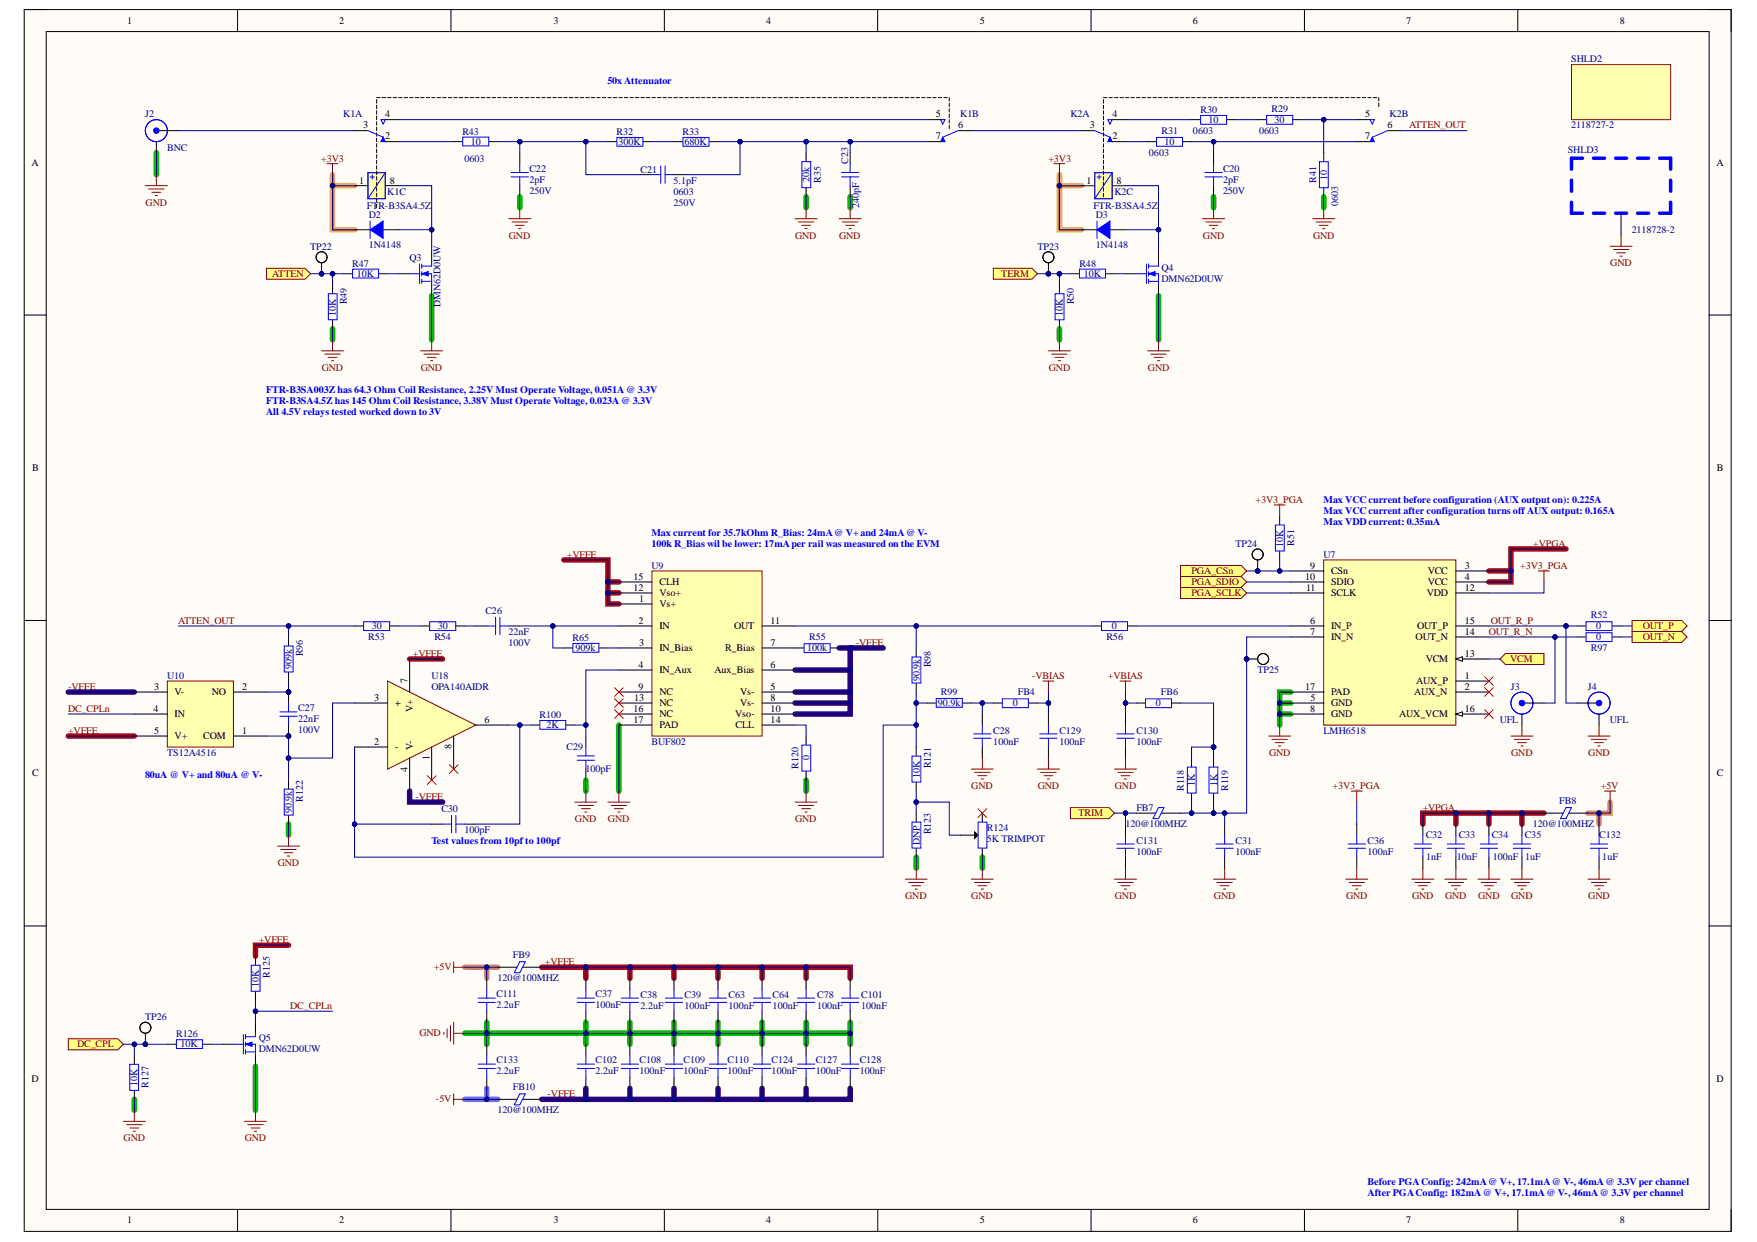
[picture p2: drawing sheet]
<svg xmlns="http://www.w3.org/2000/svg" width="297mm" height="210mm" viewBox="0 0 297 210" stroke-linecap="round" stroke-linejoin="round" font-family="sans-serif">
<defs><g id="words">
<g font-size="1.7">
<text x="21.5" y="4">1</text>
<text x="57.4" y="4">2</text>
<text x="93.6" y="4">3</text>
<text x="129.5" y="4">4</text>
<text x="165.6" y="4">5</text>
<text x="201.7" y="4">6</text>
<text x="237.7" y="4">7</text>
<text x="273.8" y="4">8</text>
<text x="61.4" y="21.7">3</text>
<text x="65.1" y="23.6">2</text>
<text x="65.1" y="19.9">4</text>
<text x="158.2" y="19.9">5</text>
<text x="158.2" y="23.6">7</text>
<text x="162" y="21.7">6</text>
<text x="184.3" y="21.7">3</text>
<text x="188.1" y="23.6">2</text>
<text x="188.1" y="19.9">4</text>
<text x="230.8" y="19.9">5</text>
<text x="230.8" y="23.6">7</text>
<text x="234.6" y="21.7">6</text>
<text x="5.3" y="28">A</text>
<text x="290.2" y="28">A</text>
<text x="60.7" y="31">1</text>
<text x="65.9" y="31">8</text>
<text x="183.7" y="31">1</text>
<text x="188.7" y="31">8</text>
<text x="5.4" y="79.6">B</text>
<text x="290.3" y="79.6">B</text>
<text x="107.1" y="99.8">12</text>
<text x="107.1" y="98">15</text>
<text x="108" y="101.7">1</text>
<text x="111.5" y="100.8">Vso+</text>
<text x="111.5" y="98.9">CLH</text>
<text x="220.6" y="98">10</text>
<text x="220.8" y="99.8">11</text>
<text x="221.5" y="96.1">9</text>
<text x="225" y="97">CSn</text>
<text x="225" y="98.9">SDIO</text>
<text x="225" y="100.8">SCLK</text>
<text x="241.2" y="100.8">VDD</text>
<text x="241.4" y="97">VCC</text>
<text x="241.4" y="98.9">VCC</text>
<text x="247.6" y="99.8">12</text>
<text x="247.6" y="96.1">3</text>
<text x="247.6" y="98">4</text>
<text x="107.9" y="105.4">2</text>
<text x="111.5" y="102.6">Vs+</text>
<text x="111.5" y="106.3">IN</text>
<text x="124.1" y="106.3">OUT</text>
<text x="130.3" y="105.4">11</text>
<text x="221.5" y="105.4">6</text>
<text x="221.5" y="107.3">7</text>
<text x="225" y="106.3">IN_P</text>
<text x="239.6" y="106.3">OUT_P</text>
<text x="247.6" y="107.3">14</text>
<text x="247.6" y="105.4">15</text>
<text x="107.9" y="112.8">4</text>
<text x="108" y="109.1">3</text>
<text x="111.5" y="110.1">IN_Bias</text>
<text x="111.5" y="113.8">IN_Aux</text>
<text x="120.8" y="113.8">Aux_Bias</text>
<text x="122.6" y="110.1">R_Bias</text>
<text x="130.3" y="112.8">6</text>
<text x="130.3" y="109.1">7</text>
<text x="225" y="108.2">IN_N</text>
<text x="239.3" y="108.2">OUT_N</text>
<text x="241" y="111.9">VCM</text>
<text x="247.6" y="111">13</text>
<text x="26.1" y="116.6">3</text>
<text x="29.5" y="117.5">V-</text>
<text x="35.8" y="117.5">NO</text>
<text x="40.9" y="116.6">2</text>
<text x="63.3" y="118.4">3</text>
<text x="66.8" y="119.4">+</text>
<text x="68.9" y="115.5" transform="rotate(-90 68.9 115.5)">7</text>
<text x="107.2" y="118.4">13</text>
<text x="107.9" y="116.6">9</text>
<text x="111.5" y="117.5">NC</text>
<text x="111.5" y="119.4">NC</text>
<text x="125.1" y="117.5">Vs-</text>
<text x="125.1" y="119.4">Vs-</text>
<text x="130.3" y="116.6">5</text>
<text x="130.3" y="118.4">8</text>
<text x="220.6" y="116.6">17</text>
<text x="221.6" y="118.4">5</text>
<text x="225" y="119.4">GND</text>
<text x="225" y="117.5">PAD</text>
<text x="239.1" y="117.5">AUX_N</text>
<text x="239.4" y="115.6">AUX_P</text>
<text x="247.6" y="114.7">1</text>
<text x="247.6" y="116.6">2</text>
<text x="26" y="120.3">4</text>
<text x="26.1" y="124">5</text>
<text x="29.5" y="124.9">V+</text>
<text x="29.5" y="121.2">IN</text>
<text x="34.3" y="124.9">COM</text>
<text x="40.9" y="124">1</text>
<text x="63.3" y="125.9">2</text>
<text x="69.8" y="120.4" transform="rotate(-90 69.8 120.4)">V+</text>
<text x="81.9" y="122.1">6</text>
<text x="107.1" y="120.3">16</text>
<text x="107.1" y="122.1">17</text>
<text x="111.5" y="121.2">NC</text>
<text x="111.5" y="123.1">PAD</text>
<text x="124.3" y="121.2">Vso-</text>
<text x="124.4" y="123.1">CLL</text>
<text x="130.3" y="120.3">10</text>
<text x="130.3" y="122.1">14</text>
<text x="221.5" y="120.3">8</text>
<text x="225" y="121.2">GND</text>
<text x="236.5" y="121.2">AUX_VCM</text>
<text x="247.6" y="120.3">16</text>
<text x="5.4" y="131.2">C</text>
<text x="66.8" y="126.8">-</text>
<text x="68.9" y="130.4" transform="rotate(-90 68.9 130.4)">4</text>
<text x="69.8" y="126.8" transform="rotate(-90 69.8 126.8)">V-</text>
<text x="72.6" y="128.4" transform="rotate(-90 72.6 128.4)">1</text>
<text x="76.3" y="126.6" transform="rotate(-90 76.3 126.6)">8</text>
<text x="290.3" y="131.2">C</text>
<text x="5.3" y="182.8">D</text>
<text x="290.2" y="182.8">D</text>
<text x="21.5" y="206.8">1</text>
<text x="57.4" y="206.8">2</text>
<text x="93.6" y="206.8">3</text>
<text x="129.5" y="206.8">4</text>
<text x="165.6" y="206.8">5</text>
<text x="201.7" y="206.8">6</text>
<text x="237.7" y="206.8">7</text>
<text x="273.8" y="206.8">8</text>
</g>
<g font-size="1.7" fill="#000080">
<text x="265.6" y="10.6">SHLD2</text>
<text x="24.5" y="19.9">J2</text>
<text x="58" y="19.9">K1A</text>
<text x="78.2" y="22.8">R43</text>
<text x="104.2" y="22.8">R32</text>
<text x="115.4" y="22.8">R33</text>
<text x="162.3" y="19.9">K1B</text>
<text x="181" y="19.9">K2A</text>
<text x="196.4" y="22.6">R31</text>
<text x="201.7" y="22.6">0603</text>
<text x="203" y="19.1">R30</text>
<text x="204.3" y="20.8">10</text>
<text x="212.9" y="22.6">0603</text>
<text x="215" y="18.9">R29</text>
<text x="215.5" y="20.8">30</text>
<text x="234.9" y="19.9">K2B</text>
<text x="265.6" y="21.7">2118727-2</text>
<text x="28.3" y="25.4">BNC</text>
<text x="78.5" y="27.3">0603</text>
<text x="79.6" y="24.5">10</text>
<text x="89.5" y="29">C22</text>
<text x="104.6" y="24.5">300K</text>
<text x="108.3" y="29.2">C21</text>
<text x="115.7" y="24.5">680K</text>
<text x="143.4" y="27.6" transform="rotate(-90 143.4 27.6)">C23</text>
<text x="194.2" y="26.4">0603</text>
<text x="196.9" y="24.5">10</text>
<text x="206.8" y="29">C20</text>
<text x="265.1" y="25.8">SHLD3</text>
<text x="62" y="35.2">FTR-B3SA4.5Z</text>
<text x="65.5" y="32.9">K1C</text>
<text x="89.5" y="32.7">250V</text>
<text x="89.5" y="30.8">2pF</text>
<text x="113.9" y="32.9">0603</text>
<text x="113.9" y="34.7">250V</text>
<text x="113.9" y="31">5.1pF</text>
<text x="136.9" y="30.8" transform="rotate(-90 136.9 30.8)">20k</text>
<text x="138.7" y="30.8" transform="rotate(-90 138.7 30.8)">R35</text>
<text x="145.3" y="35.1" transform="rotate(-90 145.3 35.1)">240pF</text>
<text x="184.9" y="35.2">FTR-B3SA4.5Z</text>
<text x="188.4" y="32.9">K2C</text>
<text x="206.8" y="32.7">250V</text>
<text x="206.8" y="30.8">2pF</text>
<text x="222.5" y="30.8" transform="rotate(-90 222.5 30.8)">R41</text>
<text x="224.4" y="30.3" transform="rotate(-90 224.4 30.3)">10</text>
<text x="226.2" y="34.8" transform="rotate(-90 226.2 34.8)">0603</text>
<text x="62.3" y="36.8">D2</text>
<text x="62.3" y="41.9">1N4148</text>
<text x="185.3" y="36.8">D3</text>
<text x="185.3" y="41.9">1N4148</text>
<text x="275.9" y="39.4">2118728-2</text>
<text x="52.5" y="42.2">TP22</text>
<text x="59.6" y="45.1">R47</text>
<text x="60.3" y="46.8">10K</text>
<text x="69.2" y="44">Q3</text>
<text x="175.4" y="42.2">TP23</text>
<text x="182.5" y="45.1">R48</text>
<text x="183.2" y="46.8">10K</text>
<text x="196.4" y="45.7">Q4</text>
<text x="196.4" y="47.6">DMN62D0UW</text>
<text x="56.8" y="53.3" transform="rotate(-90 56.8 53.3)">10K</text>
<text x="58.6" y="51.4" transform="rotate(-90 58.6 51.4)">R49</text>
<text x="74.4" y="51.8" transform="rotate(-90 74.4 51.8)">DMN62D0UW</text>
<text x="179.7" y="53.3" transform="rotate(-90 179.7 53.3)">10K</text>
<text x="181.6" y="51.4" transform="rotate(-90 181.6 51.4)">R50</text>
<text x="208.9" y="92.4">TP24</text>
<text x="216.9" y="92.4" transform="rotate(-90 216.9 92.4)">10K</text>
<text x="218.8" y="92.2" transform="rotate(-90 218.8 92.2)">R51</text>
<text x="223.8" y="94.2">U7</text>
<text x="110.1" y="96.1">U9</text>
<text x="62.9" y="106.3">30</text>
<text x="74" y="106.3">30</text>
<text x="82.1" y="103.7">C26</text>
<text x="86" y="107.3">22nF</text>
<text x="188" y="106.3">0</text>
<text x="268.9" y="104.5">R52</text>
<text x="269.9" y="106.3">0</text>
<text x="49.3" y="113.1" transform="rotate(-90 49.3 113.1)">909k</text>
<text x="51.2" y="110.9" transform="rotate(-90 51.2 110.9)">R96</text>
<text x="62.3" y="108.2">R53</text>
<text x="73.4" y="108.2">R54</text>
<text x="86" y="109.1">100V</text>
<text x="96.8" y="108.4">R65</text>
<text x="97.3" y="110.1">909k</text>
<text x="136.5" y="110.1">100k</text>
<text x="136.8" y="108.2">R55</text>
<text x="157.4" y="112.8" transform="rotate(-90 157.4 112.8)">R98</text>
<text x="187" y="108.2">R56</text>
<text x="212.6" y="113.8">TP25</text>
<text x="268.9" y="110.1">R97</text>
<text x="269.9" y="108.2">0</text>
<text x="28.3" y="114.7">U10</text>
<text x="72.9" y="114.7">U18</text>
<text x="72.9" y="116.6">OPA140AIDR</text>
<text x="155.5" y="115.1" transform="rotate(-90 155.5 115.1)">90.9k</text>
<text x="158.5" y="119.4">90.9k</text>
<text x="159" y="117.5">R99</text>
<text x="171.2" y="119.4">0</text>
<text x="172.1" y="117.5">FB4</text>
<text x="195.4" y="119.4">0</text>
<text x="196.3" y="117.5">FB6</text>
<text x="255.4" y="116.6">J3</text>
<text x="268.4" y="116.6">J4</text>
<text x="50.4" y="123.8">100V</text>
<text x="50.4" y="120.1">C27</text>
<text x="50.4" y="122">22nF</text>
<text x="91.2" y="121.4">R100</text>
<text x="92.4" y="123.1">2K</text>
<text x="110.1" y="125.9">BUF802</text>
<text x="167.9" y="124">C28</text>
<text x="167.9" y="125.9">100nF</text>
<text x="179.1" y="124">C129</text>
<text x="179.1" y="125.9">100nF</text>
<text x="192.1" y="124">C130</text>
<text x="192.1" y="125.9">100nF</text>
<text x="223.8" y="124">LMH6518</text>
<text x="253.5" y="122.1">UFL</text>
<text x="272.2" y="122.1">UFL</text>
<text x="28.3" y="127.7">TS12A4516</text>
<text x="95.8" y="126.8">C29</text>
<text x="99" y="130.5">100pF</text>
<text x="135" y="129.9" transform="rotate(-90 135 129.9)">R120</text>
<text x="136.9" y="128.5" transform="rotate(-90 136.9 128.5)">0</text>
<text x="155.5" y="131.4" transform="rotate(-90 155.5 131.4)">10K</text>
<text x="157.4" y="129.8" transform="rotate(-90 157.4 129.8)">R121</text>
<text x="49.3" y="137.4" transform="rotate(-90 49.3 137.4)">90.9k</text>
<text x="51.2" y="135.5" transform="rotate(-90 51.2 135.5)">R122</text>
<text x="74.6" y="137.3">C30</text>
<text x="192.1" y="137">FB7</text>
<text x="200.2" y="133.6" transform="rotate(-90 200.2 133.6)">R118</text>
<text x="202" y="132.9" transform="rotate(-90 202 132.9)">1K</text>
<text x="205.7" y="132.9" transform="rotate(-90 205.7 132.9)">1K</text>
<text x="207.6" y="133.6" transform="rotate(-90 207.6 133.6)">R119</text>
<text x="263.6" y="135.9">FB8</text>
<text x="78.5" y="140.7">100pF</text>
<text x="155.5" y="142.8" transform="rotate(-90 155.5 142.8)">DNP</text>
<text x="157.4" y="141" transform="rotate(-90 157.4 141)">R123</text>
<text x="166.8" y="140.4">R124</text>
<text x="166.8" y="142.3">5K TRIMPOT</text>
<text x="190.3" y="139.8">120@100MHZ</text>
<text x="192.1" y="142.6">C131</text>
<text x="208.9" y="142.6">C31</text>
<text x="231.2" y="142.6">C36</text>
<text x="241" y="141.7">C32</text>
<text x="246.6" y="141.7">C33</text>
<text x="252.2" y="141.7">C34</text>
<text x="257.8" y="141.7">C35</text>
<text x="259.1" y="139.8">120@100MHZ</text>
<text x="270.4" y="141.7">C132</text>
<text x="192.1" y="144.5">100nF</text>
<text x="208.9" y="144.5">100nF</text>
<text x="231.2" y="144.5">100nF</text>
<text x="241.1" y="145.4">1nF</text>
<text x="246.3" y="145.4">10nF</text>
<text x="252.4" y="145.4">100nF 1uF</text>
<text x="270.9" y="145.4">1uF</text>
<text x="86.7" y="162">FB9</text>
<text x="43.7" y="166.8" transform="rotate(-90 43.7 166.8)">10K</text>
<text x="45.6" y="165.3" transform="rotate(-90 45.6 165.3)">R125</text>
<text x="84.1" y="165.8">120@100MHZ</text>
<text x="24.5" y="172.4">TP26</text>
<text x="83.9" y="168.5">C111</text>
<text x="83.9" y="170.3">2.2uF</text>
<text x="100.7" y="168.5">C37</text>
<text x="100.7" y="170.3">100nF</text>
<text x="108.3" y="168.6">C38</text>
<text x="108.3" y="170.5">2.2uF</text>
<text x="115.7" y="168.6">C39</text>
<text x="115.7" y="170.5">100nF</text>
<text x="123.2" y="168.6">C63</text>
<text x="123.2" y="170.5">100nF</text>
<text x="130.6" y="168.6">C64</text>
<text x="130.6" y="170.5">100nF</text>
<text x="138.2" y="168.6">C78</text>
<text x="138.2" y="170.5">100nF</text>
<text x="145.6" y="168.6">C101</text>
<text x="145.6" y="170.5">100nF</text>
<text x="29.8" y="175.3">R126</text>
<text x="30.5" y="177">10K</text>
<text x="43.7" y="175.9">Q5</text>
<text x="43.7" y="177.8">DMN62D0UW</text>
<text x="83.9" y="179.6">C133</text>
<text x="100.7" y="179.6">C102</text>
<text x="108.1" y="179.6">C108</text>
<text x="115.6" y="179.6">C109</text>
<text x="123" y="179.6">C110</text>
<text x="130.5" y="179.6">C124</text>
<text x="137.9" y="179.6">C127</text>
<text x="145.3" y="179.6">C128</text>
<text x="23.3" y="183.5" transform="rotate(-90 23.3 183.5)">10K</text>
<text x="25.1" y="183.8" transform="rotate(-90 25.1 183.8)">R127</text>
<text x="83.9" y="181.5">2.2uF</text>
<text x="86.7" y="184.3">FB10</text>
<text x="100.7" y="181.5">2.2uF</text>
<text x="108.1" y="181.5">100nF</text>
<text x="115.6" y="181.5">100nF</text>
<text x="123" y="181.5">100nF</text>
<text x="130.5" y="181.5">100nF</text>
<text x="137.9" y="181.5">100nF</text>
<text x="145.3" y="181.5">100nF</text>
<text x="84.1" y="188.2">120@100MHZ</text>
</g>
<g font-size="1.7" fill="#00f">
<text x="102.7" y="14.3">50x Attenuator</text>
<text x="45" y="66.3">FTR-B3SA003Z has 64.3 Ohm Coil Resistance, 2.25V Must Operate Voltage, 0.051A @ 3.3V</text>
<text x="45" y="68.2">FTR-B3SA4.5Z has 145 Ohm Coil Resistance, 3.38V Must Operate Voltage, 0.023A @ 3.3V</text>
<text x="45" y="70.1">All 4.5V relays tested worked down to 3V</text>
<text x="223.8" y="84.9">Max VCC current before configuration (AUX output on): 0.225A</text>
<text x="223.8" y="86.8">Max VCC current after configuration turns offAUX output: 0.165A</text>
<text x="223.8" y="88.7">Max VDD current: 0.35mA</text>
<text x="110.1" y="90.5">Max current for 35.7kOhm R_Bias: 24mA@ V+ and 24mA@ V-</text>
<text x="110.1" y="92.4">100k R_Bias wil be lower: 17mAper rail was measured on the EVM</text>
<text x="24.5" y="131.4">80uA @ V+ and 80uA @ V-</text>
<text x="72.9" y="142.6">Test values from 10pfto 100pf</text>
<text x="231.2" y="200.2">Before PGAConfig: 242mA@ V+, 17.1mA@ V-, 46mA@ 3.3V per channel</text>
<text x="231.2" y="202.1">After PGAConfig: 182mA@ V+, 17.1mA@ V-, 46mA@ 3.3V per channel</text>
</g>
<g font-size="1.7" fill="#800000">
<text x="238.2" y="21.7">ATTEN_OUT</text>
<text x="54.3" y="27.3">+3V3</text>
<text x="177.2" y="27.3">+3V3</text>
<text x="24.6" y="34.7">GND</text>
<text x="86" y="40.3">GND</text>
<text x="134.4" y="40.3">GND</text>
<text x="141.9" y="40.3">GND</text>
<text x="203.4" y="40.3">GND</text>
<text x="222" y="40.3">GND</text>
<text x="46" y="46.8">ATTEN</text>
<text x="169.3" y="46.8">TERM</text>
<text x="272.2" y="45">GND</text>
<text x="54.4" y="62.6">GND</text>
<text x="71.1" y="62.6">GND</text>
<text x="177.3" y="62.6">GND</text>
<text x="194.1" y="62.6">GND</text>
<text x="212.3" y="84.9">+3V3_PGA</text>
<text x="95.9" y="94.2">+VFFE</text>
<text x="259.2" y="92.4">+VPGA</text>
<text x="201.4" y="97">PGA_CSn</text>
<text x="201.4" y="100.8">PGA_SCLK</text>
<text x="201.4" y="98.9">PGA_SDIO</text>
<text x="257" y="96.1">+3V3_PGA</text>
<text x="30.1" y="105.4">ATTEN_OUT</text>
<text x="251.7" y="107.3">OUT_R_N</text>
<text x="252" y="105.4">OUT_R_P</text>
<text x="277.7" y="106.3">OUT_P</text>
<text x="69.8" y="111">+VFFE</text>
<text x="144.7" y="109.1">-VFFE</text>
<text x="255.3" y="111.9">VCM</text>
<text x="277.7" y="108.2">OUT_N</text>
<text x="11.5" y="116.6">-VFFE</text>
<text x="174.4" y="114.7">-VBIAS</text>
<text x="187.3" y="114.7">+VBIAS</text>
<text x="11.5" y="120.3">DC_CPLn</text>
<text x="11.5" y="124">+VFFE</text>
<text x="214.5" y="127.7">GND</text>
<text x="255.5" y="127.7">GND</text>
<text x="268.5" y="127.7">GND</text>
<text x="70.2" y="135.2">-VFFE</text>
<text x="164.2" y="133.3">GND</text>
<text x="175.5" y="133.3">GND</text>
<text x="182.3" y="137.9">TRIM</text>
<text x="188.5" y="133.3">GND</text>
<text x="225.3" y="133.3">+3V3_PGA</text>
<text x="240.5" y="137">+VPGA</text>
<text x="270.6" y="133.3">+5V</text>
<text x="97.2" y="138.9">GND</text>
<text x="102.8" y="138.9">GND</text>
<text x="134.4" y="138.9">GND</text>
<text x="47" y="146.3">GND</text>
<text x="153" y="151.9">GND</text>
<text x="164.2" y="151.9">GND</text>
<text x="188.5" y="151.9">GND</text>
<text x="205.2" y="151.9">GND</text>
<text x="227.6" y="151.9">GND</text>
<text x="238.7" y="151.9">GND</text>
<text x="244.3" y="151.9">GND</text>
<text x="249.9" y="151.9">GND</text>
<text x="255.5" y="151.9">GND</text>
<text x="268.5" y="151.9">GND</text>
<text x="43.7" y="159.3">+VFFE</text>
<text x="73.3" y="164">+5V</text>
<text x="92.1" y="163.1">+VFFE</text>
<text x="49.1" y="170.5">DC_CPLn</text>
<text x="13" y="177">DC_CPL</text>
<text x="70.9" y="175.1">GND</text>
<text x="92.6" y="185.4">-VFFE</text>
<text x="73.7" y="186.3">-5V</text>
<text x="20.9" y="192.8">GND</text>
<text x="41.4" y="192.8">GND</text>
</g>
</g></defs>
<path d="M4.1 1.6h288.6v206.5h-288.6z" fill-rule="evenodd" fill="#fffcf8"/>
<path d="M4.1 1.6h288.6v206.5h-288.6z" fill="none" stroke="#000" stroke-width=".17"/>
<path d="M7.8 5.3h281.2v199.1h-281.2z" fill-rule="evenodd" fill="#fffcf8"/>
<g fill="none" stroke="#000" stroke-width=".17">
<path d="M4.1 1.6h3.7M7.8 5.3h281.2v199.1h-281.2zM40.2 1.6v3.7M76.2 1.6v3.7M112.3 1.6v3.7M148.4 1.6v3.7M184.5 1.6v3.7M220.5 1.6v3.7M256.6 1.6v3.7M289 1.6h3.7v3.7M274.1 36v3.8M4.1 53.2h3.7"/>
<path d="M289 53.2h3.7M4.1 104.9h3.7M289 104.9h3.7M4.1 156.5h3.7M289 156.5h3.7M40.2 204.4v3.7M76.2 204.4v3.7M112.3 204.4v3.7M148.4 204.4v3.7M184.5 204.4v3.7M220.5 204.4v3.7M256.6 204.4v3.7"/>
<path d="M292.7 204.4v3.7"/>
</g>
<g fill="none" stroke="#00be00" stroke-width=".93">
<path d="M26.4 25.8v3.7M87.9 33.2v1.9M136.3 33.2v1.9M143.7 33.2v1.9M205.2 33.2v1.9M223.8 33.2v1.9M56.2 55.6v1.8M73 50v7.4M179.1 55.6v1.8M195.9 50v7.4M216.3 118.8h1.9M218.2 117h-1.9v3.7h1.9"/>
<path d="M48.8 139.3v1.8M99 131.8v1.9M104.6 122.5v11.2M136.3 131.8v1.9M216.3 120.7v1.8M154.9 144.9v1.8M166.1 144.9v1.8M82.3 172.8v3.7M99 172.8v3.7M106.5 172.8v3.7M113.9 172.8v3.7M121.4 172.8v3.7"/>
<path d="M128.8 172.8v3.7M136.3 172.8v3.7M143.7 172.8v1.8h-65.1M143.7 174.6v1.9M22.7 185.8v1.9M43.2 180.2v7.5"/>
</g>
<g fill="none" stroke="#a50021" stroke-width=".93">
<path d="M95.3 94.6h7.5v7.5h1.8M102.8 98.4h1.8M251.7 96.5h3.7M264.7 92.8h-9.3v5.6h-3.7M69.3 111.4h5.5M102.8 100.2h1.8M11.5 124.4h11.2M246.1 137.4h-5.6v1.9M251.7 137.4h-5.6v1.9M257.3 137.4v1.9M261 137.4h-9.3v1.9M48.8 159.7h-5.6v1.9"/>
<path d="M91.6 163.5h7.4M99 163.5h7.5v1.8M99 163.5v1.8M106.5 163.5h29.8v1.8M113.9 163.5v1.8M121.4 163.5v1.8M128.8 163.5v1.8M136.3 163.5h7.4v1.8"/>
</g>
<path d="M56.2 31.4v7.4h3.7M56.2 29.5v1.9h3.7M179.1 31.4v7.4h3.7M179.1 29.5v1.9h3.7" fill="none" stroke="#f90" stroke-width=".93"/>
<g fill="none" stroke="#30007b" stroke-width=".93">
<path d="M11.5 117h11.2M134.4 113.2h9.3v3.8h-9.3M134.4 118.8h9.3v1.9h-9.3M141.9 109.5h1.8v3.7M143.7 117v1.8M143.7 109.5h5.6M69.3 133.7v1.9h5.5M91.6 185.8h7.4M99 183.9v1.9M106.5 183.9v1.9M113.9 183.9v1.9M121.4 183.9v1.9"/>
<path d="M128.8 183.9v1.9M136.3 183.9v1.9h-37.3M143.7 183.9v1.9h-7.4"/>
</g>
<path d="M270.3 137.4v1.9M272.2 135.6v1.8h-3.7M78.6 163.5h5.6M82.3 163.5v1.8" fill="none" stroke="#ff6e6e" stroke-width=".93"/>
<path d="M78.6 185.8h5.6M82.3 183.9v1.9" fill="none" stroke="#6e6eff" stroke-width=".93"/>
<path d="M265.7 30.5v1.8M265.7 34.2v1.8h1.8M267.5 26.7h-1.8v1.9M269.4 36h1.9M269.4 26.7h1.9M273.1 36h1.9M273.1 26.7h1.9M276.9 36h1.8M276.9 26.7h1.8M280.6 26.7h1.8v1.9M282.4 34.2v1.8h-1.8M282.4 30.5v1.8" fill="none" stroke="#00f" stroke-width=".59"/>
<path d="M274.1 39.8v1.8M272.2 41.6h3.7M272.7 42.2h2.7M273.3 42.7h1.5M273.9 43.3h.3" fill="none" stroke="#800000" stroke-width=".17"/>
<path d="M265.7 10.9h16.7v9.3h-16.7z" fill-rule="evenodd" fill="#ffffb0"/>
<path d="M265.7 10.9h16.7v9.3h-16.7zM24.6 31.4h3.7M25.1 31.9h2.6M25.7 32.5h1.5M26.2 33.1h.4M26.4 29.5v1.9" fill="none" stroke="#800000" stroke-width=".17"/>
<circle cx="26.4" cy="22.1" r="1.86" fill="none" stroke="#00f" stroke-width=".17"/>
<path d="M26.4 22.1h3.8M26.4 23.9v1.9" fill="none" stroke="#000" stroke-width=".17"/>
<circle cx="26.4" cy="22.1" r=".47" fill="#00f"/>
<g fill="none" stroke="#00f" stroke-width=".17">
<path d="M186.2 105.1h4.4v1.5h-4.4z"/>
<circle cx="26.4" cy="22.1" r=".47"/>
</g>
<path d="M184.7 105.8h1.5M190.7 105.8h1.4" fill="none" stroke="#000" stroke-width=".17"/>
<path d="M223.8 94.6h22.3v27.9h-22.3z" fill-rule="evenodd" fill="#ffffb0"/>
<path d="M223.8 94.6h22.3v27.9h-22.3z" fill="none" stroke="#800000" stroke-width=".17"/>
<path d="M218.2 96.5h5.6M218.2 98.4h5.6M218.2 100.2h5.6M246.1 100.2h5.6M246.1 111.4h5.6" fill="none" stroke="#000" stroke-width=".17"/>
<path d="M246.1 111.4l1.1-.4v.8z" fill="#f8fcff"/>
<path d="M246.1 111.4l1.1-.4v.8zM246.1 107.7h5.6M246.1 105.8h5.6M246.1 115.1h5.6M246.1 117h5.6M246.1 120.7h5.6" fill="none" stroke="#000" stroke-width=".17"/>
<path d="M246.1 120.7l1.1-.4v.8z" fill="#f8fcff"/>
<path d="M246.1 96.5h5.6M246.1 98.4h5.6M218.2 118.8h5.6M218.2 117h5.6M218.2 105.8h5.6M218.2 107.7h5.6M218.2 120.7h5.6M246.1 120.7l1.1-.4v.8z" fill="none" stroke="#000" stroke-width=".17"/>
<path d="M199.6 95.6h10.2l1 .9-1 .9h-10.2z" fill-rule="evenodd" fill="#ffff80"/>
<path d="M199.6 95.6h10.2l1 .9-1 .9h-10.2z" fill="none" stroke="#800000" stroke-width=".17"/>
<path d="M216.3 87.2v1.5M216.3 93.2v1.4" fill="none" stroke="#000" stroke-width=".17"/>
<path d="M215.6 88.7h1.5v4.4h-1.5z" fill="none" stroke="#00f" stroke-width=".17"/>
<path d="M199.6 99.3h10.2l1 .9-1 .9h-10.2z" fill-rule="evenodd" fill="#ffff80"/>
<path d="M199.6 99.3h10.2l1 .9-1 .9h-10.2z" fill="none" stroke="#800000" stroke-width=".17"/>
<path d="M199.6 97.4h10.2l1 1-1 .9h-10.2z" fill-rule="evenodd" fill="#ffff80"/>
<path d="M199.6 97.4h10.2l1 1-1 .9h-10.2zM214.5 124.4h3.7M215 125h2.6M215.6 125.5h1.5M216.2 126.1h.3M216.3 122.5v1.9" fill="none" stroke="#800000" stroke-width=".17"/>
<path d="M253.6 111.4l.9-1h6.5v1.9h-6.5z" fill-rule="evenodd" fill="#ffff80"/>
<path d="M253.6 111.4l.9-1h6.5v1.9h-6.5z" fill="none" stroke="#800000" stroke-width=".17"/>
<path d="M251 114.4l1.5 1.4M251 116.2l1.5 1.5M251 119.9l1.5 1.5M252.5 114.4l-1.5 1.4M252.5 116.2l-1.5 1.5M252.5 119.9l-1.5 1.5" fill="none" stroke="#f00" stroke-width=".17"/>
<path d="M275.9 104.9h8.4l.9 .9-.9 .9h-8.4z" fill-rule="evenodd" fill="#ffff80"/>
<path d="M275.9 104.9h8.4l.9 .9-.9 .9h-8.4z" fill="none" stroke="#800000" stroke-width=".17"/>
<path d="M275.9 106.7h8.4l.9 1-.9 .9h-8.4z" fill-rule="evenodd" fill="#ffff80"/>
<path d="M275.9 106.7h8.4l.9 1-.9 .9h-8.4z" fill="none" stroke="#800000" stroke-width=".17"/>
<path d="M257.3 118.8h3.7M266.6 105.8h1.5M266.6 107.7h1.5M272.6 105.8h1.5M272.6 107.7h1.5M257.3 120.7v1.8" fill="none" stroke="#000" stroke-width=".17"/>
<g fill="none" stroke="#00f" stroke-width=".17">
<path d="M268.1 105.1h4.4v1.5h-4.4zM268.1 106.9h4.4v1.5h-4.4z"/>
<circle cx="257.3" cy="118.8" r="1.86"/>
</g>
<circle cx="257.3" cy="118.8" r=".46" fill="#00f"/>
<g fill="none" stroke="#00f" stroke-width=".17">
<circle cx="257.3" cy="118.8" r=".46"/>
<circle cx="270.3" cy="118.8" r="1.86"/>
</g>
<path d="M255.4 124.4h3.8M256 125h2.6M256.6 125.5h1.5M257.1 126.1h.4M257.3 122.5v1.9" fill="none" stroke="#800000" stroke-width=".17"/>
<path d="M266.6 118.8h3.7M270.3 120.7v1.8" fill="none" stroke="#000" stroke-width=".17"/>
<circle cx="270.3" cy="118.8" r=".47" fill="#00f"/>
<circle cx="270.3" cy="118.8" r=".47" fill="none" stroke="#00f" stroke-width=".17"/>
<path d="M268.5 124.4h3.7M269 125h2.6M269.6 125.5h1.5M270.1 126.1h.4M270.3 122.5v1.9" fill="none" stroke="#800000" stroke-width=".17"/>
<circle cx="212.6" cy="96.5" r=".37" fill="#000080"/>
<circle cx="212.6" cy="96.5" r=".37" fill="none" stroke="#000080" stroke-width=".17"/>
<path d="M212.6 94.6v1.9" fill="none" stroke="#000" stroke-width=".17"/>
<circle cx="212.6" cy="96.5" r=".37" fill="#000080"/>
<circle cx="212.6" cy="96.5" r=".37" fill="none" stroke="#000080" stroke-width=".17"/>
<g fill="none" stroke="#000" stroke-width=".17">
<path d="M201.4 128.1v1.5M201.4 134.1v1.5M205.2 128.1v1.5M205.2 134.1v1.5M229.4 139.3v1.8M240.5 139.3v1.8M246.1 139.3v1.8M251.7 139.3v1.8M257.3 139.3v1.8M229.4 144.9v1.8M240.5 144.9v1.8M246.1 144.9v1.8"/>
<path d="M251.7 144.9v1.8M257.3 144.9v1.8"/>
<circle cx="212.6" cy="93.7" r=".93"/>
</g>
<g fill="none" stroke="#00f" stroke-width=".17">
<path d="M200.7 129.6h1.5v4.4h-1.5zM204.4 129.6h1.5v4.4h-1.5zM227.9 143.4h2.9M227.9 142.6h2.9M229.4 141.1v1.5M229.4 143.4v1.5M239.1 143.4h2.9M239.1 142.6h2.9M240.5 141.1v1.5M240.5 143.4v1.5M244.7 143.4h2.9M244.7 142.6h2.9"/>
<path d="M246.1 141.1v1.5M246.1 143.4v1.5M250.2 143.4h3M250.2 142.6h3M251.7 141.1v1.5M251.7 143.4v1.5M255.8 143.4h3M255.8 142.6h3M257.3 141.1v1.5M257.3 143.4v1.5"/>
</g>
<g fill="none" stroke="#800000" stroke-width=".17">
<path d="M271.3 133.7h1.8M272.2 133.7v1.9M227.5 148.6h3.7M228.1 149.1h2.6M228.6 149.7h1.5M229.2 150.3h.4M229.4 146.7v1.9M238.7 148.6h3.7M239.2 149.1h2.6M239.8 149.7h1.5M240.4 150.3h.3M240.5 146.7v1.9"/>
<path d="M244.3 148.6h3.7M244.8 149.1h2.6M245.4 149.7h1.5M245.9 150.3h.4M246.1 146.7v1.9M249.9 148.6h3.7M250.4 149.1h2.6M251 149.7h1.5M251.5 150.3h.4M251.7 146.7v1.9M255.4 148.6h3.8M256 149.1h2.6"/>
<path d="M256.6 149.7h1.5M257.1 150.3h.4M257.3 146.7v1.9"/>
</g>
<path d="M181 136.5h6.5l.9 .9-.9 .9h-6.5z" fill-rule="evenodd" fill="#ffff80"/>
<path d="M181 136.5h6.5l.9 .9-.9 .9h-6.5z" fill="none" stroke="#800000" stroke-width=".17"/>
<circle cx="210.8" cy="111.4" r=".38" fill="#000080"/>
<circle cx="210.8" cy="111.4" r=".38" fill="none" stroke="#000080" stroke-width=".17"/>
<path d="M210.8 111.4h1.8" fill="none" stroke="#000" stroke-width=".17"/>
<circle cx="210.8" cy="111.4" r=".38" fill="#000080"/>
<circle cx="210.8" cy="111.4" r=".38" fill="none" stroke="#000080" stroke-width=".17"/>
<g fill="none" stroke="#000" stroke-width=".17">
<path d="M207 139.3v1.8M207 144.9v1.8"/>
<circle cx="213.5" cy="111.4" r=".93"/>
<circle cx="213.6" cy="111.4" r=".93"/>
</g>
<path d="M205.6 142.6h2.9M205.6 143.4h2.9M207 141.1v1.5M207 143.4v1.5" fill="none" stroke="#00f" stroke-width=".17"/>
<path d="M215.4 85.3h1.9M216.3 85.3v1.9M260.1 96.5h1.9M261 96.5v1.9M228.4 133.7h1.9M229.4 133.7v1.9M205.2 148.6h3.7M205.7 149.1h2.6M206.3 149.7h1.5M206.8 150.3h.4M207 146.7v1.9" fill="none" stroke="#800000" stroke-width=".17"/>
<path d="M62.2 29.2h2.9v4.4h-2.9z" fill-rule="evenodd" fill="#ffffb0"/>
<path d="M55.3 27.7h1.9M56.2 27.7v1.8M62.2 29.2h2.9v4.4h-2.9z" fill="none" stroke="#800000" stroke-width=".17"/>
<path d="M62.6 29.9h.7M62.9 29.6v.7M65.1 29.2l-2.9 4.4M65.1 29.2h-2.9v4.4M65.1 29.2v4.4h-2.9" fill="none" stroke="#00f" stroke-width=".17"/>
<path d="M59.9 31.4h2.2M59.9 38.8h2.8M64.6 38.8h2.8M65.2 31.4h2.2" fill="none" stroke="#000" stroke-width=".17"/>
<path d="M62.6 38.8l2.2-1.4v2.9z" fill="#00f"/>
<path d="M62.6 38.8l2.2-1.4v2.9zM62.6 37.4v2.9M69.3 46.3h1.6M70.9 44.6v3.3M71.3 45h1.7M71.3 46.3h1.7v1.8M71.3 47.5h1.7M71.3 44.6v.7M71.3 45.9v.7M71.3 47.2v.7" fill="none" stroke="#00f" stroke-width=".17"/>
<path d="M67.4 46.3h1.9M73 42.5v1.9M73 48.1v1.9" fill="none" stroke="#000" stroke-width=".17"/>
<path d="M71.3 46.3l1.1-.4v.7z" fill="#00f"/>
<path d="M55.5 49.6h1.5v4.4h-1.5zM71.3 46.3l1.1-.4v.7zM73 44.4v.6" fill="none" stroke="#00f" stroke-width=".17"/>
<path d="M54.4 59.3h3.7M54.9 59.8h2.6M56.2 57.4v1.9M71.1 59.3h3.7M71.7 59.8h2.6M73 57.4v1.9M55.5 60.4h1.5M56 61h.4M72.2 60.4h1.5M72.8 61h.4" fill="none" stroke="#800000" stroke-width=".17"/>
<path d="M56.2 48.1v1.5M56.2 54.1v1.5" fill="none" stroke="#000" stroke-width=".17"/>
<path d="M45 45.3h6.6l.9 1-.9 .9h-6.6z" fill-rule="evenodd" fill="#ffff80"/>
<path d="M134.4 37h3.7M135 37.5h2.6M135.5 38.1h1.5M136.1 38.6h.4M136.3 35.1v1.9M141.9 37h3.7M142.4 37.5h2.6M143 38.1h1.5M143.5 38.6h.4M143.7 35.1v1.9M45 45.3h6.6l.9 1-.9 .9h-6.6z" fill="none" stroke="#800000" stroke-width=".17"/>
<g fill="none" stroke="#000" stroke-width=".17">
<path d="M63.7 16.8v.6M63.7 17.8v.6M63.7 18.7v.6M63.7 19.6v.6M63.7 16.5h.6M64.6 16.5h.6M65.5 16.5h.6M66.5 16.5h.5M67.4 16.5h.6M68.3 16.5h.6M69.3 16.5h.5M70.2 16.5h.6"/>
<path d="M71.1 16.5h.6M72 16.5h.6M73 16.5h.6M73.9 16.5h.6M74.8 16.5h.6M75.8 16.5h.6M76.7 16.5h.6M77.6 16.5h.6M78.6 16.5h.5M79.5 16.5h.6M80.4 16.5h.6M81.4 16.5h.5"/>
<path d="M82.3 16.5h.6M83.2 16.5h.6M84.2 16.5h.5M85.1 16.5h.6M86 16.5h.6M86.9 16.5h.6M87.9 16.5h.6M88.8 16.5h.6M89.7 16.5h.6M90.7 16.5h.5M91.6 16.5h.6M92.5 16.5h.6"/>
<path d="M93.5 16.5h.5M94.4 16.5h.6M95.3 16.5h.6M96.3 16.5h.5M97.2 16.5h.6M98.1 16.5h.6M99 16.5h.6M100 16.5h.6M100.9 16.5h.6M101.8 16.5h.6M102.8 16.5h.5M103.7 16.5h.6"/>
<path d="M104.6 16.5h.6M105.6 16.5h.5M106.5 16.5h.6M107.4 16.5h.6M108.4 16.5h.5M109.3 16.5h.6M110.2 16.5h.6M111.1 16.5h.6M112.1 16.5h.6M113 16.5h.6M113.9 16.5h.6M114.9 16.5h.6"/>
<path d="M115.8 16.5h.6M116.7 16.5h.6M117.7 16.5h.5M118.6 16.5h.6M119.5 16.5h.6M120.5 16.5h.5M121.4 16.5h.6M122.3 16.5h.6M123.2 16.5h.6M124.2 16.5h.6M125.1 16.5h.6M126 16.5h.6"/>
<path d="M127 16.5h.6M127.9 16.5h.6M128.8 16.5h.6M129.8 16.5h.5M130.7 16.5h.6M131.6 16.5h.6M132.6 16.5h.5M133.5 16.5h.6M134.4 16.5h.6M135.3 16.5h.6M136.3 16.5h.6M137.2 16.5h.6"/>
<path d="M138.1 16.5h.6M139.1 16.5h.6M140 16.5h.6M140.9 16.5h.6M141.9 16.5h.5M142.8 16.5h.6M143.7 16.5h.6M144.7 16.5h.5M145.6 16.5h.6M146.5 16.5h.6M147.5 16.5h.5M148.4 16.5h.6"/>
<path d="M149.3 16.5h.6M150.2 16.5h.6M151.2 16.5h.6M152.1 16.5h.6M153 16.5h.6M154 16.5h.5M154.9 16.5h.6M155.8 16.5h.6M156.8 16.5h.5M157.7 16.5h.6M158.6 16.5h.6M159.6 16.5h.5"/>
<path d="M160.5 16.5v.6M160.5 17.4v.6M160.5 18.4v.5M160.5 19.3v.6M59.9 22.1h2.2M63.7 20.6v.6M63.7 21.5v.6M63.7 22.4v.6M63.7 23.4v.5M63.7 24.3v.6M63.7 25.2v.6M63.7 26.1v.6"/>
<path d="M63.7 27.1v.6M63.7 28v.6M63.7 28.9v.6M63.7 29.9v.5M63.7 30.8v.6M63.7 31.7v.6M63.7 32.7v.5M63.7 33.6v.6M63.7 34.5v.6M102.8 23.9h1.4M108.4 29.5h1.8M108.7 23.9h1.5"/>
<path d="M113.9 23.9h1.5M113.9 29.5h1.9M119.9 23.9h1.5M136.3 25.8v1.5M136.3 31.8v1.4M143.7 25.8v1.9M143.7 31.4v1.8M160.5 20.2v.6M160.5 21.2v.5"/>
</g>
<path d="M62.2 22.1l2.6 1.1M104.3 23.2h4.4v1.5h-4.4zM110.2 29.5h1.5M111.7 28.1v2.9M112.4 29.5h1.5M112.4 28.1v2.9M115.5 23.2h4.4v1.5h-4.4zM135.6 27.3h1.5v4.4h-1.5zM142.3 29.9h2.9M142.3 29.2h2.9M143.7 27.7v1.5M143.7 29.9v1.5" fill="none" stroke="#00f" stroke-width=".17"/>
<path d="M64.8 23.2l.3 .7h-.7z" fill="#00f"/>
<path d="M64.4 20.2h.7l-.3 .8zM64.8 23.2l.3 .7h-.7zM159 20.2h.8l-.4 .8zM162 22.1l-2.6 1.1" fill="none" stroke="#00f" stroke-width=".17"/>
<path d="M65.2 23.9h2.2M65.2 20.2h2.2M162 22.1h2.2" fill="none" stroke="#000" stroke-width=".17"/>
<path d="M159.4 23.2l.4 .7h-.8z" fill="#00f"/>
<path d="M159.4 23.2l.4 .7h-.8zM59.6 45.5h4.4v1.5h-4.4z" fill="none" stroke="#00f" stroke-width=".17"/>
<path d="M156.8 20.2h2.2M156.8 23.9h2.2M58.1 46.3h1.5M64.1 46.3h1.4" fill="none" stroke="#000" stroke-width=".17"/>
<circle cx="54.4" cy="46.3" r=".37" fill="#000080"/>
<circle cx="54.4" cy="46.3" r=".37" fill="none" stroke="#000080" stroke-width=".17"/>
<path d="M54.4 44.4v1.9" fill="none" stroke="#000" stroke-width=".17"/>
<circle cx="54.4" cy="46.3" r=".37" fill="#000080"/>
<circle cx="54.4" cy="46.3" r=".37" fill="none" stroke="#000080" stroke-width=".17"/>
<circle cx="54.4" cy="43.5" r=".93" fill="none" stroke="#000" stroke-width=".17"/>
<path d="M167.9 45.3h6.6l.9 1-.9 .9h-6.6z" fill-rule="evenodd" fill="#ffff80"/>
<path d="M203.3 37h3.7M203.9 37.5h2.6M204.4 38.1h1.5M205 38.6h.4M205.2 35.1v1.9M167.9 45.3h6.6l.9 1-.9 .9h-6.6z" fill="none" stroke="#800000" stroke-width=".17"/>
<path d="M205.2 25.8v1.9M205.2 31.4v1.8" fill="none" stroke="#000" stroke-width=".17"/>
<path d="M203.7 29.2h2.9M203.7 29.9h2.9M205.2 27.7v1.5M205.2 29.9v1.5" fill="none" stroke="#00f" stroke-width=".17"/>
<path d="M185.1 29.2h2.9v4.4h-2.9z" fill-rule="evenodd" fill="#ffffb0"/>
<path d="M178.2 27.7h1.8M179.1 27.7v1.8M185.1 29.2h2.9v4.4h-2.9z" fill="none" stroke="#800000" stroke-width=".17"/>
<path d="M185.5 29.9h.7M185.8 29.6v.7M188 29.2l-2.9 4.4M188 29.2h-2.9v4.4M188 29.2v4.4h-2.9" fill="none" stroke="#00f" stroke-width=".17"/>
<path d="M182.8 31.4h2.2M182.8 38.8h2.8M187.5 38.8h2.8M188.1 31.4h2.2" fill="none" stroke="#000" stroke-width=".17"/>
<path d="M185.5 38.8l2.2-1.4v2.9z" fill="#00f"/>
<path d="M185.5 38.8l2.2-1.4v2.9zM185.5 37.4v2.9M192.1 46.3h1.7M193.8 44.6v3.3M194.2 45h1.7M194.2 46.3h1.7v1.8M194.2 47.6h1.7M194.2 44.6v.8M194.2 45.9v.7M194.2 47.2v.7" fill="none" stroke="#00f" stroke-width=".17"/>
<path d="M190.3 46.3h1.8M195.9 42.5v1.9M195.9 48.1v1.9" fill="none" stroke="#000" stroke-width=".17"/>
<path d="M194.2 46.3l1.1-.4v.7z" fill="#00f"/>
<path d="M185.1 22.1l2.6 1.1M178.4 49.7h1.5v4.3h-1.5zM194.2 46.3l1.1-.4v.7zM195.9 44.4v.6" fill="none" stroke="#00f" stroke-width=".17"/>
<path d="M177.2 59.3h3.8M177.8 59.9h2.6M179.1 57.4v1.9M194 59.3h3.7M194.6 59.9h2.6M195.9 57.4v1.9M178.4 60.4h1.4M178.9 61h.4M195.1 60.4h1.5M195.7 61h.3" fill="none" stroke="#800000" stroke-width=".17"/>
<g fill="none" stroke="#000" stroke-width=".17">
<path d="M186.6 16.8v.6M186.6 17.8v.6M186.6 18.7v.6M186.6 19.6v.6M186.6 16.5h.5M187.5 16.5h.6M188.4 16.5h.6M189.3 16.5h.6M190.3 16.5h.6M191.2 16.5h.6M192.1 16.5h.6M193.1 16.5h.5"/>
<path d="M194 16.5h.6M194.9 16.5h.6M195.9 16.5h.5M196.8 16.5h.6M197.7 16.5h.6M198.7 16.5h.5M199.6 16.5h.6M200.5 16.5h.6M201.4 16.5h.6M202.4 16.5h.6M203.3 16.5h.6M204.2 16.5h.6"/>
<path d="M205.2 16.5h.5M206.1 16.5h.6M207 16.5h.6M208 16.5h.5M208.9 16.5h.6M209.8 16.5h.6M210.8 16.5h.5M211.7 16.5h.6M212.6 16.5h.6M213.6 16.5h.5M214.5 16.5h.6M215.4 16.5h.6"/>
<path d="M216.3 16.5h.6M217.3 16.5h.6M218.2 16.5h.6M219.1 16.5h.6M220.1 16.5h.5M221 16.5h.6M221.9 16.5h.6M222.9 16.5h.5M223.8 16.5h.6M224.7 16.5h.6M225.6 16.5h.6M226.6 16.5h.6"/>
<path d="M227.5 16.5h.6M228.4 16.5h.6M229.4 16.5h.6M230.3 16.5h.6M231.2 16.5h.6M232.2 16.5h.5M233.1 16.5v.6M233.1 17.4v.6M182.8 22.1h2.2M186.6 20.6v.6M186.6 21.5v.6M186.6 22.4v.6"/>
<path d="M186.6 23.4v.5M186.6 24.3v.6M186.6 25.2v.6M186.6 26.2v.5M186.6 27.1v.6M186.6 28v.6M186.6 28.9v.6M186.6 29.9v.6M186.6 30.8v.6M186.6 31.7v.6M186.6 32.7v.5M179.1 48.1v1.5"/>
<path d="M179.1 54.1v1.5"/>
</g>
<path d="M187.7 23.2l.3 .7h-.7z" fill="#00f"/>
<path d="M187.3 20.2h.7l-.3 .8zM187.7 23.2l.3 .7h-.7zM231.6 20.2h.8l-.4 .8zM234.6 22.1l-2.6 1.1" fill="none" stroke="#00f" stroke-width=".17"/>
<path d="M188.1 23.9h2.2M188.1 20.2h2.2M234.6 22.1h2.2" fill="none" stroke="#000" stroke-width=".17"/>
<path d="M232 23.2l.4 .7h-.8z" fill="#00f"/>
<path d="M232 23.2l.4 .7h-.8zM182.5 45.5h4.4v1.5h-4.4z" fill="none" stroke="#00f" stroke-width=".17"/>
<path d="M229.4 20.2h2.2M229.4 23.9h2.2M181 46.3h1.4M186.9 46.3h1.5" fill="none" stroke="#000" stroke-width=".17"/>
<circle cx="177.2" cy="46.3" r=".38" fill="#000080"/>
<circle cx="177.2" cy="46.3" r=".38" fill="none" stroke="#000080" stroke-width=".17"/>
<path d="M177.2 44.4v1.9" fill="none" stroke="#000" stroke-width=".17"/>
<circle cx="177.2" cy="46.3" r=".38" fill="#000080"/>
<circle cx="177.2" cy="46.3" r=".38" fill="none" stroke="#000080" stroke-width=".17"/>
<g fill="none" stroke="#000" stroke-width=".17">
<path d="M76.7 23.9h1.5M82.7 23.9h1.5M87.9 25.8v1.9M87.9 31.4v1.8M194 23.9h1.5M200 23.9h1.4M201.4 20.2h1.5M207.4 20.2h1.5M212.6 20.2h1.5M218.6 20.2h1.5M223.8 25.8v1.5M223.8 31.8v1.4"/>
<circle cx="177.2" cy="43.5" r=".93"/>
</g>
<path d="M203 19.5h4.4v1.5h-4.4zM214.1 19.5h4.4v1.5h-4.4zM78.2 23.2h4.4v1.5h-4.4zM86.4 29.9h2.9M86.4 29.2h2.9M87.9 27.7v1.5M87.9 29.9v1.5M195.5 23.2h4.4v1.5h-4.4zM223.1 27.3h1.5v4.4h-1.5z" fill="none" stroke="#00f" stroke-width=".17"/>
<g fill="none" stroke="#800000" stroke-width=".17">
<path d="M86 37h3.7M86.6 37.5h2.6M87.1 38.1h1.5M87.7 38.6h.4M87.9 35.1v1.9M221.9 37h3.7M222.5 37.5h2.6M223 38.1h1.5M223.6 38.6h.4M223.8 35.1v1.9M46.9 143h3.7M47.5 143.6h2.6"/>
<path d="M48 144.1h1.5M48.6 144.7h.4M48.8 141.1v1.9"/>
</g>
<path d="M65.5 115.1l14.9 7.4-14.9 7.5z" fill="#ffffb0"/>
<g fill="none" stroke="#800000" stroke-width=".17">
<path d="M65.5 115.1l14.9 7.4-14.9 7.5zM176.3 115.1h1.9M177.2 115.1v1.9M164.2 130h3.7M164.8 130.5h2.6M165.3 131.1h1.5M165.9 131.6h.4M166.1 128.1v1.9M153 148.6h3.8M153.6 149.1h2.6M154.2 149.7h1.4M154.7 150.3h.4"/>
<path d="M154.9 146.7v1.9"/>
</g>
<g fill="none" stroke="#000" stroke-width=".17">
<path d="M48.8 107.7v1.4M48.8 113.6v1.5M59.9 118.8h5.6M69.3 111.4v5.6M71.1 105.8h1.5M77.1 105.8h1.5M80.4 105.8h1.9M86 105.8h1.9M154.9 109.5v1.5M154.9 115.5v1.5M156.8 118.8h1.4M162.7 118.8h1.5"/>
<path d="M48.8 131.8v1.5M48.8 137.8v1.5M59.9 126.3h5.6M69.3 128.1v5.6M73 126.3v5.5M73 139.3h1.8M76.7 124.4v5.6M78.6 139.3h1.8M80.4 122.5h5.6M89.7 122.5h1.5M95.7 122.5h1.5M154.9 126.3v1.4"/>
<path d="M154.9 132.2v1.5M154.9 137.4v1.5M166.1 120.7v1.8M166.1 126.3v1.8M154.9 143.4v1.5M106.5 165.3v1.9M106.5 170.9v1.9M113.9 165.3v1.9M113.9 170.9v1.9M121.4 165.3v1.9M121.4 170.9v1.9M128.8 165.3v1.9"/>
<path d="M128.8 170.9v1.9M136.3 165.3v1.9M136.3 170.9v1.9"/>
</g>
<path d="M72.2 131.1l1.5 1.5M73.7 131.1l-1.5 1.5M76 129.2l1.4 1.5M77.4 129.2l-1.4 1.5" fill="none" stroke="#f00" stroke-width=".17"/>
<g fill="none" stroke="#00f" stroke-width=".17">
<path d="M48.1 109.2h1.4v4.4h-1.4zM72.6 105.1h4.4v1.5h-4.4zM82.3 105.8h1.5M83.8 104.3v3M84.5 105.8h1.5M84.5 104.3v3M154.2 111h1.5v4.4h-1.5zM158.3 118h4.4v1.5h-4.4zM48.1 133.4h1.4v4.4h-1.4zM74.8 139.3h1.5M76.3 137.8v2.9M77.1 139.3h1.5"/>
<path d="M77.1 137.8v2.9M91.3 121.8h4.4v1.4h-4.4zM154.2 127.8h1.5v4.4h-1.5zM154.2 138.9h1.5v4.4h-1.5zM164.6 124h2.9M164.6 124.8h2.9M166.1 122.5v1.5M166.1 124.8v1.5M105 168.7h3M105 169.4h3M106.5 167.2v1.5M106.5 169.4v1.5"/>
<path d="M112.5 168.7h2.9M112.5 169.4h2.9M113.9 167.2v1.5M113.9 169.4v1.5M119.9 168.7h3M119.9 169.4h3M121.4 167.2v1.5M121.4 169.4v1.5M127.4 168.7h2.9M127.4 169.4h2.9M128.8 167.2v1.5M128.8 169.4v1.5"/>
<path d="M134.8 168.7h2.9M134.8 169.4h2.9M136.3 167.2v1.5M136.3 169.4v1.5"/>
</g>
<path d="M110.2 96.5h18.6v27.9h-18.6z" fill-rule="evenodd" fill="#ffffb0"/>
<g fill="none" stroke="#800000" stroke-width=".17">
<path d="M110.2 96.5h18.6v27.9h-18.6zM97.2 135.6h3.7M97.7 136.1h2.6M98.3 136.7h1.5M98.9 137.2h.3M99 133.7v1.9M102.8 135.6h3.7M103.3 136.1h2.6M103.9 136.7h1.5M104.4 137.2h.4M104.6 133.7v1.9M134.4 135.6h3.7"/>
<path d="M135 136.1h2.6M135.5 136.7h1.5M136.1 137.2h.4M136.3 133.7v1.9M164.2 148.6h3.7M164.8 149.1h2.6M165.3 149.7h1.5M165.9 150.3h.4M166.1 146.7v1.9M75 174.4v.4M75.6 173.9v1.5M76.2 173.3v2.6"/>
<path d="M76.7 162.5v1.9M76.7 172.8v3.7M76.7 163.5h1.9M76.7 174.6h1.9M76.7 184.9v1.8M76.7 185.8h1.9"/>
</g>
<g fill="none" stroke="#000" stroke-width=".17">
<path d="M104.6 98.4h5.6M95.3 109.5h1.5M101.3 109.5h1.5M104.6 102.1h5.6M104.6 105.8h5.6M104.6 109.5h5.6M104.6 113.2h5.6M104.6 117h5.6M104.6 118.8h5.6M104.6 100.2h5.6M128.8 105.8h5.6M128.8 109.5h7.1"/>
<path d="M128.8 113.2h5.6M128.8 117h5.6M128.8 118.8h5.6M140.4 109.5h1.5M99 124.4v1.9M99 130v1.8M104.6 120.7h5.6M104.6 122.5h5.6M128.8 120.7h5.6M128.8 122.5h5.6M136.3 124.4v1.5M136.3 130.4v1.4"/>
<path d="M166.1 137.4v1.5M162.3 141.1h3M164.8 140.6l.5 .5-.5 .6zM166.1 143.4v1.5M43.2 161.6v1.5M43.2 167.6v1.4M99 165.3v1.9M99 170.9v1.9M106.5 176.5v1.9M113.9 176.5v1.9M121.4 176.5v1.9M128.8 176.5v1.9"/>
<path d="M106.5 182.1v1.8M113.9 182.1v1.8M121.4 182.1v1.8M128.8 182.1v1.8"/>
</g>
<path d="M103.9 116.2l1.5 1.5M103.9 118.1l1.5 1.5M103.9 119.9l1.5 1.5M105.4 116.2l-1.5 1.5M105.4 118.1l-1.5 1.5M105.4 119.9l-1.5 1.5M165.3 136.7l1.5 1.5M166.8 136.7l-1.5 1.5" fill="none" stroke="#f00" stroke-width=".17"/>
<g fill="none" stroke="#00f" stroke-width=".17">
<path d="M96.8 108.7h4.4v1.5h-4.4zM135.9 108.8h4.4v1.5h-4.4zM97.6 128.5h2.9M97.6 127.8h2.9M99 126.3v1.5M99 128.5v1.5M135.6 125.9h1.5v4.4h-1.5zM165.4 138.9h1.4v4.4h-1.4zM42.5 163.1h1.5v4.4h-1.5zM97.6 169.4h2.9M97.6 168.7h2.9M99 167.2v1.5"/>
<path d="M99 169.4v1.5M105 179.8h3M106.5 178.4v1.4M112.5 179.8h2.9M113.9 178.4v1.4M119.9 179.8h2.9M121.4 178.4v1.4M127.4 179.8h2.9M128.8 178.4v1.4M105 180.6h3M106.5 180.6v1.5M112.5 180.6h2.9"/>
<path d="M113.9 180.6v1.5M119.9 180.6h2.9M121.4 180.6v1.5M127.4 180.6h2.9M128.8 180.6v1.5"/>
</g>
<path d="M164.8 140.6l.5 .5-.5 .6z" fill="#000"/>
<circle cx="24.6" cy="176.5" r=".37" fill="#000080"/>
<circle cx="24.6" cy="176.5" r=".37" fill="none" stroke="#000080" stroke-width=".17"/>
<path d="M24.6 174.6v1.9" fill="none" stroke="#000" stroke-width=".17"/>
<circle cx="24.6" cy="176.5" r=".37" fill="#000080"/>
<circle cx="24.6" cy="176.5" r=".37" fill="none" stroke="#000080" stroke-width=".17"/>
<g fill="none" stroke="#000" stroke-width=".17">
<path d="M22.7 178.4v1.4M22.7 184.3v1.5"/>
<circle cx="24.6" cy="173.7" r=".93"/>
</g>
<path d="M21.9 179.9h1.5v4.4h-1.5z" fill="none" stroke="#00f" stroke-width=".17"/>
<path d="M20.9 189.5h3.7M21.4 190.1h2.6M22 190.6h1.5M22.5 191.2h.4M22.7 187.7v1.8" fill="none" stroke="#800000" stroke-width=".17"/>
<path d="M11.5 175.6h8.4l1 .9-1 .9h-8.4z" fill-rule="evenodd" fill="#ffff80"/>
<path d="M11.5 175.6h8.4l1 .9-1 .9h-8.4z" fill="none" stroke="#800000" stroke-width=".17"/>
<path d="M99 176.5v1.9M136.3 176.5v1.9M143.7 165.3v1.9M143.7 170.9v1.9M143.7 176.5v1.9M99 182.1v1.8M136.3 182.1v1.8M143.7 182.1v1.8" fill="none" stroke="#000" stroke-width=".17"/>
<g fill="none" stroke="#00f" stroke-width=".17">
<path d="M97.6 179.8h2.9M99 178.4v1.4M134.8 179.8h2.9M136.3 178.4v1.4M142.3 169.4h2.9M142.3 168.7h2.9M142.3 179.8h2.9M143.7 167.2v1.5M143.7 169.4v1.5M143.7 178.4v1.4M97.6 180.6h2.9M99 180.6v1.5"/>
<path d="M134.8 180.6h2.9M136.3 180.6v1.5M142.3 180.6h2.9M143.7 180.6v1.5"/>
</g>
<path d="M28.3 115.1h11.2v11.2h-11.2z" fill-rule="evenodd" fill="#ffffb0"/>
<path d="M28.3 115.1h11.2v11.2h-11.2z" fill="none" stroke="#800000" stroke-width=".17"/>
<path d="M22.7 117h5.6M39.5 117h5.5M22.7 124.4h5.6M22.7 120.7h5.6M39.5 124.4h5.5" fill="none" stroke="#000" stroke-width=".17"/>
<circle cx="48.8" cy="117" r=".37" fill="#000080"/>
<circle cx="48.8" cy="117" r=".37" fill="none" stroke="#000080" stroke-width=".17"/>
<circle cx="48.8" cy="124.4" r=".37" fill="#000080"/>
<circle cx="48.8" cy="124.4" r=".37" fill="none" stroke="#000080" stroke-width=".17"/>
<path d="M48.8 117v1.8" fill="none" stroke="#000" stroke-width=".17"/>
<circle cx="48.8" cy="117" r=".37" fill="#000080"/>
<circle cx="48.8" cy="117" r=".37" fill="none" stroke="#000080" stroke-width=".17"/>
<path d="M48.8 122.5v1.9" fill="none" stroke="#000" stroke-width=".17"/>
<circle cx="48.8" cy="124.4" r=".37" fill="#000080"/>
<circle cx="48.8" cy="124.4" r=".37" fill="none" stroke="#000080" stroke-width=".17"/>
<path d="M48.8 118.8v1.5M47.3 120.3h2.9M47.3 121h2.9M48.8 121v1.5M39.5 176.5h1.6M41.1 174.8v3.3M41.5 175.2h1.7M41.5 176.5h1.7v1.9M41.5 177.8h1.7M41.5 174.8v.8M41.5 176.1v.8M41.5 177.4v.7" fill="none" stroke="#00f" stroke-width=".17"/>
<path d="M37.6 176.5h1.9M43.2 172.8v1.8M43.2 178.4v1.8" fill="none" stroke="#000" stroke-width=".17"/>
<path d="M41.5 176.5l1.1-.4v.8z" fill="#00f"/>
<g fill="none" stroke="#00f" stroke-width=".17">
<path d="M61.5 105.1h4.4v1.5h-4.4zM169.5 118.1h4.4v1.5h-4.4zM193.7 118.1h4.4v1.5h-4.4zM175.8 124h2.9M175.8 124.8h2.9M177.2 122.5v1.5M177.2 124.8v1.5M188.8 124h2.9M188.8 124.8h2.9M190.3 122.5v1.5M190.3 124.8v1.5M195.9 136.5h.9l-.9 1.8h-1z"/>
<path d="M264.7 136.5h1l-1 1.8h-.9zM188.8 142.6h2.9M188.8 143.4h2.9M190.3 141.1v1.5M190.3 143.4v1.5M268.9 142.6h2.9M268.9 143.4h2.9M270.3 141.1v1.5M270.3 143.4v1.5M29.8 175.7h4.4v1.5h-4.4zM41.5 176.5l1.1-.4v.8zM43.2 174.6v.6"/>
<path d="M80.8 169.4h3M80.8 168.7h3M80.8 179.8h3M82.3 167.2v1.5M82.3 169.4v1.5M82.3 178.4v1.4M87.9 162.5h.9l-.9 1.9h-1zM80.8 180.6h3M82.3 180.6v1.5M87.9 184.9h.9l-.9 1.8h-1z"/>
</g>
<g fill="none" stroke="#800000" stroke-width=".17">
<path d="M189.3 115.1h1.9M190.3 115.1v1.9M175.4 130h3.7M175.9 130.5h2.6M176.5 131.1h1.5M177.1 131.6h.3M177.2 128.1v1.9M188.4 130h3.7M189 130.5h2.6M189.5 131.1h1.5M190.1 131.6h.4M190.3 128.1v1.9"/>
<path d="M188.4 148.6h3.7M189 149.1h2.6M189.5 149.7h1.5M190.1 150.3h.4M190.3 146.7v1.9M268.5 148.6h3.7M269 149.1h2.6M269.6 149.7h1.5M270.1 150.3h.4M270.3 146.7v1.9M41.3 189.5h3.7M41.9 190.1h2.6"/>
<path d="M42.4 190.6h1.5M43 191.2h.4M43.2 187.7v1.8"/>
</g>
<g fill="none" stroke="#000" stroke-width=".17">
<path d="M59.9 105.8h1.5M65.9 105.8h1.5M167.9 118.8h1.5M173.9 118.8h1.5M192.1 118.8h1.5M198.1 118.8h1.5M177.2 120.7v1.8M177.2 126.3v1.8M190.3 120.7v1.8M190.3 126.3v1.8M190.3 139.3v1.8M192.1 137.4h3.3"/>
<path d="M196.3 137.4h3.3M261 137.4h3.3M265.2 137.4h3.3M270.3 139.3v1.8M190.3 144.9v1.8M270.3 144.9v1.8M28.3 176.5h1.5M34.3 176.5h1.4M82.3 165.3v1.9M82.3 170.9v1.9M82.3 176.5v1.9M84.2 163.5h3.2"/>
<path d="M88.3 163.5h3.3M82.3 182.1v1.8M84.2 185.8h3.2M88.3 185.8h3.3"/>
</g>
<path d="M26.4 25.8v3.7M210.8 98.4h7.4M192.1 105.8h26.1M210.8 100.2h7.4M216.3 118.8h1.9" fill="none" stroke="#000080" stroke-width=".17"/>
<circle cx="216.3" cy="118.8" r=".37" fill="#000080"/>
<g fill="none" stroke="#000080" stroke-width=".17">
<path d="M251.7 96.5h3.7M251.7 111.4h1.9"/>
<circle cx="216.3" cy="118.8" r=".37"/>
</g>
<circle cx="255.4" cy="96.5" r=".37" fill="#000080"/>
<g fill="none" stroke="#000080" stroke-width=".17">
<path d="M216.3 120.7v1.8"/>
<circle cx="255.4" cy="96.5" r=".37"/>
</g>
<circle cx="216.3" cy="120.7" r=".37" fill="#000080"/>
<g fill="none" stroke="#000080" stroke-width=".17">
<path d="M216.3 94.6v1.9"/>
<circle cx="216.3" cy="120.7" r=".37"/>
</g>
<circle cx="216.3" cy="96.5" r=".37" fill="#000080"/>
<g fill="none" stroke="#000080" stroke-width=".17">
<path d="M261 98.4v1.8h-9.3M262.9 107.7v11.1h-1.9M274.1 105.8h1.8M274.1 107.7h1.8"/>
<circle cx="216.3" cy="96.5" r=".37"/>
</g>
<circle cx="262.9" cy="107.7" r=".37" fill="#000080"/>
<g fill="none" stroke="#000080" stroke-width=".17">
<path d="M257.3 137.4v1.9"/>
<circle cx="262.9" cy="107.7" r=".37"/>
</g>
<circle cx="257.3" cy="137.4" r=".37" fill="#000080"/>
<g fill="none" stroke="#000080" stroke-width=".17">
<path d="M246.1 137.4h-5.6v1.9"/>
<circle cx="257.3" cy="137.4" r=".37"/>
</g>
<circle cx="246.1" cy="137.4" r=".37" fill="#000080"/>
<g fill="none" stroke="#000080" stroke-width=".17">
<path d="M251.7 137.4h-5.6v1.9"/>
<circle cx="246.1" cy="137.4" r=".37"/>
</g>
<circle cx="246.1" cy="137.4" r=".37" fill="#000080"/>
<circle cx="246.1" cy="137.4" r=".37" fill="none" stroke="#000080" stroke-width=".17"/>
<circle cx="251.7" cy="137.4" r=".37" fill="#000080"/>
<g fill="none" stroke="#000080" stroke-width=".17">
<path d="M264.7 105.8v13h1.9M229.4 135.6v3.7"/>
<circle cx="251.7" cy="137.4" r=".37"/>
</g>
<circle cx="264.7" cy="105.8" r=".37" fill="#000080"/>
<g fill="none" stroke="#000080" stroke-width=".17">
<path d="M52.5 46.3h3.7"/>
<circle cx="264.7" cy="105.8" r=".37"/>
</g>
<circle cx="56.2" cy="46.3" r=".37" fill="#000080"/>
<circle cx="56.2" cy="46.3" r=".37" fill="none" stroke="#000080" stroke-width=".17"/>
<circle cx="54.4" cy="46.3" r=".37" fill="#000080"/>
<g fill="none" stroke="#000080" stroke-width=".17">
<path d="M58.1 46.3h-1.9v1.8"/>
<circle cx="54.4" cy="46.3" r=".37"/>
</g>
<circle cx="56.2" cy="46.3" r=".37" fill="#000080"/>
<g fill="none" stroke="#000080" stroke-width=".17">
<path d="M56.2 31.4v7.4h3.7"/>
<circle cx="56.2" cy="46.3" r=".37"/>
</g>
<circle cx="56.2" cy="31.4" r=".37" fill="#000080"/>
<g fill="none" stroke="#000080" stroke-width=".17">
<path d="M56.2 29.5v1.9h3.7"/>
<circle cx="56.2" cy="31.4" r=".37"/>
</g>
<circle cx="56.2" cy="31.4" r=".37" fill="#000080"/>
<g fill="none" stroke="#000080" stroke-width=".17">
<path d="M67.4 38.8h5.6M65.5 46.3h1.9"/>
<circle cx="56.2" cy="31.4" r=".37"/>
</g>
<circle cx="73" cy="38.8" r=".37" fill="#000080"/>
<g fill="none" stroke="#000080" stroke-width=".17">
<path d="M67.4 31.4h5.6v11.1M110.2 23.9h3.7M136.3 33.2v1.9M56.2 55.6v1.8M73 50v7.4"/>
<circle cx="73" cy="38.8" r=".37"/>
</g>
<circle cx="73" cy="38.8" r=".37" fill="#000080"/>
<g fill="none" stroke="#000080" stroke-width=".17">
<path d="M164.2 22.1h18.6M205.2 33.2v1.9M175.4 46.3h3.7"/>
<circle cx="73" cy="38.8" r=".37"/>
</g>
<circle cx="179.1" cy="46.3" r=".38" fill="#000080"/>
<circle cx="179.1" cy="46.3" r=".38" fill="none" stroke="#000080" stroke-width=".17"/>
<circle cx="177.2" cy="46.3" r=".38" fill="#000080"/>
<g fill="none" stroke="#000080" stroke-width=".17">
<path d="M181 46.3h-1.9v1.8"/>
<circle cx="177.2" cy="46.3" r=".38"/>
</g>
<circle cx="179.1" cy="46.3" r=".38" fill="#000080"/>
<g fill="none" stroke="#000080" stroke-width=".17">
<path d="M179.1 31.4v7.4h3.7"/>
<circle cx="179.1" cy="46.3" r=".38"/>
</g>
<circle cx="179.1" cy="31.4" r=".37" fill="#000080"/>
<g fill="none" stroke="#000080" stroke-width=".17">
<path d="M179.1 29.5v1.9h3.7"/>
<circle cx="179.1" cy="31.4" r=".37"/>
</g>
<circle cx="179.1" cy="31.4" r=".37" fill="#000080"/>
<g fill="none" stroke="#000080" stroke-width=".17">
<path d="M190.3 38.8h5.6M188.4 46.3h1.9"/>
<circle cx="179.1" cy="31.4" r=".37"/>
</g>
<circle cx="195.9" cy="38.8" r=".37" fill="#000080"/>
<g fill="none" stroke="#000080" stroke-width=".17">
<path d="M190.3 31.4h5.6v11.1M179.1 55.6v1.8M195.9 50v7.4"/>
<circle cx="195.9" cy="38.8" r=".37"/>
</g>
<circle cx="195.9" cy="38.8" r=".37" fill="#000080"/>
<g fill="none" stroke="#000080" stroke-width=".17">
<path d="M67.4 20.2h89.4M87.9 33.2v1.9M143.7 33.2v1.9M190.3 20.2h11.1M190.3 23.9h3.7M201.4 23.9h28M208.9 20.2h3.7M223.8 33.2v1.9M236.8 22.1h11.2"/>
<circle cx="195.9" cy="38.8" r=".37"/>
</g>
<circle cx="205.2" cy="23.9" r=".37" fill="#000080"/>
<g fill="none" stroke="#000080" stroke-width=".17">
<path d="M205.2 23.9v1.9"/>
<circle cx="205.2" cy="23.9" r=".37"/>
</g>
<circle cx="205.2" cy="23.9" r=".37" fill="#000080"/>
<g fill="none" stroke="#000080" stroke-width=".17">
<path d="M220.1 20.2h9.3"/>
<circle cx="205.2" cy="23.9" r=".37"/>
</g>
<circle cx="223.8" cy="20.2" r=".37" fill="#000080"/>
<g fill="none" stroke="#000080" stroke-width=".17">
<path d="M223.8 20.2v5.6"/>
<circle cx="223.8" cy="20.2" r=".37"/>
</g>
<circle cx="223.8" cy="20.2" r=".37" fill="#000080"/>
<g fill="none" stroke="#000080" stroke-width=".17">
<path d="M136.3 23.9v1.9"/>
<circle cx="223.8" cy="20.2" r=".37"/>
</g>
<circle cx="136.3" cy="23.9" r=".37" fill="#000080"/>
<g fill="none" stroke="#000080" stroke-width=".17">
<path d="M30.2 22.1h29.7M166.1 118.8v1.9"/>
<circle cx="136.3" cy="23.9" r=".37"/>
</g>
<circle cx="166.1" cy="118.8" r=".37" fill="#000080"/>
<g fill="none" stroke="#000080" stroke-width=".17">
<path d="M86 122.5h1.9v16.8h-7.5"/>
<circle cx="166.1" cy="118.8" r=".37"/>
</g>
<circle cx="87.9" cy="122.5" r=".37" fill="#000080"/>
<g fill="none" stroke="#000080" stroke-width=".17">
<path d="M154.9 118.8h1.9"/>
<circle cx="87.9" cy="122.5" r=".37"/>
</g>
<circle cx="154.9" cy="118.8" r=".37" fill="#000080"/>
<g fill="none" stroke="#000080" stroke-width=".17">
<path d="M99 163.5v1.8"/>
<circle cx="154.9" cy="118.8" r=".37"/>
</g>
<circle cx="99" cy="163.5" r=".37" fill="#000080"/>
<g fill="none" stroke="#000080" stroke-width=".17">
<path d="M113.9 163.5v1.8"/>
<circle cx="99" cy="163.5" r=".37"/>
</g>
<circle cx="113.9" cy="163.5" r=".37" fill="#000080"/>
<g fill="none" stroke="#000080" stroke-width=".17">
<path d="M121.4 163.5v1.8"/>
<circle cx="113.9" cy="163.5" r=".37"/>
</g>
<circle cx="121.4" cy="163.5" r=".37" fill="#000080"/>
<g fill="none" stroke="#000080" stroke-width=".17">
<path d="M48.8 139.3v1.8M128.8 163.5v1.8"/>
<circle cx="121.4" cy="163.5" r=".37"/>
</g>
<circle cx="128.8" cy="163.5" r=".37" fill="#000080"/>
<g fill="none" stroke="#000080" stroke-width=".17">
<path d="M78.6 105.8h1.8M87.9 122.5h1.8M154.9 144.9v1.8"/>
<circle cx="128.8" cy="163.5" r=".37"/>
</g>
<circle cx="87.9" cy="122.5" r=".37" fill="#000080"/>
<g fill="none" stroke="#000080" stroke-width=".17">
<path d="M141.9 109.5h1.8v3.7M104.6 122.5v11.2M136.3 131.8v1.9"/>
<circle cx="87.9" cy="122.5" r=".37"/>
</g>
<circle cx="143.7" cy="109.5" r=".37" fill="#000080"/>
<circle cx="143.7" cy="109.5" r=".37" fill="none" stroke="#000080" stroke-width=".17"/>
<circle cx="143.7" cy="113.2" r=".37" fill="#000080"/>
<g fill="none" stroke="#000080" stroke-width=".17">
<path d="M102.8 100.2h1.8"/>
<circle cx="143.7" cy="113.2" r=".37"/>
</g>
<circle cx="102.8" cy="100.2" r=".37" fill="#000080"/>
<g fill="none" stroke="#000080" stroke-width=".17">
<path d="M102.8 98.4h1.8"/>
<circle cx="102.8" cy="100.2" r=".37"/>
</g>
<circle cx="102.8" cy="98.4" r=".37" fill="#000080"/>
<g fill="none" stroke="#000080" stroke-width=".17">
<path d="M99 122.5v1.9"/>
<circle cx="102.8" cy="98.4" r=".37"/>
</g>
<circle cx="99" cy="122.5" r=".37" fill="#000080"/>
<g fill="none" stroke="#000080" stroke-width=".17">
<path d="M99 131.8v1.9M154.9 135.6h5.6v5.5h1.8M166.1 144.9v1.8"/>
<circle cx="99" cy="122.5" r=".37"/>
</g>
<circle cx="154.9" cy="135.6" r=".37" fill="#000080"/>
<g fill="none" stroke="#000080" stroke-width=".17">
<path d="M121.4 183.9v1.9"/>
<circle cx="154.9" cy="135.6" r=".37"/>
</g>
<circle cx="121.4" cy="185.8" r=".37" fill="#000080"/>
<g fill="none" stroke="#000080" stroke-width=".17">
<path d="M113.9 183.9v1.9"/>
<circle cx="121.4" cy="185.8" r=".37"/>
</g>
<circle cx="113.9" cy="185.8" r=".37" fill="#000080"/>
<g fill="none" stroke="#000080" stroke-width=".17">
<path d="M106.5 183.9v1.9"/>
<circle cx="113.9" cy="185.8" r=".37"/>
</g>
<circle cx="106.5" cy="185.8" r=".37" fill="#000080"/>
<g fill="none" stroke="#000080" stroke-width=".17">
<path d="M93.5 105.8v3.7h1.8M102.8 109.5h1.8"/>
<circle cx="106.5" cy="185.8" r=".37"/>
</g>
<circle cx="93.5" cy="105.8" r=".37" fill="#000080"/>
<g fill="none" stroke="#000080" stroke-width=".17">
<path d="M134.4 113.2h9.3v3.8h-9.3M134.4 122.5h1.9v1.9"/>
<circle cx="93.5" cy="105.8" r=".37"/>
</g>
<circle cx="143.7" cy="117" r=".37" fill="#000080"/>
<circle cx="143.7" cy="117" r=".37" fill="none" stroke="#000080" stroke-width=".17"/>
<circle cx="143.7" cy="113.2" r=".37" fill="#000080"/>
<g fill="none" stroke="#000080" stroke-width=".17">
<path d="M143.7 117v1.8"/>
<circle cx="143.7" cy="113.2" r=".37"/>
</g>
<circle cx="143.7" cy="118.8" r=".37" fill="#000080"/>
<circle cx="143.7" cy="118.8" r=".37" fill="none" stroke="#000080" stroke-width=".17"/>
<circle cx="143.7" cy="117" r=".37" fill="#000080"/>
<g fill="none" stroke="#000080" stroke-width=".17">
<path d="M104.6 113.2h-5.6v9.3h-1.8"/>
<circle cx="143.7" cy="117" r=".37"/>
</g>
<circle cx="99" cy="122.5" r=".37" fill="#000080"/>
<g fill="none" stroke="#000080" stroke-width=".17">
<path d="M99 183.9v1.9"/>
<circle cx="99" cy="122.5" r=".37"/>
</g>
<circle cx="99" cy="185.8" r=".37" fill="#000080"/>
<g fill="none" stroke="#000080" stroke-width=".17">
<path d="M128.8 183.9v1.9"/>
<circle cx="99" cy="185.8" r=".37"/>
</g>
<circle cx="128.8" cy="185.8" r=".37" fill="#000080"/>
<g fill="none" stroke="#000080" stroke-width=".17">
<path d="M22.7 176.5v1.9M22.7 185.8v1.9"/>
<circle cx="128.8" cy="185.8" r=".37"/>
</g>
<circle cx="22.7" cy="176.5" r=".37" fill="#000080"/>
<g fill="none" stroke="#000080" stroke-width=".17">
<path d="M154.9 122.5h-5.6v22.4h-89.4v-5.6h13.1"/>
<circle cx="22.7" cy="176.5" r=".37"/>
</g>
<circle cx="154.9" cy="122.5" r=".37" fill="#000080"/>
<circle cx="154.9" cy="122.5" r=".37" fill="none" stroke="#000080" stroke-width=".17"/>
<circle cx="59.9" cy="139.3" r=".37" fill="#000080"/>
<g fill="none" stroke="#000080" stroke-width=".17">
<path d="M59.9 126.3v13"/>
<circle cx="59.9" cy="139.3" r=".37"/>
</g>
<circle cx="59.9" cy="139.3" r=".37" fill="#000080"/>
<g fill="none" stroke="#000080" stroke-width=".17">
<path d="M134.4 118.8h9.3v1.9h-9.3"/>
<circle cx="59.9" cy="139.3" r=".37"/>
</g>
<circle cx="143.7" cy="118.8" r=".37" fill="#000080"/>
<g fill="none" stroke="#000080" stroke-width=".17">
<path d="M121.4 174.6v1.9"/>
<circle cx="143.7" cy="118.8" r=".37"/>
</g>
<circle cx="121.4" cy="174.6" r=".37" fill="#000080"/>
<g fill="none" stroke="#000080" stroke-width=".17">
<path d="M136.3 163.5h7.4v1.8"/>
<circle cx="121.4" cy="174.6" r=".37"/>
</g>
<circle cx="136.3" cy="163.5" r=".37" fill="#000080"/>
<g fill="none" stroke="#000080" stroke-width=".17">
<path d="M143.7 183.9v1.9h-7.4"/>
<circle cx="136.3" cy="163.5" r=".37"/>
</g>
<circle cx="136.3" cy="185.8" r=".37" fill="#000080"/>
<g fill="none" stroke="#000080" stroke-width=".17">
<path d="M143.7 172.8v1.8h-7.4"/>
<circle cx="136.3" cy="185.8" r=".37"/>
</g>
<circle cx="136.3" cy="174.6" r=".37" fill="#000080"/>
<circle cx="136.3" cy="174.6" r=".37" fill="none" stroke="#000080" stroke-width=".17"/>
<circle cx="143.7" cy="174.6" r=".38" fill="#000080"/>
<g fill="none" stroke="#000080" stroke-width=".17">
<path d="M143.7 174.6v1.9"/>
<circle cx="143.7" cy="174.6" r=".38"/>
</g>
<circle cx="143.7" cy="174.6" r=".38" fill="#000080"/>
<g fill="none" stroke="#000080" stroke-width=".17">
<path d="M128.8 172.8v1.8"/>
<circle cx="143.7" cy="174.6" r=".38"/>
</g>
<circle cx="128.8" cy="174.6" r=".37" fill="#000080"/>
<g fill="none" stroke="#000080" stroke-width=".17">
<path d="M128.8 174.6v1.9"/>
<circle cx="128.8" cy="174.6" r=".37"/>
</g>
<circle cx="128.8" cy="174.6" r=".37" fill="#000080"/>
<g fill="none" stroke="#000080" stroke-width=".17">
<path d="M121.4 172.8v1.8"/>
<circle cx="128.8" cy="174.6" r=".37"/>
</g>
<circle cx="121.4" cy="174.6" r=".37" fill="#000080"/>
<g fill="none" stroke="#000080" stroke-width=".17">
<path d="M113.9 172.8v1.8"/>
<circle cx="121.4" cy="174.6" r=".37"/>
</g>
<circle cx="113.9" cy="174.6" r=".38" fill="#000080"/>
<g fill="none" stroke="#000080" stroke-width=".17">
<path d="M113.9 174.6v1.9"/>
<circle cx="113.9" cy="174.6" r=".38"/>
</g>
<circle cx="113.9" cy="174.6" r=".38" fill="#000080"/>
<g fill="none" stroke="#000080" stroke-width=".17">
<path d="M106.5 174.6v1.9"/>
<circle cx="113.9" cy="174.6" r=".38"/>
</g>
<circle cx="106.5" cy="174.6" r=".37" fill="#000080"/>
<g fill="none" stroke="#000080" stroke-width=".17">
<path d="M106.5 172.8v1.8"/>
<circle cx="106.5" cy="174.6" r=".37"/>
</g>
<circle cx="106.5" cy="174.6" r=".37" fill="#000080"/>
<g fill="none" stroke="#000080" stroke-width=".17">
<path d="M30.2 105.8h18.6"/>
<circle cx="106.5" cy="174.6" r=".37"/>
</g>
<circle cx="48.8" cy="105.8" r=".37" fill="#000080"/>
<g fill="none" stroke="#000080" stroke-width=".17">
<path d="M48.8 115.1v1.9"/>
<circle cx="48.8" cy="105.8" r=".37"/>
</g>
<circle cx="48.8" cy="117" r=".37" fill="#000080"/>
<g fill="none" stroke="#000080" stroke-width=".17">
<path d="M59.9 118.8h-3.7v9.3h-7.4"/>
<circle cx="48.8" cy="117" r=".37"/>
</g>
<circle cx="48.8" cy="128.1" r=".37" fill="#000080"/>
<g fill="none" stroke="#000080" stroke-width=".17">
<path d="M11.5 124.4h11.2M35.7 176.5h1.9M43.2 170.9h13M43.2 180.2v7.5"/>
<circle cx="48.8" cy="128.1" r=".37"/>
</g>
<circle cx="43.2" cy="170.9" r=".37" fill="#000080"/>
<g fill="none" stroke="#000080" stroke-width=".17">
<path d="M45 117h3.8M11.5 120.7h11.2"/>
<circle cx="43.2" cy="170.9" r=".37"/>
</g>
<circle cx="48.8" cy="117" r=".37" fill="#000080"/>
<g fill="none" stroke="#000080" stroke-width=".17">
<path d="M45 124.4h3.8"/>
<circle cx="48.8" cy="117" r=".37"/>
</g>
<circle cx="48.8" cy="124.4" r=".37" fill="#000080"/>
<g fill="none" stroke="#000080" stroke-width=".17">
<path d="M59.9 105.8h-11.1v1.9"/>
<circle cx="48.8" cy="124.4" r=".37"/>
</g>
<circle cx="48.8" cy="105.8" r=".37" fill="#000080"/>
<g fill="none" stroke="#000080" stroke-width=".17">
<path d="M67.4 105.8h3.7M78.6 174.6h20.4"/>
<circle cx="48.8" cy="105.8" r=".37"/>
</g>
<circle cx="82.3" cy="174.6" r=".38" fill="#000080"/>
<circle cx="82.3" cy="174.6" r=".38" fill="none" stroke="#000080" stroke-width=".17"/>
<circle cx="99" cy="174.6" r=".37" fill="#000080"/>
<g fill="none" stroke="#000080" stroke-width=".17">
<path d="M205.2 126.3v1.8"/>
<circle cx="99" cy="174.6" r=".37"/>
</g>
<circle cx="205.2" cy="126.3" r=".37" fill="#000080"/>
<g fill="none" stroke="#000080" stroke-width=".17">
<path d="M205.2 126.3h-3.8v1.8"/>
<circle cx="205.2" cy="126.3" r=".37"/>
</g>
<circle cx="205.2" cy="126.3" r=".37" fill="#000080"/>
<g fill="none" stroke="#000080" stroke-width=".17">
<path d="M207 137.4v1.9"/>
<circle cx="205.2" cy="126.3" r=".37"/>
</g>
<circle cx="207" cy="137.4" r=".37" fill="#000080"/>
<g fill="none" stroke="#000080" stroke-width=".17">
<path d="M125.1 23.9v5.6h-9.3"/>
<circle cx="207" cy="137.4" r=".37"/>
</g>
<circle cx="125.1" cy="23.9" r=".37" fill="#000080"/>
<g fill="none" stroke="#000080" stroke-width=".17">
<path d="M20.9 176.5h7.4"/>
<circle cx="125.1" cy="23.9" r=".37"/>
</g>
<circle cx="22.7" cy="176.5" r=".37" fill="#000080"/>
<circle cx="22.7" cy="176.5" r=".37" fill="none" stroke="#000080" stroke-width=".17"/>
<circle cx="24.6" cy="176.5" r=".37" fill="#000080"/>
<g fill="none" stroke="#000080" stroke-width=".17">
<path d="M87.9 105.8h16.7"/>
<circle cx="24.6" cy="176.5" r=".37"/>
</g>
<circle cx="93.5" cy="105.8" r=".37" fill="#000080"/>
<g fill="none" stroke="#000080" stroke-width=".17">
<path d="M99 174.6h37.3"/>
<circle cx="93.5" cy="105.8" r=".37"/>
</g>
<circle cx="136.3" cy="174.6" r=".37" fill="#000080"/>
<circle cx="136.3" cy="174.6" r=".37" fill="none" stroke="#000080" stroke-width=".17"/>
<circle cx="128.8" cy="174.6" r=".37" fill="#000080"/>
<circle cx="128.8" cy="174.6" r=".37" fill="none" stroke="#000080" stroke-width=".17"/>
<circle cx="121.4" cy="174.6" r=".37" fill="#000080"/>
<circle cx="121.4" cy="174.6" r=".37" fill="none" stroke="#000080" stroke-width=".17"/>
<circle cx="113.9" cy="174.6" r=".38" fill="#000080"/>
<circle cx="113.9" cy="174.6" r=".38" fill="none" stroke="#000080" stroke-width=".17"/>
<circle cx="106.5" cy="174.6" r=".37" fill="#000080"/>
<circle cx="106.5" cy="174.6" r=".37" fill="none" stroke="#000080" stroke-width=".17"/>
<circle cx="99" cy="174.6" r=".37" fill="#000080"/>
<g fill="none" stroke="#000080" stroke-width=".17">
<path d="M106.5 163.5h29.8v1.8"/>
<circle cx="99" cy="174.6" r=".37"/>
</g>
<circle cx="106.5" cy="163.5" r=".37" fill="#000080"/>
<circle cx="106.5" cy="163.5" r=".37" fill="none" stroke="#000080" stroke-width=".17"/>
<circle cx="113.9" cy="163.5" r=".37" fill="#000080"/>
<circle cx="113.9" cy="163.5" r=".37" fill="none" stroke="#000080" stroke-width=".17"/>
<circle cx="121.4" cy="163.5" r=".37" fill="#000080"/>
<circle cx="121.4" cy="163.5" r=".37" fill="none" stroke="#000080" stroke-width=".17"/>
<circle cx="128.8" cy="163.5" r=".37" fill="#000080"/>
<circle cx="128.8" cy="163.5" r=".37" fill="none" stroke="#000080" stroke-width=".17"/>
<circle cx="136.3" cy="163.5" r=".37" fill="#000080"/>
<g fill="none" stroke="#000080" stroke-width=".17">
<path d="M210.8 96.5h7.4"/>
<circle cx="136.3" cy="163.5" r=".37"/>
</g>
<circle cx="212.6" cy="96.5" r=".37" fill="#000080"/>
<circle cx="212.6" cy="96.5" r=".37" fill="none" stroke="#000080" stroke-width=".17"/>
<circle cx="216.3" cy="96.5" r=".37" fill="#000080"/>
<g fill="none" stroke="#000080" stroke-width=".17">
<path d="M218.2 117h-1.9v3.7h1.9"/>
<circle cx="216.3" cy="96.5" r=".37"/>
</g>
<circle cx="216.3" cy="118.8" r=".37" fill="#000080"/>
<circle cx="216.3" cy="118.8" r=".37" fill="none" stroke="#000080" stroke-width=".17"/>
<circle cx="216.3" cy="120.7" r=".37" fill="#000080"/>
<g fill="none" stroke="#000080" stroke-width=".17">
<path d="M251.7 107.7h14.9"/>
<circle cx="216.3" cy="120.7" r=".37"/>
</g>
<circle cx="262.9" cy="107.7" r=".37" fill="#000080"/>
<g fill="none" stroke="#000080" stroke-width=".17">
<path d="M251.7 105.8h14.9"/>
<circle cx="262.9" cy="107.7" r=".37"/>
</g>
<circle cx="264.7" cy="105.8" r=".37" fill="#000080"/>
<g fill="none" stroke="#000080" stroke-width=".17">
<path d="M43.2 169v3.8"/>
<circle cx="264.7" cy="105.8" r=".37"/>
</g>
<circle cx="43.2" cy="170.9" r=".37" fill="#000080"/>
<g fill="none" stroke="#000080" stroke-width=".17">
<path d="M48.8 124.4v7.4"/>
<circle cx="43.2" cy="170.9" r=".37"/>
</g>
<circle cx="48.8" cy="128.1" r=".37" fill="#000080"/>
<circle cx="48.8" cy="128.1" r=".37" fill="none" stroke="#000080" stroke-width=".17"/>
<circle cx="48.8" cy="124.4" r=".37" fill="#000080"/>
<g fill="none" stroke="#000080" stroke-width=".17">
<path d="M99 172.8v3.7"/>
<circle cx="48.8" cy="124.4" r=".37"/>
</g>
<circle cx="99" cy="174.6" r=".37" fill="#000080"/>
<g fill="none" stroke="#000080" stroke-width=".17">
<path d="M136.3 172.8v3.7"/>
<circle cx="99" cy="174.6" r=".37"/>
</g>
<circle cx="136.3" cy="174.6" r=".37" fill="#000080"/>
<g fill="none" stroke="#000080" stroke-width=".17">
<path d="M175.4 118.8h1.8v1.9"/>
<circle cx="136.3" cy="174.6" r=".37"/>
</g>
<circle cx="177.2" cy="118.8" r=".38" fill="#000080"/>
<g fill="none" stroke="#000080" stroke-width=".17">
<path d="M177.2 117v1.8"/>
<circle cx="177.2" cy="118.8" r=".38"/>
</g>
<circle cx="177.2" cy="118.8" r=".38" fill="#000080"/>
<g fill="none" stroke="#000080" stroke-width=".17">
<path d="M192.1 118.8h-1.8v1.9"/>
<circle cx="177.2" cy="118.8" r=".38"/>
</g>
<circle cx="190.3" cy="118.8" r=".37" fill="#000080"/>
<g fill="none" stroke="#000080" stroke-width=".17">
<path d="M190.3 117v1.8"/>
<circle cx="190.3" cy="118.8" r=".37"/>
</g>
<circle cx="190.3" cy="118.8" r=".37" fill="#000080"/>
<g fill="none" stroke="#000080" stroke-width=".17">
<path d="M199.6 118.8h5.6v7.5"/>
<circle cx="190.3" cy="118.8" r=".37"/>
</g>
<circle cx="205.2" cy="126.3" r=".37" fill="#000080"/>
<g fill="none" stroke="#000080" stroke-width=".17">
<path d="M154.9 105.8v3.7"/>
<circle cx="205.2" cy="126.3" r=".37"/>
</g>
<circle cx="154.9" cy="105.8" r=".37" fill="#000080"/>
<g fill="none" stroke="#000080" stroke-width=".17">
<path d="M205.2 135.6v1.8"/>
<circle cx="154.9" cy="105.8" r=".37"/>
</g>
<circle cx="205.2" cy="137.4" r=".37" fill="#000080"/>
<g fill="none" stroke="#000080" stroke-width=".17">
<path d="M218.2 107.7h-7.4v29.7h-5.6"/>
<circle cx="205.2" cy="137.4" r=".37"/>
</g>
<circle cx="205.2" cy="137.4" r=".37" fill="#000080"/>
<circle cx="205.2" cy="137.4" r=".37" fill="none" stroke="#000080" stroke-width=".17"/>
<circle cx="207" cy="137.4" r=".37" fill="#000080"/>
<circle cx="207" cy="137.4" r=".37" fill="none" stroke="#000080" stroke-width=".17"/>
<circle cx="210.8" cy="111.4" r=".38" fill="#000080"/>
<g fill="none" stroke="#000080" stroke-width=".17">
<path d="M201.4 135.6v1.8"/>
<circle cx="210.8" cy="111.4" r=".38"/>
</g>
<circle cx="201.4" cy="137.4" r=".37" fill="#000080"/>
<g fill="none" stroke="#000080" stroke-width=".17">
<path d="M199.6 137.4h5.6"/>
<circle cx="201.4" cy="137.4" r=".37"/>
</g>
<circle cx="201.4" cy="137.4" r=".37" fill="#000080"/>
<circle cx="201.4" cy="137.4" r=".37" fill="none" stroke="#000080" stroke-width=".17"/>
<circle cx="205.2" cy="137.4" r=".37" fill="#000080"/>
<g fill="none" stroke="#000080" stroke-width=".17">
<path d="M190.3 137.4v1.9"/>
<circle cx="205.2" cy="137.4" r=".37"/>
</g>
<circle cx="190.3" cy="137.4" r=".37" fill="#000080"/>
<g fill="none" stroke="#000080" stroke-width=".17">
<path d="M188.4 137.4h3.7"/>
<circle cx="190.3" cy="137.4" r=".37"/>
</g>
<circle cx="190.3" cy="137.4" r=".37" fill="#000080"/>
<g fill="none" stroke="#000080" stroke-width=".17">
<path d="M261 137.4h-9.3v1.9"/>
<circle cx="190.3" cy="137.4" r=".37"/>
</g>
<circle cx="251.7" cy="137.4" r=".37" fill="#000080"/>
<circle cx="251.7" cy="137.4" r=".37" fill="none" stroke="#000080" stroke-width=".17"/>
<circle cx="257.3" cy="137.4" r=".37" fill="#000080"/>
<g fill="none" stroke="#000080" stroke-width=".17">
<path d="M272.2 135.6v1.8h-3.7"/>
<circle cx="257.3" cy="137.4" r=".37"/>
</g>
<circle cx="270.3" cy="137.4" r=".37" fill="#000080"/>
<g fill="none" stroke="#000080" stroke-width=".17">
<path d="M264.7 92.8h-9.3v5.6h-3.7"/>
<circle cx="270.3" cy="137.4" r=".37"/>
</g>
<circle cx="255.4" cy="96.5" r=".37" fill="#000080"/>
<g fill="none" stroke="#000080" stroke-width=".17">
<path d="M270.3 137.4v1.9"/>
<circle cx="255.4" cy="96.5" r=".37"/>
</g>
<circle cx="270.3" cy="137.4" r=".37" fill="#000080"/>
<g fill="none" stroke="#000080" stroke-width=".17">
<path d="M91.6 163.5h7.4"/>
<circle cx="270.3" cy="137.4" r=".37"/>
</g>
<circle cx="99" cy="163.5" r=".37" fill="#000080"/>
<g fill="none" stroke="#000080" stroke-width=".17">
<path d="M99 163.5h7.5v1.8"/>
<circle cx="99" cy="163.5" r=".37"/>
</g>
<circle cx="99" cy="163.5" r=".37" fill="#000080"/>
<circle cx="99" cy="163.5" r=".37" fill="none" stroke="#000080" stroke-width=".17"/>
<circle cx="106.5" cy="163.5" r=".37" fill="#000080"/>
<g fill="none" stroke="#000080" stroke-width=".17">
<path d="M82.3 163.5v1.8"/>
<circle cx="106.5" cy="163.5" r=".37"/>
</g>
<circle cx="82.3" cy="163.5" r=".37" fill="#000080"/>
<g fill="none" stroke="#000080" stroke-width=".17">
<path d="M82.3 172.8v1.8"/>
<circle cx="82.3" cy="163.5" r=".37"/>
</g>
<circle cx="82.3" cy="174.6" r=".38" fill="#000080"/>
<g fill="none" stroke="#000080" stroke-width=".17">
<path d="M78.6 163.5h5.6"/>
<circle cx="82.3" cy="174.6" r=".38"/>
</g>
<circle cx="82.3" cy="163.5" r=".37" fill="#000080"/>
<g fill="none" stroke="#000080" stroke-width=".17">
<path d="M95.3 94.6h7.5v7.5h1.8M69.3 111.4h5.5"/>
<circle cx="82.3" cy="163.5" r=".37"/>
</g>
<circle cx="102.8" cy="100.2" r=".37" fill="#000080"/>
<circle cx="102.8" cy="100.2" r=".37" fill="none" stroke="#000080" stroke-width=".17"/>
<circle cx="102.8" cy="98.4" r=".37" fill="#000080"/>
<g fill="none" stroke="#000080" stroke-width=".17">
<path d="M48.8 159.7h-5.6v1.9M82.3 174.6v1.9"/>
<circle cx="102.8" cy="98.4" r=".37"/>
</g>
<circle cx="82.3" cy="174.6" r=".38" fill="#000080"/>
<g fill="none" stroke="#000080" stroke-width=".17">
<path d="M82.3 183.9v1.9"/>
<circle cx="82.3" cy="174.6" r=".38"/>
</g>
<circle cx="82.3" cy="185.8" r=".37" fill="#000080"/>
<g fill="none" stroke="#000080" stroke-width=".17">
<path d="M78.6 185.8h5.6"/>
<circle cx="82.3" cy="185.8" r=".37"/>
</g>
<circle cx="82.3" cy="185.8" r=".37" fill="#000080"/>
<g fill="none" stroke="#000080" stroke-width=".17">
<path d="M91.6 185.8h7.4"/>
<circle cx="82.3" cy="185.8" r=".37"/>
</g>
<circle cx="99" cy="185.8" r=".37" fill="#000080"/>
<g fill="none" stroke="#000080" stroke-width=".17">
<path d="M136.3 183.9v1.9h-37.3"/>
<circle cx="99" cy="185.8" r=".37"/>
</g>
<circle cx="99" cy="185.8" r=".37" fill="#000080"/>
<circle cx="99" cy="185.8" r=".37" fill="none" stroke="#000080" stroke-width=".17"/>
<circle cx="106.5" cy="185.8" r=".37" fill="#000080"/>
<circle cx="106.5" cy="185.8" r=".37" fill="none" stroke="#000080" stroke-width=".17"/>
<circle cx="113.9" cy="185.8" r=".37" fill="#000080"/>
<circle cx="113.9" cy="185.8" r=".37" fill="none" stroke="#000080" stroke-width=".17"/>
<circle cx="121.4" cy="185.8" r=".37" fill="#000080"/>
<circle cx="121.4" cy="185.8" r=".37" fill="none" stroke="#000080" stroke-width=".17"/>
<circle cx="128.8" cy="185.8" r=".37" fill="#000080"/>
<circle cx="128.8" cy="185.8" r=".37" fill="none" stroke="#000080" stroke-width=".17"/>
<circle cx="136.3" cy="185.8" r=".37" fill="#000080"/>
<g fill="none" stroke="#000080" stroke-width=".17">
<path d="M11.5 117h11.2M143.7 109.5h5.6M69.3 133.7v1.9h5.5"/>
<circle cx="136.3" cy="185.8" r=".37"/>
</g>
<circle cx="143.7" cy="109.5" r=".37" fill="#000080"/>
<g fill="none" stroke="#000080" stroke-width=".17">
<path d="M134.4 105.8h50.3"/>
<circle cx="143.7" cy="109.5" r=".37"/>
</g>
<circle cx="154.9" cy="105.8" r=".37" fill="#000080"/>
<g fill="none" stroke="#000080" stroke-width=".17">
<path d="M164.2 118.8h3.7"/>
<circle cx="154.9" cy="105.8" r=".37"/>
</g>
<circle cx="166.1" cy="118.8" r=".37" fill="#000080"/>
<g fill="none" stroke="#000080" stroke-width=".17">
<path d="M154.9 133.7v3.7"/>
<circle cx="166.1" cy="118.8" r=".37"/>
</g>
<circle cx="154.9" cy="135.6" r=".37" fill="#000080"/>
<g fill="none" stroke="#000080" stroke-width=".17">
<path d="M154.9 117v9.3"/>
<circle cx="154.9" cy="135.6" r=".37"/>
</g>
<circle cx="154.9" cy="118.8" r=".37" fill="#000080"/>
<circle cx="154.9" cy="118.8" r=".37" fill="none" stroke="#000080" stroke-width=".17"/>
<circle cx="154.9" cy="122.5" r=".37" fill="#000080"/>
<g fill="none" stroke="#000080" stroke-width=".17">
<path d="M67.4 23.9h9.3M143.7 23.9v1.9"/>
<circle cx="154.9" cy="122.5" r=".37"/>
</g>
<circle cx="143.7" cy="23.9" r=".37" fill="#000080"/>
<g fill="none" stroke="#000080" stroke-width=".17">
<path d="M99 23.9v5.6h9.4"/>
<circle cx="143.7" cy="23.9" r=".37"/>
</g>
<circle cx="99" cy="23.9" r=".37" fill="#000080"/>
<g fill="none" stroke="#000080" stroke-width=".17">
<path d="M87.9 23.9v1.9"/>
<circle cx="99" cy="23.9" r=".37"/>
</g>
<circle cx="87.9" cy="23.9" r=".37" fill="#000080"/>
<g fill="none" stroke="#000080" stroke-width=".17">
<path d="M84.2 23.9h18.6"/>
<circle cx="87.9" cy="23.9" r=".37"/>
</g>
<circle cx="87.9" cy="23.9" r=".37" fill="#000080"/>
<circle cx="87.9" cy="23.9" r=".37" fill="none" stroke="#000080" stroke-width=".17"/>
<circle cx="99" cy="23.9" r=".37" fill="#000080"/>
<g fill="none" stroke="#000080" stroke-width=".17">
<path d="M121.4 23.9h35.4"/>
<circle cx="99" cy="23.9" r=".37"/>
</g>
<circle cx="125.1" cy="23.9" r=".37" fill="#000080"/>
<circle cx="125.1" cy="23.9" r=".37" fill="none" stroke="#000080" stroke-width=".17"/>
<circle cx="136.3" cy="23.9" r=".37" fill="#000080"/>
<circle cx="136.3" cy="23.9" r=".37" fill="none" stroke="#000080" stroke-width=".17"/>
<circle cx="143.7" cy="23.9" r=".37" fill="#000080"/>
<circle cx="143.7" cy="23.9" r=".37" fill="none" stroke="#000080" stroke-width=".17"/>
<use href="#words"/>
</svg>
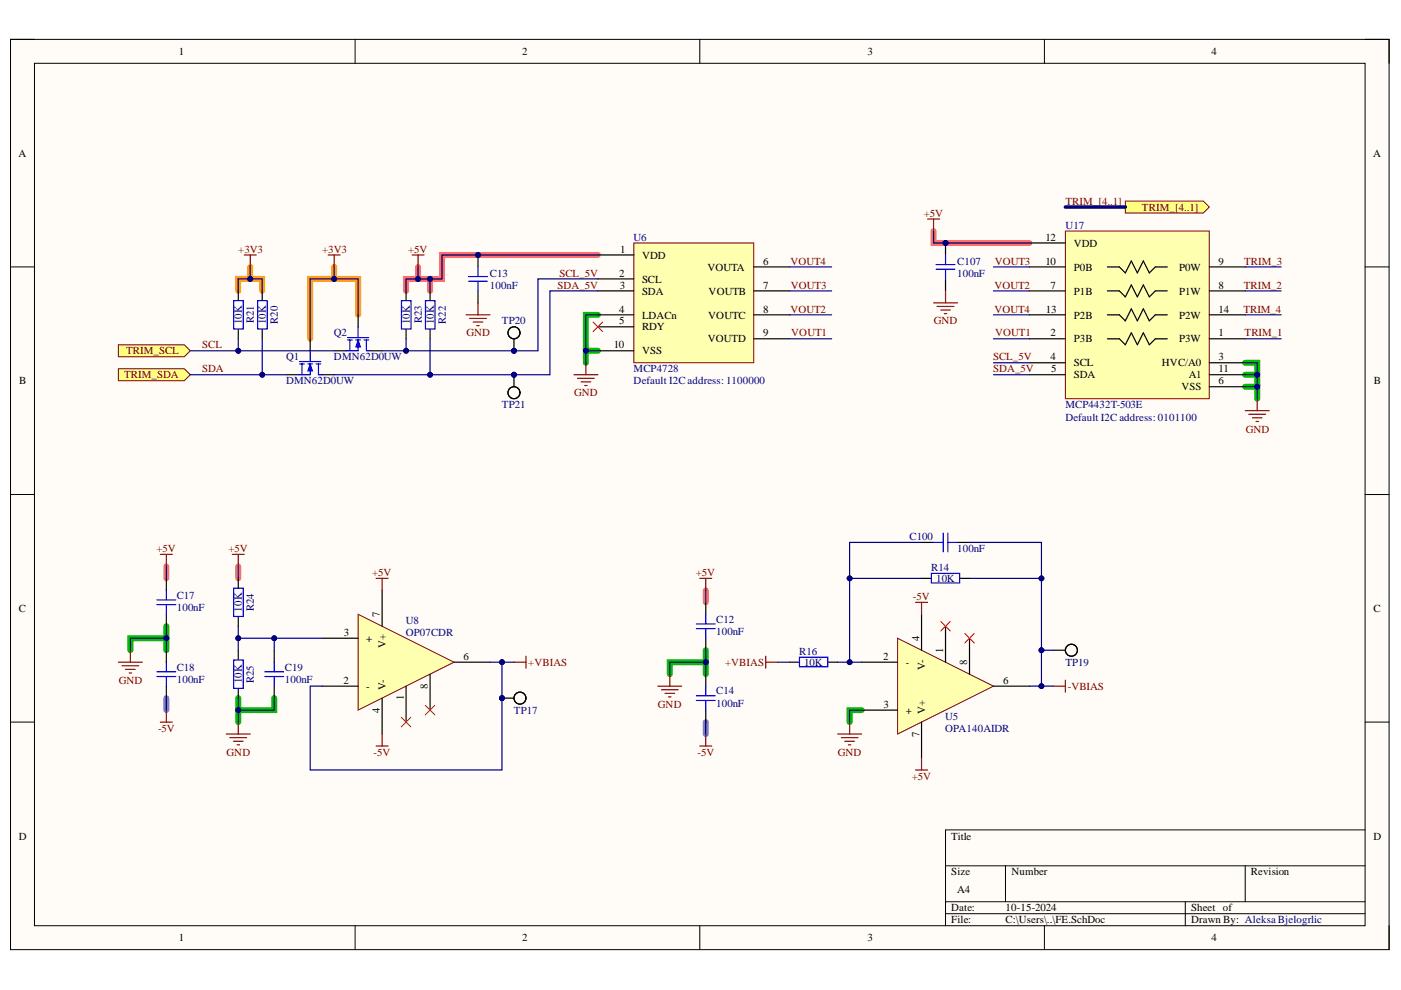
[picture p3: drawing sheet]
<svg xmlns="http://www.w3.org/2000/svg" width="297mm" height="210mm" viewBox="0 0 297 210" stroke-linecap="round" stroke-linejoin="round" font-family="sans-serif">
<defs><g id="words">
<g font-size="2.3">
<text x="37.9" y="11.7">1</text>
<text x="110.7" y="11.7">2</text>
<text x="183.9" y="11.7">3</text>
<text x="256.8" y="11.7">4</text>
<text x="3.9" y="33.3">A</text>
<text x="291.1" y="33.3">A</text>
<text x="131.5" y="53.6">1</text>
<text x="221.7" y="51">12</text>
<text x="227.7" y="52.3">VDD</text>
<text x="131.3" y="58.7">2</text>
<text x="136.1" y="54.9">VDD</text>
<text x="136.1" y="59.9">SCL</text>
<text x="150" y="57.4">VOUTA</text>
<text x="161.8" y="56.1">6</text>
<text x="221.7" y="56.1">10</text>
<text x="227.7" y="57.4">P0B</text>
<text x="250" y="57.4">P0W</text>
<text x="258.4" y="56.1">9</text>
<text x="131.4" y="61.2">3</text>
<text x="136.1" y="62.5">SDA</text>
<text x="150.2" y="62.5">VOUTB</text>
<text x="161.8" y="61.2">7</text>
<text x="222.8" y="61.2">7</text>
<text x="227.7" y="62.5">P1B</text>
<text x="250" y="62.5">P1W</text>
<text x="258.4" y="61.2">8</text>
<text x="131.3" y="66.3">4</text>
<text x="131.3" y="68.8">5</text>
<text x="136.1" y="67.5">LDACn</text>
<text x="136.1" y="70.1">RDY</text>
<text x="150.2" y="67.5">VOUTC</text>
<text x="161.8" y="66.3">8</text>
<text x="161.8" y="71.3">9</text>
<text x="221.7" y="66.3">13</text>
<text x="222.8" y="71.3">2</text>
<text x="227.7" y="67.5">P2B</text>
<text x="250" y="67.5">P2W</text>
<text x="258.4" y="66.3">14</text>
<text x="258.4" y="71.3">1</text>
<text x="130.1" y="73.9">10</text>
<text x="136.1" y="75.1">VSS</text>
<text x="150.1" y="72.6">VOUTD</text>
<text x="222.8" y="76.4">4</text>
<text x="227.7" y="77.7">SCL</text>
<text x="227.7" y="72.6">P3B</text>
<text x="246.4" y="77.7">HVC/A0</text>
<text x="250" y="72.6">P3W</text>
<text x="258.4" y="76.4">3</text>
<text x="4.1" y="81.5">B</text>
<text x="222.8" y="78.9">5</text>
<text x="227.7" y="80.2">SDA</text>
<text x="250.5" y="82.7">VSS</text>
<text x="252" y="80.2">A1</text>
<text x="258.4" y="78.9">11</text>
<text x="258.4" y="81.5">6</text>
<text x="291.3" y="81.5">B</text>
<text x="4" y="129.7">C</text>
<text x="80.5" y="130.8" transform="rotate(-90 80.5 130.8)">7</text>
<text x="291.2" y="129.7">C</text>
<text x="72.9" y="134.8">3</text>
<text x="77.7" y="136.1">+</text>
<text x="81.8" y="137.4" transform="rotate(-90 81.8 137.4)">V+</text>
<text x="194.9" y="135.8" transform="rotate(-90 194.9 135.8)">4</text>
<text x="98.3" y="139.9">6</text>
<text x="187.2" y="139.9">2</text>
<text x="192" y="141.2">-</text>
<text x="196.2" y="142" transform="rotate(-90 196.2 142)">V-</text>
<text x="200" y="138.4" transform="rotate(-90 200 138.4)">1</text>
<text x="205.1" y="140.9" transform="rotate(-90 205.1 140.9)">8</text>
<text x="72.8" y="145">2</text>
<text x="77.7" y="146.2">-</text>
<text x="81.8" y="146.2" transform="rotate(-90 81.8 146.2)">V-</text>
<text x="85.6" y="148.3" transform="rotate(-90 85.6 148.3)">1</text>
<text x="90.7" y="146" transform="rotate(-90 90.7 146)">8</text>
<text x="212.7" y="145">6</text>
<text x="80.5" y="151.1" transform="rotate(-90 80.5 151.1)">4</text>
<text x="187.3" y="150.1">3</text>
<text x="192" y="151.4">+</text>
<text x="196.2" y="151.3" transform="rotate(-90 196.2 151.3)">V+</text>
<text x="194.9" y="156.2" transform="rotate(-90 194.9 156.2)">7</text>
<text x="4" y="178">D</text>
<text x="201.7" y="178">Title</text>
<text x="291.2" y="178">D</text>
<text x="201.7" y="185.6">Size</text>
<text x="214.5" y="185.6">Number</text>
<text x="265.2" y="185.6">Revision</text>
<text x="203" y="189.4">A4</text>
<text x="201.7" y="193.2">Date:</text>
<text x="201.7" y="195.8">File:</text>
<text x="213.2" y="193.2">10-15-2024</text>
<text x="213.2" y="195.8">C:\Users\..\FE.SchDoc</text>
<text x="252.5" y="193.2">Sheet of</text>
<text x="252.5" y="195.8">Drawn By: Aleksa Bjelogrlic</text>
<text x="37.9" y="199.6">1</text>
<text x="110.7" y="199.6">2</text>
<text x="183.9" y="199.6">3</text>
<text x="256.8" y="199.6">4</text>
</g>
<g font-size="2.3" fill="#800000">
<text x="195.8" y="46">+5V</text>
<text x="225.9" y="43.4">TRIM_[4..1]</text>
<text x="242.1" y="44.7">TRIM_[4..1]</text>
<text x="50.5" y="53.6">+3V3</text>
<text x="68.3" y="53.6">+3V3</text>
<text x="86.5" y="53.6">+5V</text>
<text x="118.6" y="58.7">SCL_5V</text>
<text x="167.6" y="56.1">VOUT4</text>
<text x="210.9" y="56.1">VOUT3</text>
<text x="263.8" y="56.1">TRIM_3</text>
<text x="118.2" y="61.2">SDA_5V</text>
<text x="167.7" y="61.2">VOUT3</text>
<text x="210.8" y="61.2">VOUT2</text>
<text x="263.7" y="61.2">TRIM_2</text>
<text x="98.9" y="71.3">GND</text>
<text x="167.6" y="66.3">VOUT2</text>
<text x="167.8" y="71.3">VOUT1</text>
<text x="198" y="68.8">GND</text>
<text x="210.8" y="66.3">VOUT4</text>
<text x="211" y="71.3">VOUT1</text>
<text x="263.6" y="66.3">TRIM_4</text>
<text x="263.9" y="71.3">TRIM_1</text>
<text x="26.7" y="75.1">TRIM_SCL</text>
<text x="42.9" y="73.9">SCL</text>
<text x="210.6" y="76.4">SCL_5V</text>
<text x="26.3" y="80.2">TRIM_SDA</text>
<text x="42.9" y="78.9">SDA</text>
<text x="210.6" y="78.9">SDA_5V</text>
<text x="121.7" y="84">GND</text>
<text x="264.1" y="91.7">GND</text>
<text x="33.2" y="117.1">+5V</text>
<text x="48.5" y="117.1">+5V</text>
<text x="78.9" y="122.1">+5V</text>
<text x="147.5" y="122.1">+5V</text>
<text x="193.6" y="127.2">-5V</text>
<text x="112" y="141.2">+VBIAS</text>
<text x="153.7" y="141.2">+VBIAS</text>
<text x="25.2" y="145">GND</text>
<text x="226.4" y="146.2">-VBIAS</text>
<text x="33.5" y="155.2">-5V</text>
<text x="139.5" y="150.1">GND</text>
<text x="48.1" y="160.3">GND</text>
<text x="79.2" y="160.3">-5V</text>
<text x="147.9" y="160.3">-5V</text>
<text x="177.7" y="160.3">GND</text>
<text x="193.3" y="165.3">+5V</text>
</g>
<g font-size="2.3" fill="#000080">
<text x="134.3" y="51">U6</text>
<text x="225.9" y="48.5">U17</text>
<text x="103.9" y="58.7">C13</text>
<text x="203" y="56.1">C107</text>
<text x="203" y="58.7">100nF</text>
<text x="103.9" y="61.2">100nF</text>
<text x="51.3" y="68.7" transform="rotate(-90 51.3 68.7)">10K</text>
<text x="53.8" y="68.5" transform="rotate(-90 53.8 68.5)">R21</text>
<text x="56.3" y="68.7" transform="rotate(-90 56.3 68.7)">10K</text>
<text x="58.9" y="68.6" transform="rotate(-90 58.9 68.6)">R20</text>
<text x="70.8" y="71.3">Q2</text>
<text x="86.9" y="68.7" transform="rotate(-90 86.9 68.7)">10K</text>
<text x="89.4" y="68.5" transform="rotate(-90 89.4 68.5)">R23</text>
<text x="92" y="68.7" transform="rotate(-90 92 68.7)">10K</text>
<text x="94.5" y="68.6" transform="rotate(-90 94.5 68.6)">R22</text>
<text x="106.4" y="68.8">TP20</text>
<text x="60.7" y="76.4">Q1</text>
<text x="70.8" y="76.4">DMN62D0UW</text>
<text x="60.7" y="81.5">DMN62D0UW</text>
<text x="134.3" y="78.9">MCP4728</text>
<text x="134.3" y="81.5">Default I2C address: 1100000</text>
<text x="106.4" y="86.6">TP21</text>
<text x="225.9" y="86.6">MCP4432T-503E</text>
<text x="225.9" y="89.2">Default I2C address: 0101100</text>
<text x="192.8" y="114.5">C100</text>
<text x="203" y="117.1">100nF</text>
<text x="197.5" y="121.1">R14</text>
<text x="198.5" y="123.4">10K</text>
<text x="37.5" y="127">C17</text>
<text x="37.5" y="129.5">100nF</text>
<text x="51.3" y="129.7" transform="rotate(-90 51.3 129.7)">10K</text>
<text x="53.8" y="129.6" transform="rotate(-90 53.8 129.6)">R24</text>
<text x="86" y="132.3">U8</text>
<text x="86" y="134.8">OP07CDR</text>
<text x="151.9" y="132">C12</text>
<text x="151.9" y="134.6">100nF</text>
<text x="37.5" y="142.2">C18</text>
<text x="60.4" y="142.2">C19</text>
<text x="169.5" y="138.9">R16</text>
<text x="170.5" y="141.2">10K</text>
<text x="225.9" y="141.2">TP19</text>
<text x="37.5" y="144.7">100nF</text>
<text x="51.3" y="144.9" transform="rotate(-90 51.3 144.9)">10K</text>
<text x="53.8" y="144.8" transform="rotate(-90 53.8 144.8)">R25</text>
<text x="60.4" y="144.7">100nF</text>
<text x="151.9" y="147.2">C14</text>
<text x="151.9" y="149.9">100nF</text>
<text x="109" y="151.4">TP17</text>
<text x="200.4" y="152.7">U5</text>
<text x="200.4" y="155.2">OPA140AIDR</text>
</g>
</g></defs>
<path d="M2.2 8.3h292.3v193h-292.3z" fill-rule="evenodd" fill="#fffcf8"/>
<path d="M2.2 8.3h292.3v193h-292.3z" fill="none" stroke="#000" stroke-width=".21"/>
<path d="M7.3 13.4h282.1v182.9h-282.1z" fill-rule="evenodd" fill="#fffcf8"/>
<g fill="none" stroke="#000" stroke-width=".21">
<path d="M2.2 8.3h5.1M7.3 13.4h282.1v182.9h-282.1zM75.3 8.3v5.1M148.4 8.3v5.1M221.4 8.3v5.1M289.4 8.3h5.1v5.1M2.2 56.6h5.1M289.4 56.6h5.1M2.2 104.8h5.1M289.4 104.9h5.1M2.2 153.1h5.1M289.4 153.1h5.1"/>
<path d="M289.4 176h-88.9v20.3M75.3 196.3v5M148.4 196.3v5M200.5 183.6h88.9M200.5 191.2h88.9M200.5 193.7h88.9M213.2 183.6v7.6M221.4 196.3v5M251.3 191.2v5.1M264 183.6v7.6M294.5 196.3v5"/>
</g>
<path d="M35.3 148v2.6M149.6 153.1v2.5" fill="none" stroke="#6e6eff" stroke-width="1.3"/>
<path d="M88.6 59.1h-2.5v2.6M88.6 56.6v2.5h2.6v2.6M126.8 54.1h-33.1v5h-2.5M197.9 49v2.5h20.4M35.3 120.1v2.5M50.5 120.1v2.5M149.6 125.2v2.5" fill="none" stroke="#ff6e6e" stroke-width="1.3"/>
<path d="M126.8 74.4h-2.6v2.5M126.8 66.8h-2.6v7.6M264 76.9h2.6v5.1M264 79.5h2.6M264 82h2.6v2.5M35.3 135.3h-7.7v2.6M35.3 132.8v5.1M149.6 137.9v5M50.5 148v5.1M58.1 148v2.6h-7.6M149.6 140.4h-7.6v2.5M182.7 150.6h-2.6v2.5" fill="none" stroke="#00be00" stroke-width="1.3"/>
<path d="M53.1 59.1h-2.6v2.6M53.1 56.6v2.5h2.5v2.6M70.8 56.6v2.5M75.9 66.8v-7.7h-10.1v12.7" fill="none" stroke="#f90" stroke-width="1.3"/>
<path d="M190.3 135.3l20.3 10.2-20.3 10.1z" fill="#ffffb0"/>
<path d="M190.3 135.3l20.3 10.2-20.3 10.1z" fill="none" stroke="#800000" stroke-width=".21"/>
<g fill="none" stroke="#000" stroke-width=".25">
<path d="M195.4 115h2.5M203 115h2.6M149.6 127.7v2.5M149.6 135.3v2.6M195.4 130.2v7.7M195.4 122.6h2M200.5 132.8v7.6M203.6 122.6h2M205.6 135.3v7.6M223.3 137.9h2.6M149.6 142.9v2.6M149.6 150.6v2.5"/>
<path d="M167.4 140.4h2M175.6 140.4h2M182.7 150.6h7.6M182.7 140.4h7.6M195.4 153.1v7.6M210.6 145.5h7.7"/>
<circle cx="227.2" cy="137.9" r="1.27"/>
</g>
<path d="M199.5 131.8l2 2M201.5 131.8l-2 2M204.5 134.3l2.1 2M206.6 134.3l-2.1 2" fill="none" stroke="#f00" stroke-width=".21"/>
<g fill="none" stroke="#00f" stroke-width=".25">
<path d="M197.9 115h2.1M200 113v4M201 115h2M201 113v4M147.6 132.3h4M147.6 133.3h4M149.6 130.2v2.1M149.6 133.3v2M169.5 139.3h6v2.1h-6zM197.5 121.6h6v2h-6zM147.6 147.5h4M147.6 148.5h4"/>
<path d="M149.6 145.5v2M149.6 148.5v2.1"/>
</g>
<g fill="none" stroke="#800000" stroke-width=".25">
<path d="M148.4 122.6h2.5M149.6 122.6v2.6M162.3 139.1v2.6M194.1 127.7h2.6M195.4 127.7v2.5M139.5 145.5h5.1M140.2 146.2h3.6M141 147h2M141.8 147.8h.5M142 142.9v2.6M148.4 158.2h2.5M149.6 155.6v2.6"/>
<path d="M162.3 140.4h2.6M177.6 155.6h5.1M178.4 156.4h3.5M179.1 157.2h2.1M179.9 157.9h.5M180.1 153.1v2.5M223.3 145.5h2.6M225.9 144.2v2.5M194.1 163.3h2.6M195.4 160.7v2.6"/>
</g>
<circle cx="101.3" cy="54.1" r=".51" fill="#000080"/>
<circle cx="101.3" cy="54.1" r=".51" fill="none" stroke="#000080" stroke-width=".21"/>
<path d="M101.3 54.1v2.5M101.3 61.7v2.5" fill="none" stroke="#000" stroke-width=".25"/>
<circle cx="101.3" cy="54.1" r=".51" fill="#000080"/>
<circle cx="101.3" cy="54.1" r=".51" fill="none" stroke="#000080" stroke-width=".21"/>
<path d="M99.3 59.6h4M99.3 58.6h4M101.3 56.6v2M101.3 59.6v2.1" fill="none" stroke="#00f" stroke-width=".25"/>
<g fill="none" stroke="#800000" stroke-width=".25">
<path d="M51.8 54.1h2.5M53.1 54.1v2.5M69.6 54.1h2.5M70.8 54.1v2.5M98.8 66.8h5.1M99.6 67.5h3.5M100.3 68.3h2.1M101.1 69h.5M101.3 64.2v2.6M121.7 79.5h5.1M124.2 76.9v2.6M122.4 80.2h3.6"/>
<path d="M123.2 81h2M124 81.7h.5"/>
</g>
<path d="M25.1 73.1h14l1.2 1.3-1.2 1.2h-14z" fill-rule="evenodd" fill="#ffff80"/>
<path d="M25.1 73.1h14l1.2 1.3-1.2 1.2h-14z" fill="none" stroke="#800000" stroke-width=".21"/>
<path d="M25.1 78.2h14l1.2 1.3-1.2 1.2h-14z" fill-rule="evenodd" fill="#ffff80"/>
<path d="M25.1 78.2h14l1.2 1.3-1.2 1.2h-14z" fill="none" stroke="#800000" stroke-width=".21"/>
<path d="M134.4 51.5h25.4v25.4h-25.4z" fill-rule="evenodd" fill="#ffffb0"/>
<path d="M134.4 51.5h25.4v25.4h-25.4z" fill="none" stroke="#800000" stroke-width=".21"/>
<path d="M126.8 54.1h7.6M126.8 59.1h7.6M159.8 56.6h7.6M126.8 61.7h7.6M126.8 66.8h7.6M126.8 69.3h7.6M126.8 74.4h7.6M159.8 61.7h7.6M159.8 66.8h7.6M159.8 71.8h7.6" fill="none" stroke="#000" stroke-width=".25"/>
<path d="M125.7 68.3l2.1 2M127.8 68.3l-2.1 2" fill="none" stroke="#f00" stroke-width=".21"/>
<circle cx="109" cy="74.4" r=".51" fill="#000080"/>
<circle cx="109" cy="74.4" r=".51" fill="none" stroke="#000080" stroke-width=".21"/>
<path d="M109 71.8v2.6" fill="none" stroke="#000" stroke-width=".25"/>
<circle cx="109" cy="74.4" r=".51" fill="#000080"/>
<circle cx="109" cy="74.4" r=".51" fill="none" stroke="#000080" stroke-width=".21"/>
<circle cx="109" cy="70.6" r="1.27" fill="none" stroke="#000" stroke-width=".25"/>
<circle cx="109" cy="79.5" r=".51" fill="#000080"/>
<circle cx="109" cy="79.5" r=".51" fill="none" stroke="#000080" stroke-width=".21"/>
<path d="M109 79.5v2.5" fill="none" stroke="#000" stroke-width=".25"/>
<circle cx="109" cy="79.5" r=".51" fill="#000080"/>
<circle cx="109" cy="79.5" r=".51" fill="none" stroke="#000080" stroke-width=".21"/>
<g fill="none" stroke="#000" stroke-width=".25">
<path d="M50.5 61.7v2M50.5 69.8v2M55.6 61.7v2M55.6 69.8v2M60.7 79.5h2.5M65.8 71.8v2.6M68.3 79.5h2.5M86.1 61.7v2M86.1 69.8v2M91.2 61.7v2M91.2 69.8v2"/>
<circle cx="109" cy="83.3" r="1.27"/>
</g>
<path d="M87.4 54.1h2.5M88.6 54.1v2.5" fill="none" stroke="#800000" stroke-width=".25"/>
<path d="M49.5 63.8h2.1v6h-2.1zM54.6 63.8h2.1v6h-2.1zM63.5 76.7h4.5M63.5 77.2h1M64 77.2v2.3M65.3 77.2h1M65.8 74.4v2.3M65.8 77.2v2.3h-2.6M67 77.2h1M67.5 77.2v2.3M85.1 63.8h2.1v6h-2.1zM90.2 63.8h2v6h-2z" fill="none" stroke="#00f" stroke-width=".25"/>
<path d="M65.8 77.2l.5 1.5h-1z" fill="#00f"/>
<path d="M65.8 77.2l.5 1.5h-1z" fill="none" stroke="#00f" stroke-width=".21"/>
<path d="M67.5 79.5h.8M73.7 71.6h4.5M73.7 72.1h1M74.2 72.1v2.3M75.4 72.1h1M75.9 69.3v2.3M75.9 72.1v2.3h-2.5M77.2 72.1h1M77.7 72.1v2.3" fill="none" stroke="#00f" stroke-width=".25"/>
<path d="M70.8 74.4h2.6M75.9 66.8v2.5M78.5 74.4h2.5" fill="none" stroke="#000" stroke-width=".25"/>
<path d="M75.9 72.1l.5 1.5h-1z" fill="#00f"/>
<path d="M75.9 72.1l.5 1.5h-1z" fill="none" stroke="#00f" stroke-width=".21"/>
<path d="M77.7 74.4h.8" fill="none" stroke="#00f" stroke-width=".25"/>
<path d="M225.9 49h30.5v35.5h-30.5z" fill-rule="evenodd" fill="#ffffb0"/>
<path d="M225.9 49h30.5v35.5h-30.5z" fill="none" stroke="#800000" stroke-width=".21"/>
<g fill="none" stroke="#000" stroke-width=".25">
<path d="M218.3 51.5h7.6M218.3 56.6h7.6M234.8 56.6h2.5l1.3 1.3 1.3-2.6 1.2 2.6 1.3-2.6 1.3 2.6 1.2-1.3h2.6M256.4 56.6h7.6M218.3 76.9h7.6M218.3 79.5h7.6M218.3 61.7h7.6M218.3 66.8h7.6M218.3 71.8h7.6M234.8 61.7h2.5l1.3 1.2 1.3-2.5 1.2 2.5 1.3-2.5 1.3 2.5 1.2-1.2h2.6M234.8 66.8h2.5l1.3 1.2 1.3-2.5 1.2 2.5 1.3-2.5 1.3 2.5 1.2-1.2h2.6M234.8 71.8h2.5l1.3 1.3 1.3-2.5 1.2 2.5 1.3-2.5 1.3 2.5 1.2-1.3h2.6"/>
<path d="M256.4 76.9h7.6M256.4 79.5h7.6M256.4 61.7h7.6M256.4 66.8h7.6M256.4 71.8h7.6M256.4 82h7.6"/>
</g>
<path d="M264 87.1h5.1M264.8 87.8h3.5M265.5 88.6h2.1M266.3 89.4h.5M266.6 84.5v2.6" fill="none" stroke="#800000" stroke-width=".25"/>
<circle cx="200.5" cy="51.5" r=".51" fill="#000080"/>
<circle cx="200.5" cy="51.5" r=".51" fill="none" stroke="#000080" stroke-width=".21"/>
<path d="M200.5 51.5v2.6M200.5 59.1v2.6" fill="none" stroke="#000" stroke-width=".25"/>
<circle cx="200.5" cy="51.5" r=".51" fill="#000080"/>
<circle cx="200.5" cy="51.5" r=".51" fill="none" stroke="#000080" stroke-width=".21"/>
<path d="M198.5 57.1h4M198.5 56.1h4M200.5 54.1v2M200.5 57.1v2" fill="none" stroke="#00f" stroke-width=".25"/>
<path d="M196.7 46.4h2.5M197.9 46.4v2.6M197.9 64.2h5.1M198.7 65h3.5M199.5 65.7h2M200.2 66.5h.5M200.5 61.7v2.5" fill="none" stroke="#800000" stroke-width=".25"/>
<path d="M238.6 42.6h16.5l1.3 1.3-1.3 1.3h-16.5z" fill-rule="evenodd" fill="#ffff80"/>
<path d="M238.6 42.6h16.5l1.3 1.3-1.3 1.3h-16.5z" fill="none" stroke="#800000" stroke-width=".21"/>
<path d="M75.9 130.2l20.4 10.2-20.4 10.2z" fill="#ffffb0"/>
<path d="M75.9 130.2l20.4 10.2-20.4 10.2z" fill="none" stroke="#800000" stroke-width=".21"/>
<path d="M50.5 122.6v2M50.5 130.8v2M50.5 137.9v2M68.3 135.3h7.6M81 125.2v7.6M50.5 146v2M68.3 145.5h7.6M81 148v7.6M86.1 145.5v7.6M91.2 142.9v7.7M96.3 140.4h7.6" fill="none" stroke="#000" stroke-width=".25"/>
<path d="M85.1 152.1l2 2M87.1 152.1l-2 2M90.2 149.5l2 2.1M92.2 149.5l-2 2.1" fill="none" stroke="#f00" stroke-width=".21"/>
<path d="M49.5 124.7h2.1v6h-2.1zM49.5 139.9h2.1v6h-2.1z" fill="none" stroke="#00f" stroke-width=".25"/>
<path d="M111.5 139.1v2.6M109 140.4h2.5" fill="none" stroke="#800000" stroke-width=".25"/>
<circle cx="106.4" cy="148" r=".51" fill="#000080"/>
<circle cx="106.4" cy="148" r=".51" fill="none" stroke="#000080" stroke-width=".21"/>
<path d="M106.4 148h2.6" fill="none" stroke="#000" stroke-width=".25"/>
<circle cx="106.4" cy="148" r=".51" fill="#000080"/>
<circle cx="106.4" cy="148" r=".51" fill="none" stroke="#000080" stroke-width=".21"/>
<g fill="none" stroke="#000" stroke-width=".25">
<path d="M35.3 122.6v2.6M35.3 130.2v2.6M35.3 137.9v2.5M58.1 137.9v2.5M35.3 145.5v2.5M58.1 145.5v2.5"/>
<circle cx="110.2" cy="148" r="1.27"/>
</g>
<path d="M33.3 127.2h4M33.3 128.2h4M35.3 125.2v2M35.3 128.2v2M33.3 142.4h4M33.3 143.4h4M35.3 140.4v2M35.3 143.4v2.1M56.1 142.4h4M56.1 143.4h4M58.1 140.4v2M58.1 143.4v2.1" fill="none" stroke="#00f" stroke-width=".25"/>
<g fill="none" stroke="#800000" stroke-width=".25">
<path d="M34 117.5h2.5M35.3 117.5v2.6M49.2 117.5h2.6M50.5 117.5v2.6M27.6 137.9v2.5M79.7 122.6h2.6M81 122.6v2.6M25.1 140.4h5.1M25.9 141.2h3.5M26.6 141.9h2.1M27.4 142.7h.5M34 153.1h2.5"/>
<path d="M35.3 150.6v2.5M48 155.6h5.1M48.7 156.4h3.6M49.5 157.2h2M50.3 157.9h.5M50.5 153.1v2.5M79.7 158.2h2.6M81 155.6v2.6"/>
</g>
<path d="M149.6 125.2v2.5M149.6 140.4h-7.6v2.5M149.6 153.1v2.5" fill="none" stroke="#000080" stroke-width=".25"/>
<circle cx="149.6" cy="140.4" r=".51" fill="#000080"/>
<circle cx="149.6" cy="140.4" r=".51" fill="none" stroke="#000080" stroke-width=".21"/>
<path d="M149.6 137.9v5" fill="none" stroke="#000080" stroke-width=".25"/>
<circle cx="149.6" cy="140.4" r=".51" fill="#000080"/>
<circle cx="149.6" cy="140.4" r=".51" fill="none" stroke="#000080" stroke-width=".21"/>
<path d="M177.6 140.4h2.5M182.7 150.6h-2.6v2.5" fill="none" stroke="#000080" stroke-width=".25"/>
<circle cx="180.1" cy="140.4" r=".51" fill="#000080"/>
<circle cx="180.1" cy="140.4" r=".51" fill="none" stroke="#000080" stroke-width=".21"/>
<path d="M218.3 145.5h5" fill="none" stroke="#000080" stroke-width=".25"/>
<circle cx="220.8" cy="145.5" r=".51" fill="#000080"/>
<circle cx="220.8" cy="145.5" r=".51" fill="none" stroke="#000080" stroke-width=".21"/>
<path d="M180.1 122.6h15.3" fill="none" stroke="#000080" stroke-width=".25"/>
<circle cx="180.1" cy="122.6" r=".51" fill="#000080"/>
<circle cx="180.1" cy="122.6" r=".51" fill="none" stroke="#000080" stroke-width=".21"/>
<path d="M205.6 122.6h15.2" fill="none" stroke="#000080" stroke-width=".25"/>
<circle cx="220.8" cy="122.6" r=".51" fill="#000080"/>
<circle cx="220.8" cy="122.6" r=".51" fill="none" stroke="#000080" stroke-width=".21"/>
<path d="M195.4 115h-15.3v25.4h2.6M164.9 140.4h2.5" fill="none" stroke="#000080" stroke-width=".25"/>
<circle cx="180.1" cy="122.6" r=".51" fill="#000080"/>
<circle cx="180.1" cy="122.6" r=".51" fill="none" stroke="#000080" stroke-width=".21"/>
<circle cx="180.1" cy="140.4" r=".51" fill="#000080"/>
<circle cx="180.1" cy="140.4" r=".51" fill="none" stroke="#000080" stroke-width=".21"/>
<path d="M220.8 137.9h2.5" fill="none" stroke="#000080" stroke-width=".25"/>
<circle cx="220.8" cy="137.9" r=".51" fill="#000080"/>
<circle cx="220.8" cy="137.9" r=".51" fill="none" stroke="#000080" stroke-width=".21"/>
<path d="M205.6 115h15.2v30.5" fill="none" stroke="#000080" stroke-width=".25"/>
<circle cx="220.8" cy="122.6" r=".51" fill="#000080"/>
<circle cx="220.8" cy="122.6" r=".51" fill="none" stroke="#000080" stroke-width=".21"/>
<circle cx="220.8" cy="137.9" r=".51" fill="#000080"/>
<circle cx="220.8" cy="137.9" r=".51" fill="none" stroke="#000080" stroke-width=".21"/>
<circle cx="220.8" cy="145.5" r=".51" fill="#000080"/>
<circle cx="220.8" cy="145.5" r=".51" fill="none" stroke="#000080" stroke-width=".21"/>
<path d="M53.1 59.1h-2.6v2.6" fill="none" stroke="#000080" stroke-width=".25"/>
<circle cx="53.1" cy="59.1" r=".51" fill="#000080"/>
<circle cx="53.1" cy="59.1" r=".51" fill="none" stroke="#000080" stroke-width=".21"/>
<path d="M53.1 56.6v2.5h2.5v2.6" fill="none" stroke="#000080" stroke-width=".25"/>
<circle cx="53.1" cy="59.1" r=".51" fill="#000080"/>
<circle cx="53.1" cy="59.1" r=".51" fill="none" stroke="#000080" stroke-width=".21"/>
<path d="M88.6 59.1h-2.5v2.6" fill="none" stroke="#000080" stroke-width=".25"/>
<circle cx="88.6" cy="59.1" r=".51" fill="#000080"/>
<circle cx="88.6" cy="59.1" r=".51" fill="none" stroke="#000080" stroke-width=".21"/>
<path d="M126.8 74.4h-2.6v2.5" fill="none" stroke="#000080" stroke-width=".25"/>
<circle cx="124.2" cy="74.4" r=".51" fill="#000080"/>
<circle cx="124.2" cy="74.4" r=".51" fill="none" stroke="#000080" stroke-width=".21"/>
<path d="M126.8 66.8h-2.6v7.6" fill="none" stroke="#000080" stroke-width=".25"/>
<circle cx="124.2" cy="74.4" r=".51" fill="#000080"/>
<circle cx="124.2" cy="74.4" r=".51" fill="none" stroke="#000080" stroke-width=".21"/>
<path d="M88.6 56.6v2.5h2.6v2.6" fill="none" stroke="#000080" stroke-width=".25"/>
<circle cx="88.6" cy="59.1" r=".51" fill="#000080"/>
<circle cx="88.6" cy="59.1" r=".51" fill="none" stroke="#000080" stroke-width=".21"/>
<circle cx="91.2" cy="59.1" r=".51" fill="#000080"/>
<circle cx="91.2" cy="59.1" r=".51" fill="none" stroke="#000080" stroke-width=".21"/>
<path d="M126.8 54.1h-33.1v5h-2.5" fill="none" stroke="#000080" stroke-width=".25"/>
<circle cx="101.3" cy="54.1" r=".51" fill="#000080"/>
<circle cx="101.3" cy="54.1" r=".51" fill="none" stroke="#000080" stroke-width=".21"/>
<circle cx="91.2" cy="59.1" r=".51" fill="#000080"/>
<circle cx="91.2" cy="59.1" r=".51" fill="none" stroke="#000080" stroke-width=".21"/>
<path d="M86.1 71.8v2.6" fill="none" stroke="#000080" stroke-width=".25"/>
<circle cx="86.1" cy="74.4" r=".51" fill="#000080"/>
<circle cx="86.1" cy="74.4" r=".51" fill="none" stroke="#000080" stroke-width=".21"/>
<path d="M50.5 71.8v2.6" fill="none" stroke="#000080" stroke-width=".25"/>
<circle cx="50.5" cy="74.4" r=".51" fill="#000080"/>
<circle cx="50.5" cy="74.4" r=".51" fill="none" stroke="#000080" stroke-width=".21"/>
<path d="M70.8 56.6v2.5" fill="none" stroke="#000080" stroke-width=".25"/>
<circle cx="70.8" cy="59.1" r=".51" fill="#000080"/>
<circle cx="70.8" cy="59.1" r=".51" fill="none" stroke="#000080" stroke-width=".21"/>
<path d="M55.6 71.8v7.7h-15.3" fill="none" stroke="#000080" stroke-width=".25"/>
<circle cx="55.6" cy="79.5" r=".51" fill="#000080"/>
<circle cx="55.6" cy="79.5" r=".51" fill="none" stroke="#000080" stroke-width=".21"/>
<path d="M55.6 79.5h5.1" fill="none" stroke="#000080" stroke-width=".25"/>
<circle cx="55.6" cy="79.5" r=".51" fill="#000080"/>
<circle cx="55.6" cy="79.5" r=".51" fill="none" stroke="#000080" stroke-width=".21"/>
<path d="M126.8 61.7h-10.2v17.8h-25.4v-7.7" fill="none" stroke="#000080" stroke-width=".25"/>
<circle cx="109" cy="79.5" r=".51" fill="#000080"/>
<circle cx="109" cy="79.5" r=".51" fill="none" stroke="#000080" stroke-width=".21"/>
<circle cx="91.2" cy="79.5" r=".51" fill="#000080"/>
<circle cx="91.2" cy="79.5" r=".51" fill="none" stroke="#000080" stroke-width=".21"/>
<path d="M70.8 79.5h20.4" fill="none" stroke="#000080" stroke-width=".25"/>
<circle cx="91.2" cy="79.5" r=".51" fill="#000080"/>
<circle cx="91.2" cy="79.5" r=".51" fill="none" stroke="#000080" stroke-width=".21"/>
<path d="M75.9 66.8v-7.7h-10.1v12.7" fill="none" stroke="#000080" stroke-width=".25"/>
<circle cx="70.8" cy="59.1" r=".51" fill="#000080"/>
<circle cx="70.8" cy="59.1" r=".51" fill="none" stroke="#000080" stroke-width=".21"/>
<path d="M167.4 56.6h8.9M40.3 74.4h30.5" fill="none" stroke="#000080" stroke-width=".25"/>
<circle cx="50.5" cy="74.4" r=".51" fill="#000080"/>
<circle cx="50.5" cy="74.4" r=".51" fill="none" stroke="#000080" stroke-width=".21"/>
<path d="M126.8 59.1h-12.7v15.3h-33.1M167.4 71.8h8.9M167.4 66.8h8.9M167.4 61.7h8.9" fill="none" stroke="#000080" stroke-width=".25"/>
<circle cx="109" cy="74.4" r=".51" fill="#000080"/>
<circle cx="109" cy="74.4" r=".51" fill="none" stroke="#000080" stroke-width=".21"/>
<circle cx="86.1" cy="74.4" r=".51" fill="#000080"/>
<circle cx="86.1" cy="74.4" r=".51" fill="none" stroke="#000080" stroke-width=".21"/>
<path d="M264 61.7h7.6M264 82h2.6v2.5" fill="none" stroke="#000080" stroke-width=".25"/>
<circle cx="266.6" cy="82" r=".51" fill="#000080"/>
<circle cx="266.6" cy="82" r=".51" fill="none" stroke="#000080" stroke-width=".21"/>
<path d="M264 76.9h2.6v5.1" fill="none" stroke="#000080" stroke-width=".25"/>
<circle cx="266.6" cy="79.5" r=".51" fill="#000080"/>
<circle cx="266.6" cy="79.5" r=".51" fill="none" stroke="#000080" stroke-width=".21"/>
<circle cx="266.6" cy="82" r=".51" fill="#000080"/>
<circle cx="266.6" cy="82" r=".51" fill="none" stroke="#000080" stroke-width=".21"/>
<path d="M264 79.5h2.6" fill="none" stroke="#000080" stroke-width=".25"/>
<circle cx="266.6" cy="79.5" r=".51" fill="#000080"/>
<circle cx="266.6" cy="79.5" r=".51" fill="none" stroke="#000080" stroke-width=".21"/>
<path d="M197.9 49v2.5h20.4M210.6 76.9h7.7M210.6 79.5h7.7" fill="none" stroke="#000080" stroke-width=".25"/>
<circle cx="200.5" cy="51.5" r=".51" fill="#000080"/>
<circle cx="200.5" cy="51.5" r=".51" fill="none" stroke="#000080" stroke-width=".21"/>
<path d="M210.6 56.6h7.7M264 56.6h7.6M210.6 61.7h7.7M210.6 71.8h7.7M210.6 66.8h7.7M264 71.8h7.6M264 66.8h7.6M50.5 120.1v2.5M103.9 140.4h2.5v22.9h-40.6v-17.8h2.5" fill="none" stroke="#000080" stroke-width=".25"/>
<circle cx="106.4" cy="140.4" r=".51" fill="#000080"/>
<circle cx="106.4" cy="140.4" r=".51" fill="none" stroke="#000080" stroke-width=".21"/>
<circle cx="106.4" cy="148" r=".51" fill="#000080"/>
<circle cx="106.4" cy="148" r=".51" fill="none" stroke="#000080" stroke-width=".21"/>
<path d="M50.5 148v5.1" fill="none" stroke="#000080" stroke-width=".25"/>
<circle cx="50.5" cy="150.6" r=".51" fill="#000080"/>
<circle cx="50.5" cy="150.6" r=".51" fill="none" stroke="#000080" stroke-width=".21"/>
<path d="M50.5 132.8v5.1" fill="none" stroke="#000080" stroke-width=".25"/>
<circle cx="50.5" cy="135.3" r=".51" fill="#000080"/>
<circle cx="50.5" cy="135.3" r=".51" fill="none" stroke="#000080" stroke-width=".21"/>
<path d="M35.3 135.3h-7.7v2.6M35.3 120.1v2.5M35.3 148v2.6" fill="none" stroke="#000080" stroke-width=".25"/>
<circle cx="35.3" cy="135.3" r=".51" fill="#000080"/>
<circle cx="35.3" cy="135.3" r=".51" fill="none" stroke="#000080" stroke-width=".21"/>
<path d="M35.3 132.8v5.1" fill="none" stroke="#000080" stroke-width=".25"/>
<circle cx="35.3" cy="135.3" r=".51" fill="#000080"/>
<circle cx="35.3" cy="135.3" r=".51" fill="none" stroke="#000080" stroke-width=".21"/>
<path d="M58.1 135.3v2.6" fill="none" stroke="#000080" stroke-width=".25"/>
<circle cx="58.1" cy="135.3" r=".51" fill="#000080"/>
<circle cx="58.1" cy="135.3" r=".51" fill="none" stroke="#000080" stroke-width=".21"/>
<path d="M106.4 140.4h2.6" fill="none" stroke="#000080" stroke-width=".25"/>
<circle cx="106.4" cy="140.4" r=".51" fill="#000080"/>
<circle cx="106.4" cy="140.4" r=".51" fill="none" stroke="#000080" stroke-width=".21"/>
<path d="M50.5 135.3h17.8" fill="none" stroke="#000080" stroke-width=".25"/>
<circle cx="50.5" cy="135.3" r=".51" fill="#000080"/>
<circle cx="50.5" cy="135.3" r=".51" fill="none" stroke="#000080" stroke-width=".21"/>
<circle cx="58.1" cy="135.3" r=".51" fill="#000080"/>
<circle cx="58.1" cy="135.3" r=".51" fill="none" stroke="#000080" stroke-width=".21"/>
<path d="M58.1 148v2.6h-7.6" fill="none" stroke="#000080" stroke-width=".25"/>
<circle cx="50.5" cy="150.6" r=".51" fill="#000080"/>
<circle cx="50.5" cy="150.6" r=".51" fill="none" stroke="#000080" stroke-width=".21"/>
<path d="M225.9 43.9h12.7" fill="none" stroke="#000080" stroke-width=".76"/>
<use href="#words"/>
</svg>
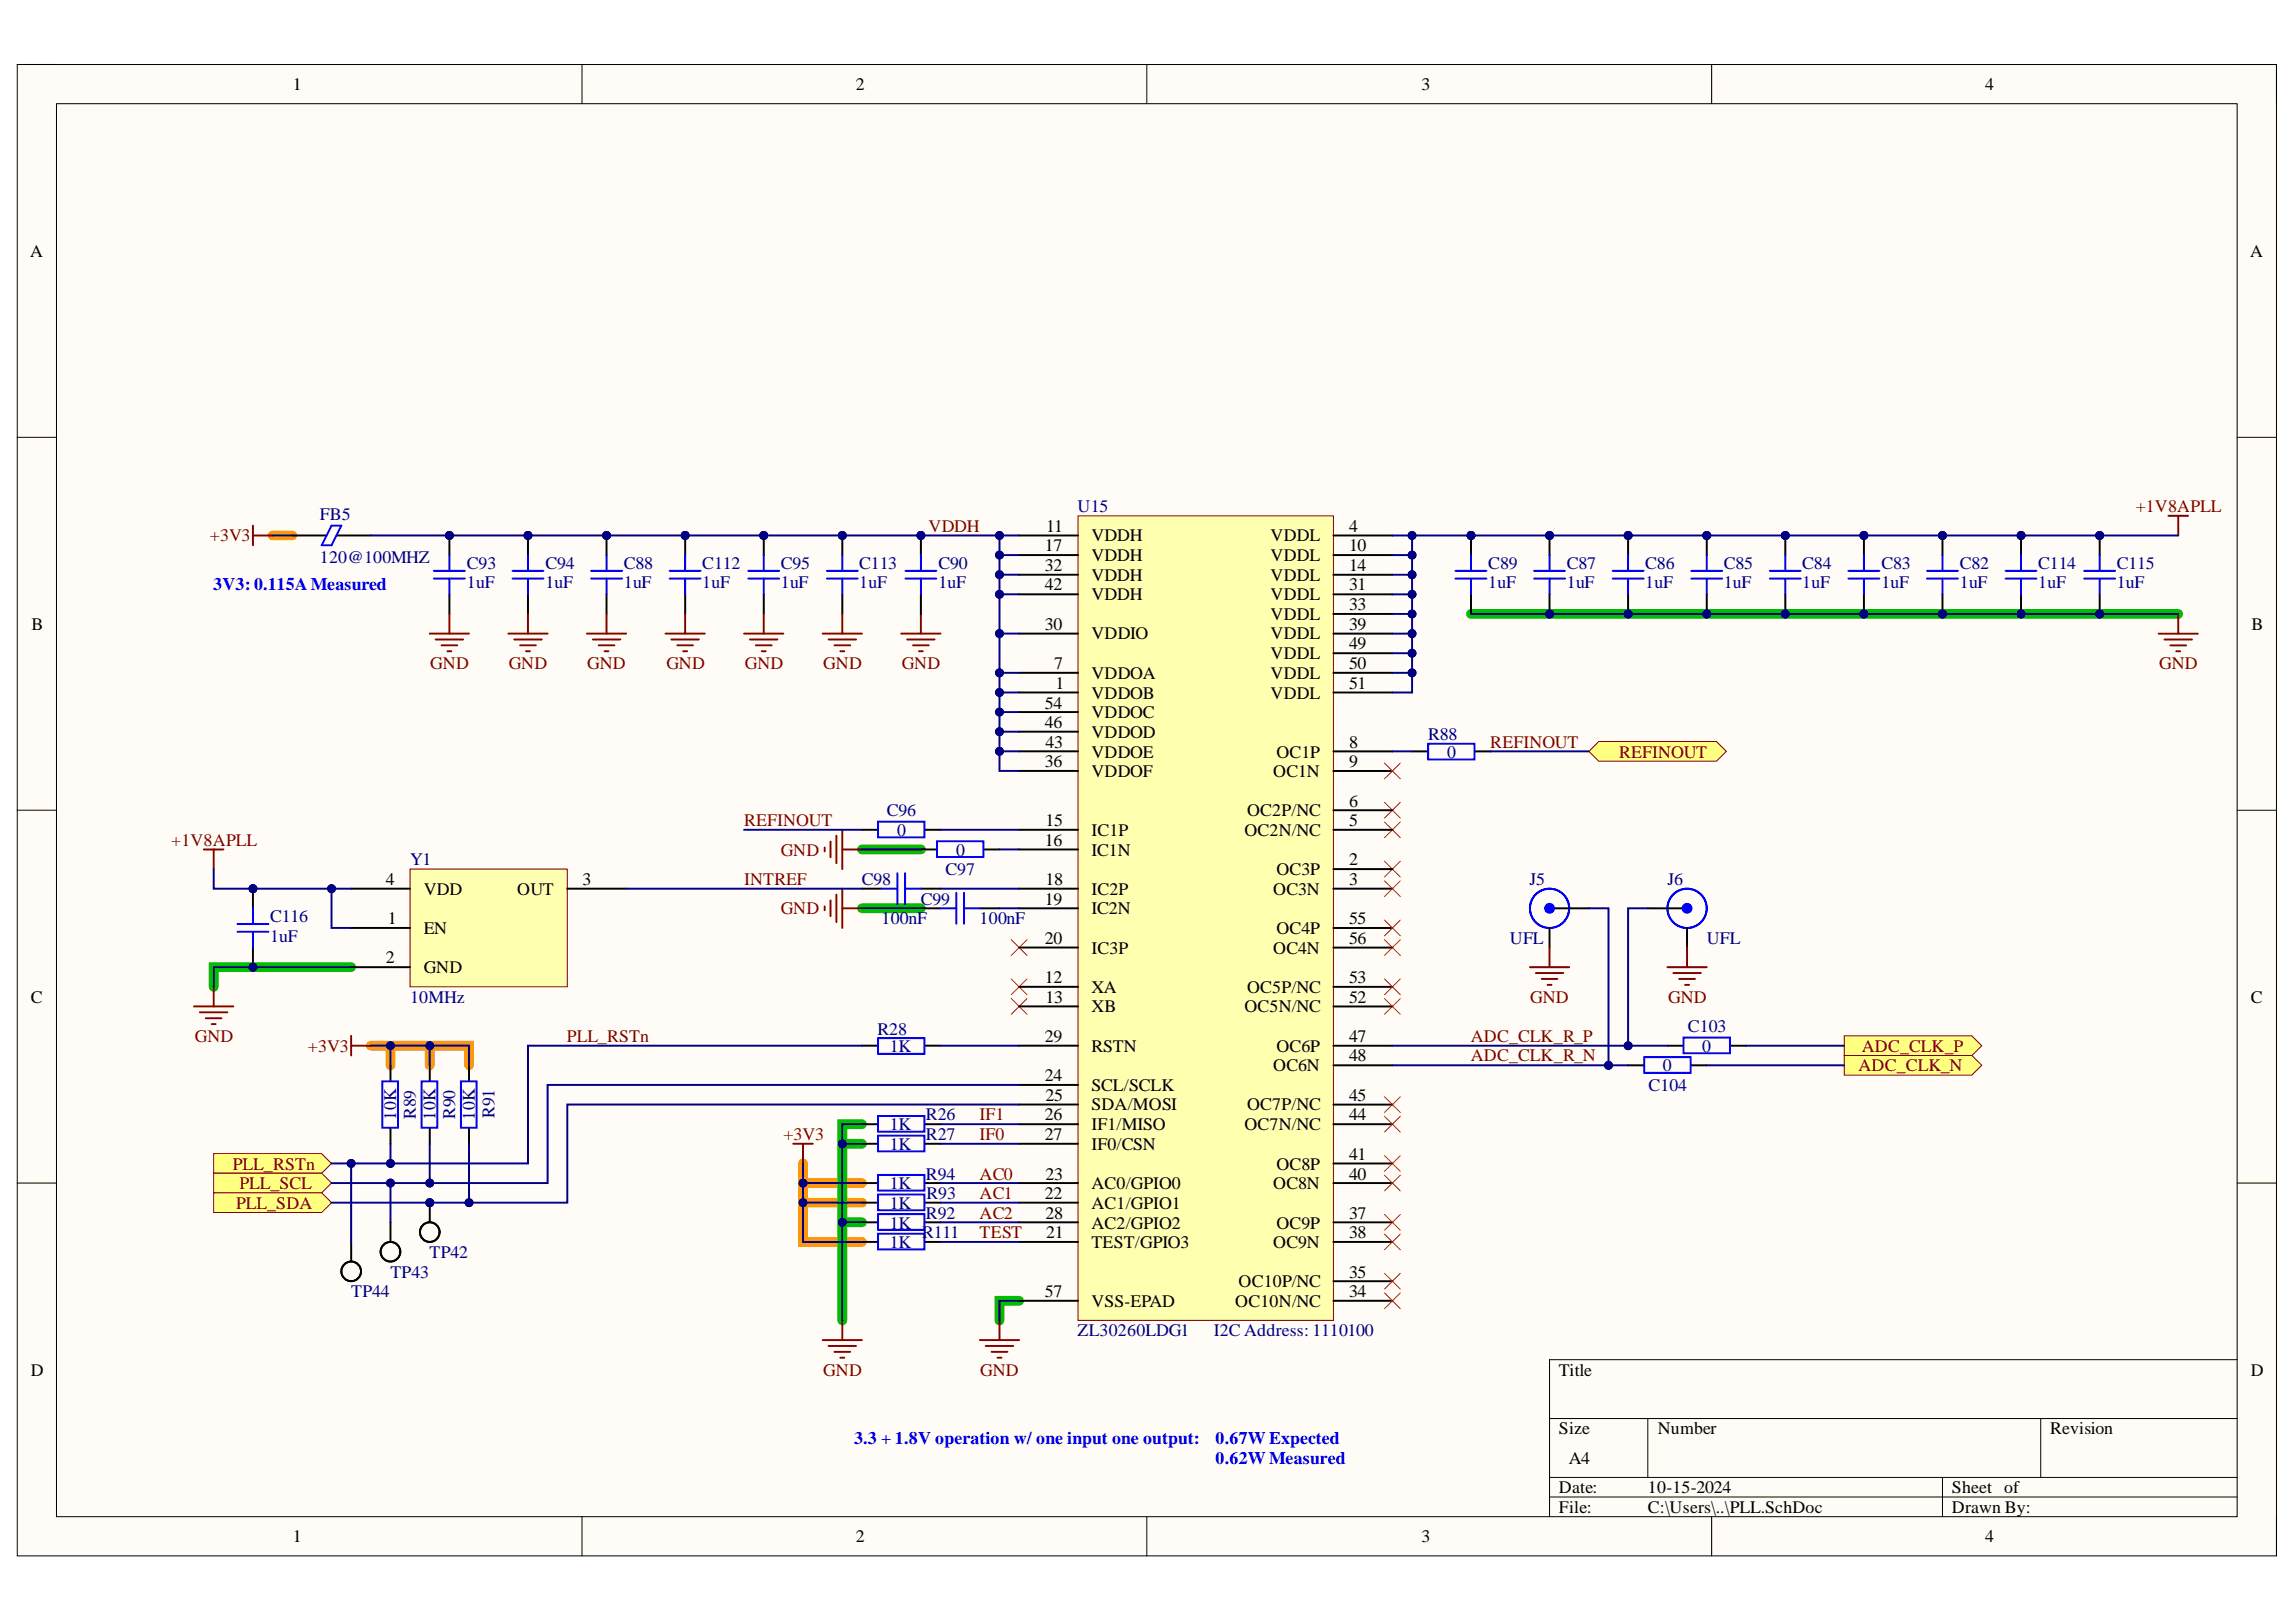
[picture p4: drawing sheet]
<svg xmlns="http://www.w3.org/2000/svg" width="297mm" height="210mm" viewBox="0 0 297 210" stroke-linecap="round" stroke-linejoin="round" font-family="sans-serif">
<defs><g id="words">
<g font-size="2.3">
<text x="37.9" y="11.7">1</text>
<text x="110.7" y="11.7">2</text>
<text x="183.9" y="11.7">3</text>
<text x="256.8" y="11.7">4</text>
<text x="3.9" y="33.3">A</text>
<text x="291.1" y="33.3">A</text>
<text x="135.2" y="71.3">17</text>
<text x="135.4" y="68.8">11</text>
<text x="141.2" y="70.1">VDDH</text>
<text x="164.4" y="70.1">VDDL</text>
<text x="174.5" y="68.8">4</text>
<text x="174.5" y="71.3">10</text>
<text x="135.2" y="73.9">32</text>
<text x="135.2" y="76.4">42</text>
<text x="141.2" y="72.6">VDDH</text>
<text x="141.2" y="75.1">VDDH</text>
<text x="141.2" y="77.7">VDDH</text>
<text x="164.4" y="72.6">VDDL</text>
<text x="164.4" y="75.1">VDDL</text>
<text x="164.4" y="77.7">VDDL</text>
<text x="174.5" y="73.9">14</text>
<text x="174.5" y="76.4">31</text>
<text x="4.1" y="81.5">B</text>
<text x="135.2" y="81.5">30</text>
<text x="141.2" y="82.7">VDDIO</text>
<text x="164.4" y="80.2">VDDL</text>
<text x="164.4" y="82.7">VDDL</text>
<text x="174.5" y="78.9">33</text>
<text x="174.5" y="81.5">39</text>
<text x="291.3" y="81.5">B</text>
<text x="136.4" y="86.6">7</text>
<text x="136.5" y="89.2">1</text>
<text x="141.2" y="87.8">VDDOA</text>
<text x="164.4" y="85.3">VDDL</text>
<text x="164.4" y="87.8">VDDL</text>
<text x="174.5" y="84">49</text>
<text x="174.5" y="86.6">50</text>
<text x="174.5" y="89.2">51</text>
<text x="135.2" y="91.7">54</text>
<text x="135.2" y="94.2">46</text>
<text x="141.2" y="90.4">VDDOB</text>
<text x="141.2" y="93">VDDOC</text>
<text x="141.2" y="95.5">VDDOD</text>
<text x="164.4" y="90.4">VDDL</text>
<text x="135.2" y="99.3">36</text>
<text x="135.3" y="96.8">43</text>
<text x="141.2" y="98">VDDOE</text>
<text x="141.2" y="100.6">VDDOF</text>
<text x="164.7" y="100.6">OC1N</text>
<text x="165.1" y="98">OC1P</text>
<text x="174.5" y="99.3">9</text>
<text x="174.5" y="96.8">8</text>
<text x="135.3" y="106.9">15</text>
<text x="161.3" y="105.7">OC2P/NC</text>
<text x="174.5" y="104.4">6</text>
<text x="174.5" y="106.9">5</text>
<text x="135.2" y="109.5">16</text>
<text x="141.2" y="110.7">IC1N</text>
<text x="141.2" y="108.2">IC1P</text>
<text x="161" y="108.2">OC2N/NC</text>
<text x="165.1" y="113.3">OC3P</text>
<text x="174.5" y="112">2</text>
<text x="49.9" y="114.5">4</text>
<text x="50.2" y="119.6">1</text>
<text x="54.8" y="115.8">VDD</text>
<text x="66.9" y="115.8">OUT</text>
<text x="75.4" y="114.5">3</text>
<text x="135.2" y="117.1">19</text>
<text x="135.3" y="114.5">18</text>
<text x="141.2" y="118.3">IC2N</text>
<text x="141.2" y="115.8">IC2P</text>
<text x="164.7" y="115.8">OC3N</text>
<text x="174.5" y="114.5">3</text>
<text x="174.5" y="119.6">55</text>
<text x="49.9" y="124.7">2</text>
<text x="54.8" y="125.9">GND</text>
<text x="54.8" y="120.9">EN</text>
<text x="135.2" y="122.1">20</text>
<text x="141.2" y="123.4">IC3P</text>
<text x="164.7" y="123.4">OC4N</text>
<text x="165.1" y="120.9">OC4P</text>
<text x="174.5" y="122.1">56</text>
<text x="4" y="129.7">C</text>
<text x="135.2" y="127.2">12</text>
<text x="135.3" y="129.7">13</text>
<text x="141.2" y="128.5">XA</text>
<text x="141.2" y="131">XB</text>
<text x="161" y="131">OC5N/NC</text>
<text x="161.3" y="128.5">OC5P/NC</text>
<text x="174.5" y="127.2">53</text>
<text x="174.5" y="129.7">52</text>
<text x="291.2" y="129.7">C</text>
<text x="135.2" y="134.8">29</text>
<text x="141.2" y="136.1">RSTN</text>
<text x="165.1" y="136.1">OC6P</text>
<text x="174.5" y="137.4">48</text>
<text x="174.5" y="134.8">47</text>
<text x="135.2" y="139.9">24</text>
<text x="135.3" y="142.4">25</text>
<text x="141.2" y="143.7">SDA/MOSI</text>
<text x="141.2" y="141.2">SCL/SCLK</text>
<text x="161.3" y="143.7">OC7P/NC</text>
<text x="164.7" y="138.6">OC6N</text>
<text x="174.5" y="142.4">45</text>
<text x="135.2" y="145">26</text>
<text x="135.2" y="147.5">27</text>
<text x="141.2" y="146.2">IF1/MISO</text>
<text x="141.2" y="148.9">IF0/CSN</text>
<text x="161" y="146.2">OC7N/NC</text>
<text x="174.5" y="145">44</text>
<text x="135.2" y="155.2">22</text>
<text x="135.3" y="152.7">23</text>
<text x="141.2" y="153.9">AC0/GPIO0</text>
<text x="164.7" y="153.9">OC8N</text>
<text x="165.1" y="151.4">OC8P</text>
<text x="174.5" y="150.1">41</text>
<text x="174.5" y="152.7">40</text>
<text x="135.3" y="157.7">28</text>
<text x="135.4" y="160.3">21</text>
<text x="141.2" y="159">AC2/GPIO2</text>
<text x="141.2" y="156.5">AC1/GPIO1</text>
<text x="141.2" y="161.5">TEST/GPIO3</text>
<text x="164.7" y="161.5">OC9N</text>
<text x="165.1" y="159">OC9P</text>
<text x="174.5" y="160.3">38</text>
<text x="174.5" y="157.7">37</text>
<text x="135.2" y="167.9">57</text>
<text x="160.2" y="166.6">OC10P/NC</text>
<text x="174.5" y="167.9">34</text>
<text x="174.5" y="165.3">35</text>
<text x="141.2" y="169.1">VSS-EPAD</text>
<text x="159.8" y="169.1">OC10N/NC</text>
<text x="4" y="178">D</text>
<text x="201.7" y="178">Title</text>
<text x="291.2" y="178">D</text>
<text x="201.7" y="185.6">Size</text>
<text x="214.5" y="185.6">Number</text>
<text x="265.2" y="185.6">Revision</text>
<text x="203" y="189.4">A4</text>
<text x="201.7" y="193.2">Date:</text>
<text x="201.7" y="195.8">File:</text>
<text x="213.2" y="193.2">10-15-2024</text>
<text x="213.2" y="195.8">C:\Users\..\PLL.SchDoc</text>
<text x="252.5" y="193.2">Sheet of</text>
<text x="252.5" y="195.8">Drawn By:</text>
<text x="37.9" y="199.6">1</text>
<text x="110.7" y="199.6">2</text>
<text x="183.9" y="199.6">3</text>
<text x="256.8" y="199.6">4</text>
</g>
<g font-size="2.3" fill="#800000">
<text x="27.2" y="70.1">+3V3</text>
<text x="120.1" y="68.8">VDDH</text>
<text x="276.3" y="66.3">+1V8APLL</text>
<text x="55.7" y="86.6">GND</text>
<text x="65.8" y="86.6">GND</text>
<text x="76" y="86.6">GND</text>
<text x="86.2" y="86.6">GND</text>
<text x="96.4" y="86.6">GND</text>
<text x="106.5" y="86.6">GND</text>
<text x="116.7" y="86.6">GND</text>
<text x="279.3" y="86.6">GND</text>
<text x="192.8" y="96.8">REFINOUT</text>
<text x="209.5" y="98">REFINOUT</text>
<text x="96.3" y="106.9">REFINOUT</text>
<text x="22.2" y="109.5">+1V8APLL</text>
<text x="101" y="110.7">GND</text>
<text x="96.3" y="114.5">INTREF</text>
<text x="101" y="118.3">GND</text>
<text x="198" y="129.7">GND</text>
<text x="215.8" y="129.7">GND</text>
<text x="25.2" y="134.8">GND</text>
<text x="39.8" y="136.1">+3V3</text>
<text x="73.3" y="134.8">PLL_RSTn</text>
<text x="190.3" y="134.8">ADC_CLK_R_P</text>
<text x="190.3" y="137.4">ADC_CLK_R_N</text>
<text x="240.9" y="136.1">ADC_CLK_P</text>
<text x="240.4" y="138.6">ADC_CLK_N</text>
<text x="101.4" y="147.5">+3V3</text>
<text x="126.7" y="147.5">IF0</text>
<text x="126.7" y="145">IF1</text>
<text x="30.1" y="151.4">PLL_RSTn</text>
<text x="31" y="153.9">PLL_SCL</text>
<text x="126.7" y="155.2">AC1</text>
<text x="126.7" y="152.7">AC0</text>
<text x="30.5" y="156.5">PLL_SDA</text>
<text x="126.7" y="160.3">TEST</text>
<text x="126.7" y="157.7">AC2</text>
<text x="106.5" y="178">GND</text>
<text x="126.8" y="178">GND</text>
</g>
<g font-size="2.3" fill="#000080">
<text x="41.4" y="67.3">FB5</text>
<text x="139.4" y="66.3">U15</text>
<text x="41.4" y="72.9">120@100MHZ</text>
<text x="60.4" y="73.6">C93</text>
<text x="60.4" y="76.2">1uF</text>
<text x="70.6" y="73.6">C94</text>
<text x="70.6" y="76.2">1uF</text>
<text x="80.7" y="73.6">C88</text>
<text x="80.7" y="76.2">1uF</text>
<text x="90.9" y="73.6">C112</text>
<text x="90.9" y="76.2">1uF</text>
<text x="101" y="73.6">C95</text>
<text x="101" y="76.2">1uF</text>
<text x="111.2" y="73.6">C113</text>
<text x="111.2" y="76.2">1uF</text>
<text x="121.4" y="73.6">C90</text>
<text x="121.4" y="76.2">1uF</text>
<text x="192.5" y="73.6">C89</text>
<text x="192.5" y="76.2">1uF</text>
<text x="202.7" y="73.6">C87</text>
<text x="202.7" y="76.2">1uF</text>
<text x="212.9" y="73.6">C86</text>
<text x="212.9" y="76.2">1uF</text>
<text x="223" y="73.6">C85</text>
<text x="223" y="76.2">1uF</text>
<text x="233.2" y="73.6">C84</text>
<text x="233.2" y="76.2">1uF</text>
<text x="243.4" y="73.6">C83</text>
<text x="243.4" y="76.2">1uF</text>
<text x="253.5" y="73.6">C82</text>
<text x="253.5" y="76.2">1uF</text>
<text x="263.7" y="73.6">C114</text>
<text x="263.7" y="76.2">1uF</text>
<text x="273.8" y="73.6">C115</text>
<text x="273.8" y="76.2">1uF</text>
<text x="184.8" y="95.8">R88</text>
<text x="187.2" y="98">0</text>
<text x="114.7" y="105.7">C96</text>
<text x="53" y="112">Y1</text>
<text x="116.1" y="108.2">0</text>
<text x="122.3" y="113.3">C97</text>
<text x="123.7" y="110.7">0</text>
<text x="34.9" y="119.4">C116</text>
<text x="111.5" y="114.5">C98</text>
<text x="114" y="119.6">100nF</text>
<text x="119.1" y="117.1">C99</text>
<text x="126.7" y="119.6">100nF</text>
<text x="197.9" y="114.5">J5</text>
<text x="215.7" y="114.5">J6</text>
<text x="34.9" y="121.9">1uF</text>
<text x="195.3" y="122.1">UFL</text>
<text x="220.8" y="122.1">UFL</text>
<text x="53" y="129.7">10MHz</text>
<text x="113.5" y="133.9">R28</text>
<text x="115.1" y="136.1">1K</text>
<text x="218.4" y="133.6">C103</text>
<text x="220.2" y="136.1">0</text>
<text x="213.3" y="141.2">C104</text>
<text x="215.1" y="138.6">0</text>
<text x="51.3" y="144.9" transform="rotate(-90 51.3 144.9)">10K</text>
<text x="53.8" y="144.8" transform="rotate(-90 53.8 144.8)">R89</text>
<text x="56.3" y="144.9" transform="rotate(-90 56.3 144.9)">10K</text>
<text x="58.9" y="144.8" transform="rotate(-90 58.9 144.8)">R90</text>
<text x="61.4" y="144.9" transform="rotate(-90 61.4 144.9)">10K</text>
<text x="64" y="144.7" transform="rotate(-90 64 144.7)">R91</text>
<text x="115.1" y="146.2">1K</text>
<text x="115.1" y="148.9">1K</text>
<text x="119.8" y="145">R26</text>
<text x="119.8" y="147.5">R27</text>
<text x="115.1" y="153.9">1K</text>
<text x="119.8" y="152.7">R94</text>
<text x="119.9" y="155.2">R93</text>
<text x="115.1" y="159">1K</text>
<text x="115.1" y="156.5">1K</text>
<text x="115.1" y="161.5">1K</text>
<text x="119.3" y="160.3">R111</text>
<text x="119.8" y="157.7">R92</text>
<text x="45.4" y="167.9">TP44</text>
<text x="50.5" y="165.3">TP43</text>
<text x="55.6" y="162.8">TP42</text>
<text x="139.4" y="172.9">ZL30260LDG1</text>
<text x="157" y="172.9">I2C Address: 1110100</text>
</g>
<g font-size="2.3" fill="#00f">
<text x="27.6" y="76.4">3V3: 0.115AMeasured</text>
<text x="110.5" y="186.9">3.3 + 1.8V operation w/ one input one output:</text>
<text x="157.3" y="189.4">0.62W Measured</text>
<text x="157.3" y="186.9">0.67W Expected</text>
</g>
</g></defs>
<path d="M2.2 8.3h292.3v193h-292.3z" fill-rule="evenodd" fill="#fffcf8"/>
<path d="M2.2 8.3h292.3v193h-292.3z" fill="none" stroke="#000" stroke-width=".13"/>
<path d="M7.3 13.4h282.1v182.9h-282.1z" fill-rule="evenodd" fill="#fffcf8"/>
<g fill="none" stroke="#000" stroke-width=".13">
<path d="M2.2 8.3h5.1M7.3 13.4h282.1v182.9h-282.1zM75.3 8.3v5.1M148.4 8.3v5.1M221.4 8.3v5.1M289.4 8.3h5.1v5.1M2.2 56.6h5.1M289.4 56.6h5.1M2.2 104.8h5.1M289.4 104.9h5.1M2.2 153.1h5.1M289.4 153.1h5.1"/>
<path d="M289.4 176h-88.9v20.3M75.3 196.3v5M148.4 196.3v5M200.5 183.6h88.9M200.5 191.2h88.9M200.5 193.7h88.9M213.2 183.6v7.6M221.4 196.3v5M251.3 191.2v5.1M264 183.6v7.6M294.5 196.3v5"/>
</g>
<path d="M190.3 79.5h91.5M111.5 109.9h7.6M111.5 117.5h7.6M45.4 125.2h-17.8v2.5M109 148h2.5M109 158.2h2.5M111.5 145.5h-2.5v25.4M131.8 168.3h-2.5v2.6" fill="none" stroke="#00be00" stroke-width="1.3"/>
<path d="M35.3 69.3h2.5M48 135.3h12.7v2.6M50.5 135.3v2.6M55.6 135.3v2.6M103.9 150.6v2.5h7.6M103.9 153.1v2.5h7.6M103.9 155.6v5.1h7.6" fill="none" stroke="#f90" stroke-width="1.3"/>
<path d="M55.6 137.9v2M60.7 137.9v2M55.6 146v2M60.7 146v2" fill="none" stroke="#000" stroke-width=".25"/>
<path d="M54.5 139.9h2.1v6h-2.1zM59.6 139.9h2.1v6h-2.1z" fill="none" stroke="#00f" stroke-width=".25"/>
<path d="M45.4 134v2.6M45.4 135.3h2.6" fill="none" stroke="#800000" stroke-width=".25"/>
<path d="M27.6 149.3h14l1.3 1.3-1.3 1.2h-14z" fill-rule="evenodd" fill="#ffff80"/>
<path d="M27.6 149.3h14l1.3 1.3-1.3 1.2h-14z" fill="none" stroke="#800000" stroke-width=".13"/>
<circle cx="55.6" cy="155.6" r=".51" fill="#000080"/>
<circle cx="55.6" cy="155.6" r=".51" fill="none" stroke="#000080" stroke-width=".13"/>
<path d="M55.6 155.6v2.6" fill="none" stroke="#000" stroke-width=".25"/>
<circle cx="55.6" cy="155.6" r=".51" fill="#000080"/>
<circle cx="55.6" cy="155.6" r=".51" fill="none" stroke="#000080" stroke-width=".13"/>
<circle cx="55.6" cy="159.4" r="1.27" fill="none" stroke="#000" stroke-width=".25"/>
<path d="M126.8 173.4h5M127.5 174.2h3.6M128.3 174.9h2M129.1 175.7h.5M129.3 170.9v2.5" fill="none" stroke="#800000" stroke-width=".25"/>
<path d="M27.6 151.8h14l1.3 1.3-1.3 1.3h-14z" fill-rule="evenodd" fill="#ffff80"/>
<path d="M27.6 151.8h14l1.3 1.3-1.3 1.3h-14z" fill="none" stroke="#800000" stroke-width=".13"/>
<path d="M27.6 154.4h14l1.3 1.2-1.3 1.3h-14z" fill-rule="evenodd" fill="#ffff80"/>
<path d="M27.6 154.4h14l1.3 1.2-1.3 1.3h-14z" fill="none" stroke="#800000" stroke-width=".13"/>
<g fill="none" stroke="#000" stroke-width=".25">
<path d="M37.8 69.3h4.5M43.5 69.3h4.5M111.5 107.4h2M119.1 109.9h2M119.7 107.4h2M127.3 109.9h2M50.5 137.9v2M50.5 146v2M50.5 158.2v2.5M111.5 158.2h2M111.5 155.6h2M111.5 153.1h2"/>
<path d="M119.7 158.2h2M119.7 155.6h2M119.7 153.1h2M45.4 160.7v2.6"/>
<circle cx="45.4" cy="164.5" r="1.27"/>
<circle cx="50.5" cy="162" r="1.27"/>
</g>
<path d="M42.9 68h1.3l-1.3 2.6h-1.3zM113.6 106.3h6v2.1h-6zM121.2 108.9h6v2h-6zM49.5 139.9h2v6h-2zM113.6 157.1h6v2.1h-6zM113.6 154.6h6v2h-6zM113.6 152h6v2.1h-6z" fill="none" stroke="#00f" stroke-width=".25"/>
<path d="M179.1 111.4l2.1 2.1M179.1 106.4l2.1 2M179.1 103.8l2.1 2.1M181.2 111.4l-2.1 2.1M181.2 106.4l-2.1 2M181.2 103.8l-2.1 2.1M130.8 129.2l2.1 2.1M130.8 126.7l2.1 2M130.8 121.6l2.1 2M132.9 129.2l-2.1 2.1M132.9 126.7l-2.1 2M132.9 121.6l-2.1 2" fill="none" stroke="#f00" stroke-width=".13"/>
<path d="M106.7 109.7v.5M107.4 108.9v2M108.2 108.2v3.5M109 107.4v5.1M109 109.9h2.5M106.4 173.4h5.1M107.2 174.2h3.6M108 174.9h2M108.7 175.7h.5M109 170.9v2.5" fill="none" stroke="#800000" stroke-width=".25"/>
<circle cx="58.1" cy="69.3" r=".51" fill="#000080"/>
<circle cx="58.1" cy="69.3" r=".51" fill="none" stroke="#000080" stroke-width=".13"/>
<path d="M58.1 69.3v2.5" fill="none" stroke="#000" stroke-width=".25"/>
<circle cx="58.1" cy="69.3" r=".51" fill="#000080"/>
<circle cx="58.1" cy="69.3" r=".51" fill="none" stroke="#000080" stroke-width=".13"/>
<path d="M58.1 76.9v2.6" fill="none" stroke="#000" stroke-width=".25"/>
<path d="M56.1 73.9h4M56.1 74.9h4M58.1 71.8v2.1M58.1 74.9v2" fill="none" stroke="#00f" stroke-width=".25"/>
<path d="M58.1 79.5v2.5M55.6 82h5.1M56.4 82.8h3.5M57.1 83.5h2.1M57.9 84.3h.5" fill="none" stroke="#800000" stroke-width=".25"/>
<circle cx="98.8" cy="69.3" r=".51" fill="#000080"/>
<circle cx="98.8" cy="69.3" r=".51" fill="none" stroke="#000080" stroke-width=".13"/>
<path d="M98.8 69.3v2.5" fill="none" stroke="#000" stroke-width=".25"/>
<circle cx="98.8" cy="69.3" r=".51" fill="#000080"/>
<circle cx="98.8" cy="69.3" r=".51" fill="none" stroke="#000080" stroke-width=".13"/>
<path d="M98.8 76.9v2.6" fill="none" stroke="#000" stroke-width=".25"/>
<path d="M96.8 73.9h4M96.8 74.9h4M98.8 71.8v2.1M98.8 74.9v2" fill="none" stroke="#00f" stroke-width=".25"/>
<path d="M98.8 79.5v2.5M280.5 66.8h2.6M281.8 66.8v2.5M96.3 82h5M97 82.8h3.6M97.8 83.5h2M98.6 84.3h.5" fill="none" stroke="#800000" stroke-width=".25"/>
<circle cx="251.3" cy="69.3" r=".51" fill="#000080"/>
<circle cx="251.3" cy="69.3" r=".51" fill="none" stroke="#000080" stroke-width=".13"/>
<circle cx="251.3" cy="79.5" r=".51" fill="#000080"/>
<circle cx="251.3" cy="79.5" r=".51" fill="none" stroke="#000080" stroke-width=".13"/>
<path d="M251.3 69.3v2.5" fill="none" stroke="#000" stroke-width=".25"/>
<circle cx="251.3" cy="69.3" r=".51" fill="#000080"/>
<circle cx="251.3" cy="69.3" r=".51" fill="none" stroke="#000080" stroke-width=".13"/>
<path d="M251.3 76.9v2.6" fill="none" stroke="#000" stroke-width=".25"/>
<circle cx="251.3" cy="79.5" r=".51" fill="#000080"/>
<circle cx="251.3" cy="79.5" r=".51" fill="none" stroke="#000080" stroke-width=".13"/>
<path d="M249.3 73.9h4M249.3 74.9h4M251.3 71.8v2.1M251.3 74.9v2" fill="none" stroke="#00f" stroke-width=".25"/>
<circle cx="241.1" cy="69.3" r=".51" fill="#000080"/>
<circle cx="241.1" cy="69.3" r=".51" fill="none" stroke="#000080" stroke-width=".13"/>
<circle cx="241.1" cy="79.5" r=".51" fill="#000080"/>
<circle cx="241.1" cy="79.5" r=".51" fill="none" stroke="#000080" stroke-width=".13"/>
<path d="M241.1 69.3v2.5" fill="none" stroke="#000" stroke-width=".25"/>
<circle cx="241.1" cy="69.3" r=".51" fill="#000080"/>
<circle cx="241.1" cy="69.3" r=".51" fill="none" stroke="#000080" stroke-width=".13"/>
<path d="M241.1 76.9v2.6" fill="none" stroke="#000" stroke-width=".25"/>
<circle cx="241.1" cy="79.5" r=".51" fill="#000080"/>
<circle cx="241.1" cy="79.5" r=".51" fill="none" stroke="#000080" stroke-width=".13"/>
<path d="M239.1 73.9h4M239.1 74.9h4M241.1 71.8v2.1M241.1 74.9v2" fill="none" stroke="#00f" stroke-width=".25"/>
<circle cx="231" cy="69.3" r=".51" fill="#000080"/>
<circle cx="231" cy="69.3" r=".51" fill="none" stroke="#000080" stroke-width=".13"/>
<circle cx="231" cy="79.5" r=".51" fill="#000080"/>
<circle cx="231" cy="79.5" r=".51" fill="none" stroke="#000080" stroke-width=".13"/>
<path d="M231 69.3v2.5" fill="none" stroke="#000" stroke-width=".25"/>
<circle cx="231" cy="69.3" r=".51" fill="#000080"/>
<circle cx="231" cy="69.3" r=".51" fill="none" stroke="#000080" stroke-width=".13"/>
<path d="M231 76.9v2.6" fill="none" stroke="#000" stroke-width=".25"/>
<circle cx="231" cy="79.5" r=".51" fill="#000080"/>
<circle cx="231" cy="79.5" r=".51" fill="none" stroke="#000080" stroke-width=".13"/>
<path d="M229 73.9h4M229 74.9h4M231 71.8v2.1M231 74.9v2" fill="none" stroke="#00f" stroke-width=".25"/>
<circle cx="220.8" cy="69.3" r=".51" fill="#000080"/>
<circle cx="220.8" cy="69.3" r=".51" fill="none" stroke="#000080" stroke-width=".13"/>
<circle cx="220.8" cy="79.5" r=".51" fill="#000080"/>
<circle cx="220.8" cy="79.5" r=".51" fill="none" stroke="#000080" stroke-width=".13"/>
<path d="M220.8 69.3v2.5" fill="none" stroke="#000" stroke-width=".25"/>
<circle cx="220.8" cy="69.3" r=".51" fill="#000080"/>
<circle cx="220.8" cy="69.3" r=".51" fill="none" stroke="#000080" stroke-width=".13"/>
<path d="M220.8 76.9v2.6" fill="none" stroke="#000" stroke-width=".25"/>
<circle cx="220.8" cy="79.5" r=".51" fill="#000080"/>
<circle cx="220.8" cy="79.5" r=".51" fill="none" stroke="#000080" stroke-width=".13"/>
<path d="M218.8 73.9h4M218.8 74.9h4M220.8 71.8v2.1M220.8 74.9v2" fill="none" stroke="#00f" stroke-width=".25"/>
<path d="M119.1 79.5v2.5M281.8 79.5v2.5M116.6 82h5.1M117.4 82.8h3.5M118.1 83.5h2.1M118.9 84.3h.5M279.3 82h5M280 82.8h3.6M280.8 83.5h2M281.5 84.3h.6" fill="none" stroke="#800000" stroke-width=".25"/>
<circle cx="200.5" cy="69.3" r=".51" fill="#000080"/>
<circle cx="200.5" cy="69.3" r=".51" fill="none" stroke="#000080" stroke-width=".13"/>
<circle cx="200.5" cy="79.5" r=".51" fill="#000080"/>
<circle cx="200.5" cy="79.5" r=".51" fill="none" stroke="#000080" stroke-width=".13"/>
<path d="M200.5 69.3v2.5" fill="none" stroke="#000" stroke-width=".25"/>
<circle cx="200.5" cy="69.3" r=".51" fill="#000080"/>
<circle cx="200.5" cy="69.3" r=".51" fill="none" stroke="#000080" stroke-width=".13"/>
<path d="M200.5 76.9v2.6" fill="none" stroke="#000" stroke-width=".25"/>
<circle cx="200.5" cy="79.5" r=".51" fill="#000080"/>
<circle cx="200.5" cy="79.5" r=".51" fill="none" stroke="#000080" stroke-width=".13"/>
<path d="M198.5 73.9h4M198.5 74.9h4M200.5 71.8v2.1M200.5 74.9v2" fill="none" stroke="#00f" stroke-width=".25"/>
<circle cx="210.6" cy="69.3" r=".51" fill="#000080"/>
<circle cx="210.6" cy="69.3" r=".51" fill="none" stroke="#000080" stroke-width=".13"/>
<circle cx="210.6" cy="79.5" r=".51" fill="#000080"/>
<circle cx="210.6" cy="79.5" r=".51" fill="none" stroke="#000080" stroke-width=".13"/>
<path d="M210.6 69.3v2.5" fill="none" stroke="#000" stroke-width=".25"/>
<circle cx="210.6" cy="69.3" r=".51" fill="#000080"/>
<circle cx="210.6" cy="69.3" r=".51" fill="none" stroke="#000080" stroke-width=".13"/>
<path d="M210.6 76.9v2.6" fill="none" stroke="#000" stroke-width=".25"/>
<circle cx="210.6" cy="79.5" r=".51" fill="#000080"/>
<circle cx="210.6" cy="79.5" r=".51" fill="none" stroke="#000080" stroke-width=".13"/>
<path d="M208.6 73.9h4M208.6 74.9h4M210.6 71.8v2.1M210.6 74.9v2" fill="none" stroke="#00f" stroke-width=".25"/>
<circle cx="68.3" cy="69.3" r=".51" fill="#000080"/>
<circle cx="68.3" cy="69.3" r=".51" fill="none" stroke="#000080" stroke-width=".13"/>
<path d="M68.3 69.3v2.5" fill="none" stroke="#000" stroke-width=".25"/>
<circle cx="68.3" cy="69.3" r=".51" fill="#000080"/>
<circle cx="68.3" cy="69.3" r=".51" fill="none" stroke="#000080" stroke-width=".13"/>
<path d="M68.3 76.9v2.6" fill="none" stroke="#000" stroke-width=".25"/>
<path d="M66.3 73.9h4M66.3 74.9h4M68.3 71.8v2.1M68.3 74.9v2" fill="none" stroke="#00f" stroke-width=".25"/>
<path d="M68.3 79.5v2.5M65.8 82h5M66.5 82.8h3.6M67.3 83.5h2M68 84.3h.6" fill="none" stroke="#800000" stroke-width=".25"/>
<path d="M53.1 112.5h20.3v15.2h-20.3z" fill-rule="evenodd" fill="#ffffb0"/>
<path d="M53.1 112.5h20.3v15.2h-20.3z" fill="none" stroke="#800000" stroke-width=".13"/>
<path d="M45.4 115h7.7M73.4 115h7.6M111.5 115h2.6M119.1 115h2.6M119.1 117.5h2.6M126.8 117.5h2.5M45.4 125.2h7.7M45.4 120.1h7.7" fill="none" stroke="#000" stroke-width=".25"/>
<path d="M26.4 109.9h2.5M27.6 109.9v2.6M106.7 117.3v.5M107.4 116.5v2.1M108.2 115.8v3.5M109 115v5.1M109 117.5h2.5M25.1 130.2h5.1M25.9 131h3.5M26.6 131.8h2.1M27.4 132.5h.5M27.6 127.7v2.5" fill="none" stroke="#800000" stroke-width=".25"/>
<path d="M114.1 115h2M116.1 113v4M117.1 115h2M117.1 113v4M121.7 117.5h2M123.7 115.5v4M124.7 117.5h2.1M124.7 115.5v4" fill="none" stroke="#00f" stroke-width=".25"/>
<circle cx="190.3" cy="69.3" r=".51" fill="#000080"/>
<circle cx="190.3" cy="69.3" r=".51" fill="none" stroke="#000080" stroke-width=".13"/>
<path d="M190.3 69.3v2.5" fill="none" stroke="#000" stroke-width=".25"/>
<circle cx="190.3" cy="69.3" r=".51" fill="#000080"/>
<circle cx="190.3" cy="69.3" r=".51" fill="none" stroke="#000080" stroke-width=".13"/>
<path d="M190.3 76.9v2.6" fill="none" stroke="#000" stroke-width=".25"/>
<path d="M188.3 73.9h4M188.3 74.9h4M190.3 71.8v2.1M190.3 74.9v2" fill="none" stroke="#00f" stroke-width=".25"/>
<path d="M32.7 68v2.6M32.7 69.3h2.6" fill="none" stroke="#800000" stroke-width=".25"/>
<circle cx="78.5" cy="69.3" r=".51" fill="#000080"/>
<circle cx="78.5" cy="69.3" r=".51" fill="none" stroke="#000080" stroke-width=".13"/>
<path d="M78.5 69.3v2.5" fill="none" stroke="#000" stroke-width=".25"/>
<circle cx="78.5" cy="69.3" r=".51" fill="#000080"/>
<circle cx="78.5" cy="69.3" r=".51" fill="none" stroke="#000080" stroke-width=".13"/>
<path d="M78.5 76.9v2.6" fill="none" stroke="#000" stroke-width=".25"/>
<path d="M76.5 73.9h4M76.5 74.9h4M78.5 71.8v2.1M78.5 74.9v2" fill="none" stroke="#00f" stroke-width=".25"/>
<path d="M78.5 79.5v2.5M75.9 82h5.1M76.7 82.8h3.6M77.5 83.5h2M78.2 84.3h.5" fill="none" stroke="#800000" stroke-width=".25"/>
<path d="M139.5 66.8h33v104.1h-33z" fill-rule="evenodd" fill="#ffffb0"/>
<path d="M139.5 66.8h33v104.1h-33z" fill="none" stroke="#800000" stroke-width=".13"/>
<g fill="none" stroke="#000" stroke-width=".25">
<path d="M131.8 69.3h7.7M131.8 71.8h7.7M131.8 74.4h7.7M131.8 76.9h7.7M172.5 71.8h7.6M172.5 74.4h7.6M172.5 76.9h7.6M172.5 69.3h7.6M172.5 79.5h7.6M131.8 99.8h7.7M131.8 97.2h7.7M131.8 82h7.7"/>
<path d="M131.8 87.1h7.7M131.8 89.6h7.7M131.8 92.1h7.7M131.8 94.7h7.7M172.5 99.8h7.6M172.5 97.2h7.6M172.5 82h7.6M172.5 84.5h7.6M172.5 87.1h7.6M172.5 89.6h7.6M131.8 117.5h7.7M131.8 115h7.7"/>
<path d="M131.8 109.9h7.7M131.8 107.4h7.7M172.5 115h7.6M172.5 107.4h7.6M172.5 112.5h7.6M172.5 104.9h7.6M131.8 122.6h7.7M131.8 127.7h7.7M131.8 130.2h7.7M131.8 135.3h7.7M172.5 122.6h7.6M172.5 130.2h7.6"/>
<path d="M172.5 135.3h7.6M172.5 137.9h7.6M172.5 127.7h7.6M172.5 120.1h7.6M131.8 145.5h7.7M131.8 142.9h7.7M131.8 158.2h7.7M131.8 155.6h7.7M131.8 153.1h7.7M131.8 140.4h7.7M131.8 148h7.7M172.5 145.5h7.6"/>
<path d="M172.5 142.9h7.6M172.5 158.2h7.6M172.5 153.1h7.6M172.5 150.6h7.6M111.5 160.7h2M119.7 160.7h2M131.8 168.3h7.7M131.8 160.7h7.7M172.5 168.3h7.6M172.5 160.7h7.6M172.5 165.8h7.6"/>
</g>
<path d="M113.6 159.7h6v2h-6z" fill="none" stroke="#00f" stroke-width=".25"/>
<g fill="none" stroke="#f00" stroke-width=".13">
<path d="M179.1 119.1l2.1 2M181.2 119.1l-2.1 2M179.1 121.6l2.1 2M179.1 129.2l2.1 2.1M179.1 126.7l2.1 2M181.2 121.6l-2.1 2M181.2 129.2l-2.1 2.1M181.2 126.7l-2.1 2M179.1 144.5l2.1 2M179.1 141.9l2.1 2.1M179.1 152.1l2.1 2M179.1 149.5l2.1 2.1"/>
<path d="M179.1 159.7l2.1 2M181.2 144.5l-2.1 2M181.2 141.9l-2.1 2.1M181.2 152.1l-2.1 2M181.2 149.5l-2.1 2.1M181.2 159.7l-2.1 2M179.1 167.3l2.1 2.1M179.1 164.8l2.1 2M181.2 167.3l-2.1 2.1M181.2 164.8l-2.1 2"/>
</g>
<circle cx="271.6" cy="69.3" r=".51" fill="#000080"/>
<circle cx="271.6" cy="69.3" r=".51" fill="none" stroke="#000080" stroke-width=".13"/>
<circle cx="271.6" cy="79.5" r=".51" fill="#000080"/>
<circle cx="271.6" cy="79.5" r=".51" fill="none" stroke="#000080" stroke-width=".13"/>
<path d="M271.6 69.3v2.5" fill="none" stroke="#000" stroke-width=".25"/>
<circle cx="271.6" cy="69.3" r=".51" fill="#000080"/>
<circle cx="271.6" cy="69.3" r=".51" fill="none" stroke="#000080" stroke-width=".13"/>
<path d="M271.6 76.9v2.6" fill="none" stroke="#000" stroke-width=".25"/>
<circle cx="271.6" cy="79.5" r=".51" fill="#000080"/>
<circle cx="271.6" cy="79.5" r=".51" fill="none" stroke="#000080" stroke-width=".13"/>
<path d="M269.6 73.9h4M269.6 74.9h4M271.6 71.8v2.1M271.6 74.9v2" fill="none" stroke="#00f" stroke-width=".25"/>
<circle cx="261.5" cy="69.3" r=".51" fill="#000080"/>
<circle cx="261.5" cy="69.3" r=".51" fill="none" stroke="#000080" stroke-width=".13"/>
<circle cx="261.5" cy="79.5" r=".51" fill="#000080"/>
<circle cx="261.5" cy="79.5" r=".51" fill="none" stroke="#000080" stroke-width=".13"/>
<path d="M261.5 69.3v2.5" fill="none" stroke="#000" stroke-width=".25"/>
<circle cx="261.5" cy="69.3" r=".51" fill="#000080"/>
<circle cx="261.5" cy="69.3" r=".51" fill="none" stroke="#000080" stroke-width=".13"/>
<path d="M261.5 76.9v2.6" fill="none" stroke="#000" stroke-width=".25"/>
<circle cx="261.5" cy="79.5" r=".51" fill="#000080"/>
<circle cx="261.5" cy="79.5" r=".51" fill="none" stroke="#000080" stroke-width=".13"/>
<path d="M259.5 73.9h4M259.5 74.9h4M261.5 71.8v2.1M261.5 74.9v2" fill="none" stroke="#00f" stroke-width=".25"/>
<circle cx="88.6" cy="69.3" r=".51" fill="#000080"/>
<circle cx="88.6" cy="69.3" r=".51" fill="none" stroke="#000080" stroke-width=".13"/>
<path d="M88.6 69.3v2.5" fill="none" stroke="#000" stroke-width=".25"/>
<circle cx="88.6" cy="69.3" r=".51" fill="#000080"/>
<circle cx="88.6" cy="69.3" r=".51" fill="none" stroke="#000080" stroke-width=".13"/>
<path d="M88.6 76.9v2.6" fill="none" stroke="#000" stroke-width=".25"/>
<path d="M86.6 73.9h4M86.6 74.9h4M88.6 71.8v2.1M88.6 74.9v2" fill="none" stroke="#00f" stroke-width=".25"/>
<path d="M88.6 79.5v2.5M86.1 82h5.1M86.9 82.8h3.5M87.6 83.5h2.1M88.4 84.3h.5" fill="none" stroke="#800000" stroke-width=".25"/>
<circle cx="109" cy="69.3" r=".51" fill="#000080"/>
<circle cx="109" cy="69.3" r=".51" fill="none" stroke="#000080" stroke-width=".13"/>
<path d="M109 69.3v2.5" fill="none" stroke="#000" stroke-width=".25"/>
<circle cx="109" cy="69.3" r=".51" fill="#000080"/>
<circle cx="109" cy="69.3" r=".51" fill="none" stroke="#000080" stroke-width=".13"/>
<path d="M109 76.9v2.6" fill="none" stroke="#000" stroke-width=".25"/>
<path d="M107 73.9h4M107 74.9h4M109 71.8v2.1M109 74.9v2" fill="none" stroke="#00f" stroke-width=".25"/>
<path d="M109 79.5v2.5M106.4 82h5.1M107.2 82.8h3.6M108 83.5h2M108.7 84.3h.5" fill="none" stroke="#800000" stroke-width=".25"/>
<circle cx="32.7" cy="115" r=".51" fill="#000080"/>
<circle cx="32.7" cy="115" r=".51" fill="none" stroke="#000080" stroke-width=".13"/>
<circle cx="32.7" cy="125.2" r=".51" fill="#000080"/>
<circle cx="32.7" cy="125.2" r=".51" fill="none" stroke="#000080" stroke-width=".13"/>
<path d="M32.7 115v2.5" fill="none" stroke="#000" stroke-width=".25"/>
<circle cx="32.7" cy="115" r=".51" fill="#000080"/>
<circle cx="32.7" cy="115" r=".51" fill="none" stroke="#000080" stroke-width=".13"/>
<path d="M32.7 122.6v2.6" fill="none" stroke="#000" stroke-width=".25"/>
<circle cx="32.7" cy="125.2" r=".51" fill="#000080"/>
<circle cx="32.7" cy="125.2" r=".51" fill="none" stroke="#000080" stroke-width=".13"/>
<path d="M30.7 119.6h4M32.7 117.5v2.1M30.7 120.6h4M32.7 120.6v2" fill="none" stroke="#00f" stroke-width=".25"/>
<path d="M238.6 134h16.5l1.3 1.3-1.3 1.3h-16.5z" fill-rule="evenodd" fill="#ffff80"/>
<path d="M238.6 134h16.5l1.3 1.3-1.3 1.3h-16.5z" fill="none" stroke="#800000" stroke-width=".13"/>
<path d="M238.6 136.6h16.5l1.3 1.3-1.3 1.2h-16.5z" fill-rule="evenodd" fill="#ffff80"/>
<path d="M238.6 136.6h16.5l1.3 1.3-1.3 1.2h-16.5z" fill="none" stroke="#800000" stroke-width=".13"/>
<path d="M179.1 98.8l2.1 2M181.2 98.8l-2.1 2M179.1 114l2.1 2M181.2 114l-2.1 2" fill="none" stroke="#f00" stroke-width=".13"/>
<circle cx="119.1" cy="69.3" r=".51" fill="#000080"/>
<circle cx="119.1" cy="69.3" r=".51" fill="none" stroke="#000080" stroke-width=".13"/>
<path d="M119.1 69.3v2.5" fill="none" stroke="#000" stroke-width=".25"/>
<circle cx="119.1" cy="69.3" r=".51" fill="#000080"/>
<circle cx="119.1" cy="69.3" r=".51" fill="none" stroke="#000080" stroke-width=".13"/>
<path d="M119.1 76.9v2.6M182.7 97.2h2M190.8 97.2h2" fill="none" stroke="#000" stroke-width=".25"/>
<path d="M117.1 73.9h4M117.1 74.9h4M119.1 71.8v2.1M119.1 74.9v2M184.8 96.3h6v2h-6z" fill="none" stroke="#00f" stroke-width=".25"/>
<path d="M179.1 157.2l2.1 2M181.2 157.2l-2.1 2" fill="none" stroke="#f00" stroke-width=".13"/>
<path d="M206.8 96h15.3l1.2 1.2-1.2 1.3h-15.3l-1.2-1.3z" fill-rule="evenodd" fill="#ffff80"/>
<path d="M206.8 96h15.3l1.2 1.2-1.2 1.3h-15.3l-1.2-1.3z" fill="none" stroke="#800000" stroke-width=".13"/>
<path d="M111.5 135.3h2M119.7 135.3h2M111.5 145.5h2M111.5 148h2M119.7 145.5h2M119.7 148h2" fill="none" stroke="#000" stroke-width=".25"/>
<path d="M113.6 134.3h6v2.1h-6zM113.6 144.4h6v2.1h-6zM113.6 147h6v2h-6z" fill="none" stroke="#00f" stroke-width=".25"/>
<path d="M102.6 148h2.6M103.9 148v2.6" fill="none" stroke="#800000" stroke-width=".25"/>
<path d="M45.4 150.6v10.1" fill="none" stroke="#000080" stroke-width=".25"/>
<circle cx="45.4" cy="150.6" r=".51" fill="#000080"/>
<circle cx="45.4" cy="150.6" r=".51" fill="none" stroke="#000080" stroke-width=".13"/>
<path d="M27.6 112.5v2.5h17.8M96.3 107.4h15.2M111.5 109.9h7.6M121.7 107.4h10.1M129.3 109.9h2.5" fill="none" stroke="#000080" stroke-width=".25"/>
<circle cx="42.9" cy="115" r=".51" fill="#000080"/>
<circle cx="42.9" cy="115" r=".51" fill="none" stroke="#000080" stroke-width=".13"/>
<circle cx="32.7" cy="115" r=".51" fill="#000080"/>
<circle cx="32.7" cy="115" r=".51" fill="none" stroke="#000080" stroke-width=".13"/>
<path d="M42.9 115v5.1h2.5M81 115h30.5M111.5 117.5h7.6M129.3 117.5h2.5" fill="none" stroke="#000080" stroke-width=".25"/>
<circle cx="42.9" cy="115" r=".51" fill="#000080"/>
<circle cx="42.9" cy="115" r=".51" fill="none" stroke="#000080" stroke-width=".13"/>
<path d="M35.3 69.3h2.5M190.3 79.5h91.5M121.7 158.2h10.1M121.7 155.6h10.1M121.7 153.1h10.1" fill="none" stroke="#000080" stroke-width=".25"/>
<circle cx="271.6" cy="79.5" r=".51" fill="#000080"/>
<circle cx="271.6" cy="79.5" r=".51" fill="none" stroke="#000080" stroke-width=".13"/>
<circle cx="261.5" cy="79.5" r=".51" fill="#000080"/>
<circle cx="261.5" cy="79.5" r=".51" fill="none" stroke="#000080" stroke-width=".13"/>
<circle cx="251.3" cy="79.5" r=".51" fill="#000080"/>
<circle cx="251.3" cy="79.5" r=".51" fill="none" stroke="#000080" stroke-width=".13"/>
<circle cx="241.1" cy="79.5" r=".51" fill="#000080"/>
<circle cx="241.1" cy="79.5" r=".51" fill="none" stroke="#000080" stroke-width=".13"/>
<circle cx="231" cy="79.5" r=".51" fill="#000080"/>
<circle cx="231" cy="79.5" r=".51" fill="none" stroke="#000080" stroke-width=".13"/>
<circle cx="220.8" cy="79.5" r=".51" fill="#000080"/>
<circle cx="220.8" cy="79.5" r=".51" fill="none" stroke="#000080" stroke-width=".13"/>
<circle cx="210.6" cy="79.5" r=".51" fill="#000080"/>
<circle cx="210.6" cy="79.5" r=".51" fill="none" stroke="#000080" stroke-width=".13"/>
<circle cx="200.5" cy="79.5" r=".51" fill="#000080"/>
<circle cx="200.5" cy="79.5" r=".51" fill="none" stroke="#000080" stroke-width=".13"/>
<path d="M190.3 69.3h91.5" fill="none" stroke="#000080" stroke-width=".25"/>
<circle cx="271.6" cy="69.3" r=".51" fill="#000080"/>
<circle cx="271.6" cy="69.3" r=".51" fill="none" stroke="#000080" stroke-width=".13"/>
<circle cx="261.5" cy="69.3" r=".51" fill="#000080"/>
<circle cx="261.5" cy="69.3" r=".51" fill="none" stroke="#000080" stroke-width=".13"/>
<circle cx="251.3" cy="69.3" r=".51" fill="#000080"/>
<circle cx="251.3" cy="69.3" r=".51" fill="none" stroke="#000080" stroke-width=".13"/>
<circle cx="241.1" cy="69.3" r=".51" fill="#000080"/>
<circle cx="241.1" cy="69.3" r=".51" fill="none" stroke="#000080" stroke-width=".13"/>
<circle cx="231" cy="69.3" r=".51" fill="#000080"/>
<circle cx="231" cy="69.3" r=".51" fill="none" stroke="#000080" stroke-width=".13"/>
<circle cx="220.8" cy="69.3" r=".51" fill="#000080"/>
<circle cx="220.8" cy="69.3" r=".51" fill="none" stroke="#000080" stroke-width=".13"/>
<circle cx="210.6" cy="69.3" r=".51" fill="#000080"/>
<circle cx="210.6" cy="69.3" r=".51" fill="none" stroke="#000080" stroke-width=".13"/>
<circle cx="200.5" cy="69.3" r=".51" fill="#000080"/>
<circle cx="200.5" cy="69.3" r=".51" fill="none" stroke="#000080" stroke-width=".13"/>
<circle cx="190.3" cy="69.3" r=".51" fill="#000080"/>
<circle cx="190.3" cy="69.3" r=".51" fill="none" stroke="#000080" stroke-width=".13"/>
<path d="M180.1 69.3h10.2" fill="none" stroke="#000080" stroke-width=".25"/>
<circle cx="182.7" cy="69.3" r=".51" fill="#000080"/>
<circle cx="182.7" cy="69.3" r=".51" fill="none" stroke="#000080" stroke-width=".13"/>
<circle cx="190.3" cy="69.3" r=".51" fill="#000080"/>
<circle cx="190.3" cy="69.3" r=".51" fill="none" stroke="#000080" stroke-width=".13"/>
<path d="M182.7 69.3v20.3h-2.6" fill="none" stroke="#000080" stroke-width=".25"/>
<circle cx="182.7" cy="87.1" r=".51" fill="#000080"/>
<circle cx="182.7" cy="87.1" r=".51" fill="none" stroke="#000080" stroke-width=".13"/>
<circle cx="182.7" cy="84.5" r=".51" fill="#000080"/>
<circle cx="182.7" cy="84.5" r=".51" fill="none" stroke="#000080" stroke-width=".13"/>
<circle cx="182.7" cy="82" r=".51" fill="#000080"/>
<circle cx="182.7" cy="82" r=".51" fill="none" stroke="#000080" stroke-width=".13"/>
<circle cx="182.7" cy="79.5" r=".51" fill="#000080"/>
<circle cx="182.7" cy="79.5" r=".51" fill="none" stroke="#000080" stroke-width=".13"/>
<circle cx="182.7" cy="76.9" r=".51" fill="#000080"/>
<circle cx="182.7" cy="76.9" r=".51" fill="none" stroke="#000080" stroke-width=".13"/>
<circle cx="182.7" cy="74.4" r=".51" fill="#000080"/>
<circle cx="182.7" cy="74.4" r=".51" fill="none" stroke="#000080" stroke-width=".13"/>
<circle cx="182.7" cy="71.8" r=".51" fill="#000080"/>
<circle cx="182.7" cy="71.8" r=".51" fill="none" stroke="#000080" stroke-width=".13"/>
<circle cx="182.7" cy="69.3" r=".51" fill="#000080"/>
<circle cx="182.7" cy="69.3" r=".51" fill="none" stroke="#000080" stroke-width=".13"/>
<path d="M180.1 87.1h2.6" fill="none" stroke="#000080" stroke-width=".25"/>
<circle cx="182.7" cy="87.1" r=".51" fill="#000080"/>
<circle cx="182.7" cy="87.1" r=".51" fill="none" stroke="#000080" stroke-width=".13"/>
<path d="M180.1 84.5h2.6" fill="none" stroke="#000080" stroke-width=".25"/>
<circle cx="182.7" cy="84.5" r=".51" fill="#000080"/>
<circle cx="182.7" cy="84.5" r=".51" fill="none" stroke="#000080" stroke-width=".13"/>
<path d="M180.1 82h2.6" fill="none" stroke="#000080" stroke-width=".25"/>
<circle cx="182.7" cy="82" r=".51" fill="#000080"/>
<circle cx="182.7" cy="82" r=".51" fill="none" stroke="#000080" stroke-width=".13"/>
<path d="M180.1 79.5h2.6" fill="none" stroke="#000080" stroke-width=".25"/>
<circle cx="182.7" cy="79.5" r=".51" fill="#000080"/>
<circle cx="182.7" cy="79.5" r=".51" fill="none" stroke="#000080" stroke-width=".13"/>
<path d="M180.1 76.9h2.6" fill="none" stroke="#000080" stroke-width=".25"/>
<circle cx="182.7" cy="76.9" r=".51" fill="#000080"/>
<circle cx="182.7" cy="76.9" r=".51" fill="none" stroke="#000080" stroke-width=".13"/>
<path d="M180.1 74.4h2.6" fill="none" stroke="#000080" stroke-width=".25"/>
<circle cx="182.7" cy="74.4" r=".51" fill="#000080"/>
<circle cx="182.7" cy="74.4" r=".51" fill="none" stroke="#000080" stroke-width=".13"/>
<path d="M180.1 71.8h2.6" fill="none" stroke="#000080" stroke-width=".25"/>
<circle cx="182.7" cy="71.8" r=".51" fill="#000080"/>
<circle cx="182.7" cy="71.8" r=".51" fill="none" stroke="#000080" stroke-width=".13"/>
<path d="M129.3 74.4h2.5" fill="none" stroke="#000080" stroke-width=".25"/>
<circle cx="129.3" cy="74.4" r=".51" fill="#000080"/>
<circle cx="129.3" cy="74.4" r=".51" fill="none" stroke="#000080" stroke-width=".13"/>
<path d="M129.3 71.8h2.5" fill="none" stroke="#000080" stroke-width=".25"/>
<circle cx="129.3" cy="71.8" r=".51" fill="#000080"/>
<circle cx="129.3" cy="71.8" r=".51" fill="none" stroke="#000080" stroke-width=".13"/>
<path d="M129.3 69.3h2.5" fill="none" stroke="#000080" stroke-width=".25"/>
<circle cx="129.3" cy="69.3" r=".51" fill="#000080"/>
<circle cx="129.3" cy="69.3" r=".51" fill="none" stroke="#000080" stroke-width=".13"/>
<path d="M45.4 125.2h-17.8v2.5" fill="none" stroke="#000080" stroke-width=".25"/>
<circle cx="32.7" cy="125.2" r=".51" fill="#000080"/>
<circle cx="32.7" cy="125.2" r=".51" fill="none" stroke="#000080" stroke-width=".13"/>
<path d="M129.3 97.2h2.5" fill="none" stroke="#000080" stroke-width=".25"/>
<circle cx="129.3" cy="97.2" r=".51" fill="#000080"/>
<circle cx="129.3" cy="97.2" r=".51" fill="none" stroke="#000080" stroke-width=".13"/>
<path d="M129.3 92.1h2.5" fill="none" stroke="#000080" stroke-width=".25"/>
<circle cx="129.3" cy="92.1" r=".51" fill="#000080"/>
<circle cx="129.3" cy="92.1" r=".51" fill="none" stroke="#000080" stroke-width=".13"/>
<path d="M129.3 89.6h2.5" fill="none" stroke="#000080" stroke-width=".25"/>
<circle cx="129.3" cy="89.6" r=".51" fill="#000080"/>
<circle cx="129.3" cy="89.6" r=".51" fill="none" stroke="#000080" stroke-width=".13"/>
<path d="M129.3 94.7h2.5" fill="none" stroke="#000080" stroke-width=".25"/>
<circle cx="129.3" cy="94.7" r=".51" fill="#000080"/>
<circle cx="129.3" cy="94.7" r=".51" fill="none" stroke="#000080" stroke-width=".13"/>
<path d="M131.8 87.1h-2.5v12.7h2.5" fill="none" stroke="#000080" stroke-width=".25"/>
<circle cx="129.3" cy="97.2" r=".51" fill="#000080"/>
<circle cx="129.3" cy="97.2" r=".51" fill="none" stroke="#000080" stroke-width=".13"/>
<circle cx="129.3" cy="94.7" r=".51" fill="#000080"/>
<circle cx="129.3" cy="94.7" r=".51" fill="none" stroke="#000080" stroke-width=".13"/>
<circle cx="129.3" cy="92.1" r=".51" fill="#000080"/>
<circle cx="129.3" cy="92.1" r=".51" fill="none" stroke="#000080" stroke-width=".13"/>
<circle cx="129.3" cy="89.6" r=".51" fill="#000080"/>
<circle cx="129.3" cy="89.6" r=".51" fill="none" stroke="#000080" stroke-width=".13"/>
<circle cx="129.3" cy="87.1" r=".51" fill="#000080"/>
<circle cx="129.3" cy="87.1" r=".51" fill="none" stroke="#000080" stroke-width=".13"/>
<path d="M129.3 76.9v5.1" fill="none" stroke="#000080" stroke-width=".25"/>
<circle cx="129.3" cy="82" r=".51" fill="#000080"/>
<circle cx="129.3" cy="82" r=".51" fill="none" stroke="#000080" stroke-width=".13"/>
<circle cx="129.3" cy="76.9" r=".51" fill="#000080"/>
<circle cx="129.3" cy="76.9" r=".51" fill="none" stroke="#000080" stroke-width=".13"/>
<path d="M131.8 82h-2.5v5.1" fill="none" stroke="#000080" stroke-width=".25"/>
<circle cx="129.3" cy="82" r=".51" fill="#000080"/>
<circle cx="129.3" cy="82" r=".51" fill="none" stroke="#000080" stroke-width=".13"/>
<circle cx="129.3" cy="87.1" r=".51" fill="#000080"/>
<circle cx="129.3" cy="87.1" r=".51" fill="none" stroke="#000080" stroke-width=".13"/>
<path d="M48 69.3h81.3v7.6h2.5" fill="none" stroke="#000080" stroke-width=".25"/>
<circle cx="58.1" cy="69.3" r=".51" fill="#000080"/>
<circle cx="58.1" cy="69.3" r=".51" fill="none" stroke="#000080" stroke-width=".13"/>
<circle cx="68.3" cy="69.3" r=".51" fill="#000080"/>
<circle cx="68.3" cy="69.3" r=".51" fill="none" stroke="#000080" stroke-width=".13"/>
<circle cx="78.5" cy="69.3" r=".51" fill="#000080"/>
<circle cx="78.5" cy="69.3" r=".51" fill="none" stroke="#000080" stroke-width=".13"/>
<circle cx="88.6" cy="69.3" r=".51" fill="#000080"/>
<circle cx="88.6" cy="69.3" r=".51" fill="none" stroke="#000080" stroke-width=".13"/>
<circle cx="98.8" cy="69.3" r=".51" fill="#000080"/>
<circle cx="98.8" cy="69.3" r=".51" fill="none" stroke="#000080" stroke-width=".13"/>
<circle cx="109" cy="69.3" r=".51" fill="#000080"/>
<circle cx="109" cy="69.3" r=".51" fill="none" stroke="#000080" stroke-width=".13"/>
<circle cx="119.1" cy="69.3" r=".51" fill="#000080"/>
<circle cx="119.1" cy="69.3" r=".51" fill="none" stroke="#000080" stroke-width=".13"/>
<circle cx="129.3" cy="69.3" r=".51" fill="#000080"/>
<circle cx="129.3" cy="69.3" r=".51" fill="none" stroke="#000080" stroke-width=".13"/>
<circle cx="129.3" cy="71.8" r=".51" fill="#000080"/>
<circle cx="129.3" cy="71.8" r=".51" fill="none" stroke="#000080" stroke-width=".13"/>
<circle cx="129.3" cy="74.4" r=".51" fill="#000080"/>
<circle cx="129.3" cy="74.4" r=".51" fill="none" stroke="#000080" stroke-width=".13"/>
<circle cx="129.3" cy="76.9" r=".51" fill="#000080"/>
<circle cx="129.3" cy="76.9" r=".51" fill="none" stroke="#000080" stroke-width=".13"/>
<path d="M180.1 97.2h2.6M192.8 97.2h12.8M50.5 153.1v5.1" fill="none" stroke="#000080" stroke-width=".25"/>
<circle cx="50.5" cy="153.1" r=".51" fill="#000080"/>
<circle cx="50.5" cy="153.1" r=".51" fill="none" stroke="#000080" stroke-width=".13"/>
<path d="M121.7 115h10.1M50.5 135.3v2.6M121.7 135.3h10.1M121.7 160.7h10.1M131.8 168.3h-2.5v2.6" fill="none" stroke="#000080" stroke-width=".25"/>
<circle cx="50.5" cy="135.3" r=".51" fill="#000080"/>
<circle cx="50.5" cy="135.3" r=".51" fill="none" stroke="#000080" stroke-width=".13"/>
<path d="M55.6 135.3v2.6" fill="none" stroke="#000080" stroke-width=".25"/>
<circle cx="55.6" cy="135.3" r=".51" fill="#000080"/>
<circle cx="55.6" cy="135.3" r=".51" fill="none" stroke="#000080" stroke-width=".13"/>
<path d="M48 135.3h12.7v2.6" fill="none" stroke="#000080" stroke-width=".25"/>
<circle cx="50.5" cy="135.3" r=".51" fill="#000080"/>
<circle cx="50.5" cy="135.3" r=".51" fill="none" stroke="#000080" stroke-width=".13"/>
<circle cx="55.6" cy="135.3" r=".51" fill="#000080"/>
<circle cx="55.6" cy="135.3" r=".51" fill="none" stroke="#000080" stroke-width=".13"/>
<path d="M50.5 148v2.6" fill="none" stroke="#000080" stroke-width=".25"/>
<circle cx="50.5" cy="150.6" r=".51" fill="#000080"/>
<circle cx="50.5" cy="150.6" r=".51" fill="none" stroke="#000080" stroke-width=".13"/>
<path d="M55.6 148v5.1" fill="none" stroke="#000080" stroke-width=".25"/>
<circle cx="55.6" cy="153.1" r=".51" fill="#000080"/>
<circle cx="55.6" cy="153.1" r=".51" fill="none" stroke="#000080" stroke-width=".13"/>
<path d="M60.7 148v7.6" fill="none" stroke="#000080" stroke-width=".25"/>
<circle cx="60.7" cy="155.6" r=".51" fill="#000080"/>
<circle cx="60.7" cy="155.6" r=".51" fill="none" stroke="#000080" stroke-width=".13"/>
<path d="M131.8 140.4h-61v12.7h-27.9" fill="none" stroke="#000080" stroke-width=".25"/>
<circle cx="50.5" cy="153.1" r=".51" fill="#000080"/>
<circle cx="50.5" cy="153.1" r=".51" fill="none" stroke="#000080" stroke-width=".13"/>
<circle cx="55.6" cy="153.1" r=".51" fill="#000080"/>
<circle cx="55.6" cy="153.1" r=".51" fill="none" stroke="#000080" stroke-width=".13"/>
<path d="M131.8 142.9h-58.4v12.7h-30.5" fill="none" stroke="#000080" stroke-width=".25"/>
<circle cx="55.6" cy="155.6" r=".51" fill="#000080"/>
<circle cx="55.6" cy="155.6" r=".51" fill="none" stroke="#000080" stroke-width=".13"/>
<circle cx="60.7" cy="155.6" r=".51" fill="#000080"/>
<circle cx="60.7" cy="155.6" r=".51" fill="none" stroke="#000080" stroke-width=".13"/>
<path d="M103.9 150.6v2.5h7.6M121.7 145.5h10.1M121.7 148h10.1" fill="none" stroke="#000080" stroke-width=".25"/>
<circle cx="103.9" cy="153.1" r=".51" fill="#000080"/>
<circle cx="103.9" cy="153.1" r=".51" fill="none" stroke="#000080" stroke-width=".13"/>
<path d="M103.9 153.1v2.5h7.6" fill="none" stroke="#000080" stroke-width=".25"/>
<circle cx="103.9" cy="155.6" r=".51" fill="#000080"/>
<circle cx="103.9" cy="155.6" r=".51" fill="none" stroke="#000080" stroke-width=".13"/>
<circle cx="103.9" cy="153.1" r=".51" fill="#000080"/>
<circle cx="103.9" cy="153.1" r=".51" fill="none" stroke="#000080" stroke-width=".13"/>
<path d="M103.9 155.6v5.1h7.6" fill="none" stroke="#000080" stroke-width=".25"/>
<circle cx="103.9" cy="155.6" r=".51" fill="#000080"/>
<circle cx="103.9" cy="155.6" r=".51" fill="none" stroke="#000080" stroke-width=".13"/>
<path d="M109 148h2.5" fill="none" stroke="#000080" stroke-width=".25"/>
<circle cx="109" cy="148" r=".51" fill="#000080"/>
<circle cx="109" cy="148" r=".51" fill="none" stroke="#000080" stroke-width=".13"/>
<path d="M109 158.2h2.5" fill="none" stroke="#000080" stroke-width=".25"/>
<circle cx="109" cy="158.2" r=".51" fill="#000080"/>
<circle cx="109" cy="158.2" r=".51" fill="none" stroke="#000080" stroke-width=".13"/>
<path d="M111.5 145.5h-2.5v25.4" fill="none" stroke="#000080" stroke-width=".25"/>
<circle cx="109" cy="148" r=".51" fill="#000080"/>
<circle cx="109" cy="148" r=".51" fill="none" stroke="#000080" stroke-width=".13"/>
<circle cx="109" cy="158.2" r=".51" fill="#000080"/>
<circle cx="109" cy="158.2" r=".51" fill="none" stroke="#000080" stroke-width=".13"/>
<path d="M111.5 135.3h-43.2v15.3h-25.4" fill="none" stroke="#000080" stroke-width=".25"/>
<circle cx="45.4" cy="150.6" r=".51" fill="#000080"/>
<circle cx="45.4" cy="150.6" r=".51" fill="none" stroke="#000080" stroke-width=".13"/>
<circle cx="50.5" cy="150.6" r=".51" fill="#000080"/>
<circle cx="50.5" cy="150.6" r=".51" fill="none" stroke="#000080" stroke-width=".13"/>
<path d="M200.5 117.5h5.1M200.5 120.1v2.5M210.6 137.9h2M215.7 135.3h2M218.8 137.9h2M223.9 135.3h2" fill="none" stroke="#000" stroke-width=".25"/>
<g fill="none" stroke="#00f" stroke-width=".25">
<path d="M212.7 136.8h6v2h-6zM217.8 134.3h6v2h-6z"/>
<circle cx="200.5" cy="117.5" r="2.54"/>
</g>
<circle cx="200.5" cy="117.5" r=".63" fill="#00f"/>
<circle cx="200.5" cy="117.5" r=".63" fill="none" stroke="#00f" stroke-width=".13"/>
<path d="M197.9 125.2h5.1M198.7 125.9h3.5M199.5 126.7h2M200.2 127.5h.5M200.5 122.6v2.6" fill="none" stroke="#800000" stroke-width=".25"/>
<circle cx="218.3" cy="117.5" r="2.54" fill="none" stroke="#00f" stroke-width=".25"/>
<path d="M213.2 117.5h5.1M218.3 120.1v2.5" fill="none" stroke="#000" stroke-width=".25"/>
<circle cx="218.3" cy="117.5" r=".64" fill="#00f"/>
<circle cx="218.3" cy="117.5" r=".64" fill="none" stroke="#00f" stroke-width=".13"/>
<path d="M215.7 125.2h5.1M216.5 125.9h3.5M217.2 126.7h2.1M218 127.5h.5M218.3 122.6v2.6" fill="none" stroke="#800000" stroke-width=".25"/>
<path d="M205.6 117.5h2.5v20.4" fill="none" stroke="#000080" stroke-width=".25"/>
<circle cx="208.1" cy="137.9" r=".51" fill="#000080"/>
<circle cx="208.1" cy="137.9" r=".51" fill="none" stroke="#000080" stroke-width=".13"/>
<path d="M213.2 117.5h-2.6v17.8" fill="none" stroke="#000080" stroke-width=".25"/>
<circle cx="210.6" cy="135.3" r=".51" fill="#000080"/>
<circle cx="210.6" cy="135.3" r=".51" fill="none" stroke="#000080" stroke-width=".13"/>
<path d="M180.1 137.9h30.5" fill="none" stroke="#000080" stroke-width=".25"/>
<circle cx="208.1" cy="137.9" r=".51" fill="#000080"/>
<circle cx="208.1" cy="137.9" r=".51" fill="none" stroke="#000080" stroke-width=".13"/>
<path d="M180.1 135.3h35.6" fill="none" stroke="#000080" stroke-width=".25"/>
<circle cx="210.6" cy="135.3" r=".51" fill="#000080"/>
<circle cx="210.6" cy="135.3" r=".51" fill="none" stroke="#000080" stroke-width=".13"/>
<path d="M220.8 137.9h17.8M225.9 135.3h12.7" fill="none" stroke="#000080" stroke-width=".25"/>
<use href="#words"/>
</svg>
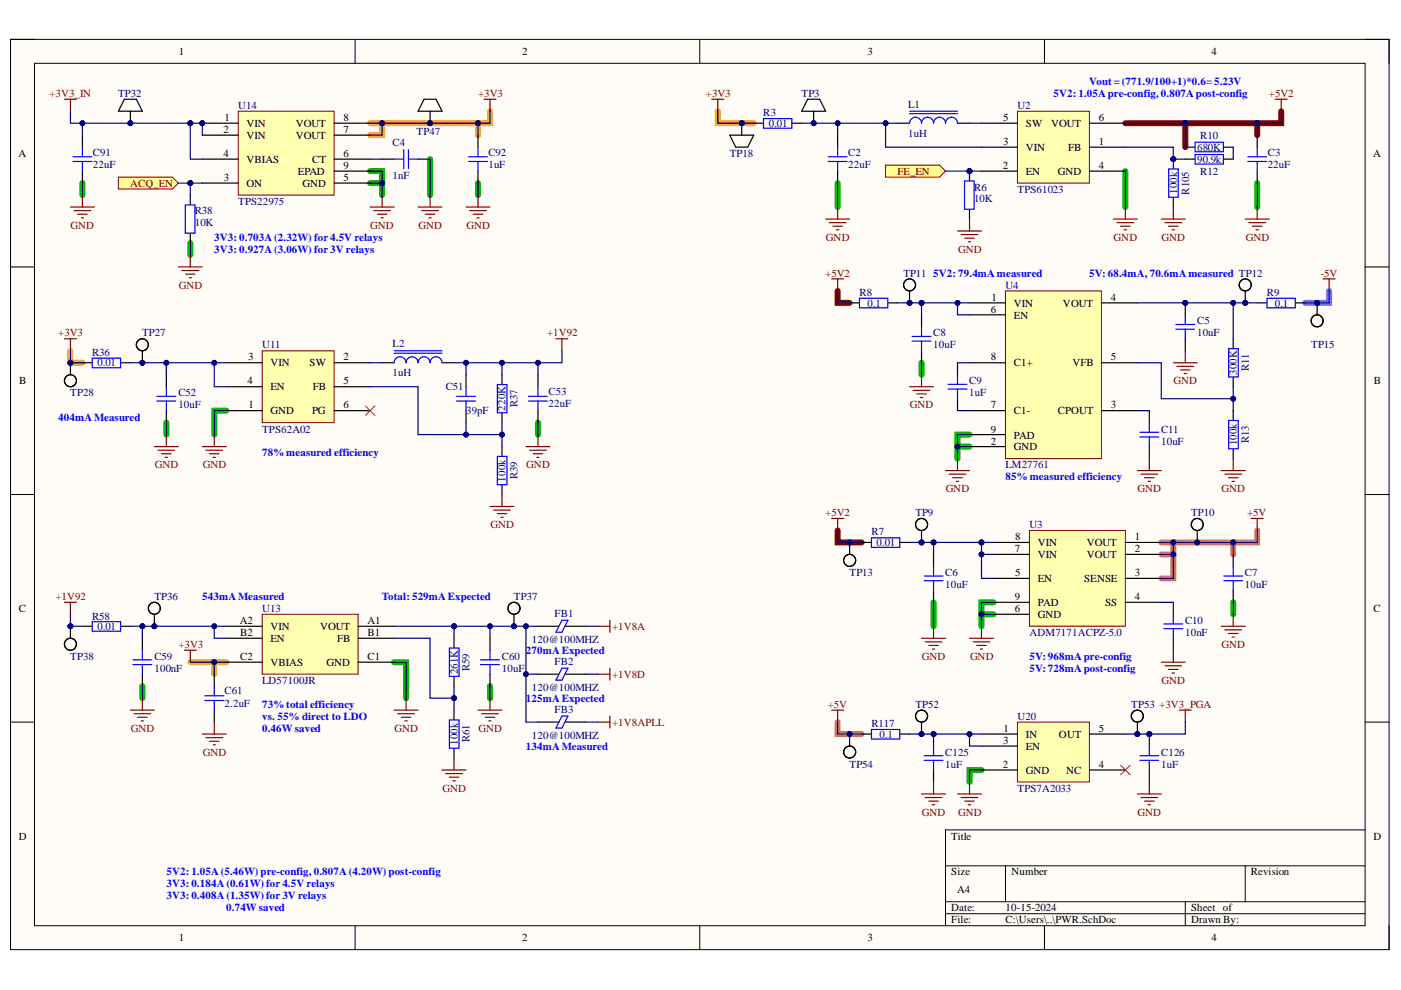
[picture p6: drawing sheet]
<svg xmlns="http://www.w3.org/2000/svg" width="297mm" height="210mm" viewBox="0 0 297 210" stroke-linecap="round" stroke-linejoin="round" font-family="sans-serif">
<defs><g id="words">
<g font-size="2.3">
<text x="37.9" y="11.7">1</text>
<text x="110.7" y="11.7">2</text>
<text x="183.9" y="11.7">3</text>
<text x="256.8" y="11.7">4</text>
<text x="47.4" y="28.1">2</text>
<text x="47.6" y="25.6">1</text>
<text x="52.3" y="26.9">VIN</text>
<text x="52.3" y="29.5">VIN</text>
<text x="62.7" y="26.9">VOUT</text>
<text x="62.7" y="29.5">VOUT</text>
<text x="72.8" y="25.6">8</text>
<text x="72.8" y="28.1">7</text>
<text x="212.7" y="25.6">5</text>
<text x="217.5" y="26.9">SW</text>
<text x="222.8" y="26.9">VOUT</text>
<text x="233" y="25.6">6</text>
<text x="3.9" y="33.3">A</text>
<text x="47.4" y="33.3">4</text>
<text x="52.3" y="34.6">VBIAS</text>
<text x="66.2" y="34.6">CT</text>
<text x="72.8" y="33.3">6</text>
<text x="72.8" y="35.8">9</text>
<text x="212.6" y="35.8">2</text>
<text x="212.7" y="30.8">3</text>
<text x="217.5" y="32">VIN</text>
<text x="226.5" y="32">FB</text>
<text x="233" y="35.8">4</text>
<text x="233" y="30.8">1</text>
<text x="291.1" y="33.3">A</text>
<text x="47.5" y="38.4">3</text>
<text x="52.3" y="39.6">ON</text>
<text x="63.1" y="37.1">EPAD</text>
<text x="64.1" y="39.6">GND</text>
<text x="72.8" y="38.4">5</text>
<text x="217.5" y="37.1">EN</text>
<text x="224.3" y="37.1">GND</text>
<text x="210.2" y="63.7">1</text>
<text x="215" y="65">VIN</text>
<text x="225.4" y="65">VOUT</text>
<text x="235.5" y="63.7">4</text>
<text x="210.1" y="66.3">6</text>
<text x="215" y="67.5">EN</text>
<text x="52.6" y="76.4">3</text>
<text x="57.4" y="77.7">VIN</text>
<text x="65.6" y="77.7">SW</text>
<text x="72.8" y="76.4">2</text>
<text x="210.1" y="76.4">8</text>
<text x="215" y="77.7">C1+</text>
<text x="227.4" y="77.7">VFB</text>
<text x="235.5" y="76.4">5</text>
<text x="4.1" y="81.5">B</text>
<text x="52.5" y="81.5">4</text>
<text x="57.4" y="82.7">EN</text>
<text x="66.3" y="82.7">FB</text>
<text x="72.8" y="81.5">5</text>
<text x="291.3" y="81.5">B</text>
<text x="52.7" y="86.6">1</text>
<text x="57.4" y="87.8">GND</text>
<text x="66.2" y="87.8">PG</text>
<text x="72.8" y="86.6">6</text>
<text x="210.1" y="86.6">7</text>
<text x="215" y="87.8">C1-</text>
<text x="224.3" y="87.8">CPOUT</text>
<text x="235.5" y="86.6">3</text>
<text x="210.1" y="94.2">2</text>
<text x="210.1" y="91.7">9</text>
<text x="215" y="95.5">GND</text>
<text x="215" y="93">PAD</text>
<text x="215.1" y="117.1">7</text>
<text x="215.2" y="114.5">8</text>
<text x="220" y="115.8">VIN</text>
<text x="220" y="118.3">VIN</text>
<text x="230.4" y="115.8">VOUT</text>
<text x="230.4" y="118.3">VOUT</text>
<text x="240.6" y="114.5">1</text>
<text x="240.6" y="117.1">2</text>
<text x="215.2" y="122.1">5</text>
<text x="220" y="123.4">EN</text>
<text x="229.9" y="123.4">SENSE</text>
<text x="240.6" y="122.1">3</text>
<text x="4" y="129.7">C</text>
<text x="215.1" y="129.7">6</text>
<text x="215.1" y="127.2">9</text>
<text x="220" y="131">GND</text>
<text x="220" y="128.5">PAD</text>
<text x="234.3" y="128.5">SS</text>
<text x="240.6" y="127.2">4</text>
<text x="291.2" y="129.7">C</text>
<text x="50.8" y="132.3">A2</text>
<text x="50.9" y="134.8">B2</text>
<text x="57.4" y="133.6">VIN</text>
<text x="57.4" y="136.1">EN</text>
<text x="67.8" y="133.6">VOUT</text>
<text x="71.5" y="136.1">FB</text>
<text x="77.9" y="132.3">A1</text>
<text x="77.9" y="134.8">B1</text>
<text x="50.9" y="139.9">C2</text>
<text x="57.4" y="141.2">VBIAS</text>
<text x="69.2" y="141.2">GND</text>
<text x="77.9" y="139.9">C1</text>
<text x="212.8" y="155.2">1</text>
<text x="233" y="155.2">5</text>
<text x="212.7" y="157.7">3</text>
<text x="217.5" y="156.5">IN</text>
<text x="217.5" y="159">EN</text>
<text x="224.5" y="156.5">OUT</text>
<text x="212.6" y="162.8">2</text>
<text x="217.5" y="164.1">GND</text>
<text x="226.1" y="164.1">NC</text>
<text x="233" y="162.8">4</text>
<text x="4" y="178">D</text>
<text x="201.7" y="178">Title</text>
<text x="291.2" y="178">D</text>
<text x="201.7" y="185.6">Size</text>
<text x="214.5" y="185.6">Number</text>
<text x="265.2" y="185.6">Revision</text>
<text x="203" y="189.4">A4</text>
<text x="201.7" y="193.2">Date:</text>
<text x="201.7" y="195.8">File:</text>
<text x="213.2" y="193.2">10-15-2024</text>
<text x="213.2" y="195.8">C:\Users\..\PWR.SchDoc</text>
<text x="252.5" y="193.2">Sheet of</text>
<text x="252.5" y="195.8">Drawn By:</text>
<text x="37.9" y="199.6">1</text>
<text x="110.7" y="199.6">2</text>
<text x="183.9" y="199.6">3</text>
<text x="256.8" y="199.6">4</text>
</g>
<g font-size="2.3" fill="#00f">
<text x="231" y="18">Vout = (771.9/100+1)*0.6= 5.23V</text>
<text x="223.3" y="20.5">5V2: 1.05Apre-config, 0.807Apost-config</text>
<text x="45.4" y="51">3V3: 0.703A(2.32W) for 4.5V relays</text>
<text x="45.4" y="53.6">3V3: 0.927A(3.06W) for 3V relays</text>
<text x="197.9" y="58.7">5V2: 79.4mAmeasured</text>
<text x="231" y="58.7">5V: 68.4mA, 70.6mAmeasured TP12</text>
<text x="12.4" y="89.2">404mAMeasured</text>
<text x="55.6" y="96.8">78% measured efficiency</text>
<text x="213.2" y="101.9">85% measured efficiency</text>
<text x="42.9" y="127.2">543mAMeasured</text>
<text x="81" y="127.2">Total: 529mAExpected</text>
<text x="111.5" y="138.6">270mAExpected</text>
<text x="218.3" y="139.9">5V: 968mApre-config</text>
<text x="218.3" y="142.4">5V: 728mApost-config</text>
<text x="111.5" y="148.9">125mAExpected</text>
<text x="55.6" y="150.1">73% total efficiency</text>
<text x="55.6" y="152.7">vs. 55% direct to LDO</text>
<text x="55.6" y="155.2">0.46W saved</text>
<text x="111.5" y="159">134mAMeasured</text>
<text x="35.3" y="185.6">5V2: 1.05A(5.46W) pre-config, 0.807A(4.20W) post-config</text>
<text x="35.3" y="188.2">3V3: 0.184A(0.61W) for 4.5V relays</text>
<text x="35.3" y="190.7">3V3: 0.408A(1.35W) for 3V relays</text>
<text x="48" y="193.2">0.74W saved</text>
</g>
<g font-size="2.3" fill="#800000">
<text x="10.5" y="20.5">+3V3_IN</text>
<text x="101.4" y="20.5">+3V3</text>
<text x="149.7" y="20.5">+3V3</text>
<text x="269" y="20.5">+5V2</text>
<text x="27.6" y="39.6">ACQ_EN</text>
<text x="190.3" y="37.1">FE_EN</text>
<text x="15" y="48.5">GND</text>
<text x="78.5" y="48.5">GND</text>
<text x="88.7" y="48.5">GND</text>
<text x="98.9" y="48.5">GND</text>
<text x="175.1" y="51">GND</text>
<text x="203.1" y="53.6">GND</text>
<text x="236.1" y="51">GND</text>
<text x="246.3" y="51">GND</text>
<text x="264.1" y="51">GND</text>
<text x="175" y="58.7">+5V2</text>
<text x="280" y="58.7">-5V</text>
<text x="37.9" y="61.2">GND</text>
<text x="12.4" y="71.3">+3V3</text>
<text x="116" y="71.3">+1V92</text>
<text x="248.8" y="81.5">GND</text>
<text x="192.9" y="86.6">GND</text>
<text x="32.8" y="99.3">GND</text>
<text x="43" y="99.3">GND</text>
<text x="111.6" y="99.3">GND</text>
<text x="200.5" y="104.4">GND</text>
<text x="241.2" y="104.4">GND</text>
<text x="259" y="104.4">GND</text>
<text x="104" y="112">GND</text>
<text x="175" y="109.5">+5V2</text>
<text x="264.5" y="109.5">+5V</text>
<text x="11.8" y="127.2">+1V92</text>
<text x="37.8" y="137.4">+3V3</text>
<text x="129.8" y="133.6">+1V8A</text>
<text x="259" y="137.4">GND</text>
<text x="129.8" y="143.7">+1V8D</text>
<text x="195.4" y="139.9">GND</text>
<text x="205.7" y="139.9">GND</text>
<text x="246.3" y="145">GND</text>
<text x="27.7" y="155.2">GND</text>
<text x="83.7" y="155.2">GND</text>
<text x="101.4" y="155.2">GND</text>
<text x="129.8" y="153.9">+1V8APLL</text>
<text x="175.5" y="150.1">+5V</text>
<text x="43" y="160.3">GND</text>
<text x="93.8" y="167.9">GND</text>
<text x="195.4" y="172.9">GND</text>
<text x="203.1" y="172.9">GND</text>
<text x="241.2" y="172.9">GND</text>
</g>
<g font-size="2.3" fill="#000080">
<text x="25" y="20.5">TP32</text>
<text x="50.5" y="23.1">U14</text>
<text x="170" y="20.5">TP3</text>
<text x="192.5" y="22.8">L1</text>
<text x="215.7" y="23.1">U2</text>
<text x="88.3" y="28.6">TP47</text>
<text x="161.8" y="24.7">R3</text>
<text x="163" y="26.9">0.01</text>
<text x="192.5" y="29">1uH</text>
<text x="254.5" y="29.5">R10</text>
<text x="19.7" y="33">C91</text>
<text x="19.7" y="35.6">22uF</text>
<text x="83.2" y="31">C4</text>
<text x="103.5" y="33">C92</text>
<text x="103.5" y="35.6">1uF</text>
<text x="154.7" y="33.3">TP18</text>
<text x="179.9" y="33">C2</text>
<text x="179.9" y="35.6">22uF</text>
<text x="253.8" y="34.6">90.9k</text>
<text x="253.8" y="32">680K</text>
<text x="268.8" y="33">C3</text>
<text x="268.8" y="35.6">22uF</text>
<text x="83.2" y="38">1nF</text>
<text x="206.5" y="40.4">R6</text>
<text x="215.7" y="40.9">TPS61023</text>
<text x="249.6" y="41.1" transform="rotate(-90 249.6 41.1)">100k</text>
<text x="252.1" y="41.2" transform="rotate(-90 252.1 41.2)">R105</text>
<text x="254.5" y="37.1">R12</text>
<text x="41.3" y="45.5">R38</text>
<text x="50.5" y="43.4">TPS22975</text>
<text x="206.5" y="42.9">10K</text>
<text x="41.3" y="48">10K</text>
<text x="191.5" y="58.7">TP11</text>
<text x="182.2" y="62.8">R8</text>
<text x="183.9" y="65">0.1</text>
<text x="213.2" y="61.2">U4</text>
<text x="268.6" y="62.8">R9</text>
<text x="270.3" y="65">0.1</text>
<text x="30.1" y="71.3">TP27</text>
<text x="197.9" y="71.3">C8</text>
<text x="253.8" y="68.8">C5</text>
<text x="253.8" y="71.3">10uF</text>
<text x="19.5" y="75.5">R36</text>
<text x="20.6" y="77.7">0.01</text>
<text x="55.6" y="73.9">U11</text>
<text x="83.2" y="73.6">L2</text>
<text x="197.9" y="73.9">10uF</text>
<text x="278" y="73.9">TP15</text>
<text x="83.2" y="79.7">1uH</text>
<text x="94.5" y="82.7">C51</text>
<text x="116.3" y="83.8">C53</text>
<text x="205.5" y="81.5">C9</text>
<text x="262.3" y="79.5" transform="rotate(-90 262.3 79.5)">300K</text>
<text x="264.8" y="78.7" transform="rotate(-90 264.8 78.7)">R11</text>
<text x="14.9" y="84">TP28</text>
<text x="37.8" y="84">C52</text>
<text x="37.8" y="86.6">10uF</text>
<text x="98.8" y="87.8">39pF</text>
<text x="107.2" y="87.1" transform="rotate(-90 107.2 87.1)">220K</text>
<text x="109.7" y="86.4" transform="rotate(-90 109.7 86.4)">R37</text>
<text x="116.3" y="86.3">22uF</text>
<text x="205.5" y="84">1uF</text>
<text x="55.6" y="91.7">TPS62A02</text>
<text x="246.2" y="91.7">C11</text>
<text x="246.2" y="94.2">10uF</text>
<text x="262.3" y="94.4" transform="rotate(-90 262.3 94.4)">100k</text>
<text x="264.8" y="94" transform="rotate(-90 264.8 94)">R13</text>
<text x="109.7" y="101.6" transform="rotate(-90 109.7 101.6)">R39</text>
<text x="213.2" y="99.3">LM27761</text>
<text x="107.2" y="102.1" transform="rotate(-90 107.2 102.1)">100k</text>
<text x="184.8" y="113.5">R7</text>
<text x="194.1" y="109.5">TP9</text>
<text x="218.3" y="112">U3</text>
<text x="252.5" y="109.5">TP10</text>
<text x="185.9" y="115.8">0.01</text>
<text x="180.1" y="122.1">TP13</text>
<text x="200.4" y="122.1">C6</text>
<text x="200.4" y="124.7">10uF</text>
<text x="264" y="122.1">C7</text>
<text x="264" y="124.7">10uF</text>
<text x="19.5" y="131.4">R58</text>
<text x="32.7" y="127.2">TP36</text>
<text x="55.6" y="129.7">U13</text>
<text x="109" y="127.2">TP37</text>
<text x="117.6" y="130.8">FB1</text>
<text x="20.6" y="133.6">0.01</text>
<text x="112.8" y="136.3">120@100MHZ</text>
<text x="218.3" y="134.8">ADM7171ACPZ-5.0</text>
<text x="251.3" y="132.3">C10</text>
<text x="251.3" y="134.8">10nF</text>
<text x="14.9" y="139.9">TP38</text>
<text x="32.7" y="139.9">C59</text>
<text x="32.7" y="142.4">100nF</text>
<text x="97" y="142.9" transform="rotate(-90 97 142.9)">261K</text>
<text x="99.6" y="142.3" transform="rotate(-90 99.6 142.3)">R59</text>
<text x="106.4" y="139.9">C60</text>
<text x="106.4" y="142.4">10uF</text>
<text x="117.6" y="140.9">FB2</text>
<text x="47.6" y="147.2">C61</text>
<text x="47.6" y="149.9">2.2uF</text>
<text x="55.6" y="145">LD57100JR</text>
<text x="112.8" y="146.5">120@100MHZ</text>
<text x="117.6" y="151.1">FB3</text>
<text x="184.8" y="154.2">R117</text>
<text x="194.1" y="150.1">TP52</text>
<text x="215.7" y="152.7">U20</text>
<text x="239.8" y="150.1">TP53 +3V3_PGA</text>
<text x="97" y="157.9" transform="rotate(-90 97 157.9)">100k</text>
<text x="99.6" y="157.4" transform="rotate(-90 99.6 157.4)">R61</text>
<text x="112.8" y="156.7">120@100MHZ</text>
<text x="186.5" y="156.5">0.1</text>
<text x="200.4" y="160.3">C125</text>
<text x="246.2" y="160.3">C126</text>
<text x="180.1" y="162.8">TP54</text>
<text x="200.4" y="162.8">1uF</text>
<text x="215.7" y="167.9">TPS7A2033</text>
<text x="246.2" y="162.8">1uF</text>
</g>
</g></defs>
<path d="M2.2 8.3h292.3v193h-292.3z" fill-rule="evenodd" fill="#fffcf8"/>
<path d="M2.2 8.3h292.3v193h-292.3z" fill="none" stroke="#000" stroke-width=".21"/>
<path d="M7.3 13.4h282.1v182.9h-282.1z" fill-rule="evenodd" fill="#fffcf8"/>
<g fill="none" stroke="#000" stroke-width=".21">
<path d="M2.2 8.3h5.1M7.3 13.4h282.1v182.9h-282.1zM75.3 8.3v5.1M148.4 8.3v5.1M221.4 8.3v5.1M289.4 8.3h5.1v5.1M2.2 56.6h5.1M289.4 56.6h5.1M2.2 104.8h5.1M289.4 104.9h5.1M2.2 153.1h5.1M289.4 153.1h5.1"/>
<path d="M289.4 176h-88.9v20.3M75.3 196.3v5M148.4 196.3v5M200.5 183.6h88.9M200.5 191.2h88.9M200.5 193.7h88.9M213.2 183.6v7.6M221.4 196.3v5M251.3 191.2v5.1M264 183.6v7.6M294.5 196.3v5"/>
</g>
<g fill="none" stroke="#00be00" stroke-width="1.3">
<path d="M17.5 38.8v2.6M78.5 38.8h2.5v2.6M78.5 36.3h2.5v2.5M91.2 33.7v7.7M101.3 38.8v2.6M177.6 38.8v5.1M238.6 36.3v7.6M266.6 38.8v5.1M40.3 51.5v2.6M195.4 76.9v2.6M35.3 89.6v2.5M48 87.1h-2.6v5"/>
<path d="M114.1 89.6v2.5M203 94.7v2.5M205.6 92.2h-2.6v2.5h2.6M197.9 127.7v5.1M208.1 130.2h2.5M210.6 127.7h-2.5v5.1M261.5 127.7v2.5M30.2 145.5v2.5M83.6 140.4h2.5v7.6M103.9 145.5v2.5M208.1 163.3h-2.5v2.5"/>
</g>
<path d="M78.5 26.1h2.5M101.3 26.1v2.6M103.9 23.6v2.5h-22.9v2.6h-2.5M152.2 23.6v2.5h7.6M14.9 74.4v2.5h2.6M40.3 140.4h5.1M48 140.4h-2.6v2.5" fill="none" stroke="#f90" stroke-width="1.3"/>
<path d="M238.6 26.1h12.7M251.3 26.1v5.1M266.6 26.1v2.6M271.6 23.6v2.5h-20.3M177.6 61.7v2.5h2.5M177.6 112.5v2.5h5.1" fill="none" stroke="#800000" stroke-width="1.3"/>
<path d="M281.8 61.7v2.5h-5.1" fill="none" stroke="#6e6eff" stroke-width="1.3"/>
<path d="M246.2 115h2.6v2.5h-2.6M248.8 115h12.7v2.5M248.8 117.5v5.1h-2.6M266.6 112.5v2.5h-5.1M177.6 153.1v2.5h5.1" fill="none" stroke="#ff6e6e" stroke-width="1.3"/>
<path d="M177.6 28.7v2.5M177.6 36.3v2.5M266.6 28.7v2.5M266.6 36.3v2.5" fill="none" stroke="#000" stroke-width=".25"/>
<path d="M175.6 34.2h4M175.6 33.2h4M177.6 31.2v2M177.6 34.2v2.1M264.6 34.2h4M264.6 33.2h4M266.6 31.2v2M266.6 34.2v2.1" fill="none" stroke="#00f" stroke-width=".25"/>
<path d="M270.4 21h2.5M271.6 21v2.6M175.1 46.4h5M175.8 47.2h3.6M176.6 48h2M177.3 48.7h.5M177.6 43.9v2.5M264 46.4h5.1M264.8 47.2h3.5M265.5 48h2.1M266.3 48.7h.5M266.6 43.9v2.5" fill="none" stroke="#800000" stroke-width=".25"/>
<path d="M215.7 23.6h15.3v15.2h-15.3z" fill-rule="evenodd" fill="#ffffb0"/>
<path d="M215.7 23.6h15.3v15.2h-15.3z" fill="none" stroke="#800000" stroke-width=".21"/>
<path d="M159.8 26.1h2M168 26.1h2M190.3 26.1h2.5M203 26.1h2.6M208.1 31.2h7.6M208.1 26.1h7.6M208.1 36.3h7.6M231 31.2h7.6M231 26.1h7.6M231 36.3h7.6" fill="none" stroke="#000" stroke-width=".25"/>
<path d="M236.1 46.4h5M236.8 47.2h3.6M237.6 48h2M238.3 48.7h.5M238.6 43.9v2.5" fill="none" stroke="#800000" stroke-width=".25"/>
<path d="M161.9 25.1h6v2.1h-6zM192.8 26.1a1.27 1.27 0 0 1 1.3-1.2 1.27 1.27 0 0 1 1.3 1.2 1.27 1.27 0 0 1 1.3-1.2 1.27 1.27 0 0 1 1.2 1.2 1.27 1.27 0 0 1 1.3-1.2 1.27 1.27 0 0 1 1.3 1.2 1.27 1.27 0 0 1 1.2-1.2 1.27 1.27 0 0 1 1.3 1.2M192.8 24.1h10.2M192.8 23.6h10.2" fill="none" stroke="#00f" stroke-width=".25"/>
<circle cx="172.5" cy="26.1" r=".51" fill="#000080"/>
<circle cx="172.5" cy="26.1" r=".51" fill="none" stroke="#000080" stroke-width=".21"/>
<path d="M172.5 23.6v2.5" fill="none" stroke="#000" stroke-width=".25"/>
<circle cx="172.5" cy="26.1" r=".51" fill="#000080"/>
<circle cx="172.5" cy="26.1" r=".51" fill="none" stroke="#000080" stroke-width=".21"/>
<path d="M171.2 21h2.6l1.3 2.6h-5.1z" fill="none" stroke="#000" stroke-width=".25"/>
<circle cx="205.6" cy="36.3" r=".51" fill="#000080"/>
<circle cx="205.6" cy="36.3" r=".51" fill="none" stroke="#000080" stroke-width=".21"/>
<path d="M205.6 36.3v2M205.6 44.4v2" fill="none" stroke="#000" stroke-width=".25"/>
<circle cx="205.6" cy="36.3" r=".51" fill="#000080"/>
<circle cx="205.6" cy="36.3" r=".51" fill="none" stroke="#000080" stroke-width=".21"/>
<path d="M204.5 38.4h2v6h-2z" fill="none" stroke="#00f" stroke-width=".25"/>
<path d="M203 49h5.1M203.8 49.7h3.5M204.5 50.5h2.1M205.3 51.3h.5M205.6 46.4v2.6" fill="none" stroke="#800000" stroke-width=".25"/>
<circle cx="42.9" cy="26.1" r=".51" fill="#000080"/>
<circle cx="42.9" cy="26.1" r=".51" fill="none" stroke="#000080" stroke-width=".21"/>
<path d="M50.5 23.6h20.3v17.8h-20.3z" fill-rule="evenodd" fill="#ffffb0"/>
<path d="M50.5 23.6h20.3v17.8h-20.3z" fill="none" stroke="#800000" stroke-width=".21"/>
<path d="M42.9 26.1h7.6M42.9 38.8h7.6M70.8 26.1h7.7M70.8 28.7h7.7M70.8 38.8h7.7" fill="none" stroke="#000" stroke-width=".25"/>
<circle cx="42.9" cy="26.1" r=".51" fill="#000080"/>
<circle cx="42.9" cy="26.1" r=".51" fill="none" stroke="#000080" stroke-width=".21"/>
<path d="M17.5 28.7v2.5M17.5 36.3v2.5M42.9 28.7h7.6M42.9 33.7h7.6M70.8 33.7h7.7M70.8 36.3h7.7M101.3 28.7v2.5M101.3 36.3v2.5" fill="none" stroke="#000" stroke-width=".25"/>
<path d="M13.7 21h2.5M14.9 21v2.6M14.9 43.9h5.1M15.7 44.7h3.6M16.5 45.4h2M17.2 46.2h.5M17.5 41.4v2.5M98.8 43.9h5.1M99.6 44.7h3.5M100.3 45.4h2.1M101.1 46.2h.5M101.3 41.4v2.5" fill="none" stroke="#800000" stroke-width=".25"/>
<path d="M15.5 34.2h4M15.5 33.2h4M17.5 31.2v2M17.5 34.2v2.1M99.3 34.2h4M99.3 33.2h4M101.3 31.2v2M101.3 34.2v2.1" fill="none" stroke="#00f" stroke-width=".25"/>
<circle cx="248.8" cy="33.7" r=".51" fill="#000080"/>
<circle cx="248.8" cy="33.7" r=".51" fill="none" stroke="#000080" stroke-width=".21"/>
<path d="M248.8 33.7v2" fill="none" stroke="#000" stroke-width=".25"/>
<circle cx="248.8" cy="33.7" r=".51" fill="#000080"/>
<circle cx="248.8" cy="33.7" r=".51" fill="none" stroke="#000080" stroke-width=".21"/>
<path d="M81 33.7h2.6M88.6 33.7h2.6M251.3 33.7h2M251.3 31.2h2M259.5 33.7h2M259.5 31.2h2M40.3 41.4v2M40.3 49.5v2M248.8 41.9v2" fill="none" stroke="#000" stroke-width=".25"/>
<path d="M83.6 33.7h2M85.6 31.7v4M86.6 33.7h2M86.6 31.7v4M247.8 35.8h2v6h-2zM253.4 32.8h6v2h-6zM253.4 30.1h6v2.1h-6zM39.3 43.4h2v6h-2z" fill="none" stroke="#00f" stroke-width=".25"/>
<g fill="none" stroke="#800000" stroke-width=".25">
<path d="M102.6 21h2.6M103.9 21v2.6M37.8 56.6h5.1M38.6 57.4h3.5M39.3 58.1h2.1M40.1 58.9h.5M40.3 54.1v2.5M78.5 43.9h5.1M79.2 44.7h3.6M80 45.4h2M80.8 46.2h.5M81 41.4v2.5"/>
<path d="M88.6 43.9h5.1M89.4 44.7h3.6M90.2 45.4h2M90.9 46.2h.5M91.2 41.4v2.5M246.2 46.4h5.1M247 47.2h3.5M247.7 48h2.1M248.5 48.7h.5M248.8 43.9v2.5"/>
</g>
<circle cx="157.3" cy="26.1" r=".51" fill="#000080"/>
<circle cx="157.3" cy="26.1" r=".51" fill="none" stroke="#000080" stroke-width=".21"/>
<path d="M157.3 26.1v2.6" fill="none" stroke="#000" stroke-width=".25"/>
<circle cx="157.3" cy="26.1" r=".51" fill="#000080"/>
<circle cx="157.3" cy="26.1" r=".51" fill="none" stroke="#000080" stroke-width=".21"/>
<path d="M154.7 28.7h5.1l-1.3 2.5h-2.5z" fill="none" stroke="#000" stroke-width=".25"/>
<circle cx="27.6" cy="26.1" r=".51" fill="#000080"/>
<circle cx="27.6" cy="26.1" r=".51" fill="none" stroke="#000080" stroke-width=".21"/>
<path d="M27.6 23.6v2.5" fill="none" stroke="#000" stroke-width=".25"/>
<circle cx="27.6" cy="26.1" r=".51" fill="#000080"/>
<circle cx="27.6" cy="26.1" r=".51" fill="none" stroke="#000080" stroke-width=".21"/>
<path d="M26.4 21h2.5l1.3 2.6h-5.1z" fill="none" stroke="#000" stroke-width=".25"/>
<circle cx="91.2" cy="26.1" r=".51" fill="#000080"/>
<circle cx="91.2" cy="26.1" r=".51" fill="none" stroke="#000080" stroke-width=".21"/>
<path d="M91.2 23.6v2.5" fill="none" stroke="#000" stroke-width=".25"/>
<circle cx="91.2" cy="26.1" r=".51" fill="#000080"/>
<circle cx="91.2" cy="26.1" r=".51" fill="none" stroke="#000080" stroke-width=".21"/>
<path d="M89.9 21h2.6l1.2 2.6h-5.1z" fill="none" stroke="#000" stroke-width=".25"/>
<path d="M187.8 35h11.4l1.3 1.3-1.3 1.3h-11.4z" fill-rule="evenodd" fill="#ffff80"/>
<path d="M187.8 35h11.4l1.3 1.3-1.3 1.3h-11.4z" fill="none" stroke="#800000" stroke-width=".21"/>
<path d="M25.1 37.6h11.4l1.3 1.2-1.3 1.3h-11.4z" fill-rule="evenodd" fill="#ffff80"/>
<path d="M25.1 37.6h11.4l1.3 1.2-1.3 1.3h-11.4z" fill="none" stroke="#800000" stroke-width=".21"/>
<path d="M150.9 21h2.5M152.2 21v2.6" fill="none" stroke="#800000" stroke-width=".25"/>
<path d="M55.6 74.4h15.2v15.2h-15.2z" fill-rule="evenodd" fill="#ffffb0"/>
<path d="M55.6 74.4h15.2v15.2h-15.2z" fill="none" stroke="#800000" stroke-width=".21"/>
<g fill="none" stroke="#000" stroke-width=".25">
<path d="M17.5 76.9h2M25.6 76.9h2M35.3 79.5v2.5M48 76.9h7.6M70.8 76.9h7.7M81 76.9h2.6M93.7 76.9h2.6M98.8 79.5v2.5M106.4 79.5v1.9M114.1 79.5v2.5M35.3 87.1v2.5M48 87.1h7.6"/>
<path d="M48 82h7.6M70.8 87.1h7.7M70.8 82h7.7M98.8 87.1v2.5M106.4 87.6v2M106.4 94.7v2M114.1 87.1v2.5M106.4 102.8v2"/>
</g>
<g fill="none" stroke="#800000" stroke-width=".25">
<path d="M117.9 71.8h2.5M119.1 71.8v2.6M32.7 94.7h5.1M33.5 95.4h3.5M34.2 96.2h2.1M35 97h.5M35.3 92.1v2.6M42.9 94.7h5.1M43.7 95.4h3.5M44.4 96.2h2.1M45.2 97h.5M45.4 92.1v2.6"/>
<path d="M111.5 94.7h5.1M112.3 95.4h3.5M113 96.2h2.1M113.8 97h.5M114.1 92.1v2.6M103.9 107.4h5.1M104.6 108.2h3.6M105.4 108.9h2M106.2 109.7h.5M106.4 104.8v2.6"/>
</g>
<g fill="none" stroke="#00f" stroke-width=".25">
<path d="M19.6 75.9h6v2.1h-6zM83.6 76.9a1.27 1.27 0 0 1 1.2-1.3 1.27 1.27 0 0 1 1.3 1.3 1.27 1.27 0 0 1 1.3-1.3 1.27 1.27 0 0 1 1.2 1.3 1.27 1.27 0 0 1 1.3-1.3 1.27 1.27 0 0 1 1.3 1.3 1.27 1.27 0 0 1 1.3-1.3 1.27 1.27 0 0 1 1.2 1.3M83.6 74.9h10.1M83.6 74.4h10.1M33.3 85h4M33.3 84h4M35.3 82v2M35.3 85v2.1M96.8 85h4M96.8 84h4M98.8 82v2M98.8 85v2.1"/>
<path d="M105.5 81.5h2v6h-2zM105.5 96.8h2v6h-2zM112.1 85h4M112.1 84h4M114.1 82v2M114.1 85v2.1"/>
</g>
<path d="M77.5 86.1l2 2M79.5 86.1l-2 2" fill="none" stroke="#f00" stroke-width=".21"/>
<circle cx="14.9" cy="76.9" r=".51" fill="#000080"/>
<circle cx="14.9" cy="76.9" r=".51" fill="none" stroke="#000080" stroke-width=".21"/>
<path d="M14.9 76.9v2.6" fill="none" stroke="#000" stroke-width=".25"/>
<circle cx="14.9" cy="76.9" r=".51" fill="#000080"/>
<circle cx="14.9" cy="76.9" r=".51" fill="none" stroke="#000080" stroke-width=".21"/>
<circle cx="14.9" cy="80.7" r="1.27" fill="none" stroke="#000" stroke-width=".25"/>
<circle cx="30.2" cy="76.9" r=".51" fill="#000080"/>
<circle cx="30.2" cy="76.9" r=".51" fill="none" stroke="#000080" stroke-width=".21"/>
<path d="M30.2 74.4v2.5" fill="none" stroke="#000" stroke-width=".25"/>
<circle cx="30.2" cy="76.9" r=".51" fill="#000080"/>
<circle cx="30.2" cy="76.9" r=".51" fill="none" stroke="#000080" stroke-width=".21"/>
<g fill="none" stroke="#000" stroke-width=".25">
<path d="M96.3 135.3v2M103.9 135.3v2.6M114.1 132.8h4.4M119.8 132.8h4.4M96.3 143.5v2M96.3 150.6v2M96.3 158.7v2M103.9 142.9v2.6M114.1 142.9h4.4M119.8 142.9h4.4"/>
<circle cx="30.2" cy="73.1" r="1.27"/>
</g>
<g fill="none" stroke="#800000" stroke-width=".25">
<path d="M13.7 71.8h2.5M14.9 71.8v2.6M126.8 132.8h2.5M129.3 131.5v2.5M101.3 150.6h5.1M102.1 151.3h3.6M102.9 152.1h2M103.6 152.8h.5M103.9 148v2.6M126.8 142.9h2.5M129.3 141.7v2.5M93.7 163.3h5.1"/>
<path d="M94.5 164h3.5M95.2 164.8h2.1M96 165.5h.5M96.3 160.7v2.6"/>
</g>
<path d="M95.3 137.4h2v6h-2zM101.9 139.9h4M103.9 137.9v2M119.1 131.5h1.3l-1.3 2.5h-1.2zM95.3 152.6h2v6h-2zM101.9 140.9h4M103.9 140.9v2M119.1 141.7h1.3l-1.3 2.5h-1.2z" fill="none" stroke="#00f" stroke-width=".25"/>
<circle cx="109" cy="132.8" r=".51" fill="#000080"/>
<circle cx="109" cy="132.8" r=".51" fill="none" stroke="#000080" stroke-width=".21"/>
<path d="M109 130.2v2.6" fill="none" stroke="#000" stroke-width=".25"/>
<circle cx="109" cy="132.8" r=".51" fill="#000080"/>
<circle cx="109" cy="132.8" r=".51" fill="none" stroke="#000080" stroke-width=".21"/>
<circle cx="109" cy="129" r="1.27" fill="none" stroke="#000" stroke-width=".25"/>
<path d="M55.6 130.2h20.3v12.7h-20.3z" fill-rule="evenodd" fill="#ffffb0"/>
<path d="M55.6 130.2h20.3v12.7h-20.3z" fill="none" stroke="#800000" stroke-width=".21"/>
<path d="M17.5 132.8h2M25.6 132.8h2M30.2 135.3v2.6M48 132.8h7.6M48 135.3h7.6M75.9 132.8h7.7M75.9 135.3h7.7M30.2 142.9v2.6M48 140.4h7.6M75.9 140.4h7.7" fill="none" stroke="#000" stroke-width=".25"/>
<path d="M19.6 131.8h6v2h-6zM28.2 139.9h4M30.2 137.9v2M28.2 140.9h4M30.2 140.9v2" fill="none" stroke="#00f" stroke-width=".25"/>
<path d="M27.6 150.6h5.1M28.4 151.3h3.6M29.2 152.1h2M29.9 152.8h.5M30.2 148v2.6" fill="none" stroke="#800000" stroke-width=".25"/>
<circle cx="14.9" cy="132.8" r=".51" fill="#000080"/>
<circle cx="14.9" cy="132.8" r=".51" fill="none" stroke="#000080" stroke-width=".21"/>
<path d="M14.9 132.8v2.5" fill="none" stroke="#000" stroke-width=".25"/>
<circle cx="14.9" cy="132.8" r=".51" fill="#000080"/>
<circle cx="14.9" cy="132.8" r=".51" fill="none" stroke="#000080" stroke-width=".21"/>
<circle cx="14.9" cy="136.6" r="1.27" fill="none" stroke="#000" stroke-width=".25"/>
<circle cx="32.7" cy="132.8" r=".51" fill="#000080"/>
<circle cx="32.7" cy="132.8" r=".51" fill="none" stroke="#000080" stroke-width=".21"/>
<path d="M32.7 130.2v2.6" fill="none" stroke="#000" stroke-width=".25"/>
<circle cx="32.7" cy="132.8" r=".51" fill="#000080"/>
<circle cx="32.7" cy="132.8" r=".51" fill="none" stroke="#000080" stroke-width=".21"/>
<g fill="none" stroke="#000" stroke-width=".25">
<path d="M45.4 142.9v2.6M45.4 150.6v2.5M114.1 153.1h4.4M119.8 153.1h4.4"/>
<circle cx="32.7" cy="129" r="1.27"/>
</g>
<g fill="none" stroke="#800000" stroke-width=".25">
<path d="M13.7 127.7h2.5M14.9 127.7v2.5M39.1 137.9h2.5M40.3 137.9v2.5M42.9 155.6h5.1M43.7 156.4h3.5M44.4 157.2h2.1M45.2 157.9h.5M45.4 153.1v2.5M83.6 150.6h5M84.3 151.3h3.6M85.1 152.1h2"/>
<path d="M85.8 152.8h.5M86.1 148v2.6M126.8 153.1h2.5M129.3 151.8v2.6"/>
</g>
<path d="M43.4 148.5h4M43.4 147.5h4M45.4 145.5v2M45.4 148.5v2.1M119.1 151.8h1.3l-1.3 2.6h-1.2z" fill="none" stroke="#00f" stroke-width=".25"/>
<path d="M213.2 61.7h20.3v35.5h-20.3z" fill-rule="evenodd" fill="#ffffb0"/>
<path d="M213.2 61.7h20.3v35.5h-20.3z" fill="none" stroke="#800000" stroke-width=".21"/>
<g fill="none" stroke="#000" stroke-width=".25">
<path d="M195.4 66.8v2.5M195.4 74.4v2.5M203 76.9v2.6M205.6 64.2h7.6M205.6 76.9h7.6M205.6 66.8h7.6M233.5 64.2h7.6M233.5 76.9h7.6M261.5 71.8v2M261.5 80v2M203 84.5v2.6M205.6 94.7h7.6"/>
<path d="M205.6 87.1h7.6M205.6 92.2h7.6M233.5 87.1h7.6M243.7 87.1v2.5M243.7 94.7v2.5M261.5 87.1v2M261.5 95.2v2"/>
</g>
<g fill="none" stroke="#00f" stroke-width=".25">
<path d="M193.4 72.3h4M193.4 71.3h4M195.4 69.3v2M195.4 72.3v2.1M203 79.5v2M260.5 73.9h2v6h-2zM201 82.5h4M201 81.5h4M203 82.5v2M241.7 92.6h4M241.7 91.7h4M243.7 89.6v2.1"/>
<path d="M243.7 92.6v2.1M260.5 89.2h2v6h-2z"/>
</g>
<g fill="none" stroke="#800000" stroke-width=".25">
<path d="M176.3 59.1h2.6M177.6 59.1v2.6M195.4 79.5v2.5M192.8 82h5.1M193.6 82.8h3.6M194.4 83.5h2M195.1 84.3h.5M200.5 99.8h5.1M203 97.2v2.6M241.1 99.8h5.1M243.7 97.2v2.6M258.9 99.8h5.1"/>
<path d="M261.5 97.2v2.6M201.2 100.5h3.6M202 101.3h2M202.8 102.1h.5M241.9 100.5h3.6M242.7 101.3h2M243.4 102.1h.5M259.7 100.5h3.5M260.5 101.3h2M261.2 102.1h.5"/>
</g>
<circle cx="251.3" cy="64.2" r=".51" fill="#000080"/>
<circle cx="251.3" cy="64.2" r=".51" fill="none" stroke="#000080" stroke-width=".21"/>
<path d="M251.3 64.2v2.6M251.3 71.8v2.6" fill="none" stroke="#000" stroke-width=".25"/>
<circle cx="251.3" cy="64.2" r=".51" fill="#000080"/>
<circle cx="251.3" cy="64.2" r=".51" fill="none" stroke="#000080" stroke-width=".21"/>
<path d="M182.2 63.2h6v2.1h-6zM249.3 69.8h4M249.3 68.8h4M251.3 66.8v2M251.3 69.8v2M268.6 63.2h6v2.1h-6z" fill="none" stroke="#00f" stroke-width=".25"/>
<path d="M280.5 59.1h2.6M281.8 59.1v2.6M248.8 76.9h5M249.5 77.7h3.6M250.3 78.4h2M251 79.2h.6M251.3 74.4v2.5" fill="none" stroke="#800000" stroke-width=".25"/>
<path d="M180.1 64.2h2M188.3 64.2h2M266.6 64.2h2M274.7 64.2h2" fill="none" stroke="#000" stroke-width=".25"/>
<circle cx="192.8" cy="64.2" r=".51" fill="#000080"/>
<circle cx="192.8" cy="64.2" r=".51" fill="none" stroke="#000080" stroke-width=".21"/>
<path d="M192.8 61.7v2.5" fill="none" stroke="#000" stroke-width=".25"/>
<circle cx="192.8" cy="64.2" r=".51" fill="#000080"/>
<circle cx="192.8" cy="64.2" r=".51" fill="none" stroke="#000080" stroke-width=".21"/>
<circle cx="192.8" cy="60.4" r="1.27" fill="none" stroke="#000" stroke-width=".25"/>
<circle cx="264" cy="64.2" r=".51" fill="#000080"/>
<circle cx="264" cy="64.2" r=".51" fill="none" stroke="#000080" stroke-width=".21"/>
<path d="M264 61.7v2.5" fill="none" stroke="#000" stroke-width=".25"/>
<circle cx="264" cy="64.2" r=".51" fill="#000080"/>
<circle cx="264" cy="64.2" r=".51" fill="none" stroke="#000080" stroke-width=".21"/>
<circle cx="264" cy="60.4" r="1.27" fill="none" stroke="#000" stroke-width=".25"/>
<circle cx="279.3" cy="64.2" r=".51" fill="#000080"/>
<circle cx="279.3" cy="64.2" r=".51" fill="none" stroke="#000080" stroke-width=".21"/>
<path d="M279.3 64.2v2.6" fill="none" stroke="#000" stroke-width=".25"/>
<circle cx="279.3" cy="64.2" r=".51" fill="#000080"/>
<circle cx="279.3" cy="64.2" r=".51" fill="none" stroke="#000080" stroke-width=".21"/>
<circle cx="279.3" cy="68" r="1.27" fill="none" stroke="#000" stroke-width=".25"/>
<path d="M215.7 153.1h15.3v12.7h-15.3z" fill-rule="evenodd" fill="#ffffb0"/>
<path d="M215.7 153.1h15.3v12.7h-15.3z" fill="none" stroke="#800000" stroke-width=".21"/>
<path d="M208.1 155.6h7.6M208.1 158.2h7.6M231 155.6h7.6M208.1 163.3h7.6M231 163.3h7.6" fill="none" stroke="#000" stroke-width=".25"/>
<circle cx="197.9" cy="155.6" r=".51" fill="#000080"/>
<circle cx="197.9" cy="155.6" r=".51" fill="none" stroke="#000080" stroke-width=".21"/>
<path d="M197.9 155.6v2.6M197.9 163.3v2.5" fill="none" stroke="#000" stroke-width=".25"/>
<circle cx="197.9" cy="155.6" r=".51" fill="#000080"/>
<circle cx="197.9" cy="155.6" r=".51" fill="none" stroke="#000080" stroke-width=".21"/>
<path d="M197.9 158.2v2M195.9 161.2h4M195.9 160.2h4M197.9 161.2v2.1" fill="none" stroke="#00f" stroke-width=".25"/>
<path d="M195.4 168.3h5.1M196.2 169.1h3.5M196.9 169.9h2M197.7 170.6h.5M197.9 165.8v2.5M203 168.3h5.1M203.8 169.1h3.5M204.5 169.9h2.1M205.3 170.6h.5M205.6 165.8v2.5" fill="none" stroke="#800000" stroke-width=".25"/>
<path d="M237.6 162.2l2 2.1M239.6 162.2l-2 2.1" fill="none" stroke="#f00" stroke-width=".21"/>
<circle cx="243.7" cy="155.6" r=".51" fill="#000080"/>
<circle cx="243.7" cy="155.6" r=".51" fill="none" stroke="#000080" stroke-width=".21"/>
<path d="M243.7 155.6v2.6M243.7 163.3v2.5" fill="none" stroke="#000" stroke-width=".25"/>
<circle cx="243.7" cy="155.6" r=".51" fill="#000080"/>
<circle cx="243.7" cy="155.6" r=".51" fill="none" stroke="#000080" stroke-width=".21"/>
<path d="M184.8 154.7h6v2h-6zM243.7 158.2v2M241.7 161.2h4M241.7 160.2h4M243.7 161.2v2.1" fill="none" stroke="#00f" stroke-width=".25"/>
<path d="M241.1 168.3h5.1M241.9 169.1h3.6M242.7 169.9h2M243.4 170.6h.5M243.7 165.8v2.5" fill="none" stroke="#800000" stroke-width=".25"/>
<path d="M182.7 155.6h2M190.8 155.6h2" fill="none" stroke="#000" stroke-width=".25"/>
<circle cx="180.1" cy="155.6" r=".51" fill="#000080"/>
<circle cx="180.1" cy="155.6" r=".51" fill="none" stroke="#000080" stroke-width=".21"/>
<path d="M180.1 155.6v2.6" fill="none" stroke="#000" stroke-width=".25"/>
<circle cx="180.1" cy="155.6" r=".51" fill="#000080"/>
<circle cx="180.1" cy="155.6" r=".51" fill="none" stroke="#000080" stroke-width=".21"/>
<circle cx="180.1" cy="159.5" r="1.27" fill="none" stroke="#000" stroke-width=".25"/>
<circle cx="195.4" cy="155.6" r=".51" fill="#000080"/>
<circle cx="195.4" cy="155.6" r=".51" fill="none" stroke="#000080" stroke-width=".21"/>
<path d="M195.4 153.1v2.5" fill="none" stroke="#000" stroke-width=".25"/>
<circle cx="195.4" cy="155.6" r=".51" fill="#000080"/>
<circle cx="195.4" cy="155.6" r=".51" fill="none" stroke="#000080" stroke-width=".21"/>
<circle cx="195.4" cy="151.8" r="1.27" fill="none" stroke="#000" stroke-width=".25"/>
<circle cx="241.1" cy="155.6" r=".51" fill="#000080"/>
<circle cx="241.1" cy="155.6" r=".51" fill="none" stroke="#000080" stroke-width=".21"/>
<path d="M241.1 153.1v2.5" fill="none" stroke="#000" stroke-width=".25"/>
<circle cx="241.1" cy="155.6" r=".51" fill="#000080"/>
<circle cx="241.1" cy="155.6" r=".51" fill="none" stroke="#000080" stroke-width=".21"/>
<circle cx="241.1" cy="151.8" r="1.27" fill="none" stroke="#000" stroke-width=".25"/>
<path d="M176.3 150.6h2.6M177.6 150.6v2.5M250 150.6h2.6M251.3 150.6v2.5" fill="none" stroke="#800000" stroke-width=".25"/>
<path d="M218.3 112.5h20.3v20.3h-20.3z" fill-rule="evenodd" fill="#ffffb0"/>
<path d="M218.3 112.5h20.3v20.3h-20.3z" fill="none" stroke="#800000" stroke-width=".21"/>
<g fill="none" stroke="#000" stroke-width=".25">
<path d="M182.7 115h2M190.8 115h2M197.9 117.5v2.6M210.6 115h7.7M210.6 117.5h7.7M238.6 115h7.6M238.6 117.5h7.6M261.5 117.5v2.6M197.9 125.2v2.5M210.6 122.6h7.7M210.6 130.2h7.7M210.6 127.7h7.7"/>
<path d="M238.6 122.6h7.6M238.6 127.7h7.6M248.8 127.7v2.5M248.8 135.3v2.6M261.5 125.2v2.5"/>
</g>
<g fill="none" stroke="#800000" stroke-width=".25">
<path d="M176.3 109.9h2.6M177.6 109.9v2.6M265.3 109.9h2.5M266.6 109.9v2.6M195.4 135.3h5.1M196.2 136.1h3.5M196.9 136.8h2M197.7 137.6h.5M197.9 132.8v2.5M205.6 135.3h5M206.3 136.1h3.6M207.1 136.8h2"/>
<path d="M207.8 137.6h.5M208.1 132.8v2.5M248.8 137.9v2.5M258.9 132.8h5.1M259.7 133.5h3.5M260.5 134.3h2M261.2 135.1h.5M261.5 130.2v2.6M246.2 140.4h5.1M247 141.2h3.5M247.7 141.9h2.1M248.5 142.7h.5"/>
</g>
<g fill="none" stroke="#00f" stroke-width=".25">
<path d="M184.8 114h6v2.1h-6zM195.9 123.1h4M195.9 122.1h4M197.9 120.1v2M197.9 123.1v2.1M246.8 133.3h4M246.8 132.3h4M248.8 130.2v2.1M248.8 133.3v2M259.5 123.1h4M259.5 122.1h4M261.5 120.1v2"/>
<path d="M261.5 123.1v2.1"/>
</g>
<circle cx="180.1" cy="115" r=".51" fill="#000080"/>
<circle cx="180.1" cy="115" r=".51" fill="none" stroke="#000080" stroke-width=".21"/>
<path d="M180.1 115v2.5" fill="none" stroke="#000" stroke-width=".25"/>
<circle cx="180.1" cy="115" r=".51" fill="#000080"/>
<circle cx="180.1" cy="115" r=".51" fill="none" stroke="#000080" stroke-width=".21"/>
<circle cx="180.1" cy="118.8" r="1.27" fill="none" stroke="#000" stroke-width=".25"/>
<circle cx="195.4" cy="115" r=".51" fill="#000080"/>
<circle cx="195.4" cy="115" r=".51" fill="none" stroke="#000080" stroke-width=".21"/>
<path d="M195.4 112.5v2.5" fill="none" stroke="#000" stroke-width=".25"/>
<circle cx="195.4" cy="115" r=".51" fill="#000080"/>
<circle cx="195.4" cy="115" r=".51" fill="none" stroke="#000080" stroke-width=".21"/>
<circle cx="195.4" cy="111.2" r="1.27" fill="none" stroke="#000" stroke-width=".25"/>
<circle cx="253.8" cy="115" r=".51" fill="#000080"/>
<circle cx="253.8" cy="115" r=".51" fill="none" stroke="#000080" stroke-width=".21"/>
<path d="M253.8 112.5v2.5" fill="none" stroke="#000" stroke-width=".25"/>
<circle cx="253.8" cy="115" r=".51" fill="#000080"/>
<circle cx="253.8" cy="115" r=".51" fill="none" stroke="#000080" stroke-width=".21"/>
<circle cx="253.8" cy="111.2" r="1.27" fill="none" stroke="#000" stroke-width=".25"/>
<path d="M177.6 38.8v5.1M205.6 36.3h2.5M266.6 38.8v5.1" fill="none" stroke="#000080" stroke-width=".25"/>
<circle cx="205.6" cy="36.3" r=".51" fill="#000080"/>
<circle cx="205.6" cy="36.3" r=".51" fill="none" stroke="#000080" stroke-width=".21"/>
<path d="M187.8 26.1h2.5" fill="none" stroke="#000080" stroke-width=".25"/>
<circle cx="187.8" cy="26.1" r=".51" fill="#000080"/>
<circle cx="187.8" cy="26.1" r=".51" fill="none" stroke="#000080" stroke-width=".21"/>
<path d="M78.5 38.8h2.5v2.6M205.6 26.1h2.5M238.6 36.3v7.6" fill="none" stroke="#000080" stroke-width=".25"/>
<circle cx="81" cy="38.8" r=".51" fill="#000080"/>
<circle cx="81" cy="38.8" r=".51" fill="none" stroke="#000080" stroke-width=".21"/>
<path d="M40.3 26.1v7.6h2.6" fill="none" stroke="#000080" stroke-width=".25"/>
<circle cx="40.3" cy="26.1" r=".51" fill="#000080"/>
<circle cx="40.3" cy="26.1" r=".51" fill="none" stroke="#000080" stroke-width=".21"/>
<path d="M78.5 33.7h2.5M91.2 33.7v7.7M101.3 26.1v2.6M101.3 38.8v2.6" fill="none" stroke="#000080" stroke-width=".25"/>
<circle cx="101.3" cy="26.1" r=".51" fill="#000080"/>
<circle cx="101.3" cy="26.1" r=".51" fill="none" stroke="#000080" stroke-width=".21"/>
<path d="M78.5 26.1h2.5" fill="none" stroke="#000080" stroke-width=".25"/>
<circle cx="81" cy="26.1" r=".51" fill="#000080"/>
<circle cx="81" cy="26.1" r=".51" fill="none" stroke="#000080" stroke-width=".21"/>
<path d="M17.5 26.1v2.6M17.5 38.8v2.6" fill="none" stroke="#000080" stroke-width=".25"/>
<circle cx="17.5" cy="26.1" r=".51" fill="#000080"/>
<circle cx="17.5" cy="26.1" r=".51" fill="none" stroke="#000080" stroke-width=".21"/>
<path d="M40.3 26.1h2.6v2.6" fill="none" stroke="#000080" stroke-width=".25"/>
<circle cx="40.3" cy="26.1" r=".51" fill="#000080"/>
<circle cx="40.3" cy="26.1" r=".51" fill="none" stroke="#000080" stroke-width=".21"/>
<circle cx="42.9" cy="26.1" r=".51" fill="#000080"/>
<circle cx="42.9" cy="26.1" r=".51" fill="none" stroke="#000080" stroke-width=".21"/>
<path d="M177.6 26.1v2.6M40.3 51.5v2.6" fill="none" stroke="#000080" stroke-width=".25"/>
<circle cx="177.6" cy="26.1" r=".51" fill="#000080"/>
<circle cx="177.6" cy="26.1" r=".51" fill="none" stroke="#000080" stroke-width=".21"/>
<path d="M266.6 26.1v2.6" fill="none" stroke="#000080" stroke-width=".25"/>
<circle cx="266.6" cy="26.1" r=".51" fill="#000080"/>
<circle cx="266.6" cy="26.1" r=".51" fill="none" stroke="#000080" stroke-width=".21"/>
<path d="M251.3 26.1v5.1M261.5 31.2v2.5" fill="none" stroke="#000080" stroke-width=".25"/>
<circle cx="251.3" cy="26.1" r=".51" fill="#000080"/>
<circle cx="251.3" cy="26.1" r=".51" fill="none" stroke="#000080" stroke-width=".21"/>
<path d="M238.6 26.1h12.7" fill="none" stroke="#000080" stroke-width=".25"/>
<circle cx="251.3" cy="26.1" r=".51" fill="#000080"/>
<circle cx="251.3" cy="26.1" r=".51" fill="none" stroke="#000080" stroke-width=".21"/>
<path d="M238.6 31.2h10.2v2.5h2.5" fill="none" stroke="#000080" stroke-width=".25"/>
<circle cx="248.8" cy="33.7" r=".51" fill="#000080"/>
<circle cx="248.8" cy="33.7" r=".51" fill="none" stroke="#000080" stroke-width=".21"/>
<path d="M78.5 36.3h2.5v2.5" fill="none" stroke="#000080" stroke-width=".25"/>
<circle cx="81" cy="38.8" r=".51" fill="#000080"/>
<circle cx="81" cy="38.8" r=".51" fill="none" stroke="#000080" stroke-width=".21"/>
<path d="M14.9 23.6v2.5h25.4" fill="none" stroke="#000080" stroke-width=".25"/>
<circle cx="17.5" cy="26.1" r=".51" fill="#000080"/>
<circle cx="17.5" cy="26.1" r=".51" fill="none" stroke="#000080" stroke-width=".21"/>
<circle cx="27.6" cy="26.1" r=".51" fill="#000080"/>
<circle cx="27.6" cy="26.1" r=".51" fill="none" stroke="#000080" stroke-width=".21"/>
<circle cx="40.3" cy="26.1" r=".51" fill="#000080"/>
<circle cx="40.3" cy="26.1" r=".51" fill="none" stroke="#000080" stroke-width=".21"/>
<path d="M103.9 23.6v2.5h-22.9v2.6h-2.5" fill="none" stroke="#000080" stroke-width=".25"/>
<circle cx="101.3" cy="26.1" r=".51" fill="#000080"/>
<circle cx="101.3" cy="26.1" r=".51" fill="none" stroke="#000080" stroke-width=".21"/>
<circle cx="91.2" cy="26.1" r=".51" fill="#000080"/>
<circle cx="91.2" cy="26.1" r=".51" fill="none" stroke="#000080" stroke-width=".21"/>
<circle cx="81" cy="26.1" r=".51" fill="#000080"/>
<circle cx="81" cy="26.1" r=".51" fill="none" stroke="#000080" stroke-width=".21"/>
<path d="M37.8 38.8h2.5" fill="none" stroke="#000080" stroke-width=".25"/>
<circle cx="40.3" cy="38.8" r=".51" fill="#000080"/>
<circle cx="40.3" cy="38.8" r=".51" fill="none" stroke="#000080" stroke-width=".21"/>
<path d="M200.5 36.3h5.1" fill="none" stroke="#000080" stroke-width=".25"/>
<circle cx="205.6" cy="36.3" r=".51" fill="#000080"/>
<circle cx="205.6" cy="36.3" r=".51" fill="none" stroke="#000080" stroke-width=".21"/>
<path d="M271.6 23.6v2.5h-20.3" fill="none" stroke="#000080" stroke-width=".25"/>
<circle cx="266.6" cy="26.1" r=".51" fill="#000080"/>
<circle cx="266.6" cy="26.1" r=".51" fill="none" stroke="#000080" stroke-width=".21"/>
<circle cx="251.3" cy="26.1" r=".51" fill="#000080"/>
<circle cx="251.3" cy="26.1" r=".51" fill="none" stroke="#000080" stroke-width=".21"/>
<path d="M170 26.1h17.8v5.1h20.3" fill="none" stroke="#000080" stroke-width=".25"/>
<circle cx="172.5" cy="26.1" r=".51" fill="#000080"/>
<circle cx="172.5" cy="26.1" r=".51" fill="none" stroke="#000080" stroke-width=".21"/>
<circle cx="177.6" cy="26.1" r=".51" fill="#000080"/>
<circle cx="177.6" cy="26.1" r=".51" fill="none" stroke="#000080" stroke-width=".21"/>
<circle cx="187.8" cy="26.1" r=".51" fill="#000080"/>
<circle cx="187.8" cy="26.1" r=".51" fill="none" stroke="#000080" stroke-width=".21"/>
<path d="M152.2 23.6v2.5h7.6" fill="none" stroke="#000080" stroke-width=".25"/>
<circle cx="157.3" cy="26.1" r=".51" fill="#000080"/>
<circle cx="157.3" cy="26.1" r=".51" fill="none" stroke="#000080" stroke-width=".21"/>
<path d="M45.4 76.9v5.1h2.6M48 87.1h-2.6v5" fill="none" stroke="#000080" stroke-width=".25"/>
<circle cx="45.4" cy="76.9" r=".51" fill="#000080"/>
<circle cx="45.4" cy="76.9" r=".51" fill="none" stroke="#000080" stroke-width=".21"/>
<path d="M48 76.9h-12.7v2.6M78.5 76.9h2.5M35.3 89.6v2.5" fill="none" stroke="#000080" stroke-width=".25"/>
<circle cx="45.4" cy="76.9" r=".51" fill="#000080"/>
<circle cx="45.4" cy="76.9" r=".51" fill="none" stroke="#000080" stroke-width=".21"/>
<circle cx="35.3" cy="76.9" r=".51" fill="#000080"/>
<circle cx="35.3" cy="76.9" r=".51" fill="none" stroke="#000080" stroke-width=".21"/>
<path d="M119.1 74.4v2.5h-5M114.1 89.6v2.5" fill="none" stroke="#000080" stroke-width=".25"/>
<circle cx="114.1" cy="76.9" r=".51" fill="#000080"/>
<circle cx="114.1" cy="76.9" r=".51" fill="none" stroke="#000080" stroke-width=".21"/>
<path d="M106.4 76.9v2.6" fill="none" stroke="#000080" stroke-width=".25"/>
<circle cx="106.4" cy="76.9" r=".51" fill="#000080"/>
<circle cx="106.4" cy="76.9" r=".51" fill="none" stroke="#000080" stroke-width=".21"/>
<path d="M96.3 76.9h17.8v2.6" fill="none" stroke="#000080" stroke-width=".25"/>
<circle cx="98.8" cy="76.9" r=".51" fill="#000080"/>
<circle cx="98.8" cy="76.9" r=".51" fill="none" stroke="#000080" stroke-width=".21"/>
<circle cx="106.4" cy="76.9" r=".51" fill="#000080"/>
<circle cx="106.4" cy="76.9" r=".51" fill="none" stroke="#000080" stroke-width=".21"/>
<circle cx="114.1" cy="76.9" r=".51" fill="#000080"/>
<circle cx="114.1" cy="76.9" r=".51" fill="none" stroke="#000080" stroke-width=".21"/>
<path d="M98.8 76.9v2.6" fill="none" stroke="#000080" stroke-width=".25"/>
<circle cx="98.8" cy="76.9" r=".51" fill="#000080"/>
<circle cx="98.8" cy="76.9" r=".51" fill="none" stroke="#000080" stroke-width=".21"/>
<path d="M106.4 89.6v5.1" fill="none" stroke="#000080" stroke-width=".25"/>
<circle cx="106.4" cy="92.1" r=".51" fill="#000080"/>
<circle cx="106.4" cy="92.1" r=".51" fill="none" stroke="#000080" stroke-width=".21"/>
<path d="M78.5 82h10.1v10.1h17.8" fill="none" stroke="#000080" stroke-width=".25"/>
<circle cx="106.4" cy="92.1" r=".51" fill="#000080"/>
<circle cx="106.4" cy="92.1" r=".51" fill="none" stroke="#000080" stroke-width=".21"/>
<circle cx="98.8" cy="92.1" r=".51" fill="#000080"/>
<circle cx="98.8" cy="92.1" r=".51" fill="none" stroke="#000080" stroke-width=".21"/>
<path d="M98.8 89.6v2.5" fill="none" stroke="#000080" stroke-width=".25"/>
<circle cx="98.8" cy="92.1" r=".51" fill="#000080"/>
<circle cx="98.8" cy="92.1" r=".51" fill="none" stroke="#000080" stroke-width=".21"/>
<path d="M14.9 74.4v2.5h2.6" fill="none" stroke="#000080" stroke-width=".25"/>
<circle cx="14.9" cy="76.9" r=".51" fill="#000080"/>
<circle cx="14.9" cy="76.9" r=".51" fill="none" stroke="#000080" stroke-width=".21"/>
<path d="M27.6 76.9h7.7" fill="none" stroke="#000080" stroke-width=".25"/>
<circle cx="30.2" cy="76.9" r=".51" fill="#000080"/>
<circle cx="30.2" cy="76.9" r=".51" fill="none" stroke="#000080" stroke-width=".21"/>
<circle cx="35.3" cy="76.9" r=".51" fill="#000080"/>
<circle cx="35.3" cy="76.9" r=".51" fill="none" stroke="#000080" stroke-width=".21"/>
<path d="M96.3 145.5v2.5M103.9 145.5v2.5" fill="none" stroke="#000080" stroke-width=".25"/>
<circle cx="96.3" cy="148" r=".51" fill="#000080"/>
<circle cx="96.3" cy="148" r=".51" fill="none" stroke="#000080" stroke-width=".21"/>
<path d="M96.3 132.8v2.5" fill="none" stroke="#000080" stroke-width=".25"/>
<circle cx="96.3" cy="132.8" r=".51" fill="#000080"/>
<circle cx="96.3" cy="132.8" r=".51" fill="none" stroke="#000080" stroke-width=".21"/>
<path d="M111.5 132.8v10.1h2.6" fill="none" stroke="#000080" stroke-width=".25"/>
<circle cx="111.5" cy="142.9" r=".51" fill="#000080"/>
<circle cx="111.5" cy="142.9" r=".51" fill="none" stroke="#000080" stroke-width=".21"/>
<circle cx="111.5" cy="132.8" r=".51" fill="#000080"/>
<circle cx="111.5" cy="132.8" r=".51" fill="none" stroke="#000080" stroke-width=".21"/>
<path d="M96.3 132.8h17.8M124.2 132.8h2.6M124.2 142.9h2.6" fill="none" stroke="#000080" stroke-width=".25"/>
<circle cx="96.3" cy="132.8" r=".51" fill="#000080"/>
<circle cx="96.3" cy="132.8" r=".51" fill="none" stroke="#000080" stroke-width=".21"/>
<circle cx="103.9" cy="132.8" r=".51" fill="#000080"/>
<circle cx="103.9" cy="132.8" r=".51" fill="none" stroke="#000080" stroke-width=".21"/>
<circle cx="109" cy="132.8" r=".51" fill="#000080"/>
<circle cx="109" cy="132.8" r=".51" fill="none" stroke="#000080" stroke-width=".21"/>
<circle cx="111.5" cy="132.8" r=".51" fill="#000080"/>
<circle cx="111.5" cy="132.8" r=".51" fill="none" stroke="#000080" stroke-width=".21"/>
<path d="M83.6 132.8h12.7" fill="none" stroke="#000080" stroke-width=".25"/>
<circle cx="96.3" cy="132.8" r=".51" fill="#000080"/>
<circle cx="96.3" cy="132.8" r=".51" fill="none" stroke="#000080" stroke-width=".21"/>
<path d="M103.9 132.8v2.5" fill="none" stroke="#000080" stroke-width=".25"/>
<circle cx="103.9" cy="132.8" r=".51" fill="#000080"/>
<circle cx="103.9" cy="132.8" r=".51" fill="none" stroke="#000080" stroke-width=".21"/>
<path d="M14.9 130.2v2.6h2.6M30.2 145.5v2.5" fill="none" stroke="#000080" stroke-width=".25"/>
<circle cx="14.9" cy="132.8" r=".51" fill="#000080"/>
<circle cx="14.9" cy="132.8" r=".51" fill="none" stroke="#000080" stroke-width=".21"/>
<path d="M27.6 132.8h2.6" fill="none" stroke="#000080" stroke-width=".25"/>
<circle cx="30.2" cy="132.8" r=".51" fill="#000080"/>
<circle cx="30.2" cy="132.8" r=".51" fill="none" stroke="#000080" stroke-width=".21"/>
<path d="M30.2 132.8v2.5" fill="none" stroke="#000080" stroke-width=".25"/>
<circle cx="30.2" cy="132.8" r=".51" fill="#000080"/>
<circle cx="30.2" cy="132.8" r=".51" fill="none" stroke="#000080" stroke-width=".21"/>
<path d="M45.4 132.8v2.5h2.6" fill="none" stroke="#000080" stroke-width=".25"/>
<circle cx="45.4" cy="132.8" r=".51" fill="#000080"/>
<circle cx="45.4" cy="132.8" r=".51" fill="none" stroke="#000080" stroke-width=".21"/>
<path d="M30.2 132.8h17.8M83.6 140.4h2.5v7.6" fill="none" stroke="#000080" stroke-width=".25"/>
<circle cx="30.2" cy="132.8" r=".51" fill="#000080"/>
<circle cx="30.2" cy="132.8" r=".51" fill="none" stroke="#000080" stroke-width=".21"/>
<circle cx="32.7" cy="132.8" r=".51" fill="#000080"/>
<circle cx="32.7" cy="132.8" r=".51" fill="none" stroke="#000080" stroke-width=".21"/>
<circle cx="45.4" cy="132.8" r=".51" fill="#000080"/>
<circle cx="45.4" cy="132.8" r=".51" fill="none" stroke="#000080" stroke-width=".21"/>
<path d="M83.6 135.3h7.6v12.7h5.1v2.6" fill="none" stroke="#000080" stroke-width=".25"/>
<circle cx="96.3" cy="148" r=".51" fill="#000080"/>
<circle cx="96.3" cy="148" r=".51" fill="none" stroke="#000080" stroke-width=".21"/>
<path d="M48 140.4h-2.6v2.5" fill="none" stroke="#000080" stroke-width=".25"/>
<circle cx="45.4" cy="140.4" r=".51" fill="#000080"/>
<circle cx="45.4" cy="140.4" r=".51" fill="none" stroke="#000080" stroke-width=".21"/>
<path d="M40.3 140.4h5.1" fill="none" stroke="#000080" stroke-width=".25"/>
<circle cx="45.4" cy="140.4" r=".51" fill="#000080"/>
<circle cx="45.4" cy="140.4" r=".51" fill="none" stroke="#000080" stroke-width=".21"/>
<path d="M111.5 142.9v10.2h2.6M124.2 153.1h2.6" fill="none" stroke="#000080" stroke-width=".25"/>
<circle cx="111.5" cy="142.9" r=".51" fill="#000080"/>
<circle cx="111.5" cy="142.9" r=".51" fill="none" stroke="#000080" stroke-width=".21"/>
<path d="M205.6 92.2h-2.6v2.5h2.6" fill="none" stroke="#000080" stroke-width=".25"/>
<circle cx="203" cy="94.7" r=".51" fill="#000080"/>
<circle cx="203" cy="94.7" r=".51" fill="none" stroke="#000080" stroke-width=".21"/>
<path d="M203 76.9h2.6M241.1 76.9h5.1v7.6h15.3v2.6M203 87.1h2.6M241.1 87.1h2.6" fill="none" stroke="#000080" stroke-width=".25"/>
<circle cx="261.5" cy="84.5" r=".51" fill="#000080"/>
<circle cx="261.5" cy="84.5" r=".51" fill="none" stroke="#000080" stroke-width=".21"/>
<path d="M281.8 61.7v2.5h-5.1" fill="none" stroke="#000080" stroke-width=".25"/>
<circle cx="279.3" cy="64.2" r=".51" fill="#000080"/>
<circle cx="279.3" cy="64.2" r=".51" fill="none" stroke="#000080" stroke-width=".21"/>
<path d="M195.4 64.2v2.6M195.4 76.9v2.6" fill="none" stroke="#000080" stroke-width=".25"/>
<circle cx="195.4" cy="64.2" r=".51" fill="#000080"/>
<circle cx="195.4" cy="64.2" r=".51" fill="none" stroke="#000080" stroke-width=".21"/>
<path d="M203 94.7v2.5" fill="none" stroke="#000080" stroke-width=".25"/>
<circle cx="203" cy="94.7" r=".51" fill="#000080"/>
<circle cx="203" cy="94.7" r=".51" fill="none" stroke="#000080" stroke-width=".21"/>
<path d="M261.5 82v2.5" fill="none" stroke="#000080" stroke-width=".25"/>
<circle cx="261.5" cy="84.5" r=".51" fill="#000080"/>
<circle cx="261.5" cy="84.5" r=".51" fill="none" stroke="#000080" stroke-width=".21"/>
<path d="M261.5 64.2v7.6" fill="none" stroke="#000080" stroke-width=".25"/>
<circle cx="261.5" cy="64.2" r=".51" fill="#000080"/>
<circle cx="261.5" cy="64.2" r=".51" fill="none" stroke="#000080" stroke-width=".21"/>
<path d="M241.1 64.2h25.5" fill="none" stroke="#000080" stroke-width=".25"/>
<circle cx="251.3" cy="64.2" r=".51" fill="#000080"/>
<circle cx="251.3" cy="64.2" r=".51" fill="none" stroke="#000080" stroke-width=".21"/>
<circle cx="261.5" cy="64.2" r=".51" fill="#000080"/>
<circle cx="261.5" cy="64.2" r=".51" fill="none" stroke="#000080" stroke-width=".21"/>
<circle cx="264" cy="64.2" r=".51" fill="#000080"/>
<circle cx="264" cy="64.2" r=".51" fill="none" stroke="#000080" stroke-width=".21"/>
<path d="M177.6 61.7v2.5h2.5M195.4 64.2h10.2" fill="none" stroke="#000080" stroke-width=".25"/>
<circle cx="203" cy="64.2" r=".51" fill="#000080"/>
<circle cx="203" cy="64.2" r=".51" fill="none" stroke="#000080" stroke-width=".21"/>
<circle cx="195.4" cy="64.2" r=".51" fill="#000080"/>
<circle cx="195.4" cy="64.2" r=".51" fill="none" stroke="#000080" stroke-width=".21"/>
<path d="M190.3 64.2h5.1" fill="none" stroke="#000080" stroke-width=".25"/>
<circle cx="195.4" cy="64.2" r=".51" fill="#000080"/>
<circle cx="195.4" cy="64.2" r=".51" fill="none" stroke="#000080" stroke-width=".21"/>
<circle cx="192.8" cy="64.2" r=".51" fill="#000080"/>
<circle cx="192.8" cy="64.2" r=".51" fill="none" stroke="#000080" stroke-width=".21"/>
<path d="M203 64.2v2.6h2.6" fill="none" stroke="#000080" stroke-width=".25"/>
<circle cx="203" cy="64.2" r=".51" fill="#000080"/>
<circle cx="203" cy="64.2" r=".51" fill="none" stroke="#000080" stroke-width=".21"/>
<path d="M238.6 155.6h5.1M208.1 163.3h-2.5v2.5" fill="none" stroke="#000080" stroke-width=".25"/>
<circle cx="243.7" cy="155.6" r=".51" fill="#000080"/>
<circle cx="243.7" cy="155.6" r=".51" fill="none" stroke="#000080" stroke-width=".21"/>
<circle cx="241.1" cy="155.6" r=".51" fill="#000080"/>
<circle cx="241.1" cy="155.6" r=".51" fill="none" stroke="#000080" stroke-width=".21"/>
<path d="M251.3 153.1v2.5h-7.6" fill="none" stroke="#000080" stroke-width=".25"/>
<circle cx="243.7" cy="155.6" r=".51" fill="#000080"/>
<circle cx="243.7" cy="155.6" r=".51" fill="none" stroke="#000080" stroke-width=".21"/>
<path d="M177.6 153.1v2.5h5.1" fill="none" stroke="#000080" stroke-width=".25"/>
<circle cx="180.1" cy="155.6" r=".51" fill="#000080"/>
<circle cx="180.1" cy="155.6" r=".51" fill="none" stroke="#000080" stroke-width=".21"/>
<path d="M205.6 155.6v2.6h2.5" fill="none" stroke="#000080" stroke-width=".25"/>
<circle cx="205.6" cy="155.6" r=".51" fill="#000080"/>
<circle cx="205.6" cy="155.6" r=".51" fill="none" stroke="#000080" stroke-width=".21"/>
<path d="M192.8 155.6h15.3" fill="none" stroke="#000080" stroke-width=".25"/>
<circle cx="195.4" cy="155.6" r=".51" fill="#000080"/>
<circle cx="195.4" cy="155.6" r=".51" fill="none" stroke="#000080" stroke-width=".21"/>
<circle cx="197.9" cy="155.6" r=".51" fill="#000080"/>
<circle cx="197.9" cy="155.6" r=".51" fill="none" stroke="#000080" stroke-width=".21"/>
<circle cx="205.6" cy="155.6" r=".51" fill="#000080"/>
<circle cx="205.6" cy="155.6" r=".51" fill="none" stroke="#000080" stroke-width=".21"/>
<path d="M40.3 38.8v2.6" fill="none" stroke="#000080" stroke-width=".25"/>
<circle cx="40.3" cy="38.8" r=".51" fill="#000080"/>
<circle cx="40.3" cy="38.8" r=".51" fill="none" stroke="#000080" stroke-width=".21"/>
<path d="M40.3 38.8h2.6" fill="none" stroke="#000080" stroke-width=".25"/>
<circle cx="40.3" cy="38.8" r=".51" fill="#000080"/>
<circle cx="40.3" cy="38.8" r=".51" fill="none" stroke="#000080" stroke-width=".21"/>
<path d="M208.1 115v2.5h2.5" fill="none" stroke="#000080" stroke-width=".25"/>
<circle cx="208.1" cy="117.5" r=".51" fill="#000080"/>
<circle cx="208.1" cy="117.5" r=".51" fill="none" stroke="#000080" stroke-width=".21"/>
<circle cx="208.1" cy="115" r=".51" fill="#000080"/>
<circle cx="208.1" cy="115" r=".51" fill="none" stroke="#000080" stroke-width=".21"/>
<path d="M246.2 115h2.6v2.5h-2.6" fill="none" stroke="#000080" stroke-width=".25"/>
<circle cx="248.8" cy="117.5" r=".51" fill="#000080"/>
<circle cx="248.8" cy="117.5" r=".51" fill="none" stroke="#000080" stroke-width=".21"/>
<circle cx="248.8" cy="115" r=".51" fill="#000080"/>
<circle cx="248.8" cy="115" r=".51" fill="none" stroke="#000080" stroke-width=".21"/>
<path d="M266.6 112.5v2.5h-5.1M261.5 127.7v2.5" fill="none" stroke="#000080" stroke-width=".25"/>
<circle cx="261.5" cy="115" r=".51" fill="#000080"/>
<circle cx="261.5" cy="115" r=".51" fill="none" stroke="#000080" stroke-width=".21"/>
<path d="M208.1 115h2.5" fill="none" stroke="#000080" stroke-width=".25"/>
<circle cx="208.1" cy="115" r=".51" fill="#000080"/>
<circle cx="208.1" cy="115" r=".51" fill="none" stroke="#000080" stroke-width=".21"/>
<path d="M192.8 115h5.1" fill="none" stroke="#000080" stroke-width=".25"/>
<circle cx="195.4" cy="115" r=".51" fill="#000080"/>
<circle cx="195.4" cy="115" r=".51" fill="none" stroke="#000080" stroke-width=".21"/>
<circle cx="197.9" cy="115" r=".51" fill="#000080"/>
<circle cx="197.9" cy="115" r=".51" fill="none" stroke="#000080" stroke-width=".21"/>
<path d="M197.9 115h10.2" fill="none" stroke="#000080" stroke-width=".25"/>
<circle cx="197.9" cy="115" r=".51" fill="#000080"/>
<circle cx="197.9" cy="115" r=".51" fill="none" stroke="#000080" stroke-width=".21"/>
<circle cx="208.1" cy="115" r=".51" fill="#000080"/>
<circle cx="208.1" cy="115" r=".51" fill="none" stroke="#000080" stroke-width=".21"/>
<path d="M177.6 112.5v2.5h5.1" fill="none" stroke="#000080" stroke-width=".25"/>
<circle cx="180.1" cy="115" r=".51" fill="#000080"/>
<circle cx="180.1" cy="115" r=".51" fill="none" stroke="#000080" stroke-width=".21"/>
<path d="M197.9 115v2.5M197.9 127.7v5.1" fill="none" stroke="#000080" stroke-width=".25"/>
<circle cx="197.9" cy="115" r=".51" fill="#000080"/>
<circle cx="197.9" cy="115" r=".51" fill="none" stroke="#000080" stroke-width=".21"/>
<path d="M208.1 117.5v5.1h2.5" fill="none" stroke="#000080" stroke-width=".25"/>
<circle cx="208.1" cy="117.5" r=".51" fill="#000080"/>
<circle cx="208.1" cy="117.5" r=".51" fill="none" stroke="#000080" stroke-width=".21"/>
<path d="M208.1 130.2h2.5" fill="none" stroke="#000080" stroke-width=".25"/>
<circle cx="208.1" cy="130.2" r=".51" fill="#000080"/>
<circle cx="208.1" cy="130.2" r=".51" fill="none" stroke="#000080" stroke-width=".21"/>
<path d="M210.6 127.7h-2.5v5.1M246.2 127.7h2.6" fill="none" stroke="#000080" stroke-width=".25"/>
<circle cx="208.1" cy="130.2" r=".51" fill="#000080"/>
<circle cx="208.1" cy="130.2" r=".51" fill="none" stroke="#000080" stroke-width=".21"/>
<path d="M248.8 115h12.7v2.5" fill="none" stroke="#000080" stroke-width=".25"/>
<circle cx="248.8" cy="115" r=".51" fill="#000080"/>
<circle cx="248.8" cy="115" r=".51" fill="none" stroke="#000080" stroke-width=".21"/>
<circle cx="253.8" cy="115" r=".51" fill="#000080"/>
<circle cx="253.8" cy="115" r=".51" fill="none" stroke="#000080" stroke-width=".21"/>
<circle cx="261.5" cy="115" r=".51" fill="#000080"/>
<circle cx="261.5" cy="115" r=".51" fill="none" stroke="#000080" stroke-width=".21"/>
<path d="M248.8 117.5v5.1h-2.6" fill="none" stroke="#000080" stroke-width=".25"/>
<circle cx="248.8" cy="117.5" r=".51" fill="#000080"/>
<circle cx="248.8" cy="117.5" r=".51" fill="none" stroke="#000080" stroke-width=".21"/>
<use href="#words"/>
</svg>
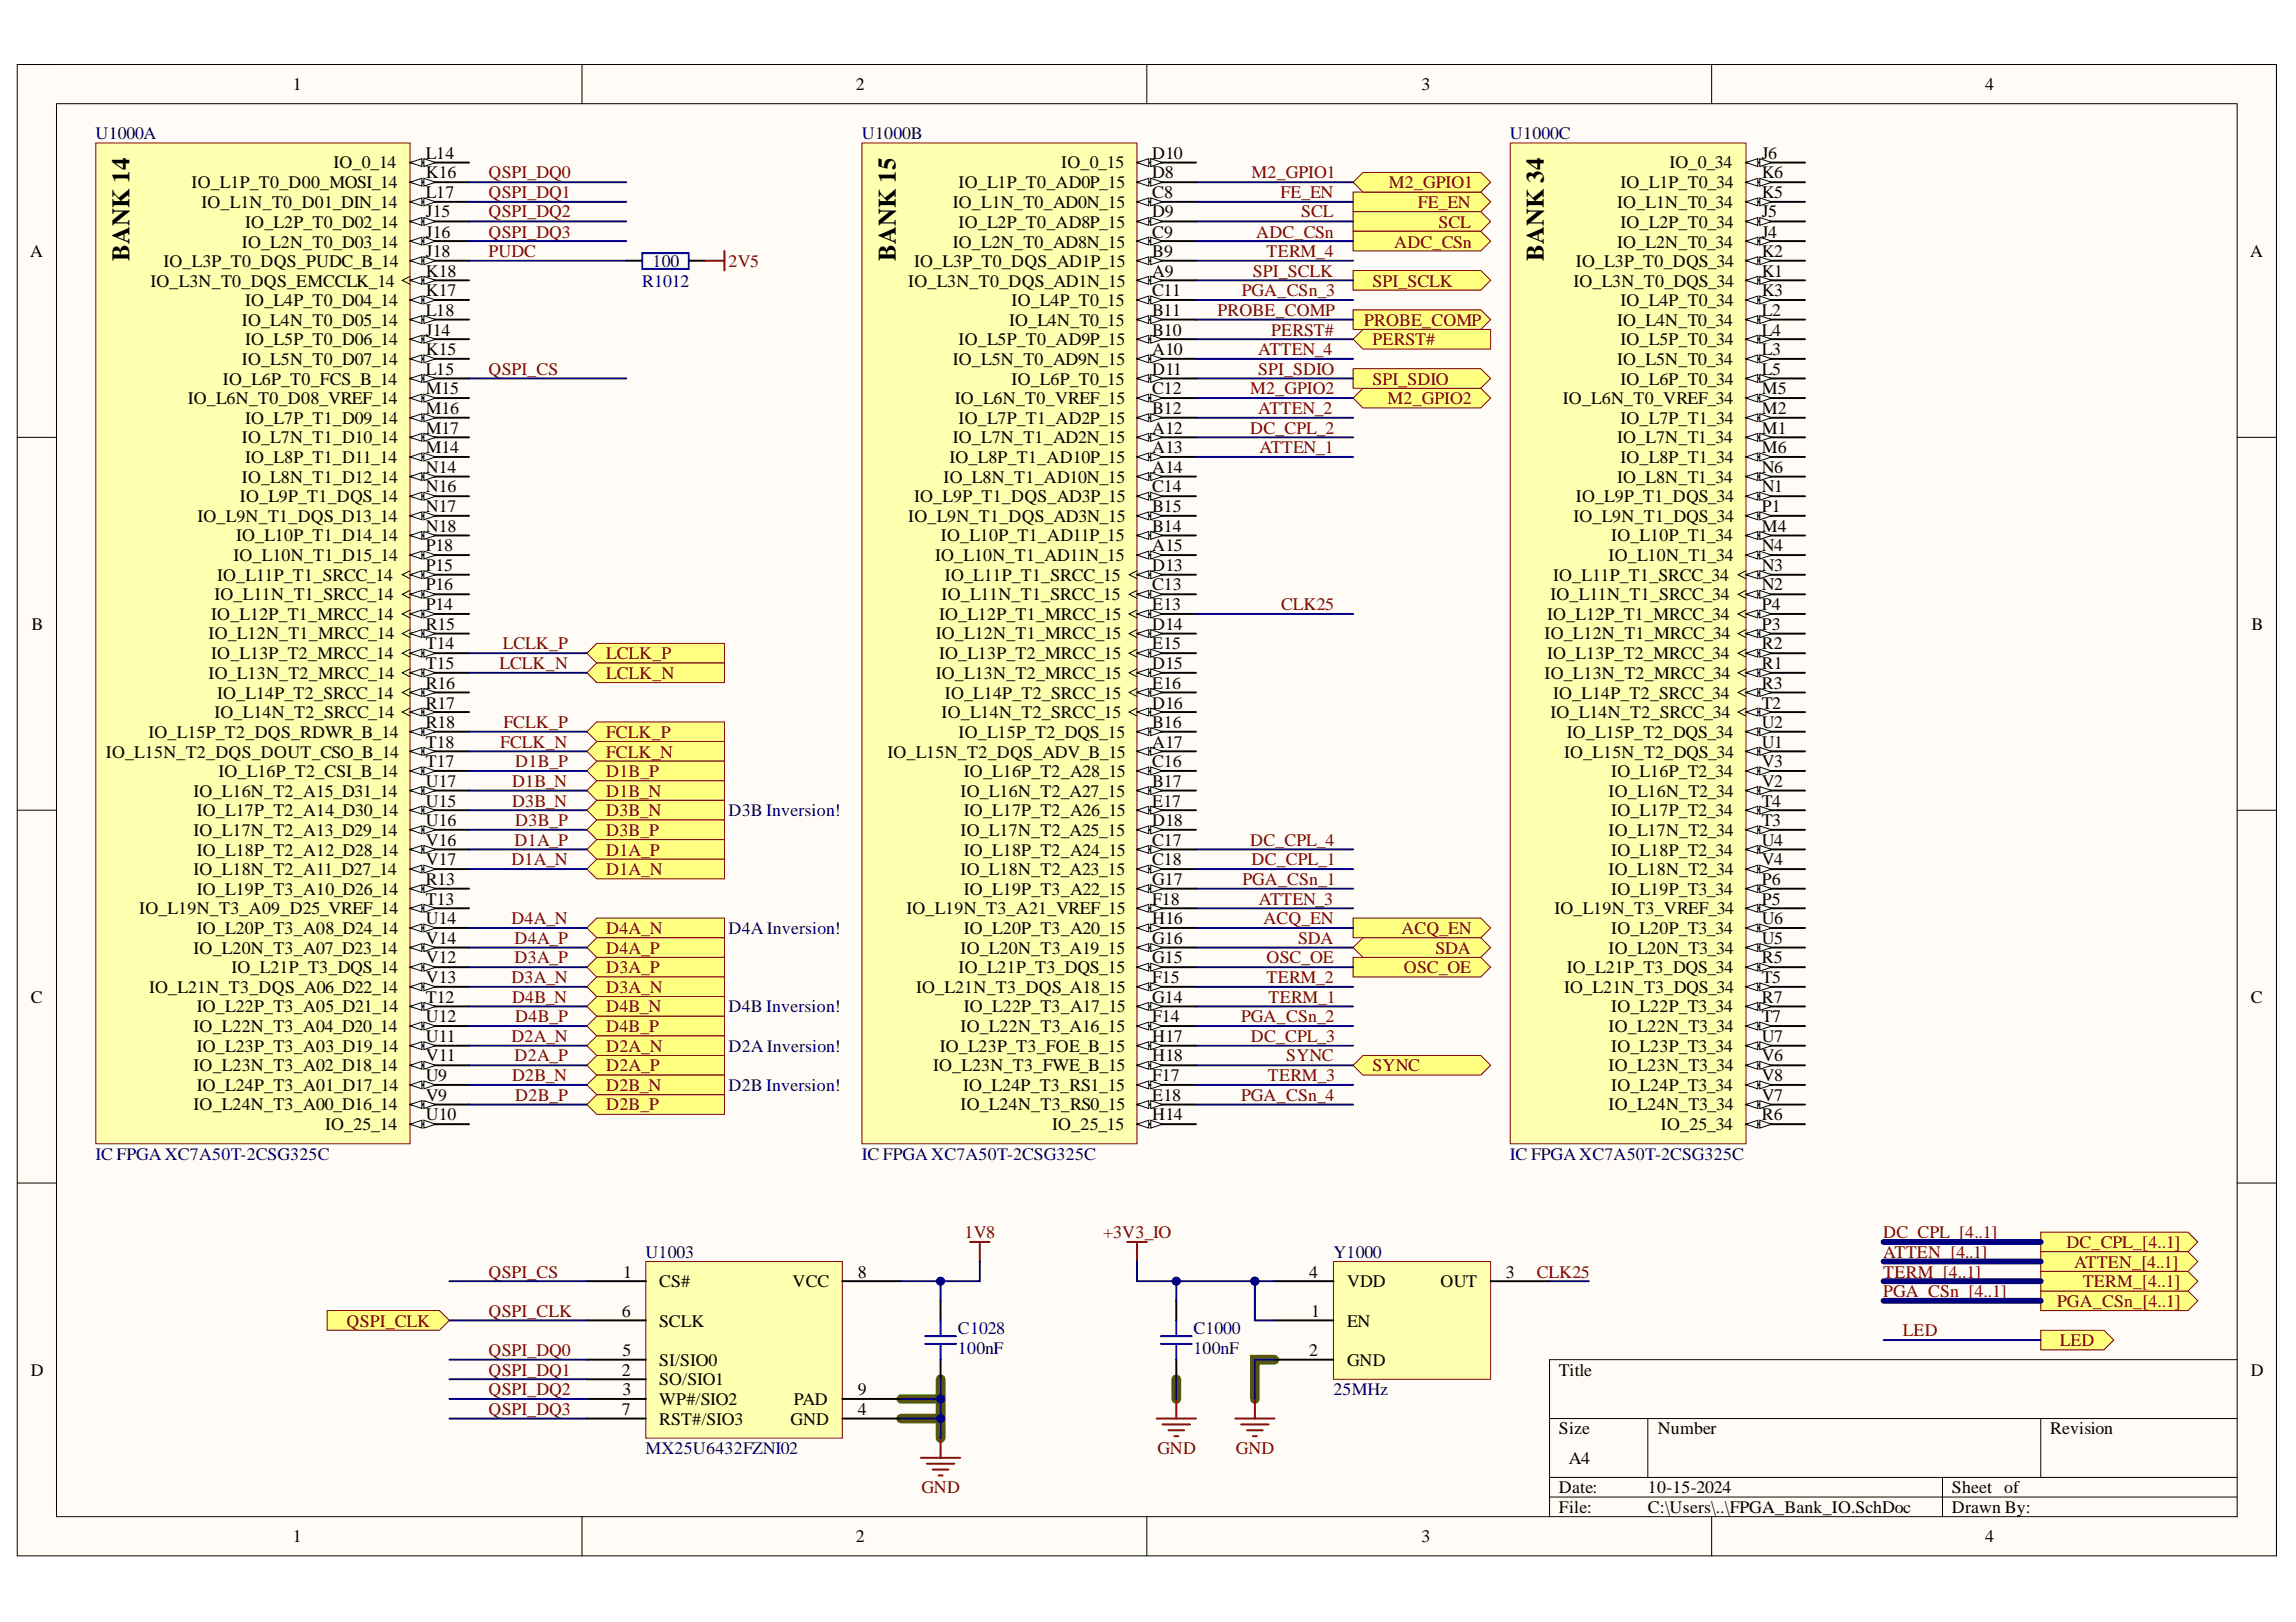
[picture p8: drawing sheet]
<svg xmlns="http://www.w3.org/2000/svg" width="297mm" height="210mm" viewBox="0 0 297 210" stroke-linecap="round" stroke-linejoin="round" font-family="sans-serif">
<defs><g id="words">
<g font-size="3.2">
<text x="16.8" y="33.7" transform="rotate(-90 16.8 33.7)">BANK 14</text>
<text x="115.9" y="33.7" transform="rotate(-90 115.9 33.7)">BANK 15</text>
<text x="199.7" y="33.7" transform="rotate(-90 199.7 33.7)">BANK 34</text>
</g>
<g font-size="2.3">
<text x="37.9" y="11.7">1</text>
<text x="110.7" y="11.7">2</text>
<text x="183.9" y="11.7">3</text>
<text x="256.8" y="11.7">4</text>
<text x="43.1" y="21.8">IO_0_14</text>
<text x="55.1" y="20.5">L14</text>
<text x="55.1" y="23.1">K16</text>
<text x="137.3" y="21.8">IO_0_15</text>
<text x="149.1" y="20.5">D10</text>
<text x="149.1" y="23.1">D8</text>
<text x="216" y="21.8">IO_0_34</text>
<text x="227.9" y="20.5">J6</text>
<text x="227.9" y="23.1">K6</text>
<text x="24.8" y="24.3">IO_L1P_T0_D00_MOSI_14</text>
<text x="26.1" y="26.9">IO_L1N_T0_D01_DIN_14</text>
<text x="31.7" y="29.5">IO_L2P_T0_D02_14</text>
<text x="55.1" y="25.6">L17</text>
<text x="55.1" y="28.1">J15</text>
<text x="123.3" y="26.9">IO_L1N_T0_AD0N_15</text>
<text x="124" y="24.3">IO_L1P_T0_AD0P_15</text>
<text x="124" y="29.5">IO_L2P_T0_AD8P_15</text>
<text x="149.1" y="25.6">C8</text>
<text x="149.1" y="28.1">D9</text>
<text x="209.2" y="26.9">IO_L1N_T0_34</text>
<text x="209.6" y="24.3">IO_L1P_T0_34</text>
<text x="209.6" y="29.5">IO_L2P_T0_34</text>
<text x="227.9" y="25.6">K5</text>
<text x="227.9" y="28.1">J5</text>
<text x="3.9" y="33.3">A</text>
<text x="21.1" y="34.6">IO_L3P_T0_DQS_PUDC_B_14</text>
<text x="31.3" y="32">IO_L2N_T0_D03_14</text>
<text x="55.1" y="30.8">J16</text>
<text x="55.1" y="33.3">J18</text>
<text x="55.1" y="35.8">K18</text>
<text x="118.3" y="34.6">IO_L3P_T0_DQS_AD1P_15</text>
<text x="123.3" y="32">IO_L2N_T0_AD8N_15</text>
<text x="149.1" y="30.8">C9</text>
<text x="149.1" y="33.3">B9</text>
<text x="149.1" y="35.8">A9</text>
<text x="203.9" y="34.6">IO_L3P_T0_DQS_34</text>
<text x="209.2" y="32">IO_L2N_T0_34</text>
<text x="227.9" y="30.8">J4</text>
<text x="227.9" y="33.3">K2</text>
<text x="227.9" y="35.8">K1</text>
<text x="291.1" y="33.3">A</text>
<text x="19.5" y="37.1">IO_L3N_T0_DQS_EMCCLK_14</text>
<text x="31.7" y="39.6">IO_L4P_T0_D04_14</text>
<text x="55.1" y="38.4">K17</text>
<text x="55.1" y="40.9">L18</text>
<text x="117.5" y="37.1">IO_L3N_T0_DQS_AD1N_15</text>
<text x="130.9" y="39.6">IO_L4P_T0_15</text>
<text x="149.1" y="38.4">C11</text>
<text x="149.1" y="40.9">B11</text>
<text x="203.5" y="37.1">IO_L3N_T0_DQS_34</text>
<text x="209.6" y="39.6">IO_L4P_T0_34</text>
<text x="227.9" y="38.4">K3</text>
<text x="227.9" y="40.9">L2</text>
<text x="31.3" y="42.2">IO_L4N_T0_D05_14</text>
<text x="31.3" y="47.2">IO_L5N_T0_D07_14</text>
<text x="31.7" y="44.7">IO_L5P_T0_D06_14</text>
<text x="55.1" y="43.4">J14</text>
<text x="55.1" y="46">K15</text>
<text x="123.3" y="47.2">IO_L5N_T0_AD9N_15</text>
<text x="124" y="44.7">IO_L5P_T0_AD9P_15</text>
<text x="130.5" y="42.2">IO_L4N_T0_15</text>
<text x="149.1" y="43.4">B10</text>
<text x="149.1" y="46">A10</text>
<text x="209.2" y="42.2">IO_L4N_T0_34</text>
<text x="209.2" y="47.2">IO_L5N_T0_34</text>
<text x="209.6" y="44.7">IO_L5P_T0_34</text>
<text x="227.9" y="43.4">L4</text>
<text x="227.9" y="46">L3</text>
<text x="24.3" y="52.3">IO_L6N_T0_D08_VREF_14</text>
<text x="28.8" y="49.8">IO_L6P_T0_FCS_B_14</text>
<text x="55.1" y="48.5">L15</text>
<text x="55.1" y="51">M15</text>
<text x="55.1" y="53.6">M16</text>
<text x="123.5" y="52.3">IO_L6N_T0_VREF_15</text>
<text x="130.9" y="49.8">IO_L6P_T0_15</text>
<text x="149.1" y="48.5">D11</text>
<text x="149.1" y="51">C12</text>
<text x="149.1" y="53.6">B12</text>
<text x="202.2" y="52.3">IO_L6N_T0_VREF_34</text>
<text x="209.6" y="49.8">IO_L6P_T0_34</text>
<text x="227.9" y="48.5">L5</text>
<text x="227.9" y="51">M5</text>
<text x="227.9" y="53.6">M2</text>
<text x="31.3" y="57.4">IO_L7N_T1_D10_14</text>
<text x="31.7" y="54.9">IO_L7P_T1_D09_14</text>
<text x="31.7" y="59.9">IO_L8P_T1_D11_14</text>
<text x="55.1" y="56.1">M17</text>
<text x="55.1" y="58.7">M14</text>
<text x="122.8" y="59.9">IO_L8P_T1_AD10P_15</text>
<text x="123.3" y="57.4">IO_L7N_T1_AD2N_15</text>
<text x="124" y="54.9">IO_L7P_T1_AD2P_15</text>
<text x="149.1" y="56.1">A12</text>
<text x="149.1" y="58.7">A13</text>
<text x="209.2" y="57.4">IO_L7N_T1_34</text>
<text x="209.6" y="54.9">IO_L7P_T1_34</text>
<text x="209.6" y="59.9">IO_L8P_T1_34</text>
<text x="227.9" y="56.1">M1</text>
<text x="227.9" y="58.7">M6</text>
<text x="31" y="65">IO_L9P_T1_DQS_14</text>
<text x="31.3" y="62.5">IO_L8N_T1_D12_14</text>
<text x="55.1" y="61.2">N14</text>
<text x="55.1" y="63.7">N16</text>
<text x="118.3" y="65">IO_L9P_T1_DQS_AD3P_15</text>
<text x="122.1" y="62.5">IO_L8N_T1_AD10N_15</text>
<text x="149.1" y="61.2">A14</text>
<text x="149.1" y="63.7">C14</text>
<text x="203.9" y="65">IO_L9P_T1_DQS_34</text>
<text x="209.2" y="62.5">IO_L8N_T1_34</text>
<text x="227.9" y="61.2">N6</text>
<text x="227.9" y="63.7">N1</text>
<text x="25.5" y="67.5">IO_L9N_T1_DQS_D13_14</text>
<text x="30.5" y="70.1">IO_L10P_T1_D14_14</text>
<text x="55.1" y="66.3">N17</text>
<text x="55.1" y="68.8">N18</text>
<text x="55.1" y="71.3">P18</text>
<text x="117.5" y="67.5">IO_L9N_T1_DQS_AD3N_15</text>
<text x="121.7" y="70.1">IO_L10P_T1_AD11P_15</text>
<text x="149.1" y="66.3">B15</text>
<text x="149.1" y="68.8">B14</text>
<text x="149.1" y="71.3">A15</text>
<text x="203.5" y="67.5">IO_L9N_T1_DQS_34</text>
<text x="208.5" y="70.1">IO_L10P_T1_34</text>
<text x="227.9" y="66.3">P1</text>
<text x="227.9" y="68.8">M4</text>
<text x="227.9" y="71.3">N4</text>
<text x="27.7" y="77.7">IO_L11N_T1_SRCC_14</text>
<text x="28.1" y="75.1">IO_L11P_T1_SRCC_14</text>
<text x="30.2" y="72.6">IO_L10N_T1_D15_14</text>
<text x="55.1" y="73.9">P15</text>
<text x="55.1" y="76.4">P16</text>
<text x="121" y="72.6">IO_L10N_T1_AD11N_15</text>
<text x="121.8" y="77.7">IO_L11N_T1_SRCC_15</text>
<text x="122.2" y="75.1">IO_L11P_T1_SRCC_15</text>
<text x="149.1" y="73.9">D13</text>
<text x="149.1" y="76.4">C13</text>
<text x="200.6" y="77.7">IO_L11N_T1_SRCC_34</text>
<text x="200.9" y="75.1">IO_L11P_T1_SRCC_34</text>
<text x="208.1" y="72.6">IO_L10N_T1_34</text>
<text x="227.9" y="73.9">N3</text>
<text x="227.9" y="76.4">N2</text>
<text x="4.1" y="81.5">B</text>
<text x="27" y="82.7">IO_L12N_T1_MRCC_14</text>
<text x="27.3" y="80.2">IO_L12P_T1_MRCC_14</text>
<text x="55.1" y="78.9">P14</text>
<text x="55.1" y="81.5">R15</text>
<text x="121.1" y="82.7">IO_L12N_T1_MRCC_15</text>
<text x="121.5" y="80.2">IO_L12P_T1_MRCC_15</text>
<text x="149.1" y="78.9">E13</text>
<text x="149.1" y="81.5">D14</text>
<text x="199.8" y="82.7">IO_L12N_T1_MRCC_34</text>
<text x="200.2" y="80.2">IO_L12P_T1_MRCC_34</text>
<text x="227.9" y="78.9">P4</text>
<text x="227.9" y="81.5">P3</text>
<text x="291.3" y="81.5">B</text>
<text x="27" y="87.8">IO_L13N_T2_MRCC_14</text>
<text x="27.3" y="85.3">IO_L13P_T2_MRCC_14</text>
<text x="55.1" y="84">T14</text>
<text x="55.1" y="86.6">T15</text>
<text x="55.1" y="89.2">R16</text>
<text x="121.1" y="87.8">IO_L13N_T2_MRCC_15</text>
<text x="121.5" y="85.3">IO_L13P_T2_MRCC_15</text>
<text x="149.1" y="84">E15</text>
<text x="149.1" y="86.6">D15</text>
<text x="149.1" y="89.2">E16</text>
<text x="199.8" y="87.8">IO_L13N_T2_MRCC_34</text>
<text x="200.2" y="85.3">IO_L13P_T2_MRCC_34</text>
<text x="227.9" y="84">R2</text>
<text x="227.9" y="86.6">R1</text>
<text x="227.9" y="89.2">R3</text>
<text x="19.2" y="95.5">IO_L15P_T2_DQS_RDWR_B_14</text>
<text x="27.7" y="93">IO_L14N_T2_SRCC_14</text>
<text x="28.1" y="90.4">IO_L14P_T2_SRCC_14</text>
<text x="55.1" y="91.7">R17</text>
<text x="55.1" y="94.2">R18</text>
<text x="121.8" y="93">IO_L14N_T2_SRCC_15</text>
<text x="122.2" y="90.4">IO_L14P_T2_SRCC_15</text>
<text x="124" y="95.5">IO_L15P_T2_DQS_15</text>
<text x="149.1" y="91.7">D16</text>
<text x="149.1" y="94.2">B16</text>
<text x="200.6" y="93">IO_L14N_T2_SRCC_34</text>
<text x="200.9" y="90.4">IO_L14P_T2_SRCC_34</text>
<text x="202.7" y="95.5">IO_L15P_T2_DQS_34</text>
<text x="227.9" y="91.7">T2</text>
<text x="227.9" y="94.2">U2</text>
<text x="13.7" y="98">IO_L15N_T2_DQS_DOUT_CSO_B_14</text>
<text x="28.3" y="100.6">IO_L16P_T2_CSI_B_14</text>
<text x="55.1" y="96.8">T18</text>
<text x="55.1" y="99.3">T17</text>
<text x="55.1" y="101.9">U17</text>
<text x="114.8" y="98">IO_L15N_T2_DQS_ADV_B_15</text>
<text x="124.7" y="100.6">IO_L16P_T2_A28_15</text>
<text x="149.1" y="96.8">A17</text>
<text x="149.1" y="99.3">C16</text>
<text x="149.1" y="101.9">B17</text>
<text x="202.4" y="98">IO_L15N_T2_DQS_34</text>
<text x="208.5" y="100.6">IO_L16P_T2_34</text>
<text x="227.9" y="96.8">U1</text>
<text x="227.9" y="99.3">V3</text>
<text x="227.9" y="101.9">V2</text>
<text x="25" y="103.1">IO_L16N_T2_A15_D31_14</text>
<text x="25.5" y="105.7">IO_L17P_T2_A14_D30_14</text>
<text x="55.1" y="104.4">U15</text>
<text x="55.1" y="106.9">U16</text>
<text x="124.3" y="103.1">IO_L16N_T2_A27_15</text>
<text x="124.7" y="105.7">IO_L17P_T2_A26_15</text>
<text x="149.1" y="104.4">E17</text>
<text x="149.1" y="106.9">D18</text>
<text x="208.1" y="103.1">IO_L16N_T2_34</text>
<text x="208.5" y="105.7">IO_L17P_T2_34</text>
<text x="227.9" y="104.4">T4</text>
<text x="227.9" y="106.9">T3</text>
<text x="25" y="108.2">IO_L17N_T2_A13_D29_14</text>
<text x="25" y="113.3">IO_L18N_T2_A11_D27_14</text>
<text x="25.5" y="110.7">IO_L18P_T2_A12_D28_14</text>
<text x="55.1" y="109.5">V16</text>
<text x="55.1" y="112">V17</text>
<text x="124.3" y="108.2">IO_L17N_T2_A25_15</text>
<text x="124.3" y="113.3">IO_L18N_T2_A23_15</text>
<text x="124.7" y="110.7">IO_L18P_T2_A24_15</text>
<text x="149.1" y="109.5">C17</text>
<text x="149.1" y="112">C18</text>
<text x="208.1" y="108.2">IO_L17N_T2_34</text>
<text x="208.1" y="113.3">IO_L18N_T2_34</text>
<text x="208.5" y="110.7">IO_L18P_T2_34</text>
<text x="227.9" y="109.5">U4</text>
<text x="227.9" y="112">V4</text>
<text x="18" y="118.3">IO_L19N_T3_A09_D25_VREF_14</text>
<text x="25.5" y="115.8">IO_L19P_T3_A10_D26_14</text>
<text x="55.1" y="114.5">R13</text>
<text x="55.1" y="117.1">T13</text>
<text x="55.1" y="119.6">U14</text>
<text x="117.3" y="118.3">IO_L19N_T3_A21_VREF_15</text>
<text x="124.7" y="115.8">IO_L19P_T3_A22_15</text>
<text x="149.1" y="114.5">G17</text>
<text x="149.1" y="117.1">F18</text>
<text x="149.1" y="119.6">H16</text>
<text x="201.1" y="118.3">IO_L19N_T3_VREF_34</text>
<text x="208.5" y="115.8">IO_L19P_T3_34</text>
<text x="227.9" y="114.5">P6</text>
<text x="227.9" y="117.1">P5</text>
<text x="227.9" y="119.6">U6</text>
<text x="25" y="123.4">IO_L20N_T3_A07_D23_14</text>
<text x="25.5" y="120.9">IO_L20P_T3_A08_D24_14</text>
<text x="29.9" y="125.9">IO_L21P_T3_DQS_14</text>
<text x="55.1" y="122.1">V14</text>
<text x="55.1" y="124.7">V12</text>
<text x="124" y="125.9">IO_L21P_T3_DQS_15</text>
<text x="124.3" y="123.4">IO_L20N_T3_A19_15</text>
<text x="124.7" y="120.9">IO_L20P_T3_A20_15</text>
<text x="149.1" y="122.1">G16</text>
<text x="149.1" y="124.7">G15</text>
<text x="202.7" y="125.9">IO_L21P_T3_DQS_34</text>
<text x="208.1" y="123.4">IO_L20N_T3_34</text>
<text x="208.5" y="120.9">IO_L20P_T3_34</text>
<text x="227.9" y="122.1">U5</text>
<text x="227.9" y="124.7">R5</text>
<text x="4" y="129.7">C</text>
<text x="19.3" y="128.5">IO_L21N_T3_DQS_A06_D22_14</text>
<text x="25.5" y="131">IO_L22P_T3_A05_D21_14</text>
<text x="55.1" y="127.2">V13</text>
<text x="55.1" y="129.7">T12</text>
<text x="118.5" y="128.5">IO_L21N_T3_DQS_A18_15</text>
<text x="124.7" y="131">IO_L22P_T3_A17_15</text>
<text x="149.1" y="127.2">F15</text>
<text x="149.1" y="129.7">G14</text>
<text x="202.4" y="128.5">IO_L21N_T3_DQS_34</text>
<text x="208.5" y="131">IO_L22P_T3_34</text>
<text x="227.9" y="127.2">T5</text>
<text x="227.9" y="129.7">R7</text>
<text x="291.2" y="129.7">C</text>
<text x="25" y="133.6">IO_L22N_T3_A04_D20_14</text>
<text x="25.5" y="136.1">IO_L23P_T3_A03_D19_14</text>
<text x="55.1" y="132.3">U12</text>
<text x="55.1" y="134.8">U11</text>
<text x="55.1" y="137.4">V11</text>
<text x="121.6" y="136.1">IO_L23P_T3_FOE_B_15</text>
<text x="124.3" y="133.6">IO_L22N_T3_A16_15</text>
<text x="149.1" y="132.3">F14</text>
<text x="149.1" y="134.8">H17</text>
<text x="149.1" y="137.4">H18</text>
<text x="208.1" y="133.6">IO_L22N_T3_34</text>
<text x="208.5" y="136.1">IO_L23P_T3_34</text>
<text x="227.9" y="132.3">T7</text>
<text x="227.9" y="134.8">U7</text>
<text x="227.9" y="137.4">V6</text>
<text x="25" y="138.6">IO_L23N_T3_A02_D18_14</text>
<text x="25" y="143.7">IO_L24N_T3_A00_D16_14</text>
<text x="25.5" y="141.2">IO_L24P_T3_A01_D17_14</text>
<text x="55.1" y="139.9">U9</text>
<text x="55.1" y="142.4">V9</text>
<text x="120.7" y="138.6">IO_L23N_T3_FWE_B_15</text>
<text x="124.3" y="143.7">IO_L24N_T3_RS0_15</text>
<text x="124.6" y="141.2">IO_L24P_T3_RS1_15</text>
<text x="149.1" y="139.9">F17</text>
<text x="149.1" y="142.4">E18</text>
<text x="208.1" y="138.6">IO_L23N_T3_34</text>
<text x="208.1" y="143.7">IO_L24N_T3_34</text>
<text x="208.5" y="141.2">IO_L24P_T3_34</text>
<text x="227.9" y="139.9">V8</text>
<text x="227.9" y="142.4">V7</text>
<text x="42" y="146.2">IO_25_14</text>
<text x="55.1" y="145">U10</text>
<text x="136.1" y="146.2">IO_25_15</text>
<text x="149.1" y="145">H14</text>
<text x="214.9" y="146.2">IO_25_34</text>
<text x="227.9" y="145">R6</text>
<text x="80.6" y="165.3">1</text>
<text x="85.3" y="166.6">CS#</text>
<text x="102.5" y="166.6">VCC</text>
<text x="111" y="165.3">8</text>
<text x="169.4" y="165.3">4</text>
<text x="174.3" y="166.6">VDD</text>
<text x="186.4" y="166.6">OUT</text>
<text x="194.8" y="165.3">3</text>
<text x="80.5" y="170.4">6</text>
<text x="85.3" y="171.7">SCLK</text>
<text x="169.6" y="170.4">1</text>
<text x="174.3" y="171.7">EN</text>
<text x="4" y="178">D</text>
<text x="80.5" y="178">2</text>
<text x="80.5" y="175.5">5</text>
<text x="85.3" y="179.3">SO/SIO1</text>
<text x="85.3" y="176.7">SI/SIO0</text>
<text x="169.4" y="175.5">2</text>
<text x="174.3" y="176.7">GND</text>
<text x="201.7" y="178">Title</text>
<text x="291.2" y="178">D</text>
<text x="80.5" y="183.1">7</text>
<text x="80.5" y="180.6">3</text>
<text x="85.3" y="181.8">WP#/SIO2</text>
<text x="85.3" y="184.4">RST#/SIO3</text>
<text x="102.3" y="184.4">GND</text>
<text x="102.7" y="181.8">PAD</text>
<text x="111" y="183.1">4</text>
<text x="111" y="180.6">9</text>
<text x="201.7" y="185.6">Size</text>
<text x="214.5" y="185.6">Number</text>
<text x="265.2" y="185.6">Revision</text>
<text x="203" y="189.4">A4</text>
<text x="201.7" y="193.2">Date:</text>
<text x="201.7" y="195.8">File:</text>
<text x="213.2" y="193.2">10-15-2024</text>
<text x="213.2" y="195.8">C:\Users\..\FPGA_Bank_IO.SchDoc</text>
<text x="252.5" y="193.2">Sheet of</text>
<text x="252.5" y="195.8">Drawn By:</text>
<text x="37.9" y="199.6">1</text>
<text x="110.7" y="199.6">2</text>
<text x="183.9" y="199.6">3</text>
<text x="256.8" y="199.6">4</text>
</g>
<g font-size="2.3" fill="#000080">
<text x="12.4" y="18">U1000A</text>
<text x="111.5" y="18">U1000B</text>
<text x="195.3" y="18">U1000C</text>
<text x="84.4" y="34.6">100</text>
<text x="83.1" y="37.1">R1012</text>
<text x="94.2" y="105.7">D3B Inversion!</text>
<text x="94.2" y="120.9">D4AInversion!</text>
<text x="94.2" y="131">D4B Inversion!</text>
<text x="94.2" y="136.1">D2AInversion!</text>
<text x="94.2" y="141.2">D2B Inversion!</text>
<text x="12.4" y="150.1">IC FPGAXC7A50T-2CSG325C</text>
<text x="111.5" y="150.1">IC FPGAXC7A50T-2CSG325C</text>
<text x="195.3" y="150.1">IC FPGAXC7A50T-2CSG325C</text>
<text x="83.5" y="162.8">U1003</text>
<text x="172.5" y="162.8">Y1000</text>
<text x="123.9" y="172.7">C1028</text>
<text x="154.4" y="172.7">C1000</text>
<text x="123.9" y="175.2">100nF</text>
<text x="154.4" y="175.2">100nF</text>
<text x="172.5" y="180.6">25MHz</text>
<text x="83.5" y="188.2">MX25U6432FZNI02</text>
</g>
<g font-size="2.3" fill="#800000">
<text x="63.2" y="23.1">QSPI_DQ0</text>
<text x="161.9" y="23.1">M2_GPIO1</text>
<text x="63.2" y="25.6">QSPI_DQ1</text>
<text x="63.2" y="28.1">QSPI_DQ2</text>
<text x="165.6" y="25.6">FE_EN</text>
<text x="168.4" y="28.1">SCL</text>
<text x="179.7" y="24.3">M2_GPIO1</text>
<text x="183.4" y="26.9">FE_EN</text>
<text x="186.1" y="29.5">SCL</text>
<text x="63.2" y="33.3">PUDC</text>
<text x="63.2" y="30.8">QSPI_DQ3</text>
<text x="94.2" y="34.6">2V5</text>
<text x="162.1" y="35.8">SPI_SCLK</text>
<text x="162.5" y="30.8">ADC_CSn</text>
<text x="163.9" y="33.3">TERM_4</text>
<text x="180.4" y="32">ADC_CSn</text>
<text x="157.5" y="40.9">PROBE_COMP</text>
<text x="160.7" y="38.4">PGA_CSn_3</text>
<text x="177.6" y="37.1">SPI_SCLK</text>
<text x="162.8" y="46">ATTEN_4</text>
<text x="164.5" y="43.4">PERST#</text>
<text x="176.5" y="42.2">PROBE_COMP</text>
<text x="177.6" y="44.7">PERST#</text>
<text x="63.2" y="48.5">QSPI_CS</text>
<text x="161.8" y="51">M2_GPIO2</text>
<text x="162.8" y="48.5">SPI_SDIO</text>
<text x="162.8" y="53.6">ATTEN_2</text>
<text x="177.6" y="49.8">SPI_SDIO</text>
<text x="179.5" y="52.3">M2_GPIO2</text>
<text x="161.8" y="56.1">DC_CPL_2</text>
<text x="162.9" y="58.7">ATTEN_1</text>
<text x="165.7" y="78.9">CLK25</text>
<text x="64.6" y="86.6">LCLK_N</text>
<text x="65.1" y="84">LCLK_P</text>
<text x="78.4" y="85.3">LCLK_P</text>
<text x="78.4" y="87.8">LCLK_N</text>
<text x="65.1" y="94.2">FCLK_P</text>
<text x="78.4" y="95.5">FCLK_P</text>
<text x="64.7" y="96.8">FCLK_N</text>
<text x="66.2" y="101.9">D1B_N</text>
<text x="66.7" y="99.3">D1B_P</text>
<text x="78.4" y="98">FCLK_N</text>
<text x="78.4" y="100.6">D1B_P</text>
<text x="66.2" y="104.4">D3B_N</text>
<text x="66.7" y="106.9">D3B_P</text>
<text x="78.4" y="103.1">D1B_N</text>
<text x="78.4" y="105.7">D3B_N</text>
<text x="66.2" y="112">D1A_N</text>
<text x="66.6" y="109.5">D1A_P</text>
<text x="78.4" y="108.2">D3B_P</text>
<text x="78.4" y="110.7">D1A_P</text>
<text x="78.4" y="113.3">D1A_N</text>
<text x="161.8" y="109.5">DC_CPL_4</text>
<text x="161.9" y="112">DC_CPL_1</text>
<text x="66.2" y="119.6">D4A_N</text>
<text x="160.7" y="114.5">PGA_CSn_1</text>
<text x="162.9" y="117.1">ATTEN_3</text>
<text x="163.4" y="119.6">ACQ_EN</text>
<text x="66.6" y="122.1">D4A_P</text>
<text x="66.6" y="124.7">D3A_P</text>
<text x="78.4" y="120.9">D4A_N</text>
<text x="78.4" y="123.4">D4A_P</text>
<text x="78.4" y="125.9">D3A_P</text>
<text x="163.9" y="124.7">OSC_OE</text>
<text x="167.9" y="122.1">SDA</text>
<text x="181.3" y="120.9">ACQ_EN</text>
<text x="181.6" y="125.9">OSC_OE</text>
<text x="185.7" y="123.4">SDA</text>
<text x="66.2" y="127.2">D3A_N</text>
<text x="66.2" y="129.7">D4B_N</text>
<text x="78.4" y="128.5">D3A_N</text>
<text x="78.4" y="131">D4B_N</text>
<text x="163.9" y="127.2">TERM_2</text>
<text x="164.1" y="129.7">TERM_1</text>
<text x="66.2" y="134.8">D2A_N</text>
<text x="66.6" y="137.4">D2A_P</text>
<text x="66.7" y="132.3">D4B_P</text>
<text x="78.4" y="133.6">D4B_P</text>
<text x="78.4" y="136.1">D2A_N</text>
<text x="160.6" y="132.3">PGA_CSn_2</text>
<text x="161.8" y="134.8">DC_CPL_3</text>
<text x="166.4" y="137.4">SYNC</text>
<text x="66.2" y="139.9">D2B_N</text>
<text x="66.7" y="142.4">D2B_P</text>
<text x="78.4" y="138.6">D2A_P</text>
<text x="78.4" y="141.2">D2B_N</text>
<text x="78.4" y="143.7">D2B_P</text>
<text x="160.6" y="142.4">PGA_CSn_4</text>
<text x="164" y="139.9">TERM_3</text>
<text x="177.6" y="138.6">SYNC</text>
<text x="124.8" y="160.3">1V8</text>
<text x="142.7" y="160.3">+3V3_IO</text>
<text x="243.6" y="160.3">DC_CPL_[4..1]</text>
<text x="267.3" y="161.5">DC_CPL_[4..1]</text>
<text x="63.2" y="165.3">QSPI_CS</text>
<text x="198.8" y="165.3">CLK25</text>
<text x="243.6" y="162.8">ATTEN_[4..1]</text>
<text x="243.6" y="167.9">PGA_CSn_[4..1]</text>
<text x="243.6" y="165.3">TERM_[4..1]</text>
<text x="268.4" y="164.1">ATTEN_[4..1]</text>
<text x="269.4" y="166.6">TERM_[4..1]</text>
<text x="44.8" y="171.7">QSPI_CLK</text>
<text x="63.2" y="170.4">QSPI_CLK</text>
<text x="246.2" y="172.9">LED</text>
<text x="266.2" y="169.1">PGA_CSn_[4..1]</text>
<text x="63.2" y="175.5">QSPI_DQ0</text>
<text x="63.2" y="178">QSPI_DQ1</text>
<text x="266.5" y="174.2">LED</text>
<text x="63.2" y="180.6">QSPI_DQ2</text>
<text x="63.2" y="183.1">QSPI_DQ3</text>
<text x="149.7" y="188.2">GND</text>
<text x="159.9" y="188.2">GND</text>
<text x="119.2" y="193.2">GND</text>
</g>
</g></defs>
<path d="M2.2 8.3h292.3v193h-292.3z" fill-rule="evenodd" fill="#fffcf8"/>
<path d="M2.2 8.3h292.3v193h-292.3z" fill="none" stroke="#000" stroke-width=".13"/>
<path d="M7.3 13.4h282.1v182.9h-282.1z" fill-rule="evenodd" fill="#fffcf8"/>
<g fill="none" stroke="#000" stroke-width=".13">
<path d="M2.2 8.3h5.1M7.3 13.4h282.1v182.9h-282.1zM75.3 8.3v5.1M148.4 8.3v5.1M221.4 8.3v5.1M289.4 8.3h5.1v5.1M2.2 56.6h5.1M289.4 56.6h5.1M2.2 104.8h5.1M289.4 104.9h5.1M2.2 153.1h5.1M289.4 153.1h5.1"/>
<path d="M289.4 176h-88.9v20.3M75.3 196.3v5M148.4 196.3v5M200.5 183.6h88.9M200.5 191.2h88.9M200.5 193.7h88.9M213.2 183.6v7.6M221.4 196.3v5M251.3 191.2v5.1M264 183.6v7.6M294.5 196.3v5"/>
</g>
<path d="M121.7 178.5v7.6M152.2 178.5v2.5M164.9 176h-2.6v5M116.6 183.6h5.1M116.6 181h5.1" fill="none" stroke="#00be00" stroke-width="1.3"/>
<path d="M172.5 163.3h20.3v15.2h-20.3z" fill-rule="evenodd" fill="#ffffb0"/>
<path d="M172.5 163.3h20.3v15.2h-20.3z" fill="none" stroke="#800000" stroke-width=".13"/>
<path d="M152.2 168.3v2.6M152.2 176v2.5M164.9 165.8h7.6M164.9 176h7.6M164.9 170.9h7.6M192.8 165.8h7.7" fill="none" stroke="#000" stroke-width=".25"/>
<path d="M150.2 172.9h4M150.2 173.9h4M152.2 170.9v2M152.2 173.9v2.1" fill="none" stroke="#00f" stroke-width=".25"/>
<path d="M145.8 160.7h2.6M147.1 160.7v2.6M149.6 183.6h5.1M150.4 184.3h3.6M151.2 185.1h2M151.9 185.9h.5M152.2 181v2.6M159.8 183.6h5.1M160.6 184.3h3.5M161.3 185.1h2.1M162.1 185.9h.5M162.3 181v2.6" fill="none" stroke="#800000" stroke-width=".25"/>
<path d="M264 159.5h19.1l1.2 1.2-1.2 1.3h-19.1z" fill-rule="evenodd" fill="#ffff80"/>
<path d="M264 159.5h19.1l1.2 1.2-1.2 1.3h-19.1z" fill="none" stroke="#800000" stroke-width=".13"/>
<path d="M264 162h19.1l1.2 1.3-1.2 1.2h-19.1z" fill-rule="evenodd" fill="#ffff80"/>
<path d="M264 162h19.1l1.2 1.3-1.2 1.2h-19.1z" fill="none" stroke="#800000" stroke-width=".13"/>
<path d="M264 167.1h19.1l1.2 1.2-1.2 1.3h-19.1z" fill-rule="evenodd" fill="#ffff80"/>
<path d="M264 167.1h19.1l1.2 1.2-1.2 1.3h-19.1z" fill="none" stroke="#800000" stroke-width=".13"/>
<path d="M264 164.5h19.1l1.2 1.3-1.2 1.3h-19.1z" fill-rule="evenodd" fill="#ffff80"/>
<path d="M264 164.5h19.1l1.2 1.3-1.2 1.3h-19.1z" fill="none" stroke="#800000" stroke-width=".13"/>
<path d="M264 172.2h8.2l1.3 1.2-1.3 1.3h-8.2z" fill-rule="evenodd" fill="#ffff80"/>
<path d="M264 172.2h8.2l1.3 1.2-1.3 1.3h-8.2z" fill="none" stroke="#800000" stroke-width=".13"/>
<path d="M12.4 18.5h40.7v129.5h-40.7z" fill-rule="evenodd" fill="#ffffb0"/>
<path d="M12.4 18.5h40.7v129.5h-40.7z" fill="none" stroke="#800000" stroke-width=".13"/>
<path d="M53.1 21h7.6" fill="none" stroke="#000" stroke-width=".25"/>
<path d="M53.1 21l1.5-.5v1z" fill="#f8fcff"/>
<path d="M53.1 21l1.5-.5v1z" fill="none" stroke="#000" stroke-width=".13"/>
<path d="M54.8 20.5l1.6 .5-1.6 .5z" fill="#f8fcff"/>
<path d="M54.8 20.5l1.6 .5-1.6 .5z" fill="none" stroke="#000" stroke-width=".13"/>
<path d="M53.1 23.6h7.6" fill="none" stroke="#000" stroke-width=".25"/>
<path d="M53.1 23.6l1.5-.5v1z" fill="#f8fcff"/>
<path d="M53.1 23.6l1.5-.5v1z" fill="none" stroke="#000" stroke-width=".13"/>
<path d="M54.8 23.1l1.6 .5-1.6 .5z" fill="#f8fcff"/>
<path d="M54.8 23.1l1.6 .5-1.6 .5z" fill="none" stroke="#000" stroke-width=".13"/>
<path d="M53.1 26.1h7.6" fill="none" stroke="#000" stroke-width=".25"/>
<path d="M53.1 26.1l1.5-.5v1z" fill="#f8fcff"/>
<path d="M53.1 26.1l1.5-.5v1z" fill="none" stroke="#000" stroke-width=".13"/>
<path d="M54.8 25.6l1.6 .5-1.6 .5z" fill="#f8fcff"/>
<path d="M54.8 25.6l1.6 .5-1.6 .5z" fill="none" stroke="#000" stroke-width=".13"/>
<path d="M53.1 28.7h7.6" fill="none" stroke="#000" stroke-width=".25"/>
<path d="M53.1 28.7l1.5-.5v1z" fill="#f8fcff"/>
<path d="M53.1 28.7l1.5-.5v1z" fill="none" stroke="#000" stroke-width=".13"/>
<path d="M54.8 28.2l1.6 .5-1.6 .5z" fill="#f8fcff"/>
<path d="M54.8 28.2l1.6 .5-1.6 .5z" fill="none" stroke="#000" stroke-width=".13"/>
<path d="M53.1 31.2h7.6" fill="none" stroke="#000" stroke-width=".25"/>
<path d="M53.1 31.2l1.5-.5v1z" fill="#f8fcff"/>
<path d="M53.1 31.2l1.5-.5v1z" fill="none" stroke="#000" stroke-width=".13"/>
<path d="M54.8 30.7l1.6 .5-1.6 .5z" fill="#f8fcff"/>
<path d="M54.8 30.7l1.6 .5-1.6 .5z" fill="none" stroke="#000" stroke-width=".13"/>
<path d="M53.1 33.7h7.6" fill="none" stroke="#000" stroke-width=".25"/>
<path d="M53.1 33.7l1.5-.5v1z" fill="#f8fcff"/>
<path d="M53.1 33.7l1.5-.5v1z" fill="none" stroke="#000" stroke-width=".13"/>
<path d="M54.8 33.2l1.6 .5-1.6 .5z" fill="#f8fcff"/>
<path d="M54.8 33.2l1.6 .5-1.6 .5z" fill="none" stroke="#000" stroke-width=".13"/>
<path d="M53.1 36.3h7.6" fill="none" stroke="#000" stroke-width=".25"/>
<path d="M53.1 36.3l1.5-.5v1z" fill="#f8fcff"/>
<path d="M53.1 36.3l1.5-.5v1z" fill="none" stroke="#000" stroke-width=".13"/>
<path d="M54.8 35.8l1.6 .5-1.6 .5z" fill="#f8fcff"/>
<path d="M53.1 35.8l-1.1 .5 1.1 .5M54.8 35.8l1.6 .5-1.6 .5z" fill="none" stroke="#000" stroke-width=".13"/>
<path d="M53.1 38.8h7.6" fill="none" stroke="#000" stroke-width=".25"/>
<path d="M53.1 38.8l1.5-.5v1z" fill="#f8fcff"/>
<path d="M53.1 38.8l1.5-.5v1z" fill="none" stroke="#000" stroke-width=".13"/>
<path d="M54.8 38.3l1.6 .5-1.6 .5z" fill="#f8fcff"/>
<path d="M54.8 38.3l1.6 .5-1.6 .5z" fill="none" stroke="#000" stroke-width=".13"/>
<path d="M53.1 41.4h7.6" fill="none" stroke="#000" stroke-width=".25"/>
<path d="M53.1 41.4l1.5-.5v1z" fill="#f8fcff"/>
<path d="M53.1 41.4l1.5-.5v1z" fill="none" stroke="#000" stroke-width=".13"/>
<path d="M54.8 40.9l1.6 .5-1.6 .5z" fill="#f8fcff"/>
<path d="M54.8 40.9l1.6 .5-1.6 .5z" fill="none" stroke="#000" stroke-width=".13"/>
<path d="M53.1 43.9h7.6" fill="none" stroke="#000" stroke-width=".25"/>
<path d="M53.1 43.9l1.5-.5v1z" fill="#f8fcff"/>
<path d="M53.1 43.9l1.5-.5v1z" fill="none" stroke="#000" stroke-width=".13"/>
<path d="M54.8 43.4l1.6 .5-1.6 .5z" fill="#f8fcff"/>
<path d="M54.8 43.4l1.6 .5-1.6 .5z" fill="none" stroke="#000" stroke-width=".13"/>
<path d="M53.1 46.4h7.6" fill="none" stroke="#000" stroke-width=".25"/>
<path d="M53.1 46.4l1.5-.5v1z" fill="#f8fcff"/>
<path d="M53.1 46.4l1.5-.5v1z" fill="none" stroke="#000" stroke-width=".13"/>
<path d="M54.8 45.9l1.6 .5-1.6 .5z" fill="#f8fcff"/>
<path d="M54.8 45.9l1.6 .5-1.6 .5z" fill="none" stroke="#000" stroke-width=".13"/>
<path d="M53.1 49h7.6" fill="none" stroke="#000" stroke-width=".25"/>
<path d="M53.1 49l1.5-.5v1z" fill="#f8fcff"/>
<path d="M53.1 49l1.5-.5v1z" fill="none" stroke="#000" stroke-width=".13"/>
<path d="M54.8 48.5l1.6 .5-1.6 .5z" fill="#f8fcff"/>
<path d="M54.8 48.5l1.6 .5-1.6 .5z" fill="none" stroke="#000" stroke-width=".13"/>
<path d="M53.1 51.5h7.6" fill="none" stroke="#000" stroke-width=".25"/>
<path d="M53.1 51.5l1.5-.5v1z" fill="#f8fcff"/>
<path d="M53.1 51.5l1.5-.5v1z" fill="none" stroke="#000" stroke-width=".13"/>
<path d="M54.8 51l1.6 .5-1.6 .5z" fill="#f8fcff"/>
<path d="M54.8 51l1.6 .5-1.6 .5z" fill="none" stroke="#000" stroke-width=".13"/>
<path d="M53.1 54.1h7.6" fill="none" stroke="#000" stroke-width=".25"/>
<path d="M53.1 54.1l1.5-.6v1.1z" fill="#f8fcff"/>
<path d="M53.1 54.1l1.5-.6v1.1z" fill="none" stroke="#000" stroke-width=".13"/>
<path d="M54.8 53.5l1.6 .6-1.6 .5z" fill="#f8fcff"/>
<path d="M54.8 53.5l1.6 .6-1.6 .5z" fill="none" stroke="#000" stroke-width=".13"/>
<path d="M53.1 56.6h7.6" fill="none" stroke="#000" stroke-width=".25"/>
<path d="M53.1 56.6l1.5-.5v1z" fill="#f8fcff"/>
<path d="M53.1 56.6l1.5-.5v1z" fill="none" stroke="#000" stroke-width=".13"/>
<path d="M54.8 56.1l1.6 .5-1.6 .5z" fill="#f8fcff"/>
<path d="M54.8 56.1l1.6 .5-1.6 .5z" fill="none" stroke="#000" stroke-width=".13"/>
<path d="M53.1 59.1h7.6" fill="none" stroke="#000" stroke-width=".25"/>
<path d="M53.1 59.1l1.5-.5v1z" fill="#f8fcff"/>
<path d="M53.1 59.1l1.5-.5v1z" fill="none" stroke="#000" stroke-width=".13"/>
<path d="M54.8 58.6l1.6 .5-1.6 .5z" fill="#f8fcff"/>
<path d="M54.8 58.6l1.6 .5-1.6 .5z" fill="none" stroke="#000" stroke-width=".13"/>
<path d="M53.1 61.7h7.6" fill="none" stroke="#000" stroke-width=".25"/>
<path d="M53.1 61.7l1.5-.5v1z" fill="#f8fcff"/>
<path d="M53.1 61.7l1.5-.5v1z" fill="none" stroke="#000" stroke-width=".13"/>
<path d="M54.8 61.2l1.6 .5-1.6 .5z" fill="#f8fcff"/>
<path d="M54.8 61.2l1.6 .5-1.6 .5z" fill="none" stroke="#000" stroke-width=".13"/>
<path d="M53.1 64.2h7.6" fill="none" stroke="#000" stroke-width=".25"/>
<path d="M53.1 64.2l1.5-.5v1z" fill="#f8fcff"/>
<path d="M53.1 64.2l1.5-.5v1z" fill="none" stroke="#000" stroke-width=".13"/>
<path d="M54.8 63.7l1.6 .5-1.6 .5z" fill="#f8fcff"/>
<path d="M54.8 63.7l1.6 .5-1.6 .5z" fill="none" stroke="#000" stroke-width=".13"/>
<path d="M53.1 66.8h7.6" fill="none" stroke="#000" stroke-width=".25"/>
<path d="M53.1 66.8l1.5-.6v1.1z" fill="#f8fcff"/>
<path d="M53.1 66.8l1.5-.6v1.1z" fill="none" stroke="#000" stroke-width=".13"/>
<path d="M54.8 66.2l1.6 .6-1.6 .5z" fill="#f8fcff"/>
<path d="M54.8 66.2l1.6 .6-1.6 .5z" fill="none" stroke="#000" stroke-width=".13"/>
<path d="M53.1 69.3h7.6" fill="none" stroke="#000" stroke-width=".25"/>
<path d="M53.1 69.3l1.5-.5v1z" fill="#f8fcff"/>
<path d="M53.1 69.3l1.5-.5v1z" fill="none" stroke="#000" stroke-width=".13"/>
<path d="M54.8 68.8l1.6 .5-1.6 .5z" fill="#f8fcff"/>
<path d="M54.8 68.8l1.6 .5-1.6 .5z" fill="none" stroke="#000" stroke-width=".13"/>
<path d="M53.1 71.8h7.6" fill="none" stroke="#000" stroke-width=".25"/>
<path d="M53.1 71.8l1.5-.5v1z" fill="#f8fcff"/>
<path d="M53.1 71.8l1.5-.5v1z" fill="none" stroke="#000" stroke-width=".13"/>
<path d="M54.8 71.3l1.6 .5-1.6 .5z" fill="#f8fcff"/>
<path d="M54.8 71.3l1.6 .5-1.6 .5z" fill="none" stroke="#000" stroke-width=".13"/>
<path d="M53.1 74.4h7.6" fill="none" stroke="#000" stroke-width=".25"/>
<path d="M53.1 74.4l1.5-.5v1z" fill="#f8fcff"/>
<path d="M53.1 74.4l1.5-.5v1z" fill="none" stroke="#000" stroke-width=".13"/>
<path d="M54.8 73.9l1.6 .5-1.6 .5z" fill="#f8fcff"/>
<path d="M53.1 73.9l-1.1 .5 1.1 .5M54.8 73.9l1.6 .5-1.6 .5z" fill="none" stroke="#000" stroke-width=".13"/>
<path d="M53.1 76.9h7.6" fill="none" stroke="#000" stroke-width=".25"/>
<path d="M53.1 76.9l1.5-.5v1z" fill="#f8fcff"/>
<path d="M53.1 76.9l1.5-.5v1z" fill="none" stroke="#000" stroke-width=".13"/>
<path d="M54.8 76.4l1.6 .5-1.6 .5z" fill="#f8fcff"/>
<path d="M53.1 76.4l-1.1 .5 1.1 .5M54.8 76.4l1.6 .5-1.6 .5z" fill="none" stroke="#000" stroke-width=".13"/>
<path d="M53.1 79.5h7.6" fill="none" stroke="#000" stroke-width=".25"/>
<path d="M53.1 79.5l1.5-.6v1.1z" fill="#f8fcff"/>
<path d="M53.1 79.5l1.5-.6v1.1z" fill="none" stroke="#000" stroke-width=".13"/>
<path d="M54.8 78.9l1.6 .6-1.6 .5z" fill="#f8fcff"/>
<path d="M53.1 78.9l-1.1 .6 1.1 .5M54.8 78.9l1.6 .6-1.6 .5z" fill="none" stroke="#000" stroke-width=".13"/>
<path d="M53.1 82h7.6" fill="none" stroke="#000" stroke-width=".25"/>
<path d="M53.1 82l1.5-.5v1z" fill="#f8fcff"/>
<path d="M53.1 82l1.5-.5v1z" fill="none" stroke="#000" stroke-width=".13"/>
<path d="M54.8 81.5l1.6 .5-1.6 .5z" fill="#f8fcff"/>
<path d="M53.1 81.5l-1.1 .5 1.1 .5M54.8 81.5l1.6 .5-1.6 .5z" fill="none" stroke="#000" stroke-width=".13"/>
<path d="M53.1 84.5h7.6" fill="none" stroke="#000" stroke-width=".25"/>
<path d="M53.1 84.5l1.5-.5v1z" fill="#f8fcff"/>
<path d="M53.1 84.5l1.5-.5v1z" fill="none" stroke="#000" stroke-width=".13"/>
<path d="M54.8 84l1.6 .5-1.6 .5z" fill="#f8fcff"/>
<path d="M53.1 84l-1.1 .5 1.1 .5M54.8 84l1.6 .5-1.6 .5z" fill="none" stroke="#000" stroke-width=".13"/>
<path d="M53.1 87.1h7.6" fill="none" stroke="#000" stroke-width=".25"/>
<path d="M53.1 87.1l1.5-.5v1z" fill="#f8fcff"/>
<path d="M53.1 87.1l1.5-.5v1z" fill="none" stroke="#000" stroke-width=".13"/>
<path d="M54.8 86.6l1.6 .5-1.6 .5z" fill="#f8fcff"/>
<path d="M53.1 86.6l-1.1 .5 1.1 .5M54.8 86.6l1.6 .5-1.6 .5z" fill="none" stroke="#000" stroke-width=".13"/>
<path d="M53.1 89.6h7.6" fill="none" stroke="#000" stroke-width=".25"/>
<path d="M53.1 89.6l1.5-.5v1z" fill="#f8fcff"/>
<path d="M53.1 89.6l1.5-.5v1z" fill="none" stroke="#000" stroke-width=".13"/>
<path d="M54.8 89.1l1.6 .5-1.6 .5z" fill="#f8fcff"/>
<path d="M53.1 89.1l-1.1 .5 1.1 .5M54.8 89.1l1.6 .5-1.6 .5z" fill="none" stroke="#000" stroke-width=".13"/>
<path d="M53.1 92.1h7.6" fill="none" stroke="#000" stroke-width=".25"/>
<path d="M53.1 92.1l1.5-.5v1.1z" fill="#f8fcff"/>
<path d="M53.1 92.1l1.5-.5v1.1z" fill="none" stroke="#000" stroke-width=".13"/>
<path d="M54.8 91.6l1.6 .5-1.6 .6z" fill="#f8fcff"/>
<path d="M53.1 91.6l-1.1 .5 1.1 .6M54.8 91.6l1.6 .5-1.6 .6z" fill="none" stroke="#000" stroke-width=".13"/>
<path d="M53.1 94.7h7.6" fill="none" stroke="#000" stroke-width=".25"/>
<path d="M53.1 94.7l1.5-.5v1z" fill="#f8fcff"/>
<path d="M53.1 94.7l1.5-.5v1z" fill="none" stroke="#000" stroke-width=".13"/>
<path d="M54.8 94.2l1.6 .5-1.6 .5z" fill="#f8fcff"/>
<path d="M54.8 94.2l1.6 .5-1.6 .5z" fill="none" stroke="#000" stroke-width=".13"/>
<path d="M53.1 97.2h7.6" fill="none" stroke="#000" stroke-width=".25"/>
<path d="M53.1 97.2l1.5-.5v1z" fill="#f8fcff"/>
<path d="M53.1 97.2l1.5-.5v1z" fill="none" stroke="#000" stroke-width=".13"/>
<path d="M54.8 96.7l1.6 .5-1.6 .5z" fill="#f8fcff"/>
<path d="M54.8 96.7l1.6 .5-1.6 .5z" fill="none" stroke="#000" stroke-width=".13"/>
<path d="M53.1 99.8h7.6" fill="none" stroke="#000" stroke-width=".25"/>
<path d="M53.1 99.8l1.5-.5v1z" fill="#f8fcff"/>
<path d="M53.1 99.8l1.5-.5v1z" fill="none" stroke="#000" stroke-width=".13"/>
<path d="M54.8 99.3l1.6 .5-1.6 .5z" fill="#f8fcff"/>
<path d="M54.8 99.3l1.6 .5-1.6 .5z" fill="none" stroke="#000" stroke-width=".13"/>
<path d="M53.1 102.3h7.6" fill="none" stroke="#000" stroke-width=".25"/>
<path d="M53.1 102.3l1.5-.5v1z" fill="#f8fcff"/>
<path d="M53.1 102.3l1.5-.5v1z" fill="none" stroke="#000" stroke-width=".13"/>
<path d="M54.8 101.8l1.6 .5-1.6 .5z" fill="#f8fcff"/>
<path d="M54.8 101.8l1.6 .5-1.6 .5z" fill="none" stroke="#000" stroke-width=".13"/>
<path d="M53.1 104.8h7.6" fill="none" stroke="#000" stroke-width=".25"/>
<path d="M53.1 104.8l1.5-.5v1.1z" fill="#f8fcff"/>
<path d="M53.1 104.8l1.5-.5v1.1z" fill="none" stroke="#000" stroke-width=".13"/>
<path d="M54.8 104.3l1.6 .5-1.6 .6z" fill="#f8fcff"/>
<path d="M54.8 104.3l1.6 .5-1.6 .6z" fill="none" stroke="#000" stroke-width=".13"/>
<path d="M53.1 107.4h7.6" fill="none" stroke="#000" stroke-width=".25"/>
<path d="M53.1 107.4l1.5-.5v1z" fill="#f8fcff"/>
<path d="M53.1 107.4l1.5-.5v1z" fill="none" stroke="#000" stroke-width=".13"/>
<path d="M54.8 106.9l1.6 .5-1.6 .5z" fill="#f8fcff"/>
<path d="M54.8 106.9l1.6 .5-1.6 .5z" fill="none" stroke="#000" stroke-width=".13"/>
<path d="M53.1 109.9h7.6" fill="none" stroke="#000" stroke-width=".25"/>
<path d="M53.1 109.9l1.5-.5v1z" fill="#f8fcff"/>
<path d="M53.1 109.9l1.5-.5v1z" fill="none" stroke="#000" stroke-width=".13"/>
<path d="M54.8 109.4l1.6 .5-1.6 .5z" fill="#f8fcff"/>
<path d="M54.8 109.4l1.6 .5-1.6 .5z" fill="none" stroke="#000" stroke-width=".13"/>
<path d="M53.1 112.5h7.6" fill="none" stroke="#000" stroke-width=".25"/>
<path d="M53.1 112.5l1.5-.5v1z" fill="#f8fcff"/>
<path d="M53.1 112.5l1.5-.5v1z" fill="none" stroke="#000" stroke-width=".13"/>
<path d="M54.8 112l1.6 .5-1.6 .5z" fill="#f8fcff"/>
<path d="M54.8 112l1.6 .5-1.6 .5z" fill="none" stroke="#000" stroke-width=".13"/>
<path d="M53.1 115h7.6" fill="none" stroke="#000" stroke-width=".25"/>
<path d="M53.1 115l1.5-.5v1z" fill="#f8fcff"/>
<path d="M53.1 115l1.5-.5v1z" fill="none" stroke="#000" stroke-width=".13"/>
<path d="M54.8 114.5l1.6 .5-1.6 .5z" fill="#f8fcff"/>
<path d="M54.8 114.5l1.6 .5-1.6 .5z" fill="none" stroke="#000" stroke-width=".13"/>
<path d="M53.1 117.5h7.6" fill="none" stroke="#000" stroke-width=".25"/>
<path d="M53.1 117.5l1.5-.5v1.1z" fill="#f8fcff"/>
<path d="M53.1 117.5l1.5-.5v1.1z" fill="none" stroke="#000" stroke-width=".13"/>
<path d="M54.8 117l1.6 .5-1.6 .6z" fill="#f8fcff"/>
<path d="M54.8 117l1.6 .5-1.6 .6z" fill="none" stroke="#000" stroke-width=".13"/>
<path d="M53.1 120.1h7.6" fill="none" stroke="#000" stroke-width=".25"/>
<path d="M53.1 120.1l1.5-.5v1z" fill="#f8fcff"/>
<path d="M53.1 120.1l1.5-.5v1z" fill="none" stroke="#000" stroke-width=".13"/>
<path d="M54.8 119.6l1.6 .5-1.6 .5z" fill="#f8fcff"/>
<path d="M54.8 119.6l1.6 .5-1.6 .5z" fill="none" stroke="#000" stroke-width=".13"/>
<path d="M53.1 122.6h7.6" fill="none" stroke="#000" stroke-width=".25"/>
<path d="M53.1 122.6l1.5-.5v1z" fill="#f8fcff"/>
<path d="M53.1 122.6l1.5-.5v1z" fill="none" stroke="#000" stroke-width=".13"/>
<path d="M54.8 122.1l1.6 .5-1.6 .5z" fill="#f8fcff"/>
<path d="M54.8 122.1l1.6 .5-1.6 .5z" fill="none" stroke="#000" stroke-width=".13"/>
<path d="M53.1 125.2h7.6" fill="none" stroke="#000" stroke-width=".25"/>
<path d="M53.1 125.2l1.5-.5v1z" fill="#f8fcff"/>
<path d="M53.1 125.2l1.5-.5v1z" fill="none" stroke="#000" stroke-width=".13"/>
<path d="M54.8 124.7l1.6 .5-1.6 .5z" fill="#f8fcff"/>
<path d="M54.8 124.7l1.6 .5-1.6 .5z" fill="none" stroke="#000" stroke-width=".13"/>
<path d="M53.1 127.7h7.6" fill="none" stroke="#000" stroke-width=".25"/>
<path d="M53.1 127.7l1.5-.5v1z" fill="#f8fcff"/>
<path d="M53.1 127.7l1.5-.5v1z" fill="none" stroke="#000" stroke-width=".13"/>
<path d="M54.8 127.2l1.6 .5-1.6 .5z" fill="#f8fcff"/>
<path d="M54.8 127.2l1.6 .5-1.6 .5z" fill="none" stroke="#000" stroke-width=".13"/>
<path d="M53.1 130.2h7.6" fill="none" stroke="#000" stroke-width=".25"/>
<path d="M53.1 130.2l1.5-.5v1.1z" fill="#f8fcff"/>
<path d="M53.1 130.2l1.5-.5v1.1z" fill="none" stroke="#000" stroke-width=".13"/>
<path d="M54.8 129.7l1.6 .5-1.6 .6z" fill="#f8fcff"/>
<path d="M54.8 129.7l1.6 .5-1.6 .6z" fill="none" stroke="#000" stroke-width=".13"/>
<path d="M53.1 132.8h7.6" fill="none" stroke="#000" stroke-width=".25"/>
<path d="M53.1 132.8l1.5-.5v1z" fill="#f8fcff"/>
<path d="M53.1 132.8l1.5-.5v1z" fill="none" stroke="#000" stroke-width=".13"/>
<path d="M54.8 132.3l1.6 .5-1.6 .5z" fill="#f8fcff"/>
<path d="M54.8 132.3l1.6 .5-1.6 .5z" fill="none" stroke="#000" stroke-width=".13"/>
<path d="M53.1 135.3h7.6" fill="none" stroke="#000" stroke-width=".25"/>
<path d="M53.1 135.3l1.5-.5v1z" fill="#f8fcff"/>
<path d="M53.1 135.3l1.5-.5v1z" fill="none" stroke="#000" stroke-width=".13"/>
<path d="M54.8 134.8l1.6 .5-1.6 .5z" fill="#f8fcff"/>
<path d="M54.8 134.8l1.6 .5-1.6 .5z" fill="none" stroke="#000" stroke-width=".13"/>
<path d="M53.1 137.9h7.6" fill="none" stroke="#000" stroke-width=".25"/>
<path d="M53.1 137.9l1.5-.5v1z" fill="#f8fcff"/>
<path d="M53.1 137.9l1.5-.5v1z" fill="none" stroke="#000" stroke-width=".13"/>
<path d="M54.8 137.4l1.6 .5-1.6 .5z" fill="#f8fcff"/>
<path d="M54.8 137.4l1.6 .5-1.6 .5z" fill="none" stroke="#000" stroke-width=".13"/>
<path d="M53.1 140.4h7.6" fill="none" stroke="#000" stroke-width=".25"/>
<path d="M53.1 140.4l1.5-.5v1z" fill="#f8fcff"/>
<path d="M53.1 140.4l1.5-.5v1z" fill="none" stroke="#000" stroke-width=".13"/>
<path d="M54.8 139.9l1.6 .5-1.6 .5z" fill="#f8fcff"/>
<path d="M54.8 139.9l1.6 .5-1.6 .5z" fill="none" stroke="#000" stroke-width=".13"/>
<path d="M53.1 142.9h7.6" fill="none" stroke="#000" stroke-width=".25"/>
<path d="M53.1 142.9l1.5-.5v1z" fill="#f8fcff"/>
<path d="M53.1 142.9l1.5-.5v1z" fill="none" stroke="#000" stroke-width=".13"/>
<path d="M54.8 142.4l1.6 .5-1.6 .5z" fill="#f8fcff"/>
<path d="M54.8 142.4l1.6 .5-1.6 .5z" fill="none" stroke="#000" stroke-width=".13"/>
<path d="M53.1 145.5h7.6" fill="none" stroke="#000" stroke-width=".25"/>
<path d="M53.1 145.5l1.5-.5v1z" fill="#f8fcff"/>
<path d="M53.1 145.5l1.5-.5v1z" fill="none" stroke="#000" stroke-width=".13"/>
<path d="M54.8 145l1.6 .5-1.6 .5z" fill="#f8fcff"/>
<path d="M54.8 145l1.6 .5-1.6 .5z" fill="none" stroke="#000" stroke-width=".13"/>
<path d="M81 33.7h2M89.2 33.7h2" fill="none" stroke="#000" stroke-width=".25"/>
<path d="M83.1 32.8h6v2h-6z" fill="none" stroke="#00f" stroke-width=".25"/>
<path d="M91.2 33.7h2.5M93.7 32.5v2.5" fill="none" stroke="#800000" stroke-width=".25"/>
<path d="M111.5 18.5h35.6v129.5h-35.6z" fill-rule="evenodd" fill="#ffffb0"/>
<path d="M111.5 18.5h35.6v129.5h-35.6z" fill="none" stroke="#800000" stroke-width=".13"/>
<path d="M147.1 21h7.6" fill="none" stroke="#000" stroke-width=".25"/>
<path d="M147.1 21l1.5-.5v1z" fill="#f8fcff"/>
<path d="M147.1 21l1.5-.5v1z" fill="none" stroke="#000" stroke-width=".13"/>
<path d="M148.9 20.5l1.5 .5-1.5 .5z" fill="#f8fcff"/>
<path d="M148.9 20.5l1.5 .5-1.5 .5z" fill="none" stroke="#000" stroke-width=".13"/>
<path d="M147.1 23.6h7.6" fill="none" stroke="#000" stroke-width=".25"/>
<path d="M147.1 23.6l1.5-.5v1z" fill="#f8fcff"/>
<path d="M147.1 23.6l1.5-.5v1z" fill="none" stroke="#000" stroke-width=".13"/>
<path d="M148.9 23.1l1.5 .5-1.5 .5z" fill="#f8fcff"/>
<path d="M148.9 23.1l1.5 .5-1.5 .5z" fill="none" stroke="#000" stroke-width=".13"/>
<path d="M147.1 26.1h7.6" fill="none" stroke="#000" stroke-width=".25"/>
<path d="M147.1 26.1l1.5-.5v1z" fill="#f8fcff"/>
<path d="M147.1 26.1l1.5-.5v1z" fill="none" stroke="#000" stroke-width=".13"/>
<path d="M148.9 25.6l1.5 .5-1.5 .5z" fill="#f8fcff"/>
<path d="M148.9 25.6l1.5 .5-1.5 .5z" fill="none" stroke="#000" stroke-width=".13"/>
<path d="M147.1 28.7h7.6" fill="none" stroke="#000" stroke-width=".25"/>
<path d="M147.1 28.7l1.5-.5v1z" fill="#f8fcff"/>
<path d="M147.1 28.7l1.5-.5v1z" fill="none" stroke="#000" stroke-width=".13"/>
<path d="M148.9 28.2l1.5 .5-1.5 .5z" fill="#f8fcff"/>
<path d="M148.9 28.2l1.5 .5-1.5 .5z" fill="none" stroke="#000" stroke-width=".13"/>
<path d="M147.1 31.2h7.6" fill="none" stroke="#000" stroke-width=".25"/>
<path d="M147.1 31.2l1.5-.5v1z" fill="#f8fcff"/>
<path d="M147.1 31.2l1.5-.5v1z" fill="none" stroke="#000" stroke-width=".13"/>
<path d="M148.9 30.7l1.5 .5-1.5 .5z" fill="#f8fcff"/>
<path d="M148.9 30.7l1.5 .5-1.5 .5z" fill="none" stroke="#000" stroke-width=".13"/>
<path d="M147.1 33.7h7.6" fill="none" stroke="#000" stroke-width=".25"/>
<path d="M147.1 33.7l1.5-.5v1z" fill="#f8fcff"/>
<path d="M147.1 33.7l1.5-.5v1z" fill="none" stroke="#000" stroke-width=".13"/>
<path d="M148.9 33.2l1.5 .5-1.5 .5z" fill="#f8fcff"/>
<path d="M148.9 33.2l1.5 .5-1.5 .5z" fill="none" stroke="#000" stroke-width=".13"/>
<path d="M147.1 36.3h7.6" fill="none" stroke="#000" stroke-width=".25"/>
<path d="M147.1 36.3l1.5-.5v1z" fill="#f8fcff"/>
<path d="M147.1 36.3l1.5-.5v1z" fill="none" stroke="#000" stroke-width=".13"/>
<path d="M148.9 35.8l1.5 .5-1.5 .5z" fill="#f8fcff"/>
<path d="M148.9 35.8l1.5 .5-1.5 .5z" fill="none" stroke="#000" stroke-width=".13"/>
<path d="M147.1 38.8h7.6" fill="none" stroke="#000" stroke-width=".25"/>
<path d="M147.1 38.8l1.5-.5v1z" fill="#f8fcff"/>
<path d="M147.1 38.8l1.5-.5v1z" fill="none" stroke="#000" stroke-width=".13"/>
<path d="M148.9 38.3l1.5 .5-1.5 .5z" fill="#f8fcff"/>
<path d="M148.9 38.3l1.5 .5-1.5 .5z" fill="none" stroke="#000" stroke-width=".13"/>
<path d="M147.1 41.4h7.6" fill="none" stroke="#000" stroke-width=".25"/>
<path d="M147.1 41.4l1.5-.5v1z" fill="#f8fcff"/>
<path d="M147.1 41.4l1.5-.5v1z" fill="none" stroke="#000" stroke-width=".13"/>
<path d="M148.9 40.9l1.5 .5-1.5 .5z" fill="#f8fcff"/>
<path d="M148.9 40.9l1.5 .5-1.5 .5z" fill="none" stroke="#000" stroke-width=".13"/>
<path d="M147.1 43.9h7.6" fill="none" stroke="#000" stroke-width=".25"/>
<path d="M147.1 43.9l1.5-.5v1z" fill="#f8fcff"/>
<path d="M147.1 43.9l1.5-.5v1z" fill="none" stroke="#000" stroke-width=".13"/>
<path d="M148.9 43.4l1.5 .5-1.5 .5z" fill="#f8fcff"/>
<path d="M148.9 43.4l1.5 .5-1.5 .5z" fill="none" stroke="#000" stroke-width=".13"/>
<path d="M147.1 46.4h7.6" fill="none" stroke="#000" stroke-width=".25"/>
<path d="M147.1 46.4l1.5-.5v1z" fill="#f8fcff"/>
<path d="M147.1 46.4l1.5-.5v1z" fill="none" stroke="#000" stroke-width=".13"/>
<path d="M148.9 45.9l1.5 .5-1.5 .5z" fill="#f8fcff"/>
<path d="M148.9 45.9l1.5 .5-1.5 .5z" fill="none" stroke="#000" stroke-width=".13"/>
<path d="M147.1 49h7.6" fill="none" stroke="#000" stroke-width=".25"/>
<path d="M147.1 49l1.5-.5v1z" fill="#f8fcff"/>
<path d="M147.1 49l1.5-.5v1z" fill="none" stroke="#000" stroke-width=".13"/>
<path d="M148.9 48.5l1.5 .5-1.5 .5z" fill="#f8fcff"/>
<path d="M148.9 48.5l1.5 .5-1.5 .5z" fill="none" stroke="#000" stroke-width=".13"/>
<path d="M147.1 51.5h7.6" fill="none" stroke="#000" stroke-width=".25"/>
<path d="M147.1 51.5l1.5-.5v1z" fill="#f8fcff"/>
<path d="M147.1 51.5l1.5-.5v1z" fill="none" stroke="#000" stroke-width=".13"/>
<path d="M148.9 51l1.5 .5-1.5 .5z" fill="#f8fcff"/>
<path d="M148.9 51l1.5 .5-1.5 .5z" fill="none" stroke="#000" stroke-width=".13"/>
<path d="M147.1 54.1h7.6" fill="none" stroke="#000" stroke-width=".25"/>
<path d="M147.1 54.1l1.5-.6v1.1z" fill="#f8fcff"/>
<path d="M147.1 54.1l1.5-.6v1.1z" fill="none" stroke="#000" stroke-width=".13"/>
<path d="M148.9 53.5l1.5 .6-1.5 .5z" fill="#f8fcff"/>
<path d="M148.9 53.5l1.5 .6-1.5 .5z" fill="none" stroke="#000" stroke-width=".13"/>
<path d="M147.1 56.6h7.6" fill="none" stroke="#000" stroke-width=".25"/>
<path d="M147.1 56.6l1.5-.5v1z" fill="#f8fcff"/>
<path d="M147.1 56.6l1.5-.5v1z" fill="none" stroke="#000" stroke-width=".13"/>
<path d="M148.9 56.1l1.5 .5-1.5 .5z" fill="#f8fcff"/>
<path d="M148.9 56.1l1.5 .5-1.5 .5z" fill="none" stroke="#000" stroke-width=".13"/>
<path d="M147.1 59.1h7.6" fill="none" stroke="#000" stroke-width=".25"/>
<path d="M147.1 59.1l1.5-.5v1z" fill="#f8fcff"/>
<path d="M147.1 59.1l1.5-.5v1z" fill="none" stroke="#000" stroke-width=".13"/>
<path d="M148.9 58.6l1.5 .5-1.5 .5z" fill="#f8fcff"/>
<path d="M148.9 58.6l1.5 .5-1.5 .5z" fill="none" stroke="#000" stroke-width=".13"/>
<path d="M147.1 61.7h7.6" fill="none" stroke="#000" stroke-width=".25"/>
<path d="M147.1 61.7l1.5-.5v1z" fill="#f8fcff"/>
<path d="M147.1 61.7l1.5-.5v1z" fill="none" stroke="#000" stroke-width=".13"/>
<path d="M148.9 61.2l1.5 .5-1.5 .5z" fill="#f8fcff"/>
<path d="M148.9 61.2l1.5 .5-1.5 .5z" fill="none" stroke="#000" stroke-width=".13"/>
<path d="M147.1 64.2h7.6" fill="none" stroke="#000" stroke-width=".25"/>
<path d="M147.1 64.2l1.5-.5v1z" fill="#f8fcff"/>
<path d="M147.1 64.2l1.5-.5v1z" fill="none" stroke="#000" stroke-width=".13"/>
<path d="M148.9 63.7l1.5 .5-1.5 .5z" fill="#f8fcff"/>
<path d="M148.9 63.7l1.5 .5-1.5 .5z" fill="none" stroke="#000" stroke-width=".13"/>
<path d="M147.1 66.8h7.6" fill="none" stroke="#000" stroke-width=".25"/>
<path d="M147.1 66.8l1.5-.6v1.1z" fill="#f8fcff"/>
<path d="M147.1 66.8l1.5-.6v1.1z" fill="none" stroke="#000" stroke-width=".13"/>
<path d="M148.9 66.2l1.5 .6-1.5 .5z" fill="#f8fcff"/>
<path d="M148.9 66.2l1.5 .6-1.5 .5z" fill="none" stroke="#000" stroke-width=".13"/>
<path d="M147.1 69.3h7.6" fill="none" stroke="#000" stroke-width=".25"/>
<path d="M147.1 69.3l1.5-.5v1z" fill="#f8fcff"/>
<path d="M147.1 69.3l1.5-.5v1z" fill="none" stroke="#000" stroke-width=".13"/>
<path d="M148.9 68.8l1.5 .5-1.5 .5z" fill="#f8fcff"/>
<path d="M148.9 68.8l1.5 .5-1.5 .5z" fill="none" stroke="#000" stroke-width=".13"/>
<path d="M147.1 71.8h7.6" fill="none" stroke="#000" stroke-width=".25"/>
<path d="M147.1 71.8l1.5-.5v1z" fill="#f8fcff"/>
<path d="M147.1 71.8l1.5-.5v1z" fill="none" stroke="#000" stroke-width=".13"/>
<path d="M148.9 71.3l1.5 .5-1.5 .5z" fill="#f8fcff"/>
<path d="M148.9 71.3l1.5 .5-1.5 .5z" fill="none" stroke="#000" stroke-width=".13"/>
<path d="M147.1 74.4h7.6" fill="none" stroke="#000" stroke-width=".25"/>
<path d="M147.1 74.4l1.5-.5v1z" fill="#f8fcff"/>
<path d="M147.1 74.4l1.5-.5v1z" fill="none" stroke="#000" stroke-width=".13"/>
<path d="M148.9 73.9l1.5 .5-1.5 .5z" fill="#f8fcff"/>
<path d="M147.1 73.9l-1 .5 1 .5M148.9 73.9l1.5 .5-1.5 .5z" fill="none" stroke="#000" stroke-width=".13"/>
<path d="M147.1 76.9h7.6" fill="none" stroke="#000" stroke-width=".25"/>
<path d="M147.1 76.9l1.5-.5v1z" fill="#f8fcff"/>
<path d="M147.1 76.9l1.5-.5v1z" fill="none" stroke="#000" stroke-width=".13"/>
<path d="M148.9 76.4l1.5 .5-1.5 .5z" fill="#f8fcff"/>
<path d="M147.1 76.4l-1 .5 1 .5M148.9 76.4l1.5 .5-1.5 .5z" fill="none" stroke="#000" stroke-width=".13"/>
<path d="M147.1 79.5h7.6" fill="none" stroke="#000" stroke-width=".25"/>
<path d="M147.1 79.5l1.5-.6v1.1z" fill="#f8fcff"/>
<path d="M147.1 79.5l1.5-.6v1.1z" fill="none" stroke="#000" stroke-width=".13"/>
<path d="M148.9 78.9l1.5 .6-1.5 .5z" fill="#f8fcff"/>
<path d="M147.1 78.9l-1 .6 1 .5M148.9 78.9l1.5 .6-1.5 .5z" fill="none" stroke="#000" stroke-width=".13"/>
<path d="M147.1 82h7.6" fill="none" stroke="#000" stroke-width=".25"/>
<path d="M147.1 82l1.5-.5v1z" fill="#f8fcff"/>
<path d="M147.1 82l1.5-.5v1z" fill="none" stroke="#000" stroke-width=".13"/>
<path d="M148.9 81.5l1.5 .5-1.5 .5z" fill="#f8fcff"/>
<path d="M147.1 81.5l-1 .5 1 .5M148.9 81.5l1.5 .5-1.5 .5z" fill="none" stroke="#000" stroke-width=".13"/>
<path d="M147.1 84.5h7.6" fill="none" stroke="#000" stroke-width=".25"/>
<path d="M147.1 84.5l1.5-.5v1z" fill="#f8fcff"/>
<path d="M147.1 84.5l1.5-.5v1z" fill="none" stroke="#000" stroke-width=".13"/>
<path d="M148.9 84l1.5 .5-1.5 .5z" fill="#f8fcff"/>
<path d="M147.1 84l-1 .5 1 .5M148.9 84l1.5 .5-1.5 .5z" fill="none" stroke="#000" stroke-width=".13"/>
<path d="M147.1 87.1h7.6" fill="none" stroke="#000" stroke-width=".25"/>
<path d="M147.1 87.1l1.5-.5v1z" fill="#f8fcff"/>
<path d="M147.1 87.1l1.5-.5v1z" fill="none" stroke="#000" stroke-width=".13"/>
<path d="M148.9 86.6l1.5 .5-1.5 .5z" fill="#f8fcff"/>
<path d="M147.1 86.6l-1 .5 1 .5M148.9 86.6l1.5 .5-1.5 .5z" fill="none" stroke="#000" stroke-width=".13"/>
<path d="M147.1 89.6h7.6" fill="none" stroke="#000" stroke-width=".25"/>
<path d="M147.1 89.6l1.5-.5v1z" fill="#f8fcff"/>
<path d="M147.1 89.6l1.5-.5v1z" fill="none" stroke="#000" stroke-width=".13"/>
<path d="M148.9 89.1l1.5 .5-1.5 .5z" fill="#f8fcff"/>
<path d="M147.1 89.1l-1 .5 1 .5M148.9 89.1l1.5 .5-1.5 .5z" fill="none" stroke="#000" stroke-width=".13"/>
<path d="M147.1 92.1h7.6" fill="none" stroke="#000" stroke-width=".25"/>
<path d="M147.1 92.1l1.5-.5v1.1z" fill="#f8fcff"/>
<path d="M147.1 92.1l1.5-.5v1.1z" fill="none" stroke="#000" stroke-width=".13"/>
<path d="M148.9 91.6l1.5 .5-1.5 .6z" fill="#f8fcff"/>
<path d="M147.1 91.6l-1 .5 1 .6M148.9 91.6l1.5 .5-1.5 .6z" fill="none" stroke="#000" stroke-width=".13"/>
<path d="M147.1 94.7h7.6" fill="none" stroke="#000" stroke-width=".25"/>
<path d="M147.1 94.7l1.5-.5v1z" fill="#f8fcff"/>
<path d="M147.1 94.7l1.5-.5v1z" fill="none" stroke="#000" stroke-width=".13"/>
<path d="M148.9 94.2l1.5 .5-1.5 .5z" fill="#f8fcff"/>
<path d="M148.9 94.2l1.5 .5-1.5 .5z" fill="none" stroke="#000" stroke-width=".13"/>
<path d="M147.1 97.2h7.6" fill="none" stroke="#000" stroke-width=".25"/>
<path d="M147.1 97.2l1.5-.5v1z" fill="#f8fcff"/>
<path d="M147.1 97.2l1.5-.5v1z" fill="none" stroke="#000" stroke-width=".13"/>
<path d="M148.9 96.7l1.5 .5-1.5 .5z" fill="#f8fcff"/>
<path d="M148.9 96.7l1.5 .5-1.5 .5z" fill="none" stroke="#000" stroke-width=".13"/>
<path d="M147.1 99.8h7.6" fill="none" stroke="#000" stroke-width=".25"/>
<path d="M147.1 99.8l1.5-.5v1z" fill="#f8fcff"/>
<path d="M147.1 99.8l1.5-.5v1z" fill="none" stroke="#000" stroke-width=".13"/>
<path d="M148.9 99.3l1.5 .5-1.5 .5z" fill="#f8fcff"/>
<path d="M148.9 99.3l1.5 .5-1.5 .5z" fill="none" stroke="#000" stroke-width=".13"/>
<path d="M147.1 102.3h7.6" fill="none" stroke="#000" stroke-width=".25"/>
<path d="M147.1 102.3l1.5-.5v1z" fill="#f8fcff"/>
<path d="M147.1 102.3l1.5-.5v1z" fill="none" stroke="#000" stroke-width=".13"/>
<path d="M148.9 101.8l1.5 .5-1.5 .5z" fill="#f8fcff"/>
<path d="M148.9 101.8l1.5 .5-1.5 .5z" fill="none" stroke="#000" stroke-width=".13"/>
<path d="M147.1 104.8h7.6" fill="none" stroke="#000" stroke-width=".25"/>
<path d="M147.1 104.8l1.5-.5v1.1z" fill="#f8fcff"/>
<path d="M147.1 104.8l1.5-.5v1.1z" fill="none" stroke="#000" stroke-width=".13"/>
<path d="M148.9 104.3l1.5 .5-1.5 .6z" fill="#f8fcff"/>
<path d="M148.9 104.3l1.5 .5-1.5 .6z" fill="none" stroke="#000" stroke-width=".13"/>
<path d="M147.1 107.4h7.6" fill="none" stroke="#000" stroke-width=".25"/>
<path d="M147.1 107.4l1.5-.5v1z" fill="#f8fcff"/>
<path d="M147.1 107.4l1.5-.5v1z" fill="none" stroke="#000" stroke-width=".13"/>
<path d="M148.9 106.9l1.5 .5-1.5 .5z" fill="#f8fcff"/>
<path d="M148.9 106.9l1.5 .5-1.5 .5z" fill="none" stroke="#000" stroke-width=".13"/>
<path d="M147.1 109.9h7.6" fill="none" stroke="#000" stroke-width=".25"/>
<path d="M147.1 109.9l1.5-.5v1z" fill="#f8fcff"/>
<path d="M147.1 109.9l1.5-.5v1z" fill="none" stroke="#000" stroke-width=".13"/>
<path d="M148.9 109.4l1.5 .5-1.5 .5z" fill="#f8fcff"/>
<path d="M148.9 109.4l1.5 .5-1.5 .5z" fill="none" stroke="#000" stroke-width=".13"/>
<path d="M147.1 112.5h7.6" fill="none" stroke="#000" stroke-width=".25"/>
<path d="M147.1 112.5l1.5-.5v1z" fill="#f8fcff"/>
<path d="M147.1 112.5l1.5-.5v1z" fill="none" stroke="#000" stroke-width=".13"/>
<path d="M148.9 112l1.5 .5-1.5 .5z" fill="#f8fcff"/>
<path d="M148.9 112l1.5 .5-1.5 .5z" fill="none" stroke="#000" stroke-width=".13"/>
<path d="M147.1 115h7.6" fill="none" stroke="#000" stroke-width=".25"/>
<path d="M147.1 115l1.5-.5v1z" fill="#f8fcff"/>
<path d="M147.1 115l1.5-.5v1z" fill="none" stroke="#000" stroke-width=".13"/>
<path d="M148.9 114.5l1.5 .5-1.5 .5z" fill="#f8fcff"/>
<path d="M148.9 114.5l1.5 .5-1.5 .5z" fill="none" stroke="#000" stroke-width=".13"/>
<path d="M147.1 117.5h7.6" fill="none" stroke="#000" stroke-width=".25"/>
<path d="M147.1 117.5l1.5-.5v1.1z" fill="#f8fcff"/>
<path d="M147.1 117.5l1.5-.5v1.1z" fill="none" stroke="#000" stroke-width=".13"/>
<path d="M148.9 117l1.5 .5-1.5 .6z" fill="#f8fcff"/>
<path d="M148.9 117l1.5 .5-1.5 .6z" fill="none" stroke="#000" stroke-width=".13"/>
<path d="M147.1 120.1h7.6" fill="none" stroke="#000" stroke-width=".25"/>
<path d="M147.1 120.1l1.5-.5v1z" fill="#f8fcff"/>
<path d="M147.1 120.1l1.5-.5v1z" fill="none" stroke="#000" stroke-width=".13"/>
<path d="M148.9 119.6l1.5 .5-1.5 .5z" fill="#f8fcff"/>
<path d="M148.9 119.6l1.5 .5-1.5 .5z" fill="none" stroke="#000" stroke-width=".13"/>
<path d="M147.1 122.6h7.6" fill="none" stroke="#000" stroke-width=".25"/>
<path d="M147.1 122.6l1.5-.5v1z" fill="#f8fcff"/>
<path d="M147.1 122.6l1.5-.5v1z" fill="none" stroke="#000" stroke-width=".13"/>
<path d="M148.9 122.1l1.5 .5-1.5 .5z" fill="#f8fcff"/>
<path d="M148.9 122.1l1.5 .5-1.5 .5z" fill="none" stroke="#000" stroke-width=".13"/>
<path d="M147.1 125.2h7.6" fill="none" stroke="#000" stroke-width=".25"/>
<path d="M147.1 125.2l1.5-.5v1z" fill="#f8fcff"/>
<path d="M147.1 125.2l1.5-.5v1z" fill="none" stroke="#000" stroke-width=".13"/>
<path d="M148.9 124.7l1.5 .5-1.5 .5z" fill="#f8fcff"/>
<path d="M148.9 124.7l1.5 .5-1.5 .5z" fill="none" stroke="#000" stroke-width=".13"/>
<path d="M147.1 127.7h7.6" fill="none" stroke="#000" stroke-width=".25"/>
<path d="M147.1 127.7l1.5-.5v1z" fill="#f8fcff"/>
<path d="M147.1 127.7l1.5-.5v1z" fill="none" stroke="#000" stroke-width=".13"/>
<path d="M148.9 127.2l1.5 .5-1.5 .5z" fill="#f8fcff"/>
<path d="M148.9 127.2l1.5 .5-1.5 .5z" fill="none" stroke="#000" stroke-width=".13"/>
<path d="M147.1 130.2h7.6" fill="none" stroke="#000" stroke-width=".25"/>
<path d="M147.1 130.2l1.5-.5v1.1z" fill="#f8fcff"/>
<path d="M147.1 130.2l1.5-.5v1.1z" fill="none" stroke="#000" stroke-width=".13"/>
<path d="M148.9 129.7l1.5 .5-1.5 .6z" fill="#f8fcff"/>
<path d="M148.9 129.7l1.5 .5-1.5 .6z" fill="none" stroke="#000" stroke-width=".13"/>
<path d="M147.1 132.8h7.6" fill="none" stroke="#000" stroke-width=".25"/>
<path d="M147.1 132.8l1.5-.5v1z" fill="#f8fcff"/>
<path d="M147.1 132.8l1.5-.5v1z" fill="none" stroke="#000" stroke-width=".13"/>
<path d="M148.9 132.3l1.5 .5-1.5 .5z" fill="#f8fcff"/>
<path d="M148.9 132.3l1.5 .5-1.5 .5z" fill="none" stroke="#000" stroke-width=".13"/>
<path d="M147.1 135.3h7.6" fill="none" stroke="#000" stroke-width=".25"/>
<path d="M147.1 135.3l1.5-.5v1z" fill="#f8fcff"/>
<path d="M147.1 135.3l1.5-.5v1z" fill="none" stroke="#000" stroke-width=".13"/>
<path d="M148.9 134.8l1.5 .5-1.5 .5z" fill="#f8fcff"/>
<path d="M148.9 134.8l1.5 .5-1.5 .5z" fill="none" stroke="#000" stroke-width=".13"/>
<path d="M147.1 137.9h7.6" fill="none" stroke="#000" stroke-width=".25"/>
<path d="M147.1 137.9l1.5-.5v1z" fill="#f8fcff"/>
<path d="M147.1 137.9l1.5-.5v1z" fill="none" stroke="#000" stroke-width=".13"/>
<path d="M148.9 137.4l1.5 .5-1.5 .5z" fill="#f8fcff"/>
<path d="M148.9 137.4l1.5 .5-1.5 .5z" fill="none" stroke="#000" stroke-width=".13"/>
<path d="M147.1 140.4h7.6" fill="none" stroke="#000" stroke-width=".25"/>
<path d="M147.1 140.4l1.5-.5v1z" fill="#f8fcff"/>
<path d="M147.1 140.4l1.5-.5v1z" fill="none" stroke="#000" stroke-width=".13"/>
<path d="M148.9 139.9l1.5 .5-1.5 .5z" fill="#f8fcff"/>
<path d="M148.9 139.9l1.5 .5-1.5 .5z" fill="none" stroke="#000" stroke-width=".13"/>
<path d="M147.1 142.9h7.6" fill="none" stroke="#000" stroke-width=".25"/>
<path d="M147.1 142.9l1.5-.5v1z" fill="#f8fcff"/>
<path d="M147.1 142.9l1.5-.5v1z" fill="none" stroke="#000" stroke-width=".13"/>
<path d="M148.9 142.4l1.5 .5-1.5 .5z" fill="#f8fcff"/>
<path d="M148.9 142.4l1.5 .5-1.5 .5z" fill="none" stroke="#000" stroke-width=".13"/>
<path d="M147.1 145.5h7.6" fill="none" stroke="#000" stroke-width=".25"/>
<path d="M147.1 145.5l1.5-.5v1z" fill="#f8fcff"/>
<path d="M147.1 145.5l1.5-.5v1z" fill="none" stroke="#000" stroke-width=".13"/>
<path d="M148.9 145l1.5 .5-1.5 .5z" fill="#f8fcff"/>
<path d="M148.9 145l1.5 .5-1.5 .5z" fill="none" stroke="#000" stroke-width=".13"/>
<path d="M195.4 18.5h30.5v129.5h-30.5z" fill-rule="evenodd" fill="#ffffb0"/>
<path d="M195.4 18.5h30.5v129.5h-30.5z" fill="none" stroke="#800000" stroke-width=".13"/>
<path d="M225.9 21h7.6" fill="none" stroke="#000" stroke-width=".25"/>
<path d="M225.9 21l1.5-.5v1z" fill="#f8fcff"/>
<path d="M225.9 21l1.5-.5v1z" fill="none" stroke="#000" stroke-width=".13"/>
<path d="M227.7 20.5l1.5 .5-1.5 .5z" fill="#f8fcff"/>
<path d="M227.7 20.5l1.5 .5-1.5 .5z" fill="none" stroke="#000" stroke-width=".13"/>
<path d="M225.9 23.6h7.6" fill="none" stroke="#000" stroke-width=".25"/>
<path d="M225.9 23.6l1.5-.5v1z" fill="#f8fcff"/>
<path d="M225.9 23.6l1.5-.5v1z" fill="none" stroke="#000" stroke-width=".13"/>
<path d="M227.7 23.1l1.5 .5-1.5 .5z" fill="#f8fcff"/>
<path d="M227.7 23.1l1.5 .5-1.5 .5z" fill="none" stroke="#000" stroke-width=".13"/>
<path d="M225.9 26.1h7.6" fill="none" stroke="#000" stroke-width=".25"/>
<path d="M225.9 26.1l1.5-.5v1z" fill="#f8fcff"/>
<path d="M225.9 26.1l1.5-.5v1z" fill="none" stroke="#000" stroke-width=".13"/>
<path d="M227.7 25.6l1.5 .5-1.5 .5z" fill="#f8fcff"/>
<path d="M227.7 25.6l1.5 .5-1.5 .5z" fill="none" stroke="#000" stroke-width=".13"/>
<path d="M225.9 28.7h7.6" fill="none" stroke="#000" stroke-width=".25"/>
<path d="M225.9 28.7l1.5-.5v1z" fill="#f8fcff"/>
<path d="M225.9 28.7l1.5-.5v1z" fill="none" stroke="#000" stroke-width=".13"/>
<path d="M227.7 28.2l1.5 .5-1.5 .5z" fill="#f8fcff"/>
<path d="M227.7 28.2l1.5 .5-1.5 .5z" fill="none" stroke="#000" stroke-width=".13"/>
<path d="M225.9 31.2h7.6" fill="none" stroke="#000" stroke-width=".25"/>
<path d="M225.9 31.2l1.5-.5v1z" fill="#f8fcff"/>
<path d="M225.9 31.2l1.5-.5v1z" fill="none" stroke="#000" stroke-width=".13"/>
<path d="M227.7 30.7l1.5 .5-1.5 .5z" fill="#f8fcff"/>
<path d="M227.7 30.7l1.5 .5-1.5 .5z" fill="none" stroke="#000" stroke-width=".13"/>
<path d="M225.9 33.7h7.6" fill="none" stroke="#000" stroke-width=".25"/>
<path d="M225.9 33.7l1.5-.5v1z" fill="#f8fcff"/>
<path d="M225.9 33.7l1.5-.5v1z" fill="none" stroke="#000" stroke-width=".13"/>
<path d="M227.7 33.2l1.5 .5-1.5 .5z" fill="#f8fcff"/>
<path d="M227.7 33.2l1.5 .5-1.5 .5z" fill="none" stroke="#000" stroke-width=".13"/>
<path d="M225.9 36.3h7.6" fill="none" stroke="#000" stroke-width=".25"/>
<path d="M225.9 36.3l1.5-.5v1z" fill="#f8fcff"/>
<path d="M225.9 36.3l1.5-.5v1z" fill="none" stroke="#000" stroke-width=".13"/>
<path d="M227.7 35.8l1.5 .5-1.5 .5z" fill="#f8fcff"/>
<path d="M227.7 35.8l1.5 .5-1.5 .5z" fill="none" stroke="#000" stroke-width=".13"/>
<path d="M225.9 38.8h7.6" fill="none" stroke="#000" stroke-width=".25"/>
<path d="M225.9 38.8l1.5-.5v1z" fill="#f8fcff"/>
<path d="M225.9 38.8l1.5-.5v1z" fill="none" stroke="#000" stroke-width=".13"/>
<path d="M227.7 38.3l1.5 .5-1.5 .5z" fill="#f8fcff"/>
<path d="M227.7 38.3l1.5 .5-1.5 .5z" fill="none" stroke="#000" stroke-width=".13"/>
<path d="M225.9 41.4h7.6" fill="none" stroke="#000" stroke-width=".25"/>
<path d="M225.9 41.4l1.5-.5v1z" fill="#f8fcff"/>
<path d="M225.9 41.4l1.5-.5v1z" fill="none" stroke="#000" stroke-width=".13"/>
<path d="M227.7 40.9l1.5 .5-1.5 .5z" fill="#f8fcff"/>
<path d="M227.7 40.9l1.5 .5-1.5 .5z" fill="none" stroke="#000" stroke-width=".13"/>
<path d="M225.9 43.9h7.6" fill="none" stroke="#000" stroke-width=".25"/>
<path d="M225.9 43.9l1.5-.5v1z" fill="#f8fcff"/>
<path d="M225.9 43.9l1.5-.5v1z" fill="none" stroke="#000" stroke-width=".13"/>
<path d="M227.7 43.4l1.5 .5-1.5 .5z" fill="#f8fcff"/>
<path d="M227.7 43.4l1.5 .5-1.5 .5z" fill="none" stroke="#000" stroke-width=".13"/>
<path d="M225.9 46.4h7.6" fill="none" stroke="#000" stroke-width=".25"/>
<path d="M225.9 46.4l1.5-.5v1z" fill="#f8fcff"/>
<path d="M225.9 46.4l1.5-.5v1z" fill="none" stroke="#000" stroke-width=".13"/>
<path d="M227.7 45.9l1.5 .5-1.5 .5z" fill="#f8fcff"/>
<path d="M227.7 45.9l1.5 .5-1.5 .5z" fill="none" stroke="#000" stroke-width=".13"/>
<path d="M225.9 49h7.6" fill="none" stroke="#000" stroke-width=".25"/>
<path d="M225.9 49l1.5-.5v1z" fill="#f8fcff"/>
<path d="M225.9 49l1.5-.5v1z" fill="none" stroke="#000" stroke-width=".13"/>
<path d="M227.7 48.5l1.5 .5-1.5 .5z" fill="#f8fcff"/>
<path d="M227.7 48.5l1.5 .5-1.5 .5z" fill="none" stroke="#000" stroke-width=".13"/>
<path d="M225.9 51.5h7.6" fill="none" stroke="#000" stroke-width=".25"/>
<path d="M225.9 51.5l1.5-.5v1z" fill="#f8fcff"/>
<path d="M225.9 51.5l1.5-.5v1z" fill="none" stroke="#000" stroke-width=".13"/>
<path d="M227.7 51l1.5 .5-1.5 .5z" fill="#f8fcff"/>
<path d="M227.7 51l1.5 .5-1.5 .5z" fill="none" stroke="#000" stroke-width=".13"/>
<path d="M225.9 54.1h7.6" fill="none" stroke="#000" stroke-width=".25"/>
<path d="M225.9 54.1l1.5-.5v1z" fill="#f8fcff"/>
<path d="M225.9 54.1l1.5-.5v1z" fill="none" stroke="#000" stroke-width=".13"/>
<path d="M227.7 53.6l1.5 .5-1.5 .5z" fill="#f8fcff"/>
<path d="M227.7 53.6l1.5 .5-1.5 .5z" fill="none" stroke="#000" stroke-width=".13"/>
<path d="M225.9 56.6h7.6" fill="none" stroke="#000" stroke-width=".25"/>
<path d="M225.9 56.6l1.5-.5v1z" fill="#f8fcff"/>
<path d="M225.9 56.6l1.5-.5v1z" fill="none" stroke="#000" stroke-width=".13"/>
<path d="M227.7 56.1l1.5 .5-1.5 .5z" fill="#f8fcff"/>
<path d="M227.7 56.1l1.5 .5-1.5 .5z" fill="none" stroke="#000" stroke-width=".13"/>
<path d="M225.9 59.1h7.6" fill="none" stroke="#000" stroke-width=".25"/>
<path d="M225.9 59.1l1.5-.5v1z" fill="#f8fcff"/>
<path d="M225.9 59.1l1.5-.5v1z" fill="none" stroke="#000" stroke-width=".13"/>
<path d="M227.7 58.6l1.5 .5-1.5 .5z" fill="#f8fcff"/>
<path d="M227.7 58.6l1.5 .5-1.5 .5z" fill="none" stroke="#000" stroke-width=".13"/>
<path d="M225.9 61.7h7.6" fill="none" stroke="#000" stroke-width=".25"/>
<path d="M225.9 61.7l1.5-.5v1z" fill="#f8fcff"/>
<path d="M225.9 61.7l1.5-.5v1z" fill="none" stroke="#000" stroke-width=".13"/>
<path d="M227.7 61.2l1.5 .5-1.5 .5z" fill="#f8fcff"/>
<path d="M227.7 61.2l1.5 .5-1.5 .5z" fill="none" stroke="#000" stroke-width=".13"/>
<path d="M225.9 64.2h7.6" fill="none" stroke="#000" stroke-width=".25"/>
<path d="M225.9 64.2l1.5-.5v1z" fill="#f8fcff"/>
<path d="M225.9 64.2l1.5-.5v1z" fill="none" stroke="#000" stroke-width=".13"/>
<path d="M227.7 63.7l1.5 .5-1.5 .5z" fill="#f8fcff"/>
<path d="M227.7 63.7l1.5 .5-1.5 .5z" fill="none" stroke="#000" stroke-width=".13"/>
<path d="M225.9 66.8h7.6" fill="none" stroke="#000" stroke-width=".25"/>
<path d="M225.9 66.8l1.5-.6v1.1z" fill="#f8fcff"/>
<path d="M225.9 66.8l1.5-.6v1.1z" fill="none" stroke="#000" stroke-width=".13"/>
<path d="M227.7 66.2l1.5 .6-1.5 .5z" fill="#f8fcff"/>
<path d="M227.7 66.2l1.5 .6-1.5 .5z" fill="none" stroke="#000" stroke-width=".13"/>
<path d="M225.9 69.3h7.6" fill="none" stroke="#000" stroke-width=".25"/>
<path d="M225.9 69.3l1.5-.5v1z" fill="#f8fcff"/>
<path d="M225.9 69.3l1.5-.5v1z" fill="none" stroke="#000" stroke-width=".13"/>
<path d="M227.7 68.8l1.5 .5-1.5 .5z" fill="#f8fcff"/>
<path d="M227.7 68.8l1.5 .5-1.5 .5z" fill="none" stroke="#000" stroke-width=".13"/>
<path d="M225.9 71.8h7.6" fill="none" stroke="#000" stroke-width=".25"/>
<path d="M225.9 71.8l1.5-.5v1z" fill="#f8fcff"/>
<path d="M225.9 71.8l1.5-.5v1z" fill="none" stroke="#000" stroke-width=".13"/>
<path d="M227.7 71.3l1.5 .5-1.5 .5z" fill="#f8fcff"/>
<path d="M227.7 71.3l1.5 .5-1.5 .5z" fill="none" stroke="#000" stroke-width=".13"/>
<path d="M225.9 74.4h7.6" fill="none" stroke="#000" stroke-width=".25"/>
<path d="M225.9 74.4l1.5-.5v1z" fill="#f8fcff"/>
<path d="M225.9 74.4l1.5-.5v1z" fill="none" stroke="#000" stroke-width=".13"/>
<path d="M227.7 73.9l1.5 .5-1.5 .5z" fill="#f8fcff"/>
<path d="M225.9 73.9l-1 .5 1 .5M227.7 73.9l1.5 .5-1.5 .5z" fill="none" stroke="#000" stroke-width=".13"/>
<path d="M225.9 76.9h7.6" fill="none" stroke="#000" stroke-width=".25"/>
<path d="M225.9 76.9l1.5-.5v1z" fill="#f8fcff"/>
<path d="M225.9 76.9l1.5-.5v1z" fill="none" stroke="#000" stroke-width=".13"/>
<path d="M227.7 76.4l1.5 .5-1.5 .5z" fill="#f8fcff"/>
<path d="M225.9 76.4l-1 .5 1 .5M227.7 76.4l1.5 .5-1.5 .5z" fill="none" stroke="#000" stroke-width=".13"/>
<path d="M225.9 79.5h7.6" fill="none" stroke="#000" stroke-width=".25"/>
<path d="M225.9 79.5l1.5-.6v1.1z" fill="#f8fcff"/>
<path d="M225.9 79.5l1.5-.6v1.1z" fill="none" stroke="#000" stroke-width=".13"/>
<path d="M227.7 78.9l1.5 .6-1.5 .5z" fill="#f8fcff"/>
<path d="M225.9 78.9l-1 .6 1 .5M227.7 78.9l1.5 .6-1.5 .5z" fill="none" stroke="#000" stroke-width=".13"/>
<path d="M225.9 82h7.6" fill="none" stroke="#000" stroke-width=".25"/>
<path d="M225.9 82l1.5-.5v1z" fill="#f8fcff"/>
<path d="M225.9 82l1.5-.5v1z" fill="none" stroke="#000" stroke-width=".13"/>
<path d="M227.7 81.5l1.5 .5-1.5 .5z" fill="#f8fcff"/>
<path d="M225.9 81.5l-1 .5 1 .5M227.7 81.5l1.5 .5-1.5 .5z" fill="none" stroke="#000" stroke-width=".13"/>
<path d="M225.9 84.5h7.6" fill="none" stroke="#000" stroke-width=".25"/>
<path d="M225.9 84.5l1.5-.5v1z" fill="#f8fcff"/>
<path d="M225.9 84.5l1.5-.5v1z" fill="none" stroke="#000" stroke-width=".13"/>
<path d="M227.7 84l1.5 .5-1.5 .5z" fill="#f8fcff"/>
<path d="M225.9 84l-1 .5 1 .5M227.7 84l1.5 .5-1.5 .5z" fill="none" stroke="#000" stroke-width=".13"/>
<path d="M225.9 87.1h7.6" fill="none" stroke="#000" stroke-width=".25"/>
<path d="M225.9 87.1l1.5-.5v1z" fill="#f8fcff"/>
<path d="M225.9 87.1l1.5-.5v1z" fill="none" stroke="#000" stroke-width=".13"/>
<path d="M227.7 86.6l1.5 .5-1.5 .5z" fill="#f8fcff"/>
<path d="M225.9 86.6l-1 .5 1 .5M227.7 86.6l1.5 .5-1.5 .5z" fill="none" stroke="#000" stroke-width=".13"/>
<path d="M225.9 89.6h7.6" fill="none" stroke="#000" stroke-width=".25"/>
<path d="M225.9 89.6l1.5-.5v1z" fill="#f8fcff"/>
<path d="M225.9 89.6l1.5-.5v1z" fill="none" stroke="#000" stroke-width=".13"/>
<path d="M227.7 89.1l1.5 .5-1.5 .5z" fill="#f8fcff"/>
<path d="M225.9 89.1l-1 .5 1 .5M227.7 89.1l1.5 .5-1.5 .5z" fill="none" stroke="#000" stroke-width=".13"/>
<path d="M225.9 92.2h7.6" fill="none" stroke="#000" stroke-width=".25"/>
<path d="M225.9 92.2l1.5-.6v1.1z" fill="#f8fcff"/>
<path d="M225.9 92.2l1.5-.6v1.1z" fill="none" stroke="#000" stroke-width=".13"/>
<path d="M227.7 91.6l1.5 .6-1.5 .5z" fill="#f8fcff"/>
<path d="M225.9 91.6l-1 .6 1 .5M227.7 91.6l1.5 .6-1.5 .5z" fill="none" stroke="#000" stroke-width=".13"/>
<path d="M225.9 94.7h7.6" fill="none" stroke="#000" stroke-width=".25"/>
<path d="M225.9 94.7l1.5-.5v1z" fill="#f8fcff"/>
<path d="M225.9 94.7l1.5-.5v1z" fill="none" stroke="#000" stroke-width=".13"/>
<path d="M227.7 94.2l1.5 .5-1.5 .5z" fill="#f8fcff"/>
<path d="M227.7 94.2l1.5 .5-1.5 .5z" fill="none" stroke="#000" stroke-width=".13"/>
<path d="M225.9 97.2h7.6" fill="none" stroke="#000" stroke-width=".25"/>
<path d="M225.9 97.2l1.5-.5v1z" fill="#f8fcff"/>
<path d="M225.9 97.2l1.5-.5v1z" fill="none" stroke="#000" stroke-width=".13"/>
<path d="M227.7 96.7l1.5 .5-1.5 .5z" fill="#f8fcff"/>
<path d="M227.7 96.7l1.5 .5-1.5 .5z" fill="none" stroke="#000" stroke-width=".13"/>
<path d="M225.9 99.8h7.6" fill="none" stroke="#000" stroke-width=".25"/>
<path d="M225.9 99.8l1.5-.5v1z" fill="#f8fcff"/>
<path d="M225.9 99.8l1.5-.5v1z" fill="none" stroke="#000" stroke-width=".13"/>
<path d="M227.7 99.3l1.5 .5-1.5 .5z" fill="#f8fcff"/>
<path d="M227.7 99.3l1.5 .5-1.5 .5z" fill="none" stroke="#000" stroke-width=".13"/>
<path d="M225.9 102.3h7.6" fill="none" stroke="#000" stroke-width=".25"/>
<path d="M225.9 102.3l1.5-.5v1z" fill="#f8fcff"/>
<path d="M225.9 102.3l1.5-.5v1z" fill="none" stroke="#000" stroke-width=".13"/>
<path d="M227.7 101.8l1.5 .5-1.5 .5z" fill="#f8fcff"/>
<path d="M227.7 101.8l1.5 .5-1.5 .5z" fill="none" stroke="#000" stroke-width=".13"/>
<path d="M225.9 104.9h7.6" fill="none" stroke="#000" stroke-width=".25"/>
<path d="M225.9 104.9l1.5-.6v1.1z" fill="#f8fcff"/>
<path d="M225.9 104.9l1.5-.6v1.1z" fill="none" stroke="#000" stroke-width=".13"/>
<path d="M227.7 104.3l1.5 .6-1.5 .5z" fill="#f8fcff"/>
<path d="M227.7 104.3l1.5 .6-1.5 .5z" fill="none" stroke="#000" stroke-width=".13"/>
<path d="M225.9 107.4h7.6" fill="none" stroke="#000" stroke-width=".25"/>
<path d="M225.9 107.4l1.5-.5v1z" fill="#f8fcff"/>
<path d="M225.9 107.4l1.5-.5v1z" fill="none" stroke="#000" stroke-width=".13"/>
<path d="M227.7 106.9l1.5 .5-1.5 .5z" fill="#f8fcff"/>
<path d="M227.7 106.9l1.5 .5-1.5 .5z" fill="none" stroke="#000" stroke-width=".13"/>
<path d="M225.9 109.9h7.6" fill="none" stroke="#000" stroke-width=".25"/>
<path d="M225.9 109.9l1.5-.5v1z" fill="#f8fcff"/>
<path d="M225.9 109.9l1.5-.5v1z" fill="none" stroke="#000" stroke-width=".13"/>
<path d="M227.7 109.4l1.5 .5-1.5 .5z" fill="#f8fcff"/>
<path d="M227.7 109.4l1.5 .5-1.5 .5z" fill="none" stroke="#000" stroke-width=".13"/>
<path d="M225.9 112.5h7.6" fill="none" stroke="#000" stroke-width=".25"/>
<path d="M225.9 112.5l1.5-.5v1z" fill="#f8fcff"/>
<path d="M225.9 112.5l1.5-.5v1z" fill="none" stroke="#000" stroke-width=".13"/>
<path d="M227.7 112l1.5 .5-1.5 .5z" fill="#f8fcff"/>
<path d="M227.7 112l1.5 .5-1.5 .5z" fill="none" stroke="#000" stroke-width=".13"/>
<path d="M225.9 115h7.6" fill="none" stroke="#000" stroke-width=".25"/>
<path d="M225.9 115l1.5-.5v1z" fill="#f8fcff"/>
<path d="M225.9 115l1.5-.5v1z" fill="none" stroke="#000" stroke-width=".13"/>
<path d="M227.7 114.5l1.5 .5-1.5 .5z" fill="#f8fcff"/>
<path d="M227.7 114.5l1.5 .5-1.5 .5z" fill="none" stroke="#000" stroke-width=".13"/>
<path d="M225.9 117.5h7.6" fill="none" stroke="#000" stroke-width=".25"/>
<path d="M225.9 117.5l1.5-.5v1.1z" fill="#f8fcff"/>
<path d="M225.9 117.5l1.5-.5v1.1z" fill="none" stroke="#000" stroke-width=".13"/>
<path d="M227.7 117l1.5 .5-1.5 .6z" fill="#f8fcff"/>
<path d="M227.7 117l1.5 .5-1.5 .6z" fill="none" stroke="#000" stroke-width=".13"/>
<path d="M225.9 120.1h7.6" fill="none" stroke="#000" stroke-width=".25"/>
<path d="M225.9 120.1l1.5-.5v1z" fill="#f8fcff"/>
<path d="M225.9 120.1l1.5-.5v1z" fill="none" stroke="#000" stroke-width=".13"/>
<path d="M227.7 119.6l1.5 .5-1.5 .5z" fill="#f8fcff"/>
<path d="M227.7 119.6l1.5 .5-1.5 .5z" fill="none" stroke="#000" stroke-width=".13"/>
<path d="M225.9 122.6h7.6" fill="none" stroke="#000" stroke-width=".25"/>
<path d="M225.9 122.6l1.5-.5v1z" fill="#f8fcff"/>
<path d="M225.9 122.6l1.5-.5v1z" fill="none" stroke="#000" stroke-width=".13"/>
<path d="M227.7 122.1l1.5 .5-1.5 .5z" fill="#f8fcff"/>
<path d="M227.7 122.1l1.5 .5-1.5 .5z" fill="none" stroke="#000" stroke-width=".13"/>
<path d="M225.9 125.2h7.6" fill="none" stroke="#000" stroke-width=".25"/>
<path d="M225.9 125.2l1.5-.5v1z" fill="#f8fcff"/>
<path d="M225.9 125.2l1.5-.5v1z" fill="none" stroke="#000" stroke-width=".13"/>
<path d="M227.7 124.7l1.5 .5-1.5 .5z" fill="#f8fcff"/>
<path d="M227.7 124.7l1.5 .5-1.5 .5z" fill="none" stroke="#000" stroke-width=".13"/>
<path d="M225.9 127.7h7.6" fill="none" stroke="#000" stroke-width=".25"/>
<path d="M225.9 127.7l1.5-.5v1z" fill="#f8fcff"/>
<path d="M225.9 127.7l1.5-.5v1z" fill="none" stroke="#000" stroke-width=".13"/>
<path d="M227.7 127.2l1.5 .5-1.5 .5z" fill="#f8fcff"/>
<path d="M227.7 127.2l1.5 .5-1.5 .5z" fill="none" stroke="#000" stroke-width=".13"/>
<path d="M225.9 130.2h7.6" fill="none" stroke="#000" stroke-width=".25"/>
<path d="M225.9 130.2l1.5-.5v1.1z" fill="#f8fcff"/>
<path d="M225.9 130.2l1.5-.5v1.1z" fill="none" stroke="#000" stroke-width=".13"/>
<path d="M227.7 129.7l1.5 .5-1.5 .6z" fill="#f8fcff"/>
<path d="M227.7 129.7l1.5 .5-1.5 .6z" fill="none" stroke="#000" stroke-width=".13"/>
<path d="M225.9 132.8h7.6" fill="none" stroke="#000" stroke-width=".25"/>
<path d="M225.9 132.8l1.5-.5v1z" fill="#f8fcff"/>
<path d="M225.9 132.8l1.5-.5v1z" fill="none" stroke="#000" stroke-width=".13"/>
<path d="M227.7 132.3l1.5 .5-1.5 .5z" fill="#f8fcff"/>
<path d="M227.7 132.3l1.5 .5-1.5 .5z" fill="none" stroke="#000" stroke-width=".13"/>
<path d="M225.9 135.3h7.6" fill="none" stroke="#000" stroke-width=".25"/>
<path d="M225.9 135.3l1.5-.5v1z" fill="#f8fcff"/>
<path d="M225.9 135.3l1.5-.5v1z" fill="none" stroke="#000" stroke-width=".13"/>
<path d="M227.7 134.8l1.5 .5-1.5 .5z" fill="#f8fcff"/>
<path d="M227.7 134.8l1.5 .5-1.5 .5z" fill="none" stroke="#000" stroke-width=".13"/>
<path d="M225.9 137.9h7.6" fill="none" stroke="#000" stroke-width=".25"/>
<path d="M225.9 137.9l1.5-.5v1z" fill="#f8fcff"/>
<path d="M225.9 137.9l1.5-.5v1z" fill="none" stroke="#000" stroke-width=".13"/>
<path d="M227.7 137.4l1.5 .5-1.5 .5z" fill="#f8fcff"/>
<path d="M227.7 137.4l1.5 .5-1.5 .5z" fill="none" stroke="#000" stroke-width=".13"/>
<path d="M225.9 140.4h7.6" fill="none" stroke="#000" stroke-width=".25"/>
<path d="M225.9 140.4l1.5-.5v1z" fill="#f8fcff"/>
<path d="M225.9 140.4l1.5-.5v1z" fill="none" stroke="#000" stroke-width=".13"/>
<path d="M227.7 139.9l1.5 .5-1.5 .5z" fill="#f8fcff"/>
<path d="M227.7 139.9l1.5 .5-1.5 .5z" fill="none" stroke="#000" stroke-width=".13"/>
<path d="M225.9 142.9h7.6" fill="none" stroke="#000" stroke-width=".25"/>
<path d="M225.9 142.9l1.5-.5v1.1z" fill="#f8fcff"/>
<path d="M225.9 142.9l1.5-.5v1.1z" fill="none" stroke="#000" stroke-width=".13"/>
<path d="M227.7 142.4l1.5 .5-1.5 .6z" fill="#f8fcff"/>
<path d="M227.7 142.4l1.5 .5-1.5 .6z" fill="none" stroke="#000" stroke-width=".13"/>
<path d="M225.9 145.5h7.6" fill="none" stroke="#000" stroke-width=".25"/>
<path d="M225.9 145.5l1.5-.5v1z" fill="#f8fcff"/>
<path d="M225.9 145.5l1.5-.5v1z" fill="none" stroke="#000" stroke-width=".13"/>
<path d="M227.7 145l1.5 .5-1.5 .5z" fill="#f8fcff"/>
<path d="M227.7 145l1.5 .5-1.5 .5z" fill="none" stroke="#000" stroke-width=".13"/>
<path d="M75.9 84.5l1.3-1.2h16.5v2.5h-16.5z" fill-rule="evenodd" fill="#ffff80"/>
<path d="M75.9 84.5l1.3-1.2h16.5v2.5h-16.5z" fill="none" stroke="#800000" stroke-width=".13"/>
<path d="M75.9 87.1l1.3-1.3h16.5v2.5h-16.5z" fill-rule="evenodd" fill="#ffff80"/>
<path d="M75.9 87.1l1.3-1.3h16.5v2.5h-16.5z" fill="none" stroke="#800000" stroke-width=".13"/>
<path d="M75.9 94.7l1.3-1.3h16.5v2.6h-16.5z" fill-rule="evenodd" fill="#ffff80"/>
<path d="M75.9 94.7l1.3-1.3h16.5v2.6h-16.5z" fill="none" stroke="#800000" stroke-width=".13"/>
<path d="M75.9 97.2l1.3-1.2h16.5v2.5h-16.5z" fill-rule="evenodd" fill="#ffff80"/>
<path d="M75.9 97.2l1.3-1.2h16.5v2.5h-16.5z" fill="none" stroke="#800000" stroke-width=".13"/>
<path d="M75.9 99.8l1.3-1.3h16.5v2.5h-16.5z" fill-rule="evenodd" fill="#ffff80"/>
<path d="M75.9 99.8l1.3-1.3h16.5v2.5h-16.5z" fill="none" stroke="#800000" stroke-width=".13"/>
<path d="M75.9 102.3l1.3-1.3h16.5v2.6h-16.5z" fill-rule="evenodd" fill="#ffff80"/>
<path d="M75.9 102.3l1.3-1.3h16.5v2.6h-16.5z" fill="none" stroke="#800000" stroke-width=".13"/>
<path d="M75.9 104.8l1.3-1.2h16.5v2.5h-16.5z" fill-rule="evenodd" fill="#ffff80"/>
<path d="M75.9 104.8l1.3-1.2h16.5v2.5h-16.5z" fill="none" stroke="#800000" stroke-width=".13"/>
<path d="M75.9 107.4l1.3-1.3h16.5v2.6h-16.5z" fill-rule="evenodd" fill="#ffff80"/>
<path d="M75.9 107.4l1.3-1.3h16.5v2.6h-16.5z" fill="none" stroke="#800000" stroke-width=".13"/>
<path d="M75.9 109.9l1.3-1.2h16.5v2.5h-16.5z" fill-rule="evenodd" fill="#ffff80"/>
<path d="M75.9 109.9l1.3-1.2h16.5v2.5h-16.5z" fill="none" stroke="#800000" stroke-width=".13"/>
<path d="M75.9 112.5l1.3-1.3h16.5v2.5h-16.5z" fill-rule="evenodd" fill="#ffff80"/>
<path d="M75.9 112.5l1.3-1.3h16.5v2.5h-16.5z" fill="none" stroke="#800000" stroke-width=".13"/>
<path d="M75.9 120.1l1.3-1.3h16.5v2.6h-16.5z" fill-rule="evenodd" fill="#ffff80"/>
<path d="M75.9 120.1l1.3-1.3h16.5v2.6h-16.5z" fill="none" stroke="#800000" stroke-width=".13"/>
<path d="M75.9 122.6l1.3-1.2h16.5v2.5h-16.5z" fill-rule="evenodd" fill="#ffff80"/>
<path d="M75.9 122.6l1.3-1.2h16.5v2.5h-16.5z" fill="none" stroke="#800000" stroke-width=".13"/>
<path d="M75.9 125.2l1.3-1.3h16.5v2.5h-16.5z" fill-rule="evenodd" fill="#ffff80"/>
<path d="M75.9 125.2l1.3-1.3h16.5v2.5h-16.5z" fill="none" stroke="#800000" stroke-width=".13"/>
<path d="M75.9 127.7l1.3-1.3h16.5v2.6h-16.5z" fill-rule="evenodd" fill="#ffff80"/>
<path d="M75.9 127.7l1.3-1.3h16.5v2.6h-16.5z" fill="none" stroke="#800000" stroke-width=".13"/>
<path d="M75.9 130.2l1.3-1.2h16.5v2.5h-16.5z" fill-rule="evenodd" fill="#ffff80"/>
<path d="M75.9 130.2l1.3-1.2h16.5v2.5h-16.5z" fill="none" stroke="#800000" stroke-width=".13"/>
<path d="M75.9 132.8l1.3-1.3h16.5v2.5h-16.5z" fill-rule="evenodd" fill="#ffff80"/>
<path d="M75.9 132.8l1.3-1.3h16.5v2.5h-16.5z" fill="none" stroke="#800000" stroke-width=".13"/>
<path d="M75.9 135.3l1.3-1.3h16.5v2.6h-16.5z" fill-rule="evenodd" fill="#ffff80"/>
<path d="M75.9 135.3l1.3-1.3h16.5v2.6h-16.5z" fill="none" stroke="#800000" stroke-width=".13"/>
<path d="M75.9 137.9l1.3-1.3h16.5v2.5h-16.5z" fill-rule="evenodd" fill="#ffff80"/>
<path d="M75.9 137.9l1.3-1.3h16.5v2.5h-16.5z" fill="none" stroke="#800000" stroke-width=".13"/>
<path d="M75.9 140.4l1.3-1.3h16.5v2.6h-16.5z" fill-rule="evenodd" fill="#ffff80"/>
<path d="M75.9 140.4l1.3-1.3h16.5v2.6h-16.5z" fill="none" stroke="#800000" stroke-width=".13"/>
<path d="M75.9 142.9l1.3-1.2h16.5v2.5h-16.5z" fill-rule="evenodd" fill="#ffff80"/>
<path d="M75.9 142.9l1.3-1.2h16.5v2.5h-16.5z" fill="none" stroke="#800000" stroke-width=".13"/>
<path d="M175.1 137.9l1.2-1.3h15.3l1.2 1.3-1.2 1.2h-15.3z" fill-rule="evenodd" fill="#ffff80"/>
<path d="M175.1 137.9l1.2-1.3h15.3l1.2 1.3-1.2 1.2h-15.3z" fill="none" stroke="#800000" stroke-width=".13"/>
<path d="M175.1 123.9h16.5l1.2 1.3-1.2 1.2h-16.5z" fill-rule="evenodd" fill="#ffff80"/>
<path d="M175.1 123.9h16.5l1.2 1.3-1.2 1.2h-16.5z" fill="none" stroke="#800000" stroke-width=".13"/>
<path d="M175.1 118.8h16.5l1.2 1.3-1.2 1.3h-16.5z" fill-rule="evenodd" fill="#ffff80"/>
<path d="M175.1 118.8h16.5l1.2 1.3-1.2 1.3h-16.5z" fill="none" stroke="#800000" stroke-width=".13"/>
<path d="M175.1 122.6l1.2-1.2h15.3l1.2 1.2-1.2 1.3h-15.3z" fill-rule="evenodd" fill="#ffff80"/>
<path d="M175.1 122.6l1.2-1.2h15.3l1.2 1.2-1.2 1.3h-15.3z" fill="none" stroke="#800000" stroke-width=".13"/>
<path d="M175.1 51.5l1.2-1.3h15.3l1.2 1.3-1.2 1.3h-15.3z" fill-rule="evenodd" fill="#ffff80"/>
<path d="M175.1 51.5l1.2-1.3h15.3l1.2 1.3-1.2 1.3h-15.3z" fill="none" stroke="#800000" stroke-width=".13"/>
<path d="M175.1 47.7h16.5l1.2 1.3-1.2 1.2h-16.5z" fill-rule="evenodd" fill="#ffff80"/>
<path d="M175.1 47.7h16.5l1.2 1.3-1.2 1.2h-16.5z" fill="none" stroke="#800000" stroke-width=".13"/>
<path d="M175.1 35h16.5l1.2 1.3-1.2 1.3h-16.5z" fill-rule="evenodd" fill="#ffff80"/>
<path d="M175.1 35h16.5l1.2 1.3-1.2 1.3h-16.5z" fill="none" stroke="#800000" stroke-width=".13"/>
<path d="M175.1 40.1h16.5l1.2 1.3-1.2 1.2h-16.5z" fill-rule="evenodd" fill="#ffff80"/>
<path d="M175.1 40.1h16.5l1.2 1.3-1.2 1.2h-16.5z" fill="none" stroke="#800000" stroke-width=".13"/>
<path d="M175.1 24.9h16.5l1.2 1.2-1.2 1.3h-16.5z" fill-rule="evenodd" fill="#ffff80"/>
<path d="M175.1 24.9h16.5l1.2 1.2-1.2 1.3h-16.5z" fill="none" stroke="#800000" stroke-width=".13"/>
<path d="M175.1 27.4h16.5l1.2 1.3-1.2 1.2h-16.5z" fill-rule="evenodd" fill="#ffff80"/>
<path d="M175.1 27.4h16.5l1.2 1.3-1.2 1.2h-16.5z" fill="none" stroke="#800000" stroke-width=".13"/>
<path d="M175.1 29.9h16.5l1.2 1.3-1.2 1.3h-16.5z" fill-rule="evenodd" fill="#ffff80"/>
<path d="M175.1 29.9h16.5l1.2 1.3-1.2 1.3h-16.5z" fill="none" stroke="#800000" stroke-width=".13"/>
<path d="M175.1 43.9l1.2-1.3h16.5v2.6h-16.5z" fill-rule="evenodd" fill="#ffff80"/>
<path d="M175.1 43.9l1.2-1.3h16.5v2.6h-16.5z" fill="none" stroke="#800000" stroke-width=".13"/>
<path d="M175.1 23.6l1.2-1.3h15.3l1.2 1.3-1.2 1.3h-15.3z" fill-rule="evenodd" fill="#ffff80"/>
<path d="M175.1 23.6l1.2-1.3h15.3l1.2 1.3-1.2 1.3h-15.3z" fill="none" stroke="#800000" stroke-width=".13"/>
<path d="M83.6 163.3h25.4v22.8h-25.4z" fill-rule="evenodd" fill="#ffffb0"/>
<path d="M83.6 163.3h25.4v22.8h-25.4z" fill="none" stroke="#800000" stroke-width=".13"/>
<path d="M75.9 165.8h7.7M75.9 178.5h7.7M75.9 176h7.7M75.9 170.9h7.7M109 165.8h7.6M121.7 168.3v2.6M121.7 176v2.5M75.9 181h7.7M75.9 183.6h7.7M109 181h7.6M109 183.6h7.6" fill="none" stroke="#000" stroke-width=".25"/>
<path d="M119.7 172.9h4M119.7 173.9h4M121.7 170.9v2M121.7 173.9v2.1" fill="none" stroke="#00f" stroke-width=".25"/>
<path d="M125.5 160.7h2.5M126.8 160.7v2.6M119.1 188.7h5.1M119.9 189.4h3.6M120.7 190.2h2M121.4 190.9h.5M121.7 186.1v2.6" fill="none" stroke="#800000" stroke-width=".25"/>
<path d="M42.3 169.6h14.6l1.2 1.3-1.2 1.2h-14.6z" fill-rule="evenodd" fill="#ffff80"/>
<path d="M42.3 169.6h14.6l1.2 1.3-1.2 1.2h-14.6z" fill="none" stroke="#800000" stroke-width=".13"/>
<path d="M162.3 165.8v5.1h2.6" fill="none" stroke="#000080" stroke-width=".25"/>
<circle cx="162.3" cy="165.8" r=".51" fill="#000080"/>
<circle cx="162.3" cy="165.8" r=".51" fill="none" stroke="#000080" stroke-width=".13"/>
<path d="M152.2 178.5v2.5M162.3 165.8h2.6" fill="none" stroke="#000080" stroke-width=".25"/>
<circle cx="162.3" cy="165.8" r=".51" fill="#000080"/>
<circle cx="162.3" cy="165.8" r=".51" fill="none" stroke="#000080" stroke-width=".13"/>
<path d="M162.3 165.8h-10.1v2.5" fill="none" stroke="#000080" stroke-width=".25"/>
<circle cx="162.3" cy="165.8" r=".51" fill="#000080"/>
<circle cx="162.3" cy="165.8" r=".51" fill="none" stroke="#000080" stroke-width=".13"/>
<circle cx="152.2" cy="165.8" r=".51" fill="#000080"/>
<circle cx="152.2" cy="165.8" r=".51" fill="none" stroke="#000080" stroke-width=".13"/>
<path d="M147.1 163.3v2.5h5.1M164.9 176h-2.6v5" fill="none" stroke="#000080" stroke-width=".25"/>
<circle cx="152.2" cy="165.8" r=".51" fill="#000080"/>
<circle cx="152.2" cy="165.8" r=".51" fill="none" stroke="#000080" stroke-width=".13"/>
<g fill="none" stroke="#000080" stroke-width=".25">
<path d="M60.7 23.6h20.3M60.7 26.1h20.3M60.7 28.7h20.3M60.7 31.2h20.3M60.7 33.7h20.3M154.7 23.6h20.4M154.7 26.1h20.4M154.7 28.7h20.4M154.7 31.2h20.4M154.7 33.7h20.4M154.7 36.3h20.4M154.7 38.8h20.4"/>
<path d="M60.7 49h20.3M154.7 49h20.4M154.7 51.5h20.4M154.7 59.1h20.4M154.7 54.1h20.4M154.7 46.4h20.4M154.7 56.6h20.4M154.7 41.4h20.4M154.7 43.9h20.4M154.7 79.5h20.4M60.7 94.7h15.2M60.7 97.2h15.2"/>
<path d="M60.7 84.5h15.2M60.7 87.1h15.2M60.7 99.8h15.2M60.7 109.9h15.2M60.7 112.5h15.2M60.7 102.3h15.2M60.7 104.8h15.2M60.7 107.4h15.2M154.7 109.9h20.4M154.7 112.5h20.4M154.7 115h20.4M154.7 117.5h20.4"/>
<path d="M60.7 135.3h15.2M60.7 137.9h15.2M60.7 130.2h15.2M60.7 132.8h15.2M60.7 125.2h15.2M60.7 127.7h15.2M60.7 120.1h15.2M60.7 122.6h15.2M154.7 135.3h20.4M154.7 137.9h20.4M154.7 130.2h20.4M154.7 132.8h20.4"/>
<path d="M154.7 125.2h20.4M154.7 120.1h20.4M154.7 122.6h20.4M154.7 127.7h20.4M60.7 140.4h15.2M60.7 142.9h15.2M154.7 140.4h20.4M154.7 142.9h20.4M58.1 170.9h17.8M126.8 163.3v2.5h-10.2M200.5 165.8h5.1M243.7 173.4h20.3"/>
</g>
<circle cx="121.7" cy="165.8" r=".51" fill="#000080"/>
<circle cx="121.7" cy="165.8" r=".51" fill="none" stroke="#000080" stroke-width=".13"/>
<path d="M121.7 165.8v2.5" fill="none" stroke="#000080" stroke-width=".25"/>
<circle cx="121.7" cy="165.8" r=".51" fill="#000080"/>
<circle cx="121.7" cy="165.8" r=".51" fill="none" stroke="#000080" stroke-width=".13"/>
<path d="M121.7 178.5v7.6" fill="none" stroke="#000080" stroke-width=".25"/>
<circle cx="121.7" cy="181" r=".51" fill="#000080"/>
<circle cx="121.7" cy="181" r=".51" fill="none" stroke="#000080" stroke-width=".13"/>
<circle cx="121.7" cy="183.6" r=".51" fill="#000080"/>
<circle cx="121.7" cy="183.6" r=".51" fill="none" stroke="#000080" stroke-width=".13"/>
<path d="M116.6 183.6h5.1" fill="none" stroke="#000080" stroke-width=".25"/>
<circle cx="121.7" cy="183.6" r=".51" fill="#000080"/>
<circle cx="121.7" cy="183.6" r=".51" fill="none" stroke="#000080" stroke-width=".13"/>
<path d="M116.6 181h5.1" fill="none" stroke="#000080" stroke-width=".25"/>
<circle cx="121.7" cy="181" r=".51" fill="#000080"/>
<circle cx="121.7" cy="181" r=".51" fill="none" stroke="#000080" stroke-width=".13"/>
<path d="M58.1 176h17.8M58.1 178.5h17.8M58.1 165.8h17.8M58.1 181h17.8M58.1 183.6h17.8" fill="none" stroke="#000080" stroke-width=".25"/>
<path d="M243.7 160.7h20.3M243.7 163.3h20.3M243.7 168.3h20.3M243.7 165.8h20.3" fill="none" stroke="#000080" stroke-width=".76"/>
<use href="#words"/>
</svg>
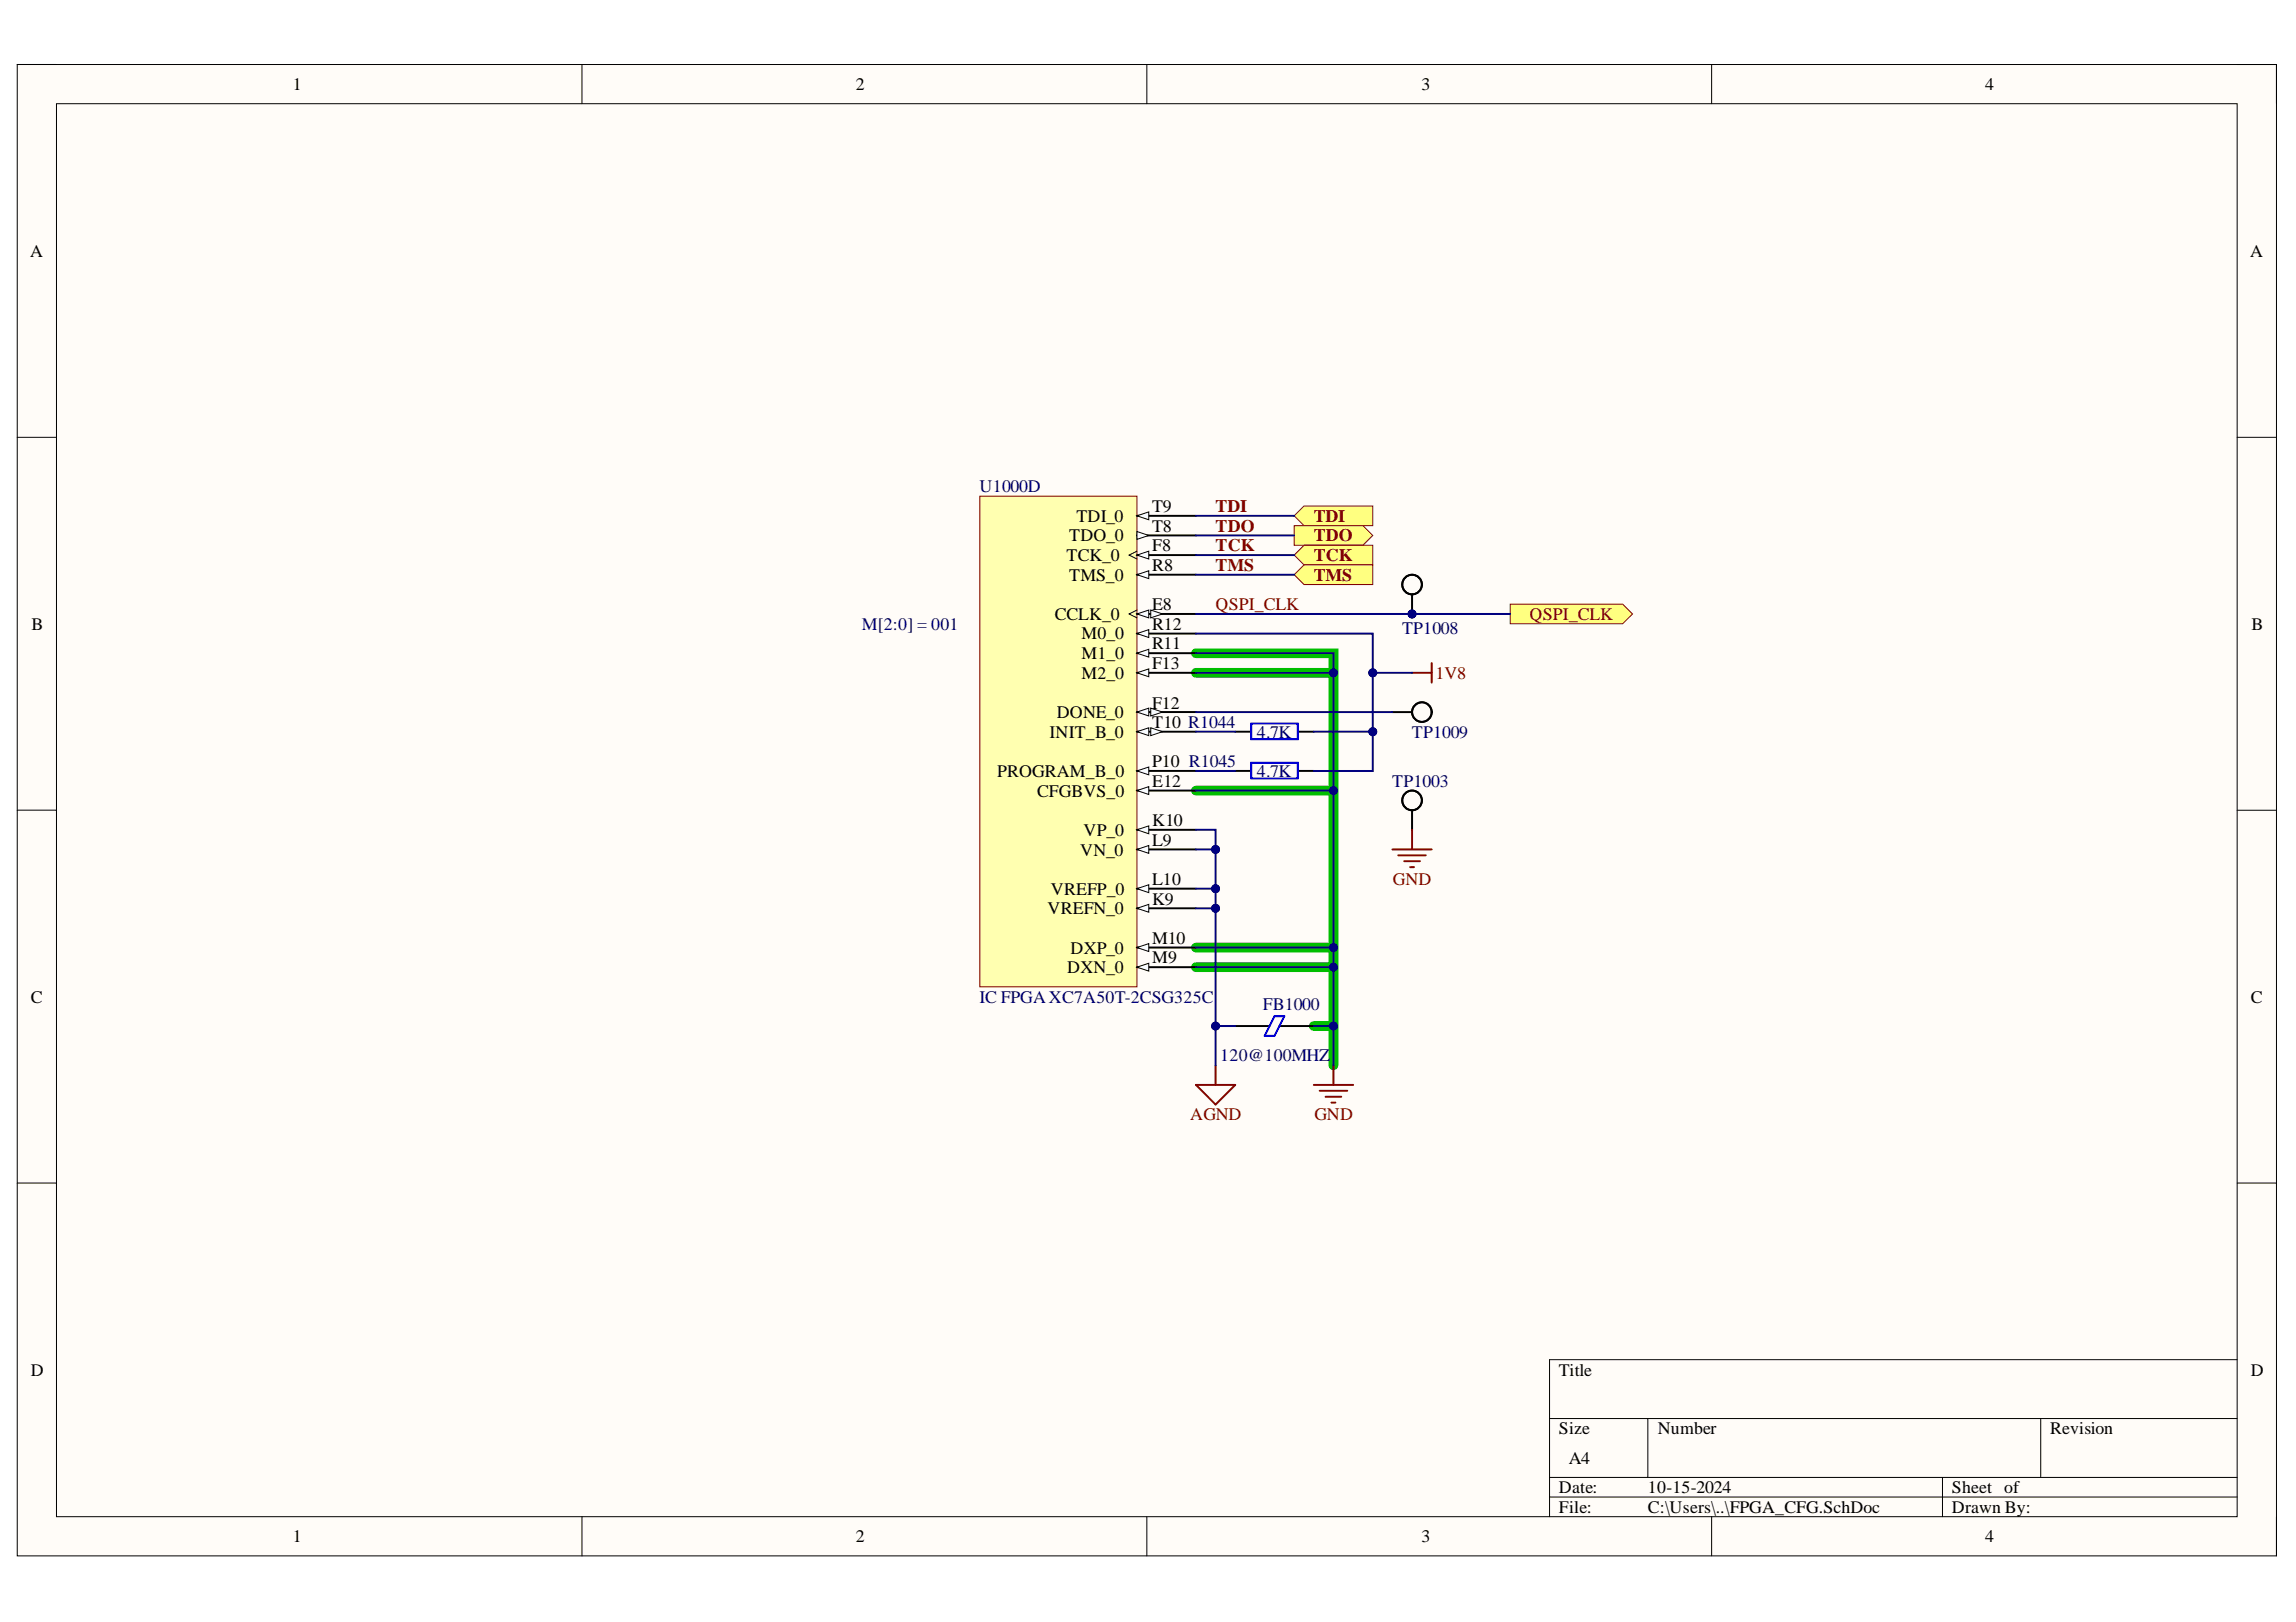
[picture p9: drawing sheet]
<svg xmlns="http://www.w3.org/2000/svg" width="297mm" height="210mm" viewBox="0 0 297 210" stroke-linecap="round" stroke-linejoin="round" font-family="sans-serif">
<defs><g id="words">
<g font-size="2.3">
<text x="37.9" y="11.7">1</text>
<text x="110.7" y="11.7">2</text>
<text x="183.9" y="11.7">3</text>
<text x="256.8" y="11.7">4</text>
<text x="3.9" y="33.3">A</text>
<text x="291.1" y="33.3">A</text>
<text x="138.3" y="70.1">TDO_0</text>
<text x="139.3" y="67.5">TDI_0</text>
<text x="149.1" y="71.3">F8</text>
<text x="149.1" y="66.3">T9</text>
<text x="149.1" y="68.8">T8</text>
<text x="138" y="72.6">TCK_0</text>
<text x="138.3" y="75.1">TMS_0</text>
<text x="149.1" y="73.9">R8</text>
<text x="4.1" y="81.5">B</text>
<text x="136.5" y="80.2">CCLK_0</text>
<text x="139.9" y="82.7">M0_0</text>
<text x="149.1" y="78.9">E8</text>
<text x="149.1" y="81.5">R12</text>
<text x="291.3" y="81.5">B</text>
<text x="139.9" y="85.3">M1_0</text>
<text x="139.9" y="87.8">M2_0</text>
<text x="149.1" y="84">R11</text>
<text x="149.1" y="86.6">F13</text>
<text x="135.8" y="95.5">INIT_B_0</text>
<text x="136.7" y="93">DONE_0</text>
<text x="149.1" y="91.7">F12</text>
<text x="149.1" y="94.2">T10 R1044</text>
<text x="129" y="100.6">PROGRAM_B_0</text>
<text x="149.1" y="101.9">E12</text>
<text x="149.1" y="99.3">P10 R1045</text>
<text x="134.2" y="103.1">CFGBVS_0</text>
<text x="149.1" y="106.9">K10</text>
<text x="139.8" y="110.7">VN_0</text>
<text x="140.2" y="108.2">VP_0</text>
<text x="149.1" y="109.5">L9</text>
<text x="135.5" y="118.3">VREFN_0</text>
<text x="136" y="115.8">VREFP_0</text>
<text x="149.1" y="114.5">L10</text>
<text x="149.1" y="117.1">K9</text>
<text x="138.1" y="125.9">DXN_0</text>
<text x="138.5" y="123.4">DXP_0</text>
<text x="149.1" y="122.1">M10</text>
<text x="149.1" y="124.7">M9</text>
<text x="4" y="129.7">C</text>
<text x="291.2" y="129.7">C</text>
<text x="4" y="178">D</text>
<text x="201.7" y="178">Title</text>
<text x="291.2" y="178">D</text>
<text x="201.7" y="185.6">Size</text>
<text x="214.5" y="185.6">Number</text>
<text x="265.2" y="185.6">Revision</text>
<text x="203" y="189.4">A4</text>
<text x="201.7" y="193.2">Date:</text>
<text x="201.7" y="195.8">File:</text>
<text x="213.2" y="193.2">10-15-2024</text>
<text x="213.2" y="195.8">C:\Users\..\FPGA_CFG.SchDoc</text>
<text x="252.5" y="193.2">Sheet of</text>
<text x="252.5" y="195.8">Drawn By:</text>
<text x="37.9" y="199.6">1</text>
<text x="110.7" y="199.6">2</text>
<text x="183.9" y="199.6">3</text>
<text x="256.8" y="199.6">4</text>
</g>
<g font-size="2.3" fill="#000080">
<text x="126.7" y="63.7">U1000D</text>
<text x="111.5" y="81.5">M[2:0] = 001</text>
<text x="181.4" y="82">TP1008</text>
<text x="162.6" y="95.5">4.7K</text>
<text x="182.7" y="95.5">TP1009</text>
<text x="162.6" y="100.6">4.7K</text>
<text x="180.1" y="101.9">TP1003</text>
<text x="126.7" y="129.7">IC FPGAXC7A50T-2CSG325C</text>
<text x="163.4" y="130.8">FB1000</text>
<text x="157.9" y="137.4">120@100MHZ</text>
</g>
<g font-size="2.3" fill="#800000">
<text x="157.3" y="71.3">TCK</text>
<text x="157.3" y="68.8">TDO</text>
<text x="157.3" y="66.3">TDI</text>
<text x="170" y="67.5">TDI</text>
<text x="170" y="70.1">TDO</text>
<text x="157.3" y="73.9">TMS</text>
<text x="170" y="72.6">TCK</text>
<text x="170" y="75.1">TMS</text>
<text x="157.3" y="78.9">QSPI_CLK</text>
<text x="197.9" y="80.2">QSPI_CLK</text>
<text x="185.7" y="87.8">1V8</text>
<text x="180.2" y="114.5">GND</text>
<text x="154" y="145">AGND</text>
<text x="170" y="145">GND</text>
</g>
</g></defs>
<path d="M2.2 8.3h292.3v193h-292.3z" fill-rule="evenodd" fill="#fffcf8"/>
<path d="M2.2 8.3h292.3v193h-292.3z" fill="none" stroke="#000" stroke-width=".13"/>
<path d="M7.3 13.4h282.1v182.9h-282.1z" fill-rule="evenodd" fill="#fffcf8"/>
<g fill="none" stroke="#000" stroke-width=".13">
<path d="M2.2 8.3h5.1M7.3 13.4h282.1v182.9h-282.1zM75.3 8.3v5.1M148.4 8.3v5.1M221.4 8.3v5.1M289.4 8.3h5.1v5.1M2.2 56.6h5.1M289.4 56.6h5.1M2.2 104.8h5.1M289.4 104.9h5.1M2.2 153.1h5.1M289.4 153.1h5.1"/>
<path d="M289.4 176h-88.9v20.3M75.3 196.3v5M148.4 196.3v5M200.5 183.6h88.9M200.5 191.2h88.9M200.5 193.7h88.9M213.2 183.6v7.6M221.4 196.3v5M251.3 191.2v5.1M264 183.6v7.6M294.5 196.3v5"/>
</g>
<path d="M154.7 84.5h17.8v53.4M154.7 87.1h17.8M154.7 102.3h17.8M154.7 122.6h17.8M154.7 125.2h17.8M170 132.8h2.5" fill="none" stroke="#00be00" stroke-width="1.3"/>
<path d="M126.8 64.2h20.3v63.5h-20.3z" fill-rule="evenodd" fill="#ffffb0"/>
<path d="M126.8 64.2h20.3v63.5h-20.3z" fill="none" stroke="#800000" stroke-width=".13"/>
<path d="M147.1 92.1h7.6" fill="none" stroke="#000" stroke-width=".25"/>
<path d="M147.1 92.1l1.5-.5v1.1z" fill="#f8fcff"/>
<path d="M147.1 92.1l1.5-.5v1.1z" fill="none" stroke="#000" stroke-width=".13"/>
<path d="M148.9 91.6l1.5 .5-1.5 .6z" fill="#f8fcff"/>
<path d="M148.9 91.6l1.5 .5-1.5 .6z" fill="none" stroke="#000" stroke-width=".13"/>
<path d="M147.1 122.6h7.6" fill="none" stroke="#000" stroke-width=".25"/>
<path d="M147.1 122.6l1.5-.5v1z" fill="#f8fcff"/>
<path d="M147.1 122.6l1.5-.5v1z" fill="none" stroke="#000" stroke-width=".13"/>
<path d="M147.1 115h7.6" fill="none" stroke="#000" stroke-width=".25"/>
<path d="M147.1 115l1.5-.5v1z" fill="#f8fcff"/>
<path d="M147.1 115l1.5-.5v1z" fill="none" stroke="#000" stroke-width=".13"/>
<path d="M147.1 109.9h7.6" fill="none" stroke="#000" stroke-width=".25"/>
<path d="M147.1 109.9l1.5-.5v1z" fill="#f8fcff"/>
<path d="M147.1 109.9l1.5-.5v1z" fill="none" stroke="#000" stroke-width=".13"/>
<path d="M147.1 71.8h7.6" fill="none" stroke="#000" stroke-width=".25"/>
<path d="M147.1 71.8l1.5-.5v1z" fill="#f8fcff"/>
<path d="M147.1 71.8l1.5-.5v1zM147.1 71.3l-1 .5 1 .5" fill="none" stroke="#000" stroke-width=".13"/>
<path d="M147.1 125.2h7.6" fill="none" stroke="#000" stroke-width=".25"/>
<path d="M147.1 125.2l1.5-.5v1z" fill="#f8fcff"/>
<path d="M147.1 125.2l1.5-.5v1z" fill="none" stroke="#000" stroke-width=".13"/>
<path d="M147.1 117.5h7.6" fill="none" stroke="#000" stroke-width=".25"/>
<path d="M147.1 117.5l1.5-.5v1.1z" fill="#f8fcff"/>
<path d="M147.1 117.5l1.5-.5v1.1z" fill="none" stroke="#000" stroke-width=".13"/>
<path d="M147.1 107.4h7.6" fill="none" stroke="#000" stroke-width=".25"/>
<path d="M147.1 107.4l1.5-.5v1z" fill="#f8fcff"/>
<path d="M147.1 107.4l1.5-.5v1z" fill="none" stroke="#000" stroke-width=".13"/>
<path d="M147.1 79.5h7.6" fill="none" stroke="#000" stroke-width=".25"/>
<path d="M147.1 79.5l1.5-.6v1.1z" fill="#f8fcff"/>
<path d="M147.1 79.5l1.5-.6v1.1z" fill="none" stroke="#000" stroke-width=".13"/>
<path d="M148.9 78.9l1.5 .6-1.5 .5z" fill="#f8fcff"/>
<path d="M147.1 78.9l-1 .6 1 .5M148.9 78.9l1.5 .6-1.5 .5z" fill="none" stroke="#000" stroke-width=".13"/>
<path d="M147.1 82h7.6" fill="none" stroke="#000" stroke-width=".25"/>
<path d="M147.1 82l1.5-.5v1z" fill="#f8fcff"/>
<path d="M147.1 82l1.5-.5v1z" fill="none" stroke="#000" stroke-width=".13"/>
<path d="M147.1 84.5h7.6" fill="none" stroke="#000" stroke-width=".25"/>
<path d="M147.1 84.5l1.5-.5v1z" fill="#f8fcff"/>
<path d="M147.1 84.5l1.5-.5v1z" fill="none" stroke="#000" stroke-width=".13"/>
<path d="M147.1 94.7h7.6" fill="none" stroke="#000" stroke-width=".25"/>
<path d="M147.1 94.7l1.5-.5v1z" fill="#f8fcff"/>
<path d="M147.1 94.7l1.5-.5v1z" fill="none" stroke="#000" stroke-width=".13"/>
<path d="M148.9 94.2l1.5 .5-1.5 .5z" fill="#f8fcff"/>
<path d="M148.9 94.2l1.5 .5-1.5 .5z" fill="none" stroke="#000" stroke-width=".13"/>
<path d="M147.1 66.8h7.6" fill="none" stroke="#000" stroke-width=".25"/>
<path d="M147.1 66.8l1.5-.6v1.1z" fill="#f8fcff"/>
<path d="M147.1 66.8l1.5-.6v1.1z" fill="none" stroke="#000" stroke-width=".13"/>
<path d="M147.1 69.3h7.6" fill="none" stroke="#000" stroke-width=".25"/>
<path d="M147.1 68.8l1.5 .5-1.5 .5z" fill="#f8fcff"/>
<path d="M147.1 68.8l1.5 .5-1.5 .5z" fill="none" stroke="#000" stroke-width=".13"/>
<path d="M147.1 87.1h7.6" fill="none" stroke="#000" stroke-width=".25"/>
<path d="M147.1 87.1l1.5-.5v1z" fill="#f8fcff"/>
<path d="M147.1 87.1l1.5-.5v1z" fill="none" stroke="#000" stroke-width=".13"/>
<path d="M147.1 102.3h7.6" fill="none" stroke="#000" stroke-width=".25"/>
<path d="M147.1 102.3l1.5-.5v1z" fill="#f8fcff"/>
<path d="M147.1 102.3l1.5-.5v1z" fill="none" stroke="#000" stroke-width=".13"/>
<path d="M147.1 99.8h7.6" fill="none" stroke="#000" stroke-width=".25"/>
<path d="M147.1 99.8l1.5-.5v1z" fill="#f8fcff"/>
<path d="M147.1 99.8l1.5-.5v1z" fill="none" stroke="#000" stroke-width=".13"/>
<path d="M147.1 74.4h7.6" fill="none" stroke="#000" stroke-width=".25"/>
<path d="M147.1 74.4l1.5-.5v1z" fill="#f8fcff"/>
<path d="M147.1 74.4l1.5-.5v1z" fill="none" stroke="#000" stroke-width=".13"/>
<path d="M182.7 87.1h2.5M185.2 85.8v2.5M157.3 137.9v2.5M172.5 137.9v2.5M154.7 140.4h5.1l-2.5 2.5zM170 140.4h5.1M170.7 141.2h3.6M171.5 141.9h2M172.3 142.7h.5" fill="none" stroke="#800000" stroke-width=".25"/>
<g fill="none" stroke="#000" stroke-width=".25">
<path d="M159.8 99.8h2M159.8 94.7h2M168 99.8h2M168 94.7h2M180.1 92.2h2.6M159.8 132.8h4.5M165.5 132.8h4.5"/>
<circle cx="184" cy="92.2" r="1.27"/>
</g>
<path d="M161.9 98.7h6v2h-6zM161.9 93.6h6v2.1h-6zM164.9 131.5h1.3l-1.3 2.5h-1.3z" fill="none" stroke="#00f" stroke-width=".25"/>
<circle cx="182.7" cy="79.5" r=".51" fill="#000080"/>
<circle cx="182.7" cy="79.5" r=".51" fill="none" stroke="#000080" stroke-width=".13"/>
<path d="M182.7 76.9v2.6" fill="none" stroke="#000" stroke-width=".25"/>
<circle cx="182.7" cy="79.5" r=".51" fill="#000080"/>
<circle cx="182.7" cy="79.5" r=".51" fill="none" stroke="#000080" stroke-width=".13"/>
<g fill="none" stroke="#000" stroke-width=".25">
<path d="M182.7 104.9v2.5"/>
<circle cx="182.7" cy="75.6" r="1.27"/>
<circle cx="182.7" cy="103.6" r="1.27"/>
</g>
<path d="M180.1 109.9h5.1M180.9 110.7h3.6M181.7 111.4h2M182.4 112.2h.5M182.7 107.4v2.5" fill="none" stroke="#800000" stroke-width=".25"/>
<path d="M167.4 66.8l1.3-1.3h8.9v2.5h-8.9z" fill-rule="evenodd" fill="#ffff80"/>
<path d="M167.4 66.8l1.3-1.3h8.9v2.5h-8.9z" fill="none" stroke="#800000" stroke-width=".13"/>
<path d="M167.4 68h8.9l1.3 1.3-1.3 1.3h-8.9z" fill-rule="evenodd" fill="#ffff80"/>
<path d="M167.4 68h8.9l1.3 1.3-1.3 1.3h-8.9z" fill="none" stroke="#800000" stroke-width=".13"/>
<path d="M167.4 71.8l1.3-1.2h8.9v2.5h-8.9z" fill-rule="evenodd" fill="#ffff80"/>
<path d="M167.4 71.8l1.3-1.2h8.9v2.5h-8.9z" fill="none" stroke="#800000" stroke-width=".13"/>
<path d="M168.7 73.1h8.9v2.5h-8.9l-1.3-1.2z" fill-rule="evenodd" fill="#ffff80"/>
<path d="M168.7 73.1h8.9v2.5h-8.9l-1.3-1.2z" fill="none" stroke="#800000" stroke-width=".13"/>
<path d="M195.4 78.2h14.5l1.3 1.3-1.3 1.2h-14.5z" fill-rule="evenodd" fill="#ffff80"/>
<path d="M195.4 78.2h14.5l1.3 1.3-1.3 1.2h-14.5z" fill="none" stroke="#800000" stroke-width=".13"/>
<path d="M154.7 94.7h5.1M154.7 99.8h5.1M154.7 109.9h2.6" fill="none" stroke="#000080" stroke-width=".25"/>
<circle cx="157.3" cy="109.9" r=".51" fill="#000080"/>
<circle cx="157.3" cy="109.9" r=".51" fill="none" stroke="#000080" stroke-width=".13"/>
<path d="M154.7 115h2.6v2.5h-2.6" fill="none" stroke="#000080" stroke-width=".25"/>
<circle cx="157.3" cy="117.5" r=".51" fill="#000080"/>
<circle cx="157.3" cy="117.5" r=".51" fill="none" stroke="#000080" stroke-width=".13"/>
<circle cx="157.3" cy="115" r=".51" fill="#000080"/>
<circle cx="157.3" cy="115" r=".51" fill="none" stroke="#000080" stroke-width=".13"/>
<path d="M157.3 117.5v20.4" fill="none" stroke="#000080" stroke-width=".25"/>
<circle cx="157.3" cy="117.5" r=".51" fill="#000080"/>
<circle cx="157.3" cy="117.5" r=".51" fill="none" stroke="#000080" stroke-width=".13"/>
<circle cx="157.3" cy="132.8" r=".51" fill="#000080"/>
<circle cx="157.3" cy="132.8" r=".51" fill="none" stroke="#000080" stroke-width=".13"/>
<path d="M154.7 107.4h2.6v7.6" fill="none" stroke="#000080" stroke-width=".25"/>
<circle cx="157.3" cy="109.9" r=".51" fill="#000080"/>
<circle cx="157.3" cy="109.9" r=".51" fill="none" stroke="#000080" stroke-width=".13"/>
<circle cx="157.3" cy="115" r=".51" fill="#000080"/>
<circle cx="157.3" cy="115" r=".51" fill="none" stroke="#000080" stroke-width=".13"/>
<path d="M154.7 102.3h17.8" fill="none" stroke="#000080" stroke-width=".25"/>
<circle cx="172.5" cy="102.3" r=".51" fill="#000080"/>
<circle cx="172.5" cy="102.3" r=".51" fill="none" stroke="#000080" stroke-width=".13"/>
<path d="M154.7 92.2h25.4M154.7 87.1h17.8" fill="none" stroke="#000080" stroke-width=".25"/>
<circle cx="172.5" cy="87.1" r=".51" fill="#000080"/>
<circle cx="172.5" cy="87.1" r=".51" fill="none" stroke="#000080" stroke-width=".13"/>
<path d="M154.7 84.5h17.8v53.4" fill="none" stroke="#000080" stroke-width=".25"/>
<circle cx="172.5" cy="132.8" r=".51" fill="#000080"/>
<circle cx="172.5" cy="132.8" r=".51" fill="none" stroke="#000080" stroke-width=".13"/>
<circle cx="172.5" cy="125.2" r=".51" fill="#000080"/>
<circle cx="172.5" cy="125.2" r=".51" fill="none" stroke="#000080" stroke-width=".13"/>
<circle cx="172.5" cy="122.6" r=".51" fill="#000080"/>
<circle cx="172.5" cy="122.6" r=".51" fill="none" stroke="#000080" stroke-width=".13"/>
<circle cx="172.5" cy="102.3" r=".51" fill="#000080"/>
<circle cx="172.5" cy="102.3" r=".51" fill="none" stroke="#000080" stroke-width=".13"/>
<circle cx="172.5" cy="87.1" r=".51" fill="#000080"/>
<circle cx="172.5" cy="87.1" r=".51" fill="none" stroke="#000080" stroke-width=".13"/>
<path d="M177.6 94.7v5.1h-7.6" fill="none" stroke="#000080" stroke-width=".25"/>
<circle cx="177.6" cy="94.7" r=".51" fill="#000080"/>
<circle cx="177.6" cy="94.7" r=".51" fill="none" stroke="#000080" stroke-width=".13"/>
<path d="M154.7 122.6h17.8" fill="none" stroke="#000080" stroke-width=".25"/>
<circle cx="172.5" cy="122.6" r=".51" fill="#000080"/>
<circle cx="172.5" cy="122.6" r=".51" fill="none" stroke="#000080" stroke-width=".13"/>
<path d="M154.7 125.2h17.8" fill="none" stroke="#000080" stroke-width=".25"/>
<circle cx="172.5" cy="125.2" r=".51" fill="#000080"/>
<circle cx="172.5" cy="125.2" r=".51" fill="none" stroke="#000080" stroke-width=".13"/>
<path d="M157.3 132.8h2.5" fill="none" stroke="#000080" stroke-width=".25"/>
<circle cx="157.3" cy="132.8" r=".51" fill="#000080"/>
<circle cx="157.3" cy="132.8" r=".51" fill="none" stroke="#000080" stroke-width=".13"/>
<path d="M170 132.8h2.5" fill="none" stroke="#000080" stroke-width=".25"/>
<circle cx="172.5" cy="132.8" r=".51" fill="#000080"/>
<circle cx="172.5" cy="132.8" r=".51" fill="none" stroke="#000080" stroke-width=".13"/>
<path d="M154.7 79.5h40.7" fill="none" stroke="#000080" stroke-width=".25"/>
<circle cx="182.7" cy="79.5" r=".51" fill="#000080"/>
<circle cx="182.7" cy="79.5" r=".51" fill="none" stroke="#000080" stroke-width=".13"/>
<path d="M154.7 82h22.9v12.7h-7.6" fill="none" stroke="#000080" stroke-width=".25"/>
<circle cx="177.6" cy="94.7" r=".51" fill="#000080"/>
<circle cx="177.6" cy="94.7" r=".51" fill="none" stroke="#000080" stroke-width=".13"/>
<circle cx="177.6" cy="87.1" r=".51" fill="#000080"/>
<circle cx="177.6" cy="87.1" r=".51" fill="none" stroke="#000080" stroke-width=".13"/>
<path d="M177.6 87.1h5.1" fill="none" stroke="#000080" stroke-width=".25"/>
<circle cx="177.6" cy="87.1" r=".51" fill="#000080"/>
<circle cx="177.6" cy="87.1" r=".51" fill="none" stroke="#000080" stroke-width=".13"/>
<path d="M154.7 66.8h12.7M154.7 69.3h12.7M154.7 71.8h12.7M154.7 74.4h12.7" fill="none" stroke="#000080" stroke-width=".25"/>
<use href="#words"/>
</svg>
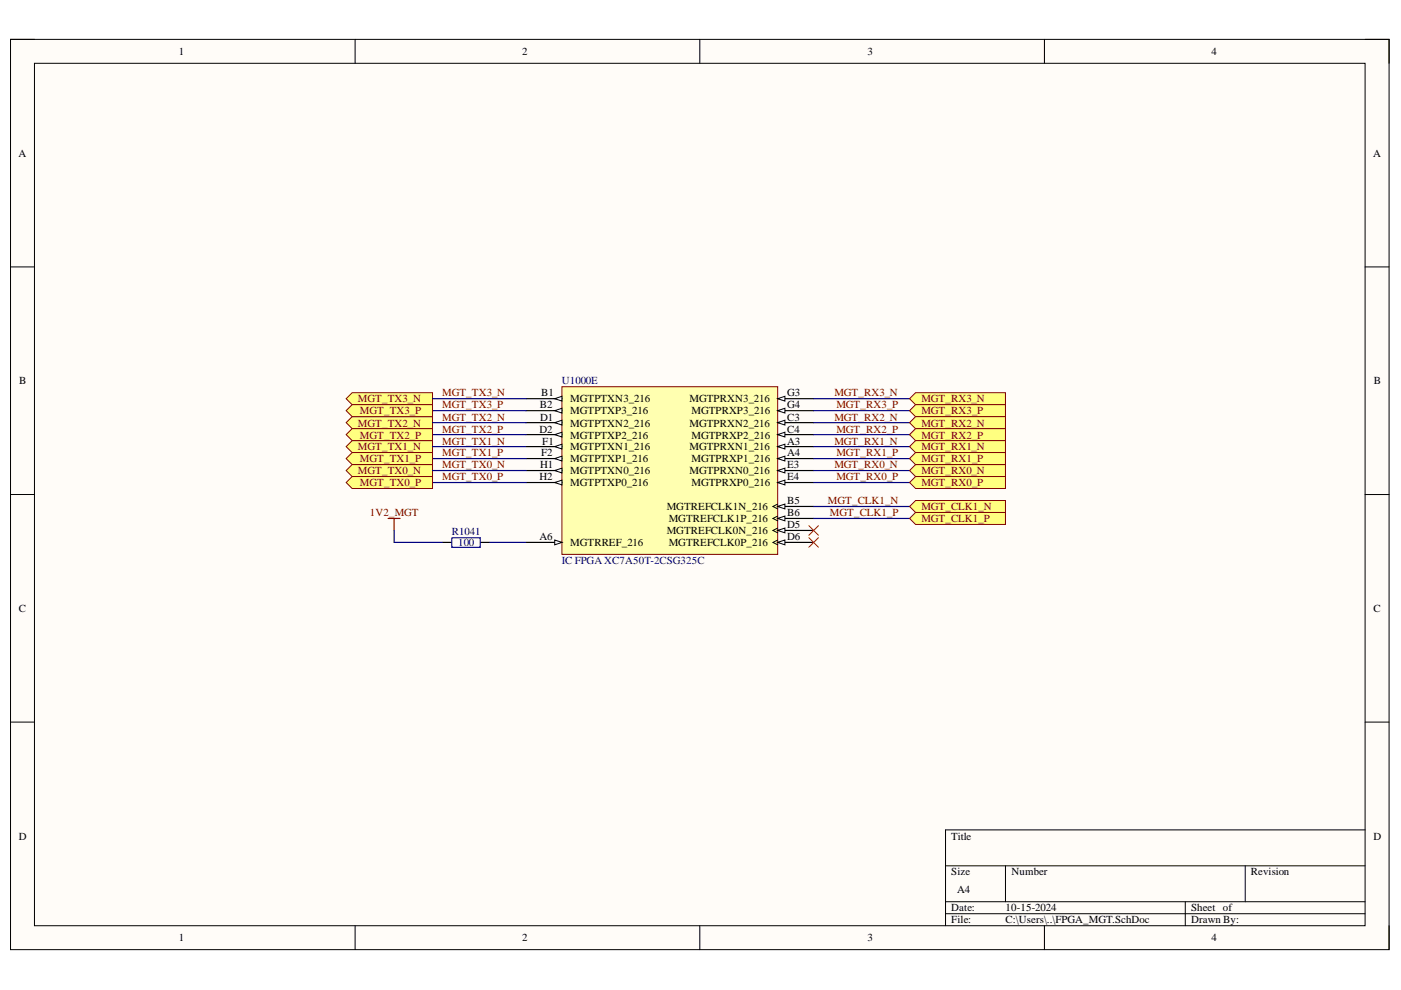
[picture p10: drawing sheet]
<svg xmlns="http://www.w3.org/2000/svg" width="297mm" height="210mm" viewBox="0 0 297 210" stroke-linecap="round" stroke-linejoin="round" font-family="sans-serif">
<defs><g id="words">
<g font-size="2.3">
<text x="37.9" y="11.7">1</text>
<text x="110.7" y="11.7">2</text>
<text x="183.9" y="11.7">3</text>
<text x="256.8" y="11.7">4</text>
<text x="3.9" y="33.3">A</text>
<text x="291.1" y="33.3">A</text>
<text x="4.1" y="81.5">B</text>
<text x="291.3" y="81.5">B</text>
<text x="114.5" y="86.6">B2</text>
<text x="114.5" y="89.2">D1</text>
<text x="114.7" y="84">B1</text>
<text x="120.9" y="87.8">MGTPTXP3_216</text>
<text x="120.9" y="85.3">MGTPTXN3_216</text>
<text x="146.2" y="85.3">MGTPRXN3_216</text>
<text x="146.6" y="87.8">MGTPRXP3_216</text>
<text x="166.9" y="86.6">G4</text>
<text x="166.9" y="89.2">C3</text>
<text x="166.9" y="84">G3</text>
<text x="114.4" y="91.7">D2</text>
<text x="115" y="94.2">F1</text>
<text x="120.9" y="93">MGTPTXP2_216</text>
<text x="120.9" y="90.4">MGTPTXN2_216</text>
<text x="120.9" y="95.5">MGTPTXN1_216</text>
<text x="146.2" y="95.5">MGTPRXN1_216</text>
<text x="146.2" y="90.4">MGTPRXN2_216</text>
<text x="146.6" y="93">MGTPRXP2_216</text>
<text x="166.9" y="91.7">C4</text>
<text x="166.9" y="94.2">A3</text>
<text x="114.4" y="101.9">H2</text>
<text x="114.5" y="99.3">H1</text>
<text x="114.7" y="96.8">F2</text>
<text x="120.9" y="98">MGTPTXP1_216</text>
<text x="120.9" y="100.6">MGTPTXN0_216</text>
<text x="146.2" y="100.6">MGTPRXN0_216</text>
<text x="146.6" y="98">MGTPRXP1_216</text>
<text x="166.9" y="96.8">A4</text>
<text x="166.9" y="101.9">E4</text>
<text x="166.9" y="99.3">E3</text>
<text x="120.9" y="103.1">MGTPTXP0_216</text>
<text x="146.6" y="103.1">MGTPRXP0_216</text>
<text x="166.9" y="106.9">B5</text>
<text x="141.4" y="113.3">MGTREFCLK0N_216</text>
<text x="141.4" y="108.2">MGTREFCLK1N_216</text>
<text x="141.8" y="110.7">MGTREFCLK1P_216</text>
<text x="166.9" y="112">D5</text>
<text x="166.9" y="109.5">B6</text>
<text x="114.4" y="114.5">A6</text>
<text x="120.9" y="115.8">MGTRREF_216</text>
<text x="141.8" y="115.8">MGTREFCLK0P_216</text>
<text x="166.9" y="114.5">D6</text>
<text x="4" y="129.7">C</text>
<text x="291.2" y="129.7">C</text>
<text x="4" y="178">D</text>
<text x="201.7" y="178">Title</text>
<text x="291.2" y="178">D</text>
<text x="201.7" y="185.6">Size</text>
<text x="214.5" y="185.6">Number</text>
<text x="265.2" y="185.6">Revision</text>
<text x="203" y="189.4">A4</text>
<text x="201.7" y="193.2">Date:</text>
<text x="201.7" y="195.8">File:</text>
<text x="213.2" y="193.2">10-15-2024</text>
<text x="213.2" y="195.8">C:\Users\..\FPGA_MGT.SchDoc</text>
<text x="252.5" y="193.2">Sheet of</text>
<text x="252.5" y="195.8">Drawn By:</text>
<text x="37.9" y="199.6">1</text>
<text x="110.7" y="199.6">2</text>
<text x="183.9" y="199.6">3</text>
<text x="256.8" y="199.6">4</text>
</g>
<g font-size="2.3" fill="#000080">
<text x="119.1" y="81.5">U1000E</text>
<text x="95.8" y="113.5">R1041</text>
<text x="97.1" y="115.8">100</text>
<text x="119.1" y="119.6">IC FPGAXC7A50T-2CSG325C</text>
</g>
<g font-size="2.3" fill="#800000">
<text x="75.9" y="85.3">MGT_TX3_N</text>
<text x="76.3" y="87.8">MGT_TX3_P</text>
<text x="93.7" y="89.2">MGT_TX2_N</text>
<text x="93.7" y="84">MGT_TX3_N</text>
<text x="93.7" y="86.6">MGT_TX3_P</text>
<text x="176.9" y="89.2">MGT_RX2_N</text>
<text x="176.9" y="84">MGT_RX3_N</text>
<text x="177.3" y="86.6">MGT_RX3_P</text>
<text x="195.3" y="85.3">MGT_RX3_N</text>
<text x="195.3" y="87.8">MGT_RX3_P</text>
<text x="75.9" y="90.4">MGT_TX2_N</text>
<text x="75.9" y="95.5">MGT_TX1_N</text>
<text x="76.3" y="93">MGT_TX2_P</text>
<text x="93.7" y="94.2">MGT_TX1_N</text>
<text x="93.7" y="91.7">MGT_TX2_P</text>
<text x="176.9" y="94.2">MGT_RX1_N</text>
<text x="177.3" y="91.7">MGT_RX2_P</text>
<text x="195.3" y="90.4">MGT_RX2_N</text>
<text x="195.3" y="93">MGT_RX2_P</text>
<text x="195.3" y="95.5">MGT_RX1_N</text>
<text x="75.9" y="100.6">MGT_TX0_N</text>
<text x="76.3" y="98">MGT_TX1_P</text>
<text x="93.7" y="99.3">MGT_TX0_N</text>
<text x="93.7" y="101.9">MGT_TX0_P</text>
<text x="93.7" y="96.8">MGT_TX1_P</text>
<text x="176.9" y="99.3">MGT_RX0_N</text>
<text x="177.3" y="101.9">MGT_RX0_P</text>
<text x="177.3" y="96.8">MGT_RX1_P</text>
<text x="195.3" y="98">MGT_RX1_P</text>
<text x="195.3" y="100.6">MGT_RX0_N</text>
<text x="76.3" y="103.1">MGT_TX0_P</text>
<text x="175.5" y="106.9">MGT_CLK1_N</text>
<text x="195.3" y="103.1">MGT_RX0_P</text>
<text x="78.4" y="109.5">1V2_MGT</text>
<text x="176" y="109.5">MGT_CLK1_P</text>
<text x="195.3" y="108.2">MGT_CLK1_N</text>
<text x="195.3" y="110.7">MGT_CLK1_P</text>
</g>
</g></defs>
<path d="M2.2 8.3h292.3v193h-292.3z" fill-rule="evenodd" fill="#fffcf8"/>
<path d="M2.2 8.3h292.3v193h-292.3z" fill="none" stroke="#000" stroke-width=".21"/>
<path d="M7.3 13.4h282.1v182.9h-282.1z" fill-rule="evenodd" fill="#fffcf8"/>
<g fill="none" stroke="#000" stroke-width=".21">
<path d="M2.2 8.3h5.1M7.3 13.4h282.1v182.9h-282.1zM75.3 8.3v5.1M148.4 8.3v5.1M221.4 8.3v5.1M289.4 8.3h5.1v5.1M2.2 56.6h5.1M289.4 56.6h5.1M2.2 104.8h5.1M289.4 104.9h5.1M2.2 153.1h5.1M289.4 153.1h5.1"/>
<path d="M289.4 176h-88.9v20.3M75.3 196.3v5M148.4 196.3v5M200.5 183.6h88.9M200.5 191.2h88.9M200.5 193.7h88.9M213.2 183.6v7.6M221.4 196.3v5M251.3 191.2v5.1M264 183.6v7.6M294.5 196.3v5"/>
</g>
<path d="M119.1 82h45.8v35.5h-45.8z" fill-rule="evenodd" fill="#ffffb0"/>
<path d="M119.1 82h45.8v35.5h-45.8z" fill="none" stroke="#800000" stroke-width=".21"/>
<path d="M111.5 115h7.6" fill="none" stroke="#000" stroke-width=".25"/>
<path d="M117.6 114.5l1.5 .5-1.5 .5z" fill="#f8fcff"/>
<path d="M117.6 114.5l1.5 .5-1.5 .5z" fill="none" stroke="#000" stroke-width=".21"/>
<path d="M164.9 112.5h7.6" fill="none" stroke="#000" stroke-width=".25"/>
<path d="M164.9 112.5l1.5-.5v1z" fill="#f8fcff"/>
<path d="M164.9 112.5l1.5-.5v1zM164.9 112l-1 .5 1 .5" fill="none" stroke="#000" stroke-width=".21"/>
<path d="M164.9 115h7.6" fill="none" stroke="#000" stroke-width=".25"/>
<path d="M164.9 115l1.5-.5v1z" fill="#f8fcff"/>
<path d="M164.9 115l1.5-.5v1zM164.9 114.5l-1 .5 1 .5" fill="none" stroke="#000" stroke-width=".21"/>
<path d="M164.9 97.2h7.6" fill="none" stroke="#000" stroke-width=".25"/>
<path d="M164.9 97.2l1.5-.5v1z" fill="#f8fcff"/>
<path d="M164.9 97.2l1.5-.5v1z" fill="none" stroke="#000" stroke-width=".21"/>
<path d="M164.9 92.1h7.6" fill="none" stroke="#000" stroke-width=".25"/>
<path d="M164.9 92.1l1.5-.5v1.1z" fill="#f8fcff"/>
<path d="M164.9 92.1l1.5-.5v1.1z" fill="none" stroke="#000" stroke-width=".21"/>
<path d="M164.9 87.1h7.6" fill="none" stroke="#000" stroke-width=".25"/>
<path d="M164.9 87.1l1.5-.5v1z" fill="#f8fcff"/>
<path d="M164.9 87.1l1.5-.5v1z" fill="none" stroke="#000" stroke-width=".21"/>
<path d="M164.9 102.3h7.6" fill="none" stroke="#000" stroke-width=".25"/>
<path d="M164.9 102.3l1.5-.5v1z" fill="#f8fcff"/>
<path d="M164.9 102.3l1.5-.5v1z" fill="none" stroke="#000" stroke-width=".21"/>
<path d="M111.5 87.1h7.6" fill="none" stroke="#000" stroke-width=".25"/>
<path d="M117.6 87.1l1.5-.5v1z" fill="#f8fcff"/>
<path d="M117.6 87.1l1.5-.5v1z" fill="none" stroke="#000" stroke-width=".21"/>
<path d="M111.5 92.1h7.6" fill="none" stroke="#000" stroke-width=".25"/>
<path d="M117.6 92.1l1.5-.5v1.1z" fill="#f8fcff"/>
<path d="M117.6 92.1l1.5-.5v1.1z" fill="none" stroke="#000" stroke-width=".21"/>
<path d="M164.9 109.9h7.6" fill="none" stroke="#000" stroke-width=".25"/>
<path d="M164.9 109.9l1.5-.5v1z" fill="#f8fcff"/>
<path d="M164.9 109.9l1.5-.5v1zM164.9 109.4l-1 .5 1 .5" fill="none" stroke="#000" stroke-width=".21"/>
<path d="M164.9 107.4h7.6" fill="none" stroke="#000" stroke-width=".25"/>
<path d="M164.9 107.4l1.5-.5v1z" fill="#f8fcff"/>
<path d="M164.9 107.4l1.5-.5v1zM164.9 106.9l-1 .5 1 .5" fill="none" stroke="#000" stroke-width=".21"/>
<path d="M164.9 94.7h7.6" fill="none" stroke="#000" stroke-width=".25"/>
<path d="M164.9 94.7l1.5-.5v1z" fill="#f8fcff"/>
<path d="M164.9 94.7l1.5-.5v1z" fill="none" stroke="#000" stroke-width=".21"/>
<path d="M164.9 89.6h7.6" fill="none" stroke="#000" stroke-width=".25"/>
<path d="M164.9 89.6l1.5-.5v1z" fill="#f8fcff"/>
<path d="M164.9 89.6l1.5-.5v1z" fill="none" stroke="#000" stroke-width=".21"/>
<path d="M164.9 84.5h7.6" fill="none" stroke="#000" stroke-width=".25"/>
<path d="M164.9 84.5l1.5-.5v1z" fill="#f8fcff"/>
<path d="M164.9 84.5l1.5-.5v1z" fill="none" stroke="#000" stroke-width=".21"/>
<path d="M164.9 99.8h7.6" fill="none" stroke="#000" stroke-width=".25"/>
<path d="M164.9 99.8l1.5-.5v1z" fill="#f8fcff"/>
<path d="M164.9 99.8l1.5-.5v1z" fill="none" stroke="#000" stroke-width=".21"/>
<path d="M111.5 84.5h7.6" fill="none" stroke="#000" stroke-width=".25"/>
<path d="M117.6 84.5l1.5-.5v1z" fill="#f8fcff"/>
<path d="M117.6 84.5l1.5-.5v1z" fill="none" stroke="#000" stroke-width=".21"/>
<path d="M111.5 89.6h7.6" fill="none" stroke="#000" stroke-width=".25"/>
<path d="M117.6 89.6l1.5-.5v1z" fill="#f8fcff"/>
<path d="M117.6 89.6l1.5-.5v1z" fill="none" stroke="#000" stroke-width=".21"/>
<path d="M111.5 97.2h7.6" fill="none" stroke="#000" stroke-width=".25"/>
<path d="M117.6 97.2l1.5-.5v1z" fill="#f8fcff"/>
<path d="M117.6 97.2l1.5-.5v1z" fill="none" stroke="#000" stroke-width=".21"/>
<path d="M111.5 94.7h7.6" fill="none" stroke="#000" stroke-width=".25"/>
<path d="M117.6 94.7l1.5-.5v1z" fill="#f8fcff"/>
<path d="M117.6 94.7l1.5-.5v1z" fill="none" stroke="#000" stroke-width=".21"/>
<path d="M111.5 102.3h7.6" fill="none" stroke="#000" stroke-width=".25"/>
<path d="M117.6 102.3l1.5-.5v1z" fill="#f8fcff"/>
<path d="M117.6 102.3l1.5-.5v1z" fill="none" stroke="#000" stroke-width=".21"/>
<path d="M111.5 99.8h7.6" fill="none" stroke="#000" stroke-width=".25"/>
<path d="M117.6 99.8l1.5-.5v1z" fill="#f8fcff"/>
<path d="M117.6 99.8l1.5-.5v1z" fill="none" stroke="#000" stroke-width=".21"/>
<path d="M171.5 111.4l2 2.1M171.5 114l2 2M173.5 111.4l-2 2.1M173.5 114l-2 2" fill="none" stroke="#f00" stroke-width=".21"/>
<path d="M93.7 115h2M101.9 115h2" fill="none" stroke="#000" stroke-width=".25"/>
<path d="M95.8 114h6v2.1h-6z" fill="none" stroke="#00f" stroke-width=".25"/>
<path d="M82.3 109.9h2.5M83.6 109.9v2.6" fill="none" stroke="#800000" stroke-width=".25"/>
<path d="M73.4 84.5l1.3-1.2h17v2.5h-17z" fill-rule="evenodd" fill="#ffff80"/>
<path d="M73.4 84.5l1.3-1.2h17v2.5h-17z" fill="none" stroke="#800000" stroke-width=".21"/>
<path d="M74.7 88.3h17v2.6h-17l-1.3-1.3z" fill-rule="evenodd" fill="#ffff80"/>
<path d="M74.7 88.3h17v2.6h-17l-1.3-1.3z" fill="none" stroke="#800000" stroke-width=".21"/>
<path d="M73.4 94.7l1.3-1.3h17v2.6h-17z" fill-rule="evenodd" fill="#ffff80"/>
<path d="M73.4 94.7l1.3-1.3h17v2.6h-17z" fill="none" stroke="#800000" stroke-width=".21"/>
<path d="M73.4 99.8l1.3-1.3h17v2.5h-17z" fill-rule="evenodd" fill="#ffff80"/>
<path d="M73.4 99.8l1.3-1.3h17v2.5h-17z" fill="none" stroke="#800000" stroke-width=".21"/>
<g fill="none" stroke="#000080" stroke-width=".25">
<path d="M91.7 84.5h19.8M91.7 87.1h19.8M91.7 89.6h19.8M91.7 92.1h19.8M91.7 94.7h19.8M91.7 97.2h19.8M91.7 99.8h19.8M172.5 84.5h20.3M172.5 87.1h20.3M172.5 89.6h20.3M172.5 94.7h20.3M172.5 97.2h20.3"/>
<path d="M172.5 99.8h20.3M172.5 92.2h20.3M83.6 112.5v2.5h10.1M91.7 102.3h19.8M103.9 115h7.6M172.5 102.3h20.3M172.5 107.4h20.3M172.5 109.9h20.3"/>
</g>
<path d="M73.4 87.1l1.3-1.3h17v2.5h-17z" fill-rule="evenodd" fill="#ffff80"/>
<path d="M73.4 87.1l1.3-1.3h17v2.5h-17z" fill="none" stroke="#800000" stroke-width=".21"/>
<path d="M73.4 92.1l1.3-1.2h17v2.5h-17z" fill-rule="evenodd" fill="#ffff80"/>
<path d="M73.4 92.1l1.3-1.2h17v2.5h-17z" fill="none" stroke="#800000" stroke-width=".21"/>
<path d="M74.7 96h17v2.5h-17l-1.3-1.3z" fill-rule="evenodd" fill="#ffff80"/>
<path d="M74.7 96h17v2.5h-17l-1.3-1.3z" fill="none" stroke="#800000" stroke-width=".21"/>
<path d="M73.4 102.3l1.3-1.3h17v2.6h-17z" fill-rule="evenodd" fill="#ffff80"/>
<path d="M73.4 102.3l1.3-1.3h17v2.6h-17z" fill="none" stroke="#800000" stroke-width=".21"/>
<path d="M192.8 84.5l1.3-1.2h19.1v2.5h-19.1z" fill-rule="evenodd" fill="#ffff80"/>
<path d="M192.8 84.5l1.3-1.2h19.1v2.5h-19.1z" fill="none" stroke="#800000" stroke-width=".21"/>
<path d="M192.8 87.1l1.3-1.3h19.1v2.5h-19.1z" fill-rule="evenodd" fill="#ffff80"/>
<path d="M192.8 87.1l1.3-1.3h19.1v2.5h-19.1z" fill="none" stroke="#800000" stroke-width=".21"/>
<path d="M194.1 88.3h19.1v2.6h-19.1l-1.3-1.3z" fill-rule="evenodd" fill="#ffff80"/>
<path d="M194.1 88.3h19.1v2.6h-19.1l-1.3-1.3z" fill="none" stroke="#800000" stroke-width=".21"/>
<path d="M192.8 92.2l1.3-1.3h19.1v2.5h-19.1z" fill-rule="evenodd" fill="#ffff80"/>
<path d="M192.8 92.2l1.3-1.3h19.1v2.5h-19.1z" fill="none" stroke="#800000" stroke-width=".21"/>
<path d="M192.8 94.7l1.3-1.3h19.1v2.6h-19.1z" fill-rule="evenodd" fill="#ffff80"/>
<path d="M192.8 94.7l1.3-1.3h19.1v2.6h-19.1z" fill="none" stroke="#800000" stroke-width=".21"/>
<path d="M194.1 96h19.1v2.5h-19.1l-1.3-1.3z" fill-rule="evenodd" fill="#ffff80"/>
<path d="M194.1 96h19.1v2.5h-19.1l-1.3-1.3z" fill="none" stroke="#800000" stroke-width=".21"/>
<path d="M192.8 99.8l1.3-1.3h19.1v2.5h-19.1z" fill-rule="evenodd" fill="#ffff80"/>
<path d="M192.8 99.8l1.3-1.3h19.1v2.5h-19.1z" fill="none" stroke="#800000" stroke-width=".21"/>
<path d="M192.8 102.3l1.3-1.3h19.1v2.6h-19.1z" fill-rule="evenodd" fill="#ffff80"/>
<path d="M192.8 102.3l1.3-1.3h19.1v2.6h-19.1z" fill="none" stroke="#800000" stroke-width=".21"/>
<path d="M192.8 107.4l1.3-1.3h19.1v2.6h-19.1z" fill-rule="evenodd" fill="#ffff80"/>
<path d="M192.8 107.4l1.3-1.3h19.1v2.6h-19.1z" fill="none" stroke="#800000" stroke-width=".21"/>
<path d="M192.8 109.9l1.3-1.2h19.1v2.5h-19.1z" fill-rule="evenodd" fill="#ffff80"/>
<path d="M192.8 109.9l1.3-1.2h19.1v2.5h-19.1z" fill="none" stroke="#800000" stroke-width=".21"/>
<use href="#words"/>
</svg>
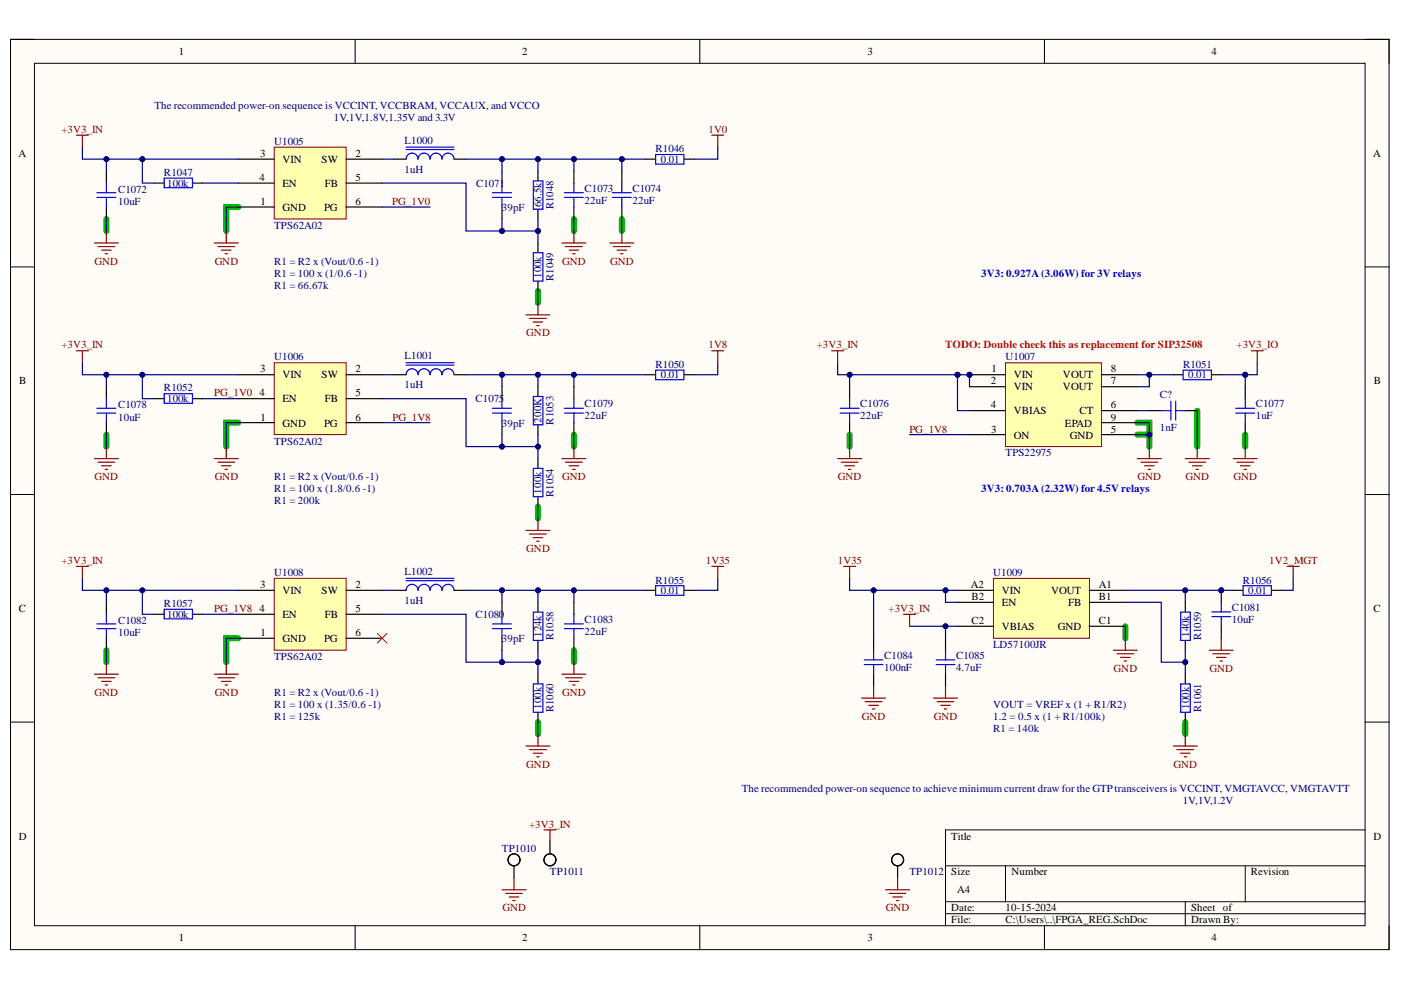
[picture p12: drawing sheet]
<svg xmlns="http://www.w3.org/2000/svg" width="297mm" height="210mm" viewBox="0 0 297 210" stroke-linecap="round" stroke-linejoin="round" font-family="sans-serif">
<defs><g id="words">
<g font-size="2.3">
<text x="37.9" y="11.7">1</text>
<text x="110.7" y="11.7">2</text>
<text x="183.9" y="11.7">3</text>
<text x="256.8" y="11.7">4</text>
<text x="3.9" y="33.3">A</text>
<text x="55.2" y="33.3">3</text>
<text x="59.9" y="34.6">VIN</text>
<text x="68.2" y="34.6">SW</text>
<text x="75.4" y="33.3">2</text>
<text x="291.1" y="33.3">A</text>
<text x="55" y="38.4">4</text>
<text x="59.9" y="39.6">EN</text>
<text x="68.9" y="39.6">FB</text>
<text x="75.4" y="38.4">5</text>
<text x="55.2" y="43.4">1</text>
<text x="59.9" y="44.7">GND</text>
<text x="68.7" y="44.7">PG</text>
<text x="75.4" y="43.4">6</text>
<text x="4.1" y="81.5">B</text>
<text x="55.2" y="78.9">3</text>
<text x="59.9" y="80.2">VIN</text>
<text x="68.2" y="80.2">SW</text>
<text x="75.4" y="78.9">2</text>
<text x="210.1" y="81.5">2</text>
<text x="210.2" y="78.9">1</text>
<text x="215" y="80.2">VIN</text>
<text x="215" y="82.7">VIN</text>
<text x="225.4" y="80.2">VOUT</text>
<text x="225.4" y="82.7">VOUT</text>
<text x="235.5" y="78.9">8</text>
<text x="235.5" y="81.5">7</text>
<text x="291.3" y="81.5">B</text>
<text x="55" y="84">4</text>
<text x="55.2" y="89.2">1</text>
<text x="59.9" y="85.3">EN</text>
<text x="68.9" y="85.3">FB</text>
<text x="75.4" y="84">5</text>
<text x="75.4" y="89.2">6</text>
<text x="210.1" y="86.6">4</text>
<text x="215" y="87.8">VBIAS</text>
<text x="228.8" y="87.8">CT</text>
<text x="235.5" y="86.6">6</text>
<text x="235.5" y="89.2">9</text>
<text x="59.9" y="90.4">GND</text>
<text x="68.7" y="90.4">PG</text>
<text x="210.1" y="91.7">3</text>
<text x="215" y="93">ON</text>
<text x="225.8" y="90.4">EPAD</text>
<text x="226.8" y="93">GND</text>
<text x="235.5" y="91.7">5</text>
<text x="55.2" y="124.7">3</text>
<text x="59.9" y="125.9">VIN</text>
<text x="68.2" y="125.9">SW</text>
<text x="75.4" y="124.7">2</text>
<text x="205.8" y="124.7">A2</text>
<text x="212.4" y="125.9">VIN</text>
<text x="222.8" y="125.9">VOUT</text>
<text x="233" y="124.7">A1</text>
<text x="4" y="129.7">C</text>
<text x="55" y="129.7">4</text>
<text x="59.9" y="131">EN</text>
<text x="68.9" y="131">FB</text>
<text x="75.4" y="129.7">5</text>
<text x="206" y="127.2">B2</text>
<text x="212.4" y="128.5">EN</text>
<text x="226.5" y="128.5">FB</text>
<text x="233" y="127.2">B1</text>
<text x="291.2" y="129.7">C</text>
<text x="55.2" y="134.8">1</text>
<text x="59.9" y="136.1">GND</text>
<text x="68.7" y="136.1">PG</text>
<text x="75.4" y="134.8">6</text>
<text x="206" y="132.3">C2</text>
<text x="212.4" y="133.6">VBIAS</text>
<text x="224.3" y="133.6">GND</text>
<text x="233" y="132.3">C1</text>
<text x="4" y="178">D</text>
<text x="201.7" y="178">Title</text>
<text x="291.2" y="178">D</text>
<text x="201.7" y="185.6">Size</text>
<text x="214.5" y="185.6">Number</text>
<text x="265.2" y="185.6">Revision</text>
<text x="203" y="189.4">A4</text>
<text x="201.7" y="193.2">Date:</text>
<text x="201.7" y="195.8">File:</text>
<text x="213.2" y="193.2">10-15-2024</text>
<text x="213.2" y="195.8">C:\Users\..\FPGA_REG.SchDoc</text>
<text x="252.5" y="193.2">Sheet of</text>
<text x="252.5" y="195.8">Drawn By:</text>
<text x="37.9" y="199.6">1</text>
<text x="110.7" y="199.6">2</text>
<text x="183.9" y="199.6">3</text>
<text x="256.8" y="199.6">4</text>
</g>
<g font-size="2.3" fill="#000080">
<text x="32.7" y="23.1">The recommended power-on sequence is VCCINT, VCCBRAM, VCCAUX, and VCCO</text>
<text x="70.8" y="25.6">1V,1V,1.8V,1.35V and 3.3V</text>
<text x="58.1" y="30.8">U1005</text>
<text x="85.8" y="30.5">L1000</text>
<text x="139" y="32.3">R1046</text>
<text x="140.1" y="34.6">0.01</text>
<text x="25" y="40.9">C1072</text>
<text x="34.8" y="37.3">R1047</text>
<text x="35.4" y="39.6">100k</text>
<text x="85.8" y="36.6">1uH</text>
<text x="100.9" y="39.6">C1071</text>
<text x="123.9" y="40.7">C1073</text>
<text x="134.1" y="40.7">C1074</text>
<text x="25" y="43.4">10uF</text>
<text x="106.4" y="44.7">39pF</text>
<text x="114.8" y="43.9" transform="rotate(-90 114.8 43.9)">66.5k</text>
<text x="117.3" y="44.4" transform="rotate(-90 117.3 44.4)">R1048</text>
<text x="123.9" y="43.2">22uF</text>
<text x="134.1" y="43.2">22uF</text>
<text x="58.1" y="48.5">TPS62A02</text>
<text x="58.1" y="56.1">R1 = R2 x (Vout/0.6 -1)</text>
<text x="58.1" y="58.7">R1 = 100 x (1/0.6 -1)</text>
<text x="114.8" y="58.9" transform="rotate(-90 114.8 58.9)">100k</text>
<text x="117.3" y="59.6" transform="rotate(-90 117.3 59.6)">R1049</text>
<text x="58.1" y="61.2">R1 = 66.67k</text>
<text x="58.1" y="76.4">U1006</text>
<text x="85.8" y="76.2">L1001</text>
<text x="213.2" y="76.4">U1007</text>
<text x="34.8" y="83">R1052</text>
<text x="85.8" y="82.2">1uH</text>
<text x="139" y="78">R1050</text>
<text x="140.1" y="80.2">0.01</text>
<text x="250.8" y="78">R1051</text>
<text x="251.9" y="80.2">0.01</text>
<text x="25" y="86.6">C1078</text>
<text x="25" y="89.2">10uF</text>
<text x="35.4" y="85.3">100k</text>
<text x="100.8" y="85.3">C1075</text>
<text x="114.8" y="89.6" transform="rotate(-90 114.8 89.6)">200K</text>
<text x="123.9" y="86.3">C1079</text>
<text x="123.9" y="88.9">22uF</text>
<text x="182.4" y="86.3">C1076</text>
<text x="182.4" y="88.9">22uF</text>
<text x="245.9" y="84.4">C?</text>
<text x="266.2" y="86.3">C1077</text>
<text x="266.2" y="88.9">1uF</text>
<text x="58.1" y="94.2">TPS62A02</text>
<text x="106.4" y="90.4">39pF</text>
<text x="117.3" y="90" transform="rotate(-90 117.3 90)">R1053</text>
<text x="245.9" y="91.4">1nF</text>
<text x="58.1" y="101.9">R1 = R2 x (Vout/0.6 -1)</text>
<text x="213.2" y="96.8">TPS22975</text>
<text x="58.1" y="104.4">R1 = 100 x (1.8/0.6 -1)</text>
<text x="58.1" y="106.9">R1 = 200k</text>
<text x="114.8" y="104.6" transform="rotate(-90 114.8 104.6)">100k</text>
<text x="117.3" y="105.3" transform="rotate(-90 117.3 105.3)">R1054</text>
<text x="58.1" y="122.1">U1008</text>
<text x="85.8" y="121.9">L1002</text>
<text x="139" y="123.7">R1055</text>
<text x="140.1" y="125.9">0.01</text>
<text x="210.6" y="122.1">U1009</text>
<text x="263.5" y="123.7">R1056</text>
<text x="264.6" y="125.9">0.01</text>
<text x="34.8" y="128.7">R1057</text>
<text x="35.4" y="131">100k</text>
<text x="85.8" y="128">1uH</text>
<text x="100.8" y="131">C1080</text>
<text x="261.2" y="129.5">C1081</text>
<text x="25" y="132.3">C1082</text>
<text x="25" y="134.8">10uF</text>
<text x="106.4" y="136.1">39pF</text>
<text x="114.8" y="135.1" transform="rotate(-90 114.8 135.1)">124k</text>
<text x="117.3" y="135.8" transform="rotate(-90 117.3 135.8)">R1058</text>
<text x="123.9" y="132">C1083</text>
<text x="123.9" y="134.6">22uF</text>
<text x="210.6" y="137.4">LD57100JR</text>
<text x="252.1" y="135.1" transform="rotate(-90 252.1 135.1)">140k</text>
<text x="254.6" y="135.8" transform="rotate(-90 254.6 135.8)">R1059</text>
<text x="261.2" y="132">10uF</text>
<text x="58.1" y="139.9">TPS62A02</text>
<text x="187.5" y="139.6">C1084</text>
<text x="187.5" y="142.2">100nF</text>
<text x="202.7" y="139.6">C1085</text>
<text x="202.7" y="142.2">4.7uF</text>
<text x="58.1" y="147.5">R1 = R2 x (Vout/0.6 -1)</text>
<text x="58.1" y="150.1">R1 = 100 x (1.35/0.6 -1)</text>
<text x="58.1" y="152.7">R1 = 125k</text>
<text x="114.8" y="150.3" transform="rotate(-90 114.8 150.3)">100k</text>
<text x="117.3" y="151.1" transform="rotate(-90 117.3 151.1)">R1060</text>
<text x="210.6" y="150.1">VOUT = VREF x (1 + R1/R2)</text>
<text x="210.6" y="152.7">1.2 = 0.5 x (1 + R1/100k)</text>
<text x="210.6" y="155.2">R1 = 140k</text>
<text x="252.1" y="150.3" transform="rotate(-90 252.1 150.3)">100k</text>
<text x="254.6" y="151" transform="rotate(-90 254.6 151)">R1061</text>
<text x="157.3" y="167.9">The recommended power-on sequence to achieve minimum current draw for the GTPtransceivers is VCCINT, VMGTAVCC, VMGTAVTT</text>
<text x="250.8" y="170.4">1V,1V,1.2V</text>
<text x="106.4" y="180.6">TP1010</text>
<text x="116.6" y="185.6">TP1011</text>
<text x="192.8" y="185.6">TP1012</text>
</g>
<g font-size="2.3" fill="#800000">
<text x="13" y="28.1">+3V3_IN</text>
<text x="150.2" y="28.1">1V0</text>
<text x="83.2" y="43.4">PG_1V0</text>
<text x="20.1" y="56.1">GND</text>
<text x="45.5" y="56.1">GND</text>
<text x="119.2" y="56.1">GND</text>
<text x="129.4" y="56.1">GND</text>
<text x="111.6" y="71.3">GND</text>
<text x="13" y="73.9">+3V3_IN</text>
<text x="150.2" y="73.9">1V8</text>
<text x="173.2" y="73.9">+3V3_IN</text>
<text x="262.2" y="73.9">+3V3_IO</text>
<text x="45.4" y="84">PG_1V0</text>
<text x="83.2" y="89.2">PG_1V8</text>
<text x="192.8" y="91.7">PG_1V8</text>
<text x="20.1" y="101.9">GND</text>
<text x="45.5" y="101.9">GND</text>
<text x="119.2" y="101.9">GND</text>
<text x="177.7" y="101.9">GND</text>
<text x="241.2" y="101.9">GND</text>
<text x="251.3" y="101.9">GND</text>
<text x="261.5" y="101.9">GND</text>
<text x="13" y="119.6">+3V3_IN</text>
<text x="111.6" y="117.1">GND</text>
<text x="149.7" y="119.6">1V35</text>
<text x="177.7" y="119.6">1V35</text>
<text x="269.1" y="119.6">1V2_MGT</text>
<text x="45.4" y="129.7">PG_1V8</text>
<text x="188.4" y="129.7">+3V3_IN</text>
<text x="236.1" y="142.4">GND</text>
<text x="256.4" y="142.4">GND</text>
<text x="20.1" y="147.5">GND</text>
<text x="45.5" y="147.5">GND</text>
<text x="119.2" y="147.5">GND</text>
<text x="182.7" y="152.7">GND</text>
<text x="198" y="152.7">GND</text>
<text x="111.6" y="162.8">GND</text>
<text x="248.8" y="162.8">GND</text>
<text x="112.2" y="175.5">+3V3_IN</text>
<text x="106.5" y="193.2">GND</text>
<text x="187.8" y="193.2">GND</text>
</g>
<g font-size="2.3" fill="#00f">
<text x="208" y="58.7">3V3: 0.927A(3.06W) for 3V relays</text>
<text x="208" y="104.4">3V3: 0.703A(2.32W) for 4.5V relays</text>
</g>
<text font-size="2.3" fill="#f00" x="200.4" y="73.9">TODO: Double check this as replacement for SIP32508</text>
</g></defs>
<path d="M2.2 8.3h292.3v193h-292.3z" fill-rule="evenodd" fill="#fffcf8"/>
<path d="M2.2 8.3h292.3v193h-292.3z" fill="none" stroke="#000" stroke-width=".21"/>
<path d="M7.3 13.4h282.1v182.9h-282.1z" fill-rule="evenodd" fill="#fffcf8"/>
<g fill="none" stroke="#000" stroke-width=".21">
<path d="M2.2 8.3h5.1M7.3 13.4h282.1v182.9h-282.1zM75.3 8.3v5.1M148.4 8.3v5.1M221.4 8.3v5.1M289.4 8.3h5.1v5.1M2.2 56.6h5.1M289.4 56.6h5.1M2.2 104.8h5.1M289.4 104.9h5.1M2.2 153.1h5.1M289.4 153.1h5.1"/>
<path d="M289.4 176h-88.9v20.3M75.3 196.3v5M148.4 196.3v5M200.5 183.6h88.9M200.5 191.2h88.9M200.5 193.7h88.9M213.2 183.6v7.6M221.4 196.3v5M251.3 191.2v5.1M264 183.6v7.6M294.5 196.3v5"/>
</g>
<g fill="none" stroke="#00be00" stroke-width="1.3">
<path d="M22.6 46.4v2.6M50.5 43.9h-2.5v5.1M121.7 46.4v2.6M131.8 46.4v2.6M114.1 61.7v2.5M22.6 92.1v2.6M50.5 89.6h-2.5v5.1M121.7 92.1v2.6M180.1 92.2v2.5M241.1 92.2h2.6v2.5M241.1 89.6h2.6v2.6M253.8 87.1v7.6"/>
<path d="M264 92.2v2.5M114.1 107.4v2.5M22.6 137.9v2.5M50.5 135.3h-2.5v5.1M121.7 137.9v2.5M238.6 132.8v2.5M114.1 153.1v2.5M251.3 153.1v2.5"/>
</g>
<path d="M272.9 120.1h2.5M274.2 120.1v2.5" fill="none" stroke="#800000" stroke-width=".25"/>
<path d="M210.6 122.6h20.4v12.7h-20.4z" fill-rule="evenodd" fill="#ffffb0"/>
<path d="M210.6 122.6h20.4v12.7h-20.4z" fill="none" stroke="#800000" stroke-width=".21"/>
<path d="M200.5 135.3v2.6M203 125.2h7.6M203 127.7h7.6M203 132.8h7.6M231 125.2h7.6M231 127.7h7.6M231 132.8h7.6M200.5 142.9v2.6" fill="none" stroke="#000" stroke-width=".25"/>
<path d="M178.9 120.1h2.5M180.1 120.1v2.5M236.1 137.9h5M236.8 138.6h3.6M237.6 139.4h2M238.6 135.3v2.6M197.9 148h5.1M198.7 148.8h3.5M199.5 149.5h2M200.2 150.3h.5M200.5 145.5v2.5M238.3 140.1h.5" fill="none" stroke="#800000" stroke-width=".25"/>
<path d="M198.5 139.9h4M200.5 137.9v2M198.5 140.9h4M200.5 140.9v2" fill="none" stroke="#00f" stroke-width=".25"/>
<circle cx="258.9" cy="125.2" r=".51" fill="#000080"/>
<circle cx="258.9" cy="125.2" r=".51" fill="none" stroke="#000080" stroke-width=".21"/>
<path d="M258.9 125.2v2.5M258.9 132.8v2.5" fill="none" stroke="#000" stroke-width=".25"/>
<circle cx="258.9" cy="125.2" r=".51" fill="#000080"/>
<circle cx="258.9" cy="125.2" r=".51" fill="none" stroke="#000080" stroke-width=".21"/>
<path d="M183.2 139.9h4M185.2 137.9v2M250.3 129.8h2.1v6h-2.1zM256.9 130.7h4M256.9 129.7h4M258.9 127.7v2M258.9 130.7v2.1M263.5 124.2h6.1v2h-6.1zM183.2 140.9h4M185.2 140.9v2M250.3 145h2.1v6h-2.1z" fill="none" stroke="#00f" stroke-width=".25"/>
<g fill="none" stroke="#800000" stroke-width=".25">
<path d="M256.4 137.9h5.1M257.2 138.6h3.5M257.9 139.4h2M258.9 135.3v2.6M182.7 148h5.1M183.4 148.8h3.6M184.2 149.5h2M185 150.3h.5M185.2 145.5v2.5M248.8 158.2h5M249.5 158.9h3.6M250.3 159.7h2"/>
<path d="M251.3 155.6v2.6M258.7 140.1h.5M251 160.5h.6"/>
</g>
<path d="M185.2 135.3v2.6M251.3 127.7v2M251.3 135.9v2M261.5 125.2h2M269.6 125.2h2M185.2 142.9v2.6M251.3 142.9v2M251.3 151.1v2" fill="none" stroke="#000" stroke-width=".25"/>
<path d="M58.1 31.2h15.3v15.2h-15.3z" fill-rule="evenodd" fill="#ffffb0"/>
<path d="M58.1 31.2h15.3v15.2h-15.3z" fill="none" stroke="#800000" stroke-width=".21"/>
<g fill="none" stroke="#000" stroke-width=".25">
<path d="M22.6 36.3v2.5M32.7 38.8h2M40.9 38.8h2M50.5 33.7h7.6M50.5 38.8h7.6M73.4 33.7h7.6M73.4 38.8h7.6M83.6 33.7h2.5M96.3 33.7h2.5M106.4 36.3v2.5M114.1 36.3v2M121.7 36.3v2.5"/>
<path d="M131.8 36.3v2.5M136.9 33.7h2M145.1 33.7h2M22.6 43.9v2.5M50.5 43.9h7.6M73.4 43.9h7.6M106.4 43.9v2.5M114.1 44.4v2M114.1 51.5v2M114.1 59.7v2M121.7 43.9v2.5M131.8 43.9v2.5"/>
</g>
<g fill="none" stroke="#800000" stroke-width=".25">
<path d="M16.2 28.7h2.5M17.5 28.7v2.5M150.9 28.7h2.5M152.2 28.7v2.5M20 51.5h5.1M20.8 52.3h3.5M21.5 53h2.1M22.3 53.8h.5M22.6 49v2.5M45.4 51.5h5.1M46.2 52.3h3.5M47 53h2"/>
<path d="M47.7 53.8h.5M48 49v2.5M119.1 51.5h5.1M119.9 52.3h3.6M120.7 53h2M121.4 53.8h.5M121.7 49v2.5M129.3 51.5h5.1M130.1 52.3h3.5M130.8 53h2.1M131.6 53.8h.5M131.8 49v2.5"/>
<path d="M111.5 66.8h5.1M112.3 67.5h3.5M113 68.3h2.1M113.8 69h.5M114.1 64.2v2.6"/>
</g>
<g fill="none" stroke="#00f" stroke-width=".25">
<path d="M22.6 38.8v2.1M34.8 37.8h6v2h-6zM86.1 33.7a1.27 1.27 0 0 1 1.3-1.2 1.27 1.27 0 0 1 1.2 1.2 1.27 1.27 0 0 1 1.3-1.2 1.27 1.27 0 0 1 1.3 1.2 1.27 1.27 0 0 1 1.3-1.2 1.27 1.27 0 0 1 1.2 1.2 1.27 1.27 0 0 1 1.3-1.2 1.27 1.27 0 0 1 1.3 1.2M86.1 31.7h10.2M86.1 31.2h10.2M106.4 38.8v2.1M113.1 38.4h2v6h-2zM121.7 38.8v2.1M131.8 38.8v2.1M139 32.8h6v2h-6zM20.6 41.9h4M20.6 40.9h4"/>
<path d="M22.6 41.9v2M104.4 41.9h4M104.4 40.9h4M106.4 41.9v2M113.1 53.6h2v6h-2zM119.7 41.9h4M119.7 40.9h4M121.7 41.9v2M129.8 41.9h4M129.8 40.9h4M131.8 41.9v2"/>
</g>
<path d="M58.1 122.6h15.3v15.3h-15.3z" fill-rule="evenodd" fill="#ffffb0"/>
<path d="M58.1 122.6h15.3v15.3h-15.3z" fill="none" stroke="#800000" stroke-width=".21"/>
<g fill="none" stroke="#000" stroke-width=".25">
<path d="M22.6 127.7v2.5M22.6 135.3v2.6M32.7 130.2h2M40.9 130.2h2M50.5 125.2h7.6M50.5 135.3h7.6M50.5 130.2h7.6M73.4 125.2h7.6M73.4 135.3h7.6M73.4 130.2h7.6M83.6 125.2h2.5M96.3 125.2h2.5"/>
<path d="M106.4 127.7v2.5M106.4 135.3v2.6M114.1 127.7v2M114.1 135.9v2M121.7 127.7v2.5M121.7 135.3v2.6M136.9 125.2h2M145.1 125.2h2M114.1 142.9v2M114.1 151.1v2"/>
</g>
<g fill="none" stroke="#800000" stroke-width=".25">
<path d="M16.2 120.1h2.5M17.5 120.1v2.5M150.9 120.1h2.5M152.2 120.1v2.5M20 142.9h5.1M20.8 143.7h3.5M21.5 144.5h2.1M22.3 145.2h.5M22.6 140.4v2.5M45.4 142.9h5.1M46.2 143.7h3.5M47 144.5h2"/>
<path d="M47.7 145.2h.5M48 140.4v2.5M111.5 158.2h5.1M112.3 158.9h3.5M113 159.7h2.1M114.1 155.6v2.6M119.1 142.9h5.1M119.9 143.7h3.6M120.7 144.5h2M121.4 145.2h.5M121.7 140.4v2.5M113.8 160.5h.5"/>
</g>
<g fill="none" stroke="#00f" stroke-width=".25">
<path d="M20.6 133.3h4M20.6 132.3h4M22.6 130.2v2.1M22.6 133.3v2M34.8 129.2h6v2h-6zM86.1 125.2a1.27 1.27 0 0 1 1.3-1.3 1.27 1.27 0 0 1 1.2 1.3 1.27 1.27 0 0 1 1.3-1.3 1.27 1.27 0 0 1 1.3 1.3 1.27 1.27 0 0 1 1.3-1.3 1.27 1.27 0 0 1 1.2 1.3 1.27 1.27 0 0 1 1.3-1.3 1.27 1.27 0 0 1 1.3 1.3M86.1 123.1h10.2M86.1 122.6h10.2M104.4 133.3h4M104.4 132.3h4M106.4 130.2v2.1M106.4 133.3v2"/>
<path d="M113.1 129.8h2v6h-2zM119.7 133.3h4M119.7 132.3h4M121.7 130.2v2.1M121.7 133.3v2M139 124.2h6v2h-6zM113.1 145h2v6h-2z"/>
</g>
<path d="M58.1 76.9h15.3v15.2h-15.3z" fill-rule="evenodd" fill="#ffffb0"/>
<path d="M58.1 76.9h15.3v15.2h-15.3z" fill="none" stroke="#800000" stroke-width=".21"/>
<g fill="none" stroke="#000" stroke-width=".25">
<path d="M50.5 79.5h7.6M73.4 79.5h7.6M83.6 79.5h2.5M96.3 79.5h2.5M136.9 79.5h2M145.1 79.5h2M22.6 82v2.5M22.6 89.6v2.5M32.7 84.5h2M40.9 84.5h2M50.5 89.6h7.6M50.5 84.5h7.6"/>
<path d="M73.4 89.6h7.6M73.4 84.5h7.6M106.4 82v2.5M106.4 89.6v2.5M114.1 82v2M114.1 90.2v1.9M114.1 97.2v2M121.7 82v2.5M121.7 89.6v2.5M114.1 105.4v2M116.6 178.5v2.5M109 183.6v2.5"/>
<path d="M190.3 183.6v2.5"/>
<circle cx="109" cy="182.3" r="1.27"/>
<circle cx="116.6" cy="182.3" r="1.27"/>
<circle cx="190.3" cy="182.3" r="1.27"/>
</g>
<g fill="none" stroke="#800000" stroke-width=".25">
<path d="M16.2 74.4h2.5M17.5 74.4v2.5M150.9 74.4h2.5M152.2 74.4v2.5M20 97.2h5.1M20.8 98h3.5M21.5 98.8h2.1M22.3 99.5h.5M22.6 94.7v2.5M45.4 97.2h5.1M46.2 98h3.5M47 98.8h2"/>
<path d="M47.7 99.5h.5M48 94.7v2.5M119.1 97.2h5.1M119.9 98h3.6M120.7 98.8h2M121.4 99.5h.5M121.7 94.7v2.5M111.5 112.5h5.1M112.3 113.2h3.5M113 114h2.1M113.8 114.7h.5M114.1 109.9v2.6"/>
<path d="M191.6 130.2h2.5M192.8 130.2v2.6M115.3 176h2.6M116.6 176v2.5M106.4 188.7h5.1M107.2 189.4h3.6M108 190.2h2M108.7 190.9h.5M109 186.1v2.6M187.8 188.7h5M188.5 189.4h3.6M189.3 190.2h2"/>
<path d="M190.1 190.9h.5M190.3 186.1v2.6"/>
</g>
<g fill="none" stroke="#00f" stroke-width=".25">
<path d="M86.1 79.5a1.27 1.27 0 0 1 1.3-1.3 1.27 1.27 0 0 1 1.2 1.3 1.27 1.27 0 0 1 1.3-1.3 1.27 1.27 0 0 1 1.3 1.3 1.27 1.27 0 0 1 1.3-1.3 1.27 1.27 0 0 1 1.2 1.3 1.27 1.27 0 0 1 1.3-1.3 1.27 1.27 0 0 1 1.3 1.3M86.1 77.4h10.2M86.1 76.9h10.2M139 78.5h6v2h-6zM20.6 87.6h4M20.6 86.6h4M22.6 84.5v2.1M22.6 87.6v2M34.8 83.5h6v2h-6zM104.4 87.6h4M104.4 86.6h4M106.4 84.5v2.1"/>
<path d="M106.4 87.6v2M113.1 99.3h2v6h-2zM113.1 84.1h2v6h-2zM119.7 87.6h4M119.7 86.6h4M121.7 84.5v2.1M121.7 87.6v2"/>
</g>
<path d="M80 134.3l2 2M82 134.3l-2 2" fill="none" stroke="#f00" stroke-width=".21"/>
<circle cx="205.6" cy="79.5" r=".51" fill="#000080"/>
<circle cx="205.6" cy="79.5" r=".51" fill="none" stroke="#000080" stroke-width=".21"/>
<path d="M213.2 76.9h20.3v17.8h-20.3z" fill-rule="evenodd" fill="#ffffb0"/>
<path d="M213.2 76.9h20.3v17.8h-20.3z" fill="none" stroke="#800000" stroke-width=".21"/>
<path d="M205.6 79.5h7.6M233.5 79.5h7.6M205.6 92.2h7.6M233.5 82h7.6M233.5 92.2h7.6" fill="none" stroke="#000" stroke-width=".25"/>
<circle cx="205.6" cy="79.5" r=".51" fill="#000080"/>
<circle cx="205.6" cy="79.5" r=".51" fill="none" stroke="#000080" stroke-width=".21"/>
<path d="M248.8 79.5h2M256.9 79.5h2M180.1 82v2.5M180.1 89.6v2.6M205.6 82h7.6M205.6 87.1h7.6M233.5 87.1h7.6M233.5 89.6h7.6M243.7 87.1h2.5M251.3 87.1h2.5M264 82v2.5M264 89.6v2.6" fill="none" stroke="#000" stroke-width=".25"/>
<g fill="none" stroke="#800000" stroke-width=".25">
<path d="M176.3 74.4h2.6M177.6 74.4v2.5M265.3 74.4h2.5M266.6 74.4v2.5M177.6 97.2h5.1M178.4 98h3.5M179.1 98.8h2.1M179.9 99.5h.5M180.1 94.7v2.5M241.1 97.2h5.1M241.9 98h3.6M242.7 98.8h2"/>
<path d="M243.4 99.5h.5M243.7 94.7v2.5M251.3 97.2h5.1M252.1 98h3.5M252.8 98.8h2.1M253.6 99.5h.5M253.8 94.7v2.5M261.5 97.2h5.1M262.2 98h3.6M263 98.8h2M263.8 99.5h.5M264 94.7v2.5"/>
</g>
<g fill="none" stroke="#00f" stroke-width=".25">
<path d="M250.8 78.5h6v2h-6zM178.1 87.6h4M178.1 86.6h4M180.1 84.5v2.1M180.1 87.6v2M246.2 87.1h2.1M248.3 85.1v4M249.3 87.1h2M249.3 85.1v4M262 87.6h4M262 86.6h4M264 84.5v2.1"/>
<path d="M264 87.6v2"/>
</g>
<path d="M238.6 125.2h22.9M238.6 132.8v2.5" fill="none" stroke="#000080" stroke-width=".25"/>
<circle cx="251.3" cy="125.2" r=".51" fill="#000080"/>
<circle cx="251.3" cy="125.2" r=".51" fill="none" stroke="#000080" stroke-width=".21"/>
<circle cx="258.9" cy="125.2" r=".51" fill="#000080"/>
<circle cx="258.9" cy="125.2" r=".51" fill="none" stroke="#000080" stroke-width=".21"/>
<path d="M203 132.8h-2.5v2.5M274.2 122.6v2.6h-2.6" fill="none" stroke="#000080" stroke-width=".25"/>
<circle cx="200.5" cy="132.8" r=".51" fill="#000080"/>
<circle cx="200.5" cy="132.8" r=".51" fill="none" stroke="#000080" stroke-width=".21"/>
<path d="M251.3 137.9v2.5M251.3 153.1v2.5" fill="none" stroke="#000080" stroke-width=".25"/>
<circle cx="251.3" cy="140.4" r=".51" fill="#000080"/>
<circle cx="251.3" cy="140.4" r=".51" fill="none" stroke="#000080" stroke-width=".21"/>
<path d="M251.3 125.2v2.5" fill="none" stroke="#000080" stroke-width=".25"/>
<circle cx="251.3" cy="125.2" r=".51" fill="#000080"/>
<circle cx="251.3" cy="125.2" r=".51" fill="none" stroke="#000080" stroke-width=".21"/>
<path d="M238.6 127.7h7.6v12.7h5.1v2.5" fill="none" stroke="#000080" stroke-width=".25"/>
<circle cx="251.3" cy="140.4" r=".51" fill="#000080"/>
<circle cx="251.3" cy="140.4" r=".51" fill="none" stroke="#000080" stroke-width=".21"/>
<path d="M81 33.7h2.6M114.1 33.7v2.6M22.6 46.4v2.6M50.5 43.9h-2.5v5.1M121.7 46.4v2.6" fill="none" stroke="#000080" stroke-width=".25"/>
<circle cx="114.1" cy="33.7" r=".51" fill="#000080"/>
<circle cx="114.1" cy="33.7" r=".51" fill="none" stroke="#000080" stroke-width=".21"/>
<path d="M106.4 33.7v2.6" fill="none" stroke="#000080" stroke-width=".25"/>
<circle cx="106.4" cy="33.7" r=".51" fill="#000080"/>
<circle cx="106.4" cy="33.7" r=".51" fill="none" stroke="#000080" stroke-width=".21"/>
<path d="M106.4 46.4v2.6M114.1 61.7v2.5" fill="none" stroke="#000080" stroke-width=".25"/>
<circle cx="106.4" cy="49" r=".51" fill="#000080"/>
<circle cx="106.4" cy="49" r=".51" fill="none" stroke="#000080" stroke-width=".21"/>
<path d="M131.8 33.7v2.6M131.8 46.4v2.6" fill="none" stroke="#000080" stroke-width=".25"/>
<circle cx="131.8" cy="33.7" r=".51" fill="#000080"/>
<circle cx="131.8" cy="33.7" r=".51" fill="none" stroke="#000080" stroke-width=".21"/>
<path d="M17.5 31.2v2.5h5.1M152.2 31.2v2.5h-5.1M81 43.9h10.2" fill="none" stroke="#000080" stroke-width=".25"/>
<circle cx="22.6" cy="33.7" r=".51" fill="#000080"/>
<circle cx="22.6" cy="33.7" r=".51" fill="none" stroke="#000080" stroke-width=".21"/>
<path d="M42.9 38.8h7.6M22.6 137.9v2.5M50.5 135.3h-2.5v5.1M81 125.2h2.6M114.1 125.2v2.5M121.7 137.9v2.5" fill="none" stroke="#000080" stroke-width=".25"/>
<circle cx="114.1" cy="125.2" r=".51" fill="#000080"/>
<circle cx="114.1" cy="125.2" r=".51" fill="none" stroke="#000080" stroke-width=".21"/>
<path d="M106.4 125.2v2.5" fill="none" stroke="#000080" stroke-width=".25"/>
<circle cx="106.4" cy="125.2" r=".51" fill="#000080"/>
<circle cx="106.4" cy="125.2" r=".51" fill="none" stroke="#000080" stroke-width=".21"/>
<path d="M106.4 137.9v2.5M114.1 153.1v2.5" fill="none" stroke="#000080" stroke-width=".25"/>
<circle cx="106.4" cy="140.4" r=".51" fill="#000080"/>
<circle cx="106.4" cy="140.4" r=".51" fill="none" stroke="#000080" stroke-width=".21"/>
<path d="M17.5 122.6v2.6h5.1M152.2 122.6v2.6h-5.1" fill="none" stroke="#000080" stroke-width=".25"/>
<circle cx="22.6" cy="125.2" r=".51" fill="#000080"/>
<circle cx="22.6" cy="125.2" r=".51" fill="none" stroke="#000080" stroke-width=".21"/>
<path d="M30.2 33.7v5.1h2.5" fill="none" stroke="#000080" stroke-width=".25"/>
<circle cx="30.2" cy="33.7" r=".51" fill="#000080"/>
<circle cx="30.2" cy="33.7" r=".51" fill="none" stroke="#000080" stroke-width=".21"/>
<path d="M30.2 125.2v5h2.5M42.9 130.2h7.6" fill="none" stroke="#000080" stroke-width=".25"/>
<circle cx="30.2" cy="125.2" r=".51" fill="#000080"/>
<circle cx="30.2" cy="125.2" r=".51" fill="none" stroke="#000080" stroke-width=".21"/>
<path d="M50.5 33.7h-27.9v2.6" fill="none" stroke="#000080" stroke-width=".25"/>
<circle cx="30.2" cy="33.7" r=".51" fill="#000080"/>
<circle cx="30.2" cy="33.7" r=".51" fill="none" stroke="#000080" stroke-width=".21"/>
<circle cx="22.6" cy="33.7" r=".51" fill="#000080"/>
<circle cx="22.6" cy="33.7" r=".51" fill="none" stroke="#000080" stroke-width=".21"/>
<path d="M81 38.8h17.8v10.2h15.3" fill="none" stroke="#000080" stroke-width=".25"/>
<circle cx="114.1" cy="49" r=".51" fill="#000080"/>
<circle cx="114.1" cy="49" r=".51" fill="none" stroke="#000080" stroke-width=".21"/>
<circle cx="106.4" cy="49" r=".51" fill="#000080"/>
<circle cx="106.4" cy="49" r=".51" fill="none" stroke="#000080" stroke-width=".21"/>
<path d="M98.8 33.7h22.9v2.6" fill="none" stroke="#000080" stroke-width=".25"/>
<circle cx="121.7" cy="33.7" r=".51" fill="#000080"/>
<circle cx="121.7" cy="33.7" r=".51" fill="none" stroke="#000080" stroke-width=".21"/>
<circle cx="114.1" cy="33.7" r=".51" fill="#000080"/>
<circle cx="114.1" cy="33.7" r=".51" fill="none" stroke="#000080" stroke-width=".21"/>
<circle cx="106.4" cy="33.7" r=".51" fill="#000080"/>
<circle cx="106.4" cy="33.7" r=".51" fill="none" stroke="#000080" stroke-width=".21"/>
<path d="M121.7 125.2h15.2" fill="none" stroke="#000080" stroke-width=".25"/>
<circle cx="121.7" cy="125.2" r=".51" fill="#000080"/>
<circle cx="121.7" cy="125.2" r=".51" fill="none" stroke="#000080" stroke-width=".21"/>
<path d="M121.7 33.7h15.2" fill="none" stroke="#000080" stroke-width=".25"/>
<circle cx="121.7" cy="33.7" r=".51" fill="#000080"/>
<circle cx="121.7" cy="33.7" r=".51" fill="none" stroke="#000080" stroke-width=".21"/>
<circle cx="131.8" cy="33.7" r=".51" fill="#000080"/>
<circle cx="131.8" cy="33.7" r=".51" fill="none" stroke="#000080" stroke-width=".21"/>
<path d="M114.1 46.4v5.1" fill="none" stroke="#000080" stroke-width=".25"/>
<circle cx="114.1" cy="49" r=".51" fill="#000080"/>
<circle cx="114.1" cy="49" r=".51" fill="none" stroke="#000080" stroke-width=".21"/>
<path d="M50.5 125.2h-27.9v2.5" fill="none" stroke="#000080" stroke-width=".25"/>
<circle cx="30.2" cy="125.2" r=".51" fill="#000080"/>
<circle cx="30.2" cy="125.2" r=".51" fill="none" stroke="#000080" stroke-width=".21"/>
<circle cx="22.6" cy="125.2" r=".51" fill="#000080"/>
<circle cx="22.6" cy="125.2" r=".51" fill="none" stroke="#000080" stroke-width=".21"/>
<path d="M81 130.2h17.8v10.2h15.3" fill="none" stroke="#000080" stroke-width=".25"/>
<circle cx="114.1" cy="140.4" r=".51" fill="#000080"/>
<circle cx="114.1" cy="140.4" r=".51" fill="none" stroke="#000080" stroke-width=".21"/>
<circle cx="106.4" cy="140.4" r=".51" fill="#000080"/>
<circle cx="106.4" cy="140.4" r=".51" fill="none" stroke="#000080" stroke-width=".21"/>
<path d="M98.8 125.2h22.9v2.5" fill="none" stroke="#000080" stroke-width=".25"/>
<circle cx="121.7" cy="125.2" r=".51" fill="#000080"/>
<circle cx="121.7" cy="125.2" r=".51" fill="none" stroke="#000080" stroke-width=".21"/>
<circle cx="114.1" cy="125.2" r=".51" fill="#000080"/>
<circle cx="114.1" cy="125.2" r=".51" fill="none" stroke="#000080" stroke-width=".21"/>
<circle cx="106.4" cy="125.2" r=".51" fill="#000080"/>
<circle cx="106.4" cy="125.2" r=".51" fill="none" stroke="#000080" stroke-width=".21"/>
<path d="M114.1 137.9v5" fill="none" stroke="#000080" stroke-width=".25"/>
<circle cx="114.1" cy="140.4" r=".51" fill="#000080"/>
<circle cx="114.1" cy="140.4" r=".51" fill="none" stroke="#000080" stroke-width=".21"/>
<path d="M81 79.5h2.6M114.1 79.5v2.5M22.6 92.1v2.6M50.5 89.6h-2.5v5.1M121.7 92.1v2.6" fill="none" stroke="#000080" stroke-width=".25"/>
<circle cx="114.1" cy="79.5" r=".51" fill="#000080"/>
<circle cx="114.1" cy="79.5" r=".51" fill="none" stroke="#000080" stroke-width=".21"/>
<path d="M106.4 79.5v2.5" fill="none" stroke="#000080" stroke-width=".25"/>
<circle cx="106.4" cy="79.5" r=".51" fill="#000080"/>
<circle cx="106.4" cy="79.5" r=".51" fill="none" stroke="#000080" stroke-width=".21"/>
<path d="M106.4 92.1v2.6M114.1 107.4v2.5" fill="none" stroke="#000080" stroke-width=".25"/>
<circle cx="106.4" cy="94.7" r=".51" fill="#000080"/>
<circle cx="106.4" cy="94.7" r=".51" fill="none" stroke="#000080" stroke-width=".21"/>
<path d="M17.5 76.9v2.6h5.1M152.2 76.9v2.6h-5.1M81 89.6h10.2" fill="none" stroke="#000080" stroke-width=".25"/>
<circle cx="22.6" cy="79.5" r=".51" fill="#000080"/>
<circle cx="22.6" cy="79.5" r=".51" fill="none" stroke="#000080" stroke-width=".21"/>
<path d="M30.2 79.5v5h2.5M42.9 84.5h7.6" fill="none" stroke="#000080" stroke-width=".25"/>
<circle cx="30.2" cy="79.5" r=".51" fill="#000080"/>
<circle cx="30.2" cy="79.5" r=".51" fill="none" stroke="#000080" stroke-width=".21"/>
<path d="M121.7 79.5h15.2" fill="none" stroke="#000080" stroke-width=".25"/>
<circle cx="121.7" cy="79.5" r=".51" fill="#000080"/>
<circle cx="121.7" cy="79.5" r=".51" fill="none" stroke="#000080" stroke-width=".21"/>
<path d="M50.5 79.5h-27.9v2.5" fill="none" stroke="#000080" stroke-width=".25"/>
<circle cx="30.2" cy="79.5" r=".51" fill="#000080"/>
<circle cx="30.2" cy="79.5" r=".51" fill="none" stroke="#000080" stroke-width=".21"/>
<circle cx="22.6" cy="79.5" r=".51" fill="#000080"/>
<circle cx="22.6" cy="79.5" r=".51" fill="none" stroke="#000080" stroke-width=".21"/>
<path d="M81 84.5h17.8v10.2h15.3" fill="none" stroke="#000080" stroke-width=".25"/>
<circle cx="114.1" cy="94.7" r=".51" fill="#000080"/>
<circle cx="114.1" cy="94.7" r=".51" fill="none" stroke="#000080" stroke-width=".21"/>
<circle cx="106.4" cy="94.7" r=".51" fill="#000080"/>
<circle cx="106.4" cy="94.7" r=".51" fill="none" stroke="#000080" stroke-width=".21"/>
<path d="M98.8 79.5h22.9v2.5" fill="none" stroke="#000080" stroke-width=".25"/>
<circle cx="121.7" cy="79.5" r=".51" fill="#000080"/>
<circle cx="121.7" cy="79.5" r=".51" fill="none" stroke="#000080" stroke-width=".21"/>
<circle cx="114.1" cy="79.5" r=".51" fill="#000080"/>
<circle cx="114.1" cy="79.5" r=".51" fill="none" stroke="#000080" stroke-width=".21"/>
<circle cx="106.4" cy="79.5" r=".51" fill="#000080"/>
<circle cx="106.4" cy="79.5" r=".51" fill="none" stroke="#000080" stroke-width=".21"/>
<path d="M114.1 92.1v5.1" fill="none" stroke="#000080" stroke-width=".25"/>
<circle cx="114.1" cy="94.7" r=".51" fill="#000080"/>
<circle cx="114.1" cy="94.7" r=".51" fill="none" stroke="#000080" stroke-width=".21"/>
<path d="M200.5 125.2v2.5h2.5" fill="none" stroke="#000080" stroke-width=".25"/>
<circle cx="200.5" cy="125.2" r=".51" fill="#000080"/>
<circle cx="200.5" cy="125.2" r=".51" fill="none" stroke="#000080" stroke-width=".21"/>
<path d="M192.8 132.8h7.7" fill="none" stroke="#000080" stroke-width=".25"/>
<circle cx="200.5" cy="132.8" r=".51" fill="#000080"/>
<circle cx="200.5" cy="132.8" r=".51" fill="none" stroke="#000080" stroke-width=".21"/>
<path d="M180.1 122.6v2.6h22.9" fill="none" stroke="#000080" stroke-width=".25"/>
<circle cx="185.2" cy="125.2" r=".51" fill="#000080"/>
<circle cx="185.2" cy="125.2" r=".51" fill="none" stroke="#000080" stroke-width=".21"/>
<circle cx="200.5" cy="125.2" r=".51" fill="#000080"/>
<circle cx="200.5" cy="125.2" r=".51" fill="none" stroke="#000080" stroke-width=".21"/>
<path d="M185.2 125.2v10.1" fill="none" stroke="#000080" stroke-width=".25"/>
<circle cx="185.2" cy="125.2" r=".51" fill="#000080"/>
<circle cx="185.2" cy="125.2" r=".51" fill="none" stroke="#000080" stroke-width=".21"/>
<path d="M241.1 92.2h2.6v2.5" fill="none" stroke="#000080" stroke-width=".25"/>
<circle cx="243.7" cy="92.2" r=".51" fill="#000080"/>
<circle cx="243.7" cy="92.2" r=".51" fill="none" stroke="#000080" stroke-width=".21"/>
<path d="M203 79.5v7.6h2.6" fill="none" stroke="#000080" stroke-width=".25"/>
<circle cx="203" cy="79.5" r=".51" fill="#000080"/>
<circle cx="203" cy="79.5" r=".51" fill="none" stroke="#000080" stroke-width=".21"/>
<path d="M264 79.5v2.5M241.1 87.1h2.6M253.8 87.1v7.6M264 92.2v2.5" fill="none" stroke="#000080" stroke-width=".25"/>
<circle cx="264" cy="79.5" r=".51" fill="#000080"/>
<circle cx="264" cy="79.5" r=".51" fill="none" stroke="#000080" stroke-width=".21"/>
<path d="M241.1 79.5h2.6" fill="none" stroke="#000080" stroke-width=".25"/>
<circle cx="243.7" cy="79.5" r=".51" fill="#000080"/>
<circle cx="243.7" cy="79.5" r=".51" fill="none" stroke="#000080" stroke-width=".21"/>
<path d="M180.1 79.5v2.5M180.1 92.2v2.5" fill="none" stroke="#000080" stroke-width=".25"/>
<circle cx="180.1" cy="79.5" r=".51" fill="#000080"/>
<circle cx="180.1" cy="79.5" r=".51" fill="none" stroke="#000080" stroke-width=".21"/>
<path d="M203 79.5h2.6v2.5" fill="none" stroke="#000080" stroke-width=".25"/>
<circle cx="203" cy="79.5" r=".51" fill="#000080"/>
<circle cx="203" cy="79.5" r=".51" fill="none" stroke="#000080" stroke-width=".21"/>
<circle cx="205.6" cy="79.5" r=".51" fill="#000080"/>
<circle cx="205.6" cy="79.5" r=".51" fill="none" stroke="#000080" stroke-width=".21"/>
<path d="M241.1 89.6h2.6v2.6" fill="none" stroke="#000080" stroke-width=".25"/>
<circle cx="243.7" cy="92.2" r=".51" fill="#000080"/>
<circle cx="243.7" cy="92.2" r=".51" fill="none" stroke="#000080" stroke-width=".21"/>
<path d="M177.6 76.9v2.6h25.4" fill="none" stroke="#000080" stroke-width=".25"/>
<circle cx="180.1" cy="79.5" r=".51" fill="#000080"/>
<circle cx="180.1" cy="79.5" r=".51" fill="none" stroke="#000080" stroke-width=".21"/>
<circle cx="203" cy="79.5" r=".51" fill="#000080"/>
<circle cx="203" cy="79.5" r=".51" fill="none" stroke="#000080" stroke-width=".21"/>
<path d="M248.8 79.5h-5.1v2.5h-2.6M192.8 92.2h12.8" fill="none" stroke="#000080" stroke-width=".25"/>
<circle cx="243.7" cy="79.5" r=".51" fill="#000080"/>
<circle cx="243.7" cy="79.5" r=".51" fill="none" stroke="#000080" stroke-width=".21"/>
<path d="M258.9 79.5h5.1" fill="none" stroke="#000080" stroke-width=".25"/>
<circle cx="264" cy="79.5" r=".51" fill="#000080"/>
<circle cx="264" cy="79.5" r=".51" fill="none" stroke="#000080" stroke-width=".21"/>
<path d="M266.6 76.9v2.6h-2.6" fill="none" stroke="#000080" stroke-width=".25"/>
<circle cx="264" cy="79.5" r=".51" fill="#000080"/>
<circle cx="264" cy="79.5" r=".51" fill="none" stroke="#000080" stroke-width=".21"/>
<use href="#words"/>
</svg>
